VERSION 5.8 ;
BUSBITCHARS "[]" ;
DIVIDERCHAR "/" ;
UNITS
    DATABASE MICRONS 1000 ;
END UNITS

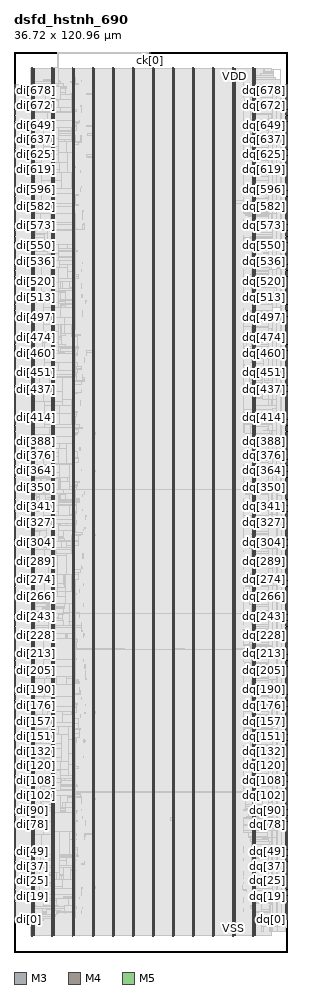
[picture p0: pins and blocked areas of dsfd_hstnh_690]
MACRO dsfd_hstnh_690
  FOREIGN dsfd_hstnh_690 0 0 ;
  CLASS BLOCK ;
  SIZE 36.72 BY 120.96 ;
  PIN ck[0]
    DIRECTION INPUT ;
    USE SIGNAL ;
    PORT
      LAYER M3 ;
        RECT  18.36 120.816 18.378 120.96 ;
    END
    PORT
      LAYER M3 ;
        RECT  18.18 120.793 18.378 120.828 ;
    END
  END ck[0]
  PIN di[0]
    DIRECTION INPUT ;
    USE SIGNAL ;
    PORT
      LAYER M4 ;
        RECT  0 4.416 0.192 4.44 ;
    END
  END di[0]
  PIN di[100]
    DIRECTION INPUT ;
    USE SIGNAL ;
    PORT
      LAYER M4 ;
        RECT  0 20.688 0.192 20.712 ;
    END
  END di[100]
  PIN di[101]
    DIRECTION INPUT ;
    USE SIGNAL ;
    PORT
      LAYER M4 ;
        RECT  0 20.832 0.192 20.856 ;
    END
  END di[101]
  PIN di[102]
    DIRECTION INPUT ;
    USE SIGNAL ;
    PORT
      LAYER M4 ;
        RECT  0 21.024 0.192 21.048 ;
    END
  END di[102]
  PIN di[103]
    DIRECTION INPUT ;
    USE SIGNAL ;
    PORT
      LAYER M4 ;
        RECT  0 21.168 0.192 21.192 ;
    END
  END di[103]
  PIN di[104]
    DIRECTION INPUT ;
    USE SIGNAL ;
    PORT
      LAYER M4 ;
        RECT  0 21.36 0.192 21.384 ;
    END
  END di[104]
  PIN di[105]
    DIRECTION INPUT ;
    USE SIGNAL ;
    PORT
      LAYER M4 ;
        RECT  0 21.504 0.192 21.528 ;
    END
  END di[105]
  PIN di[106]
    DIRECTION INPUT ;
    USE SIGNAL ;
    PORT
      LAYER M4 ;
        RECT  0 21.648 0.192 21.672 ;
    END
  END di[106]
  PIN di[107]
    DIRECTION INPUT ;
    USE SIGNAL ;
    PORT
      LAYER M4 ;
        RECT  0 21.84 0.192 21.864 ;
    END
  END di[107]
  PIN di[108]
    DIRECTION INPUT ;
    USE SIGNAL ;
    PORT
      LAYER M4 ;
        RECT  0 21.984 0.192 22.008 ;
    END
  END di[108]
  PIN di[109]
    DIRECTION INPUT ;
    USE SIGNAL ;
    PORT
      LAYER M4 ;
        RECT  0 22.176 0.192 22.2 ;
    END
  END di[109]
  PIN di[10]
    DIRECTION INPUT ;
    USE SIGNAL ;
    PORT
      LAYER M4 ;
        RECT  0 6.048 0.192 6.072 ;
    END
  END di[10]
  PIN di[110]
    DIRECTION INPUT ;
    USE SIGNAL ;
    PORT
      LAYER M4 ;
        RECT  0 22.32 0.192 22.344 ;
    END
  END di[110]
  PIN di[111]
    DIRECTION INPUT ;
    USE SIGNAL ;
    PORT
      LAYER M4 ;
        RECT  0 22.464 0.192 22.488 ;
    END
  END di[111]
  PIN di[112]
    DIRECTION INPUT ;
    USE SIGNAL ;
    PORT
      LAYER M4 ;
        RECT  0 22.656 0.192 22.68 ;
    END
  END di[112]
  PIN di[113]
    DIRECTION INPUT ;
    USE SIGNAL ;
    PORT
      LAYER M4 ;
        RECT  0 22.8 0.192 22.824 ;
    END
  END di[113]
  PIN di[114]
    DIRECTION INPUT ;
    USE SIGNAL ;
    PORT
      LAYER M4 ;
        RECT  0 22.992 0.192 23.016 ;
    END
  END di[114]
  PIN di[115]
    DIRECTION INPUT ;
    USE SIGNAL ;
    PORT
      LAYER M4 ;
        RECT  0 23.136 0.192 23.16 ;
    END
  END di[115]
  PIN di[116]
    DIRECTION INPUT ;
    USE SIGNAL ;
    PORT
      LAYER M4 ;
        RECT  0 23.28 0.192 23.304 ;
    END
  END di[116]
  PIN di[117]
    DIRECTION INPUT ;
    USE SIGNAL ;
    PORT
      LAYER M4 ;
        RECT  0 23.472 0.192 23.496 ;
    END
  END di[117]
  PIN di[118]
    DIRECTION INPUT ;
    USE SIGNAL ;
    PORT
      LAYER M4 ;
        RECT  0 23.616 0.192 23.64 ;
    END
  END di[118]
  PIN di[119]
    DIRECTION INPUT ;
    USE SIGNAL ;
    PORT
      LAYER M4 ;
        RECT  0 23.808 0.192 23.832 ;
    END
  END di[119]
  PIN di[11]
    DIRECTION INPUT ;
    USE SIGNAL ;
    PORT
      LAYER M4 ;
        RECT  0 6.192 0.192 6.216 ;
    END
  END di[11]
  PIN di[120]
    DIRECTION INPUT ;
    USE SIGNAL ;
    PORT
      LAYER M4 ;
        RECT  0 23.952 0.192 23.976 ;
    END
  END di[120]
  PIN di[121]
    DIRECTION INPUT ;
    USE SIGNAL ;
    PORT
      LAYER M4 ;
        RECT  0 24.096 0.192 24.12 ;
    END
  END di[121]
  PIN di[122]
    DIRECTION INPUT ;
    USE SIGNAL ;
    PORT
      LAYER M4 ;
        RECT  0 24.288 0.192 24.312 ;
    END
  END di[122]
  PIN di[123]
    DIRECTION INPUT ;
    USE SIGNAL ;
    PORT
      LAYER M4 ;
        RECT  0 24.432 0.192 24.456 ;
    END
  END di[123]
  PIN di[124]
    DIRECTION INPUT ;
    USE SIGNAL ;
    PORT
      LAYER M4 ;
        RECT  0 24.576 0.192 24.6 ;
    END
  END di[124]
  PIN di[125]
    DIRECTION INPUT ;
    USE SIGNAL ;
    PORT
      LAYER M4 ;
        RECT  0 24.768 0.192 24.792 ;
    END
  END di[125]
  PIN di[126]
    DIRECTION INPUT ;
    USE SIGNAL ;
    PORT
      LAYER M4 ;
        RECT  0 24.912 0.192 24.936 ;
    END
  END di[126]
  PIN di[127]
    DIRECTION INPUT ;
    USE SIGNAL ;
    PORT
      LAYER M4 ;
        RECT  0 25.104 0.192 25.128 ;
    END
  END di[127]
  PIN di[128]
    DIRECTION INPUT ;
    USE SIGNAL ;
    PORT
      LAYER M4 ;
        RECT  0 25.248 0.192 25.272 ;
    END
  END di[128]
  PIN di[129]
    DIRECTION INPUT ;
    USE SIGNAL ;
    PORT
      LAYER M4 ;
        RECT  0 25.392 0.192 25.416 ;
    END
  END di[129]
  PIN di[12]
    DIRECTION INPUT ;
    USE SIGNAL ;
    PORT
      LAYER M4 ;
        RECT  0 6.384 0.192 6.408 ;
    END
  END di[12]
  PIN di[130]
    DIRECTION INPUT ;
    USE SIGNAL ;
    PORT
      LAYER M4 ;
        RECT  0 25.584 0.192 25.608 ;
    END
  END di[130]
  PIN di[131]
    DIRECTION INPUT ;
    USE SIGNAL ;
    PORT
      LAYER M4 ;
        RECT  0 25.728 0.192 25.752 ;
    END
  END di[131]
  PIN di[132]
    DIRECTION INPUT ;
    USE SIGNAL ;
    PORT
      LAYER M4 ;
        RECT  0 25.92 0.192 25.944 ;
    END
  END di[132]
  PIN di[133]
    DIRECTION INPUT ;
    USE SIGNAL ;
    PORT
      LAYER M4 ;
        RECT  0 26.064 0.192 26.088 ;
    END
  END di[133]
  PIN di[134]
    DIRECTION INPUT ;
    USE SIGNAL ;
    PORT
      LAYER M4 ;
        RECT  0 26.208 0.192 26.232 ;
    END
  END di[134]
  PIN di[135]
    DIRECTION INPUT ;
    USE SIGNAL ;
    PORT
      LAYER M4 ;
        RECT  0 26.4 0.192 26.424 ;
    END
  END di[135]
  PIN di[136]
    DIRECTION INPUT ;
    USE SIGNAL ;
    PORT
      LAYER M4 ;
        RECT  0 26.544 0.192 26.568 ;
    END
  END di[136]
  PIN di[137]
    DIRECTION INPUT ;
    USE SIGNAL ;
    PORT
      LAYER M4 ;
        RECT  0 26.736 0.192 26.76 ;
    END
  END di[137]
  PIN di[138]
    DIRECTION INPUT ;
    USE SIGNAL ;
    PORT
      LAYER M4 ;
        RECT  0 26.88 0.192 26.904 ;
    END
  END di[138]
  PIN di[139]
    DIRECTION INPUT ;
    USE SIGNAL ;
    PORT
      LAYER M4 ;
        RECT  0 27.024 0.192 27.048 ;
    END
  END di[139]
  PIN di[13]
    DIRECTION INPUT ;
    USE SIGNAL ;
    PORT
      LAYER M4 ;
        RECT  0 6.528 0.192 6.552 ;
    END
  END di[13]
  PIN di[140]
    DIRECTION INPUT ;
    USE SIGNAL ;
    PORT
      LAYER M4 ;
        RECT  0 27.216 0.192 27.24 ;
    END
  END di[140]
  PIN di[141]
    DIRECTION INPUT ;
    USE SIGNAL ;
    PORT
      LAYER M4 ;
        RECT  0 27.36 0.192 27.384 ;
    END
  END di[141]
  PIN di[142]
    DIRECTION INPUT ;
    USE SIGNAL ;
    PORT
      LAYER M4 ;
        RECT  0 27.552 0.192 27.576 ;
    END
  END di[142]
  PIN di[143]
    DIRECTION INPUT ;
    USE SIGNAL ;
    PORT
      LAYER M4 ;
        RECT  0 27.696 0.192 27.72 ;
    END
  END di[143]
  PIN di[144]
    DIRECTION INPUT ;
    USE SIGNAL ;
    PORT
      LAYER M4 ;
        RECT  0 27.84 0.192 27.864 ;
    END
  END di[144]
  PIN di[145]
    DIRECTION INPUT ;
    USE SIGNAL ;
    PORT
      LAYER M4 ;
        RECT  0 28.032 0.192 28.056 ;
    END
  END di[145]
  PIN di[146]
    DIRECTION INPUT ;
    USE SIGNAL ;
    PORT
      LAYER M4 ;
        RECT  0 28.176 0.192 28.2 ;
    END
  END di[146]
  PIN di[147]
    DIRECTION INPUT ;
    USE SIGNAL ;
    PORT
      LAYER M4 ;
        RECT  0 28.32 0.192 28.344 ;
    END
  END di[147]
  PIN di[148]
    DIRECTION INPUT ;
    USE SIGNAL ;
    PORT
      LAYER M4 ;
        RECT  0 28.512 0.192 28.536 ;
    END
  END di[148]
  PIN di[149]
    DIRECTION INPUT ;
    USE SIGNAL ;
    PORT
      LAYER M4 ;
        RECT  0 28.656 0.192 28.68 ;
    END
  END di[149]
  PIN di[14]
    DIRECTION INPUT ;
    USE SIGNAL ;
    PORT
      LAYER M4 ;
        RECT  0 6.672 0.192 6.696 ;
    END
  END di[14]
  PIN di[150]
    DIRECTION INPUT ;
    USE SIGNAL ;
    PORT
      LAYER M4 ;
        RECT  0 28.848 0.192 28.872 ;
    END
  END di[150]
  PIN di[151]
    DIRECTION INPUT ;
    USE SIGNAL ;
    PORT
      LAYER M4 ;
        RECT  0 28.992 0.192 29.016 ;
    END
  END di[151]
  PIN di[152]
    DIRECTION INPUT ;
    USE SIGNAL ;
    PORT
      LAYER M4 ;
        RECT  0 29.136 0.192 29.16 ;
    END
  END di[152]
  PIN di[153]
    DIRECTION INPUT ;
    USE SIGNAL ;
    PORT
      LAYER M4 ;
        RECT  0 29.328 0.192 29.352 ;
    END
  END di[153]
  PIN di[154]
    DIRECTION INPUT ;
    USE SIGNAL ;
    PORT
      LAYER M4 ;
        RECT  0 29.472 0.192 29.496 ;
    END
  END di[154]
  PIN di[155]
    DIRECTION INPUT ;
    USE SIGNAL ;
    PORT
      LAYER M4 ;
        RECT  0 29.664 0.192 29.688 ;
    END
  END di[155]
  PIN di[156]
    DIRECTION INPUT ;
    USE SIGNAL ;
    PORT
      LAYER M4 ;
        RECT  0 29.808 0.192 29.832 ;
    END
  END di[156]
  PIN di[157]
    DIRECTION INPUT ;
    USE SIGNAL ;
    PORT
      LAYER M4 ;
        RECT  0 29.952 0.192 29.976 ;
    END
  END di[157]
  PIN di[158]
    DIRECTION INPUT ;
    USE SIGNAL ;
    PORT
      LAYER M4 ;
        RECT  0 30.144 0.192 30.168 ;
    END
  END di[158]
  PIN di[159]
    DIRECTION INPUT ;
    USE SIGNAL ;
    PORT
      LAYER M4 ;
        RECT  0 30.288 0.192 30.312 ;
    END
  END di[159]
  PIN di[15]
    DIRECTION INPUT ;
    USE SIGNAL ;
    PORT
      LAYER M4 ;
        RECT  0 6.864 0.192 6.888 ;
    END
  END di[15]
  PIN di[160]
    DIRECTION INPUT ;
    USE SIGNAL ;
    PORT
      LAYER M4 ;
        RECT  0 30.48 0.192 30.504 ;
    END
  END di[160]
  PIN di[161]
    DIRECTION INPUT ;
    USE SIGNAL ;
    PORT
      LAYER M4 ;
        RECT  0 30.624 0.192 30.648 ;
    END
  END di[161]
  PIN di[162]
    DIRECTION INPUT ;
    USE SIGNAL ;
    PORT
      LAYER M4 ;
        RECT  0 30.768 0.192 30.792 ;
    END
  END di[162]
  PIN di[163]
    DIRECTION INPUT ;
    USE SIGNAL ;
    PORT
      LAYER M4 ;
        RECT  0 30.96 0.192 30.984 ;
    END
  END di[163]
  PIN di[164]
    DIRECTION INPUT ;
    USE SIGNAL ;
    PORT
      LAYER M4 ;
        RECT  0 31.104 0.192 31.128 ;
    END
  END di[164]
  PIN di[165]
    DIRECTION INPUT ;
    USE SIGNAL ;
    PORT
      LAYER M4 ;
        RECT  0 31.296 0.192 31.32 ;
    END
  END di[165]
  PIN di[166]
    DIRECTION INPUT ;
    USE SIGNAL ;
    PORT
      LAYER M4 ;
        RECT  0 31.44 0.192 31.464 ;
    END
  END di[166]
  PIN di[167]
    DIRECTION INPUT ;
    USE SIGNAL ;
    PORT
      LAYER M4 ;
        RECT  0 31.584 0.192 31.608 ;
    END
  END di[167]
  PIN di[168]
    DIRECTION INPUT ;
    USE SIGNAL ;
    PORT
      LAYER M4 ;
        RECT  0 31.776 0.192 31.8 ;
    END
  END di[168]
  PIN di[169]
    DIRECTION INPUT ;
    USE SIGNAL ;
    PORT
      LAYER M4 ;
        RECT  0 31.92 0.192 31.944 ;
    END
  END di[169]
  PIN di[16]
    DIRECTION INPUT ;
    USE SIGNAL ;
    PORT
      LAYER M4 ;
        RECT  0 7.008 0.192 7.032 ;
    END
  END di[16]
  PIN di[170]
    DIRECTION INPUT ;
    USE SIGNAL ;
    PORT
      LAYER M4 ;
        RECT  0 32.064 0.192 32.088 ;
    END
  END di[170]
  PIN di[171]
    DIRECTION INPUT ;
    USE SIGNAL ;
    PORT
      LAYER M4 ;
        RECT  0 32.256 0.192 32.28 ;
    END
  END di[171]
  PIN di[172]
    DIRECTION INPUT ;
    USE SIGNAL ;
    PORT
      LAYER M4 ;
        RECT  0 32.4 0.192 32.424 ;
    END
  END di[172]
  PIN di[173]
    DIRECTION INPUT ;
    USE SIGNAL ;
    PORT
      LAYER M4 ;
        RECT  0 32.592 0.192 32.616 ;
    END
  END di[173]
  PIN di[174]
    DIRECTION INPUT ;
    USE SIGNAL ;
    PORT
      LAYER M4 ;
        RECT  0 32.736 0.192 32.76 ;
    END
  END di[174]
  PIN di[175]
    DIRECTION INPUT ;
    USE SIGNAL ;
    PORT
      LAYER M4 ;
        RECT  0 32.88 0.192 32.904 ;
    END
  END di[175]
  PIN di[176]
    DIRECTION INPUT ;
    USE SIGNAL ;
    PORT
      LAYER M4 ;
        RECT  0 33.072 0.192 33.096 ;
    END
  END di[176]
  PIN di[177]
    DIRECTION INPUT ;
    USE SIGNAL ;
    PORT
      LAYER M4 ;
        RECT  0 33.216 0.192 33.24 ;
    END
  END di[177]
  PIN di[178]
    DIRECTION INPUT ;
    USE SIGNAL ;
    PORT
      LAYER M4 ;
        RECT  0 33.408 0.192 33.432 ;
    END
  END di[178]
  PIN di[179]
    DIRECTION INPUT ;
    USE SIGNAL ;
    PORT
      LAYER M4 ;
        RECT  0 33.552 0.192 33.576 ;
    END
  END di[179]
  PIN di[17]
    DIRECTION INPUT ;
    USE SIGNAL ;
    PORT
      LAYER M4 ;
        RECT  0 7.2 0.192 7.224 ;
    END
  END di[17]
  PIN di[180]
    DIRECTION INPUT ;
    USE SIGNAL ;
    PORT
      LAYER M4 ;
        RECT  0 33.696 0.192 33.72 ;
    END
  END di[180]
  PIN di[181]
    DIRECTION INPUT ;
    USE SIGNAL ;
    PORT
      LAYER M4 ;
        RECT  0 33.888 0.192 33.912 ;
    END
  END di[181]
  PIN di[182]
    DIRECTION INPUT ;
    USE SIGNAL ;
    PORT
      LAYER M4 ;
        RECT  0 34.032 0.192 34.056 ;
    END
  END di[182]
  PIN di[183]
    DIRECTION INPUT ;
    USE SIGNAL ;
    PORT
      LAYER M4 ;
        RECT  0 34.224 0.192 34.248 ;
    END
  END di[183]
  PIN di[184]
    DIRECTION INPUT ;
    USE SIGNAL ;
    PORT
      LAYER M4 ;
        RECT  0 34.368 0.192 34.392 ;
    END
  END di[184]
  PIN di[185]
    DIRECTION INPUT ;
    USE SIGNAL ;
    PORT
      LAYER M4 ;
        RECT  0 34.512 0.192 34.536 ;
    END
  END di[185]
  PIN di[186]
    DIRECTION INPUT ;
    USE SIGNAL ;
    PORT
      LAYER M4 ;
        RECT  0 34.704 0.192 34.728 ;
    END
  END di[186]
  PIN di[187]
    DIRECTION INPUT ;
    USE SIGNAL ;
    PORT
      LAYER M4 ;
        RECT  0 34.848 0.192 34.872 ;
    END
  END di[187]
  PIN di[188]
    DIRECTION INPUT ;
    USE SIGNAL ;
    PORT
      LAYER M4 ;
        RECT  0 35.04 0.192 35.064 ;
    END
  END di[188]
  PIN di[189]
    DIRECTION INPUT ;
    USE SIGNAL ;
    PORT
      LAYER M4 ;
        RECT  0 35.184 0.192 35.208 ;
    END
  END di[189]
  PIN di[18]
    DIRECTION INPUT ;
    USE SIGNAL ;
    PORT
      LAYER M4 ;
        RECT  0 7.344 0.192 7.368 ;
    END
  END di[18]
  PIN di[190]
    DIRECTION INPUT ;
    USE SIGNAL ;
    PORT
      LAYER M4 ;
        RECT  0 35.328 0.192 35.352 ;
    END
  END di[190]
  PIN di[191]
    DIRECTION INPUT ;
    USE SIGNAL ;
    PORT
      LAYER M4 ;
        RECT  0 35.52 0.192 35.544 ;
    END
  END di[191]
  PIN di[192]
    DIRECTION INPUT ;
    USE SIGNAL ;
    PORT
      LAYER M4 ;
        RECT  0 35.664 0.192 35.688 ;
    END
  END di[192]
  PIN di[193]
    DIRECTION INPUT ;
    USE SIGNAL ;
    PORT
      LAYER M4 ;
        RECT  0 35.808 0.192 35.832 ;
    END
  END di[193]
  PIN di[194]
    DIRECTION INPUT ;
    USE SIGNAL ;
    PORT
      LAYER M4 ;
        RECT  0 36 0.192 36.024 ;
    END
  END di[194]
  PIN di[195]
    DIRECTION INPUT ;
    USE SIGNAL ;
    PORT
      LAYER M4 ;
        RECT  0 36.144 0.192 36.168 ;
    END
  END di[195]
  PIN di[196]
    DIRECTION INPUT ;
    USE SIGNAL ;
    PORT
      LAYER M4 ;
        RECT  0 36.336 0.192 36.36 ;
    END
  END di[196]
  PIN di[197]
    DIRECTION INPUT ;
    USE SIGNAL ;
    PORT
      LAYER M4 ;
        RECT  0 36.48 0.192 36.504 ;
    END
  END di[197]
  PIN di[198]
    DIRECTION INPUT ;
    USE SIGNAL ;
    PORT
      LAYER M4 ;
        RECT  0 36.624 0.192 36.648 ;
    END
  END di[198]
  PIN di[199]
    DIRECTION INPUT ;
    USE SIGNAL ;
    PORT
      LAYER M4 ;
        RECT  0 36.816 0.192 36.84 ;
    END
  END di[199]
  PIN di[19]
    DIRECTION INPUT ;
    USE SIGNAL ;
    PORT
      LAYER M4 ;
        RECT  0 7.488 0.192 7.512 ;
    END
  END di[19]
  PIN di[1]
    DIRECTION INPUT ;
    USE SIGNAL ;
    PORT
      LAYER M4 ;
        RECT  0 4.56 0.192 4.584 ;
    END
  END di[1]
  PIN di[200]
    DIRECTION INPUT ;
    USE SIGNAL ;
    PORT
      LAYER M4 ;
        RECT  0 36.96 0.192 36.984 ;
    END
  END di[200]
  PIN di[201]
    DIRECTION INPUT ;
    USE SIGNAL ;
    PORT
      LAYER M4 ;
        RECT  0 37.152 0.192 37.176 ;
    END
  END di[201]
  PIN di[202]
    DIRECTION INPUT ;
    USE SIGNAL ;
    PORT
      LAYER M4 ;
        RECT  0 37.296 0.192 37.32 ;
    END
  END di[202]
  PIN di[203]
    DIRECTION INPUT ;
    USE SIGNAL ;
    PORT
      LAYER M4 ;
        RECT  0 37.44 0.192 37.464 ;
    END
  END di[203]
  PIN di[204]
    DIRECTION INPUT ;
    USE SIGNAL ;
    PORT
      LAYER M4 ;
        RECT  0 37.632 0.192 37.656 ;
    END
  END di[204]
  PIN di[205]
    DIRECTION INPUT ;
    USE SIGNAL ;
    PORT
      LAYER M4 ;
        RECT  0 37.776 0.192 37.8 ;
    END
  END di[205]
  PIN di[206]
    DIRECTION INPUT ;
    USE SIGNAL ;
    PORT
      LAYER M4 ;
        RECT  0 37.968 0.192 37.992 ;
    END
  END di[206]
  PIN di[207]
    DIRECTION INPUT ;
    USE SIGNAL ;
    PORT
      LAYER M4 ;
        RECT  0 38.112 0.192 38.136 ;
    END
  END di[207]
  PIN di[208]
    DIRECTION INPUT ;
    USE SIGNAL ;
    PORT
      LAYER M4 ;
        RECT  0 38.256 0.192 38.28 ;
    END
  END di[208]
  PIN di[209]
    DIRECTION INPUT ;
    USE SIGNAL ;
    PORT
      LAYER M4 ;
        RECT  0 38.448 0.192 38.472 ;
    END
  END di[209]
  PIN di[20]
    DIRECTION INPUT ;
    USE SIGNAL ;
    PORT
      LAYER M4 ;
        RECT  0 7.68 0.192 7.704 ;
    END
  END di[20]
  PIN di[210]
    DIRECTION INPUT ;
    USE SIGNAL ;
    PORT
      LAYER M4 ;
        RECT  0 38.592 0.192 38.616 ;
    END
  END di[210]
  PIN di[211]
    DIRECTION INPUT ;
    USE SIGNAL ;
    PORT
      LAYER M4 ;
        RECT  0 38.784 0.192 38.808 ;
    END
  END di[211]
  PIN di[212]
    DIRECTION INPUT ;
    USE SIGNAL ;
    PORT
      LAYER M4 ;
        RECT  0 38.928 0.192 38.952 ;
    END
  END di[212]
  PIN di[213]
    DIRECTION INPUT ;
    USE SIGNAL ;
    PORT
      LAYER M4 ;
        RECT  0 39.072 0.192 39.096 ;
    END
  END di[213]
  PIN di[214]
    DIRECTION INPUT ;
    USE SIGNAL ;
    PORT
      LAYER M4 ;
        RECT  0 39.264 0.192 39.288 ;
    END
  END di[214]
  PIN di[215]
    DIRECTION INPUT ;
    USE SIGNAL ;
    PORT
      LAYER M4 ;
        RECT  0 39.408 0.192 39.432 ;
    END
  END di[215]
  PIN di[216]
    DIRECTION INPUT ;
    USE SIGNAL ;
    PORT
      LAYER M4 ;
        RECT  0 39.552 0.192 39.576 ;
    END
  END di[216]
  PIN di[217]
    DIRECTION INPUT ;
    USE SIGNAL ;
    PORT
      LAYER M4 ;
        RECT  0 39.744 0.192 39.768 ;
    END
  END di[217]
  PIN di[218]
    DIRECTION INPUT ;
    USE SIGNAL ;
    PORT
      LAYER M4 ;
        RECT  0 39.888 0.192 39.912 ;
    END
  END di[218]
  PIN di[219]
    DIRECTION INPUT ;
    USE SIGNAL ;
    PORT
      LAYER M4 ;
        RECT  0 40.08 0.192 40.104 ;
    END
  END di[219]
  PIN di[21]
    DIRECTION INPUT ;
    USE SIGNAL ;
    PORT
      LAYER M4 ;
        RECT  0 7.824 0.192 7.848 ;
    END
  END di[21]
  PIN di[220]
    DIRECTION INPUT ;
    USE SIGNAL ;
    PORT
      LAYER M4 ;
        RECT  0 40.224 0.192 40.248 ;
    END
  END di[220]
  PIN di[221]
    DIRECTION INPUT ;
    USE SIGNAL ;
    PORT
      LAYER M4 ;
        RECT  0 40.368 0.192 40.392 ;
    END
  END di[221]
  PIN di[222]
    DIRECTION INPUT ;
    USE SIGNAL ;
    PORT
      LAYER M4 ;
        RECT  0 40.56 0.192 40.584 ;
    END
  END di[222]
  PIN di[223]
    DIRECTION INPUT ;
    USE SIGNAL ;
    PORT
      LAYER M4 ;
        RECT  0 40.704 0.192 40.728 ;
    END
  END di[223]
  PIN di[224]
    DIRECTION INPUT ;
    USE SIGNAL ;
    PORT
      LAYER M4 ;
        RECT  0 40.896 0.192 40.92 ;
    END
  END di[224]
  PIN di[225]
    DIRECTION INPUT ;
    USE SIGNAL ;
    PORT
      LAYER M4 ;
        RECT  0 41.04 0.192 41.064 ;
    END
  END di[225]
  PIN di[226]
    DIRECTION INPUT ;
    USE SIGNAL ;
    PORT
      LAYER M4 ;
        RECT  0 41.184 0.192 41.208 ;
    END
  END di[226]
  PIN di[227]
    DIRECTION INPUT ;
    USE SIGNAL ;
    PORT
      LAYER M4 ;
        RECT  0 41.376 0.192 41.4 ;
    END
  END di[227]
  PIN di[228]
    DIRECTION INPUT ;
    USE SIGNAL ;
    PORT
      LAYER M4 ;
        RECT  0 41.52 0.192 41.544 ;
    END
  END di[228]
  PIN di[229]
    DIRECTION INPUT ;
    USE SIGNAL ;
    PORT
      LAYER M4 ;
        RECT  0 41.712 0.192 41.736 ;
    END
  END di[229]
  PIN di[22]
    DIRECTION INPUT ;
    USE SIGNAL ;
    PORT
      LAYER M4 ;
        RECT  0 8.016 0.192 8.04 ;
    END
  END di[22]
  PIN di[230]
    DIRECTION INPUT ;
    USE SIGNAL ;
    PORT
      LAYER M4 ;
        RECT  0 41.856 0.192 41.88 ;
    END
  END di[230]
  PIN di[231]
    DIRECTION INPUT ;
    USE SIGNAL ;
    PORT
      LAYER M4 ;
        RECT  0 42 0.192 42.024 ;
    END
  END di[231]
  PIN di[232]
    DIRECTION INPUT ;
    USE SIGNAL ;
    PORT
      LAYER M4 ;
        RECT  0 42.192 0.192 42.216 ;
    END
  END di[232]
  PIN di[233]
    DIRECTION INPUT ;
    USE SIGNAL ;
    PORT
      LAYER M4 ;
        RECT  0 42.336 0.192 42.36 ;
    END
  END di[233]
  PIN di[234]
    DIRECTION INPUT ;
    USE SIGNAL ;
    PORT
      LAYER M4 ;
        RECT  0 42.528 0.192 42.552 ;
    END
  END di[234]
  PIN di[235]
    DIRECTION INPUT ;
    USE SIGNAL ;
    PORT
      LAYER M4 ;
        RECT  0 42.672 0.192 42.696 ;
    END
  END di[235]
  PIN di[236]
    DIRECTION INPUT ;
    USE SIGNAL ;
    PORT
      LAYER M4 ;
        RECT  0 42.816 0.192 42.84 ;
    END
  END di[236]
  PIN di[237]
    DIRECTION INPUT ;
    USE SIGNAL ;
    PORT
      LAYER M4 ;
        RECT  0 43.008 0.192 43.032 ;
    END
  END di[237]
  PIN di[238]
    DIRECTION INPUT ;
    USE SIGNAL ;
    PORT
      LAYER M4 ;
        RECT  0 43.152 0.192 43.176 ;
    END
  END di[238]
  PIN di[239]
    DIRECTION INPUT ;
    USE SIGNAL ;
    PORT
      LAYER M4 ;
        RECT  0 43.296 0.192 43.32 ;
    END
  END di[239]
  PIN di[23]
    DIRECTION INPUT ;
    USE SIGNAL ;
    PORT
      LAYER M4 ;
        RECT  0 8.16 0.192 8.184 ;
    END
  END di[23]
  PIN di[240]
    DIRECTION INPUT ;
    USE SIGNAL ;
    PORT
      LAYER M4 ;
        RECT  0 43.488 0.192 43.512 ;
    END
  END di[240]
  PIN di[241]
    DIRECTION INPUT ;
    USE SIGNAL ;
    PORT
      LAYER M4 ;
        RECT  0 43.632 0.192 43.656 ;
    END
  END di[241]
  PIN di[242]
    DIRECTION INPUT ;
    USE SIGNAL ;
    PORT
      LAYER M4 ;
        RECT  0 43.824 0.192 43.848 ;
    END
  END di[242]
  PIN di[243]
    DIRECTION INPUT ;
    USE SIGNAL ;
    PORT
      LAYER M4 ;
        RECT  0 43.968 0.192 43.992 ;
    END
  END di[243]
  PIN di[244]
    DIRECTION INPUT ;
    USE SIGNAL ;
    PORT
      LAYER M4 ;
        RECT  0 44.112 0.192 44.136 ;
    END
  END di[244]
  PIN di[245]
    DIRECTION INPUT ;
    USE SIGNAL ;
    PORT
      LAYER M4 ;
        RECT  0 44.304 0.192 44.328 ;
    END
  END di[245]
  PIN di[246]
    DIRECTION INPUT ;
    USE SIGNAL ;
    PORT
      LAYER M4 ;
        RECT  0 44.448 0.192 44.472 ;
    END
  END di[246]
  PIN di[247]
    DIRECTION INPUT ;
    USE SIGNAL ;
    PORT
      LAYER M4 ;
        RECT  0 44.64 0.192 44.664 ;
    END
  END di[247]
  PIN di[248]
    DIRECTION INPUT ;
    USE SIGNAL ;
    PORT
      LAYER M4 ;
        RECT  0 44.784 0.192 44.808 ;
    END
  END di[248]
  PIN di[249]
    DIRECTION INPUT ;
    USE SIGNAL ;
    PORT
      LAYER M4 ;
        RECT  0 44.928 0.192 44.952 ;
    END
  END di[249]
  PIN di[24]
    DIRECTION INPUT ;
    USE SIGNAL ;
    PORT
      LAYER M4 ;
        RECT  0 8.304 0.192 8.328 ;
    END
  END di[24]
  PIN di[250]
    DIRECTION INPUT ;
    USE SIGNAL ;
    PORT
      LAYER M4 ;
        RECT  0 45.12 0.192 45.144 ;
    END
  END di[250]
  PIN di[251]
    DIRECTION INPUT ;
    USE SIGNAL ;
    PORT
      LAYER M4 ;
        RECT  0 45.264 0.192 45.288 ;
    END
  END di[251]
  PIN di[252]
    DIRECTION INPUT ;
    USE SIGNAL ;
    PORT
      LAYER M4 ;
        RECT  0 45.456 0.192 45.48 ;
    END
  END di[252]
  PIN di[253]
    DIRECTION INPUT ;
    USE SIGNAL ;
    PORT
      LAYER M4 ;
        RECT  0 45.6 0.192 45.624 ;
    END
  END di[253]
  PIN di[254]
    DIRECTION INPUT ;
    USE SIGNAL ;
    PORT
      LAYER M4 ;
        RECT  0 45.744 0.192 45.768 ;
    END
  END di[254]
  PIN di[255]
    DIRECTION INPUT ;
    USE SIGNAL ;
    PORT
      LAYER M4 ;
        RECT  0 45.936 0.192 45.96 ;
    END
  END di[255]
  PIN di[256]
    DIRECTION INPUT ;
    USE SIGNAL ;
    PORT
      LAYER M4 ;
        RECT  0 46.08 0.192 46.104 ;
    END
  END di[256]
  PIN di[257]
    DIRECTION INPUT ;
    USE SIGNAL ;
    PORT
      LAYER M4 ;
        RECT  0 46.272 0.192 46.296 ;
    END
  END di[257]
  PIN di[258]
    DIRECTION INPUT ;
    USE SIGNAL ;
    PORT
      LAYER M4 ;
        RECT  0 46.416 0.192 46.44 ;
    END
  END di[258]
  PIN di[259]
    DIRECTION INPUT ;
    USE SIGNAL ;
    PORT
      LAYER M4 ;
        RECT  0 46.56 0.192 46.584 ;
    END
  END di[259]
  PIN di[25]
    DIRECTION INPUT ;
    USE SIGNAL ;
    PORT
      LAYER M4 ;
        RECT  0 8.496 0.192 8.52 ;
    END
  END di[25]
  PIN di[260]
    DIRECTION INPUT ;
    USE SIGNAL ;
    PORT
      LAYER M4 ;
        RECT  0 46.752 0.192 46.776 ;
    END
  END di[260]
  PIN di[261]
    DIRECTION INPUT ;
    USE SIGNAL ;
    PORT
      LAYER M4 ;
        RECT  0 46.896 0.192 46.92 ;
    END
  END di[261]
  PIN di[262]
    DIRECTION INPUT ;
    USE SIGNAL ;
    PORT
      LAYER M4 ;
        RECT  0 47.04 0.192 47.064 ;
    END
  END di[262]
  PIN di[263]
    DIRECTION INPUT ;
    USE SIGNAL ;
    PORT
      LAYER M4 ;
        RECT  0 47.232 0.192 47.256 ;
    END
  END di[263]
  PIN di[264]
    DIRECTION INPUT ;
    USE SIGNAL ;
    PORT
      LAYER M4 ;
        RECT  0 47.376 0.192 47.4 ;
    END
  END di[264]
  PIN di[265]
    DIRECTION INPUT ;
    USE SIGNAL ;
    PORT
      LAYER M4 ;
        RECT  0 47.568 0.192 47.592 ;
    END
  END di[265]
  PIN di[266]
    DIRECTION INPUT ;
    USE SIGNAL ;
    PORT
      LAYER M4 ;
        RECT  0 47.712 0.192 47.736 ;
    END
  END di[266]
  PIN di[267]
    DIRECTION INPUT ;
    USE SIGNAL ;
    PORT
      LAYER M4 ;
        RECT  0 47.856 0.192 47.88 ;
    END
  END di[267]
  PIN di[268]
    DIRECTION INPUT ;
    USE SIGNAL ;
    PORT
      LAYER M4 ;
        RECT  0 48.048 0.192 48.072 ;
    END
  END di[268]
  PIN di[269]
    DIRECTION INPUT ;
    USE SIGNAL ;
    PORT
      LAYER M4 ;
        RECT  0 48.192 0.192 48.216 ;
    END
  END di[269]
  PIN di[26]
    DIRECTION INPUT ;
    USE SIGNAL ;
    PORT
      LAYER M4 ;
        RECT  0 8.64 0.192 8.664 ;
    END
  END di[26]
  PIN di[270]
    DIRECTION INPUT ;
    USE SIGNAL ;
    PORT
      LAYER M4 ;
        RECT  0 48.384 0.192 48.408 ;
    END
  END di[270]
  PIN di[271]
    DIRECTION INPUT ;
    USE SIGNAL ;
    PORT
      LAYER M4 ;
        RECT  0 48.528 0.192 48.552 ;
    END
  END di[271]
  PIN di[272]
    DIRECTION INPUT ;
    USE SIGNAL ;
    PORT
      LAYER M4 ;
        RECT  0 48.672 0.192 48.696 ;
    END
  END di[272]
  PIN di[273]
    DIRECTION INPUT ;
    USE SIGNAL ;
    PORT
      LAYER M4 ;
        RECT  0 48.864 0.192 48.888 ;
    END
  END di[273]
  PIN di[274]
    DIRECTION INPUT ;
    USE SIGNAL ;
    PORT
      LAYER M4 ;
        RECT  0 49.008 0.192 49.032 ;
    END
  END di[274]
  PIN di[275]
    DIRECTION INPUT ;
    USE SIGNAL ;
    PORT
      LAYER M4 ;
        RECT  0 49.2 0.192 49.224 ;
    END
  END di[275]
  PIN di[276]
    DIRECTION INPUT ;
    USE SIGNAL ;
    PORT
      LAYER M4 ;
        RECT  0 49.344 0.192 49.368 ;
    END
  END di[276]
  PIN di[277]
    DIRECTION INPUT ;
    USE SIGNAL ;
    PORT
      LAYER M4 ;
        RECT  0 49.488 0.192 49.512 ;
    END
  END di[277]
  PIN di[278]
    DIRECTION INPUT ;
    USE SIGNAL ;
    PORT
      LAYER M4 ;
        RECT  0 49.68 0.192 49.704 ;
    END
  END di[278]
  PIN di[279]
    DIRECTION INPUT ;
    USE SIGNAL ;
    PORT
      LAYER M4 ;
        RECT  0 49.824 0.192 49.848 ;
    END
  END di[279]
  PIN di[27]
    DIRECTION INPUT ;
    USE SIGNAL ;
    PORT
      LAYER M4 ;
        RECT  0 8.832 0.192 8.856 ;
    END
  END di[27]
  PIN di[280]
    DIRECTION INPUT ;
    USE SIGNAL ;
    PORT
      LAYER M4 ;
        RECT  0 50.016 0.192 50.04 ;
    END
  END di[280]
  PIN di[281]
    DIRECTION INPUT ;
    USE SIGNAL ;
    PORT
      LAYER M4 ;
        RECT  0 50.16 0.192 50.184 ;
    END
  END di[281]
  PIN di[282]
    DIRECTION INPUT ;
    USE SIGNAL ;
    PORT
      LAYER M4 ;
        RECT  0 50.304 0.192 50.328 ;
    END
  END di[282]
  PIN di[283]
    DIRECTION INPUT ;
    USE SIGNAL ;
    PORT
      LAYER M4 ;
        RECT  0 50.496 0.192 50.52 ;
    END
  END di[283]
  PIN di[284]
    DIRECTION INPUT ;
    USE SIGNAL ;
    PORT
      LAYER M4 ;
        RECT  0 50.64 0.192 50.664 ;
    END
  END di[284]
  PIN di[285]
    DIRECTION INPUT ;
    USE SIGNAL ;
    PORT
      LAYER M4 ;
        RECT  0 50.784 0.192 50.808 ;
    END
  END di[285]
  PIN di[286]
    DIRECTION INPUT ;
    USE SIGNAL ;
    PORT
      LAYER M4 ;
        RECT  0 50.976 0.192 51 ;
    END
  END di[286]
  PIN di[287]
    DIRECTION INPUT ;
    USE SIGNAL ;
    PORT
      LAYER M4 ;
        RECT  0 51.12 0.192 51.144 ;
    END
  END di[287]
  PIN di[288]
    DIRECTION INPUT ;
    USE SIGNAL ;
    PORT
      LAYER M4 ;
        RECT  0 51.312 0.192 51.336 ;
    END
  END di[288]
  PIN di[289]
    DIRECTION INPUT ;
    USE SIGNAL ;
    PORT
      LAYER M4 ;
        RECT  0 51.456 0.192 51.48 ;
    END
  END di[289]
  PIN di[28]
    DIRECTION INPUT ;
    USE SIGNAL ;
    PORT
      LAYER M4 ;
        RECT  0 8.976 0.192 9 ;
    END
  END di[28]
  PIN di[290]
    DIRECTION INPUT ;
    USE SIGNAL ;
    PORT
      LAYER M4 ;
        RECT  0 51.6 0.192 51.624 ;
    END
  END di[290]
  PIN di[291]
    DIRECTION INPUT ;
    USE SIGNAL ;
    PORT
      LAYER M4 ;
        RECT  0 51.792 0.192 51.816 ;
    END
  END di[291]
  PIN di[292]
    DIRECTION INPUT ;
    USE SIGNAL ;
    PORT
      LAYER M4 ;
        RECT  0 51.936 0.192 51.96 ;
    END
  END di[292]
  PIN di[293]
    DIRECTION INPUT ;
    USE SIGNAL ;
    PORT
      LAYER M4 ;
        RECT  0 52.128 0.192 52.152 ;
    END
  END di[293]
  PIN di[294]
    DIRECTION INPUT ;
    USE SIGNAL ;
    PORT
      LAYER M4 ;
        RECT  0 52.272 0.192 52.296 ;
    END
  END di[294]
  PIN di[295]
    DIRECTION INPUT ;
    USE SIGNAL ;
    PORT
      LAYER M4 ;
        RECT  0 52.416 0.192 52.44 ;
    END
  END di[295]
  PIN di[296]
    DIRECTION INPUT ;
    USE SIGNAL ;
    PORT
      LAYER M4 ;
        RECT  0 52.608 0.192 52.632 ;
    END
  END di[296]
  PIN di[297]
    DIRECTION INPUT ;
    USE SIGNAL ;
    PORT
      LAYER M4 ;
        RECT  0 52.752 0.192 52.776 ;
    END
  END di[297]
  PIN di[298]
    DIRECTION INPUT ;
    USE SIGNAL ;
    PORT
      LAYER M4 ;
        RECT  0 52.944 0.192 52.968 ;
    END
  END di[298]
  PIN di[299]
    DIRECTION INPUT ;
    USE SIGNAL ;
    PORT
      LAYER M4 ;
        RECT  0 53.088 0.192 53.112 ;
    END
  END di[299]
  PIN di[29]
    DIRECTION INPUT ;
    USE SIGNAL ;
    PORT
      LAYER M4 ;
        RECT  0 9.12 0.192 9.144 ;
    END
  END di[29]
  PIN di[2]
    DIRECTION INPUT ;
    USE SIGNAL ;
    PORT
      LAYER M4 ;
        RECT  0 4.752 0.192 4.776 ;
    END
  END di[2]
  PIN di[300]
    DIRECTION INPUT ;
    USE SIGNAL ;
    PORT
      LAYER M4 ;
        RECT  0 53.232 0.192 53.256 ;
    END
  END di[300]
  PIN di[301]
    DIRECTION INPUT ;
    USE SIGNAL ;
    PORT
      LAYER M4 ;
        RECT  0 53.424 0.192 53.448 ;
    END
  END di[301]
  PIN di[302]
    DIRECTION INPUT ;
    USE SIGNAL ;
    PORT
      LAYER M4 ;
        RECT  0 53.568 0.192 53.592 ;
    END
  END di[302]
  PIN di[303]
    DIRECTION INPUT ;
    USE SIGNAL ;
    PORT
      LAYER M4 ;
        RECT  0 53.76 0.192 53.784 ;
    END
  END di[303]
  PIN di[304]
    DIRECTION INPUT ;
    USE SIGNAL ;
    PORT
      LAYER M4 ;
        RECT  0 53.904 0.192 53.928 ;
    END
  END di[304]
  PIN di[305]
    DIRECTION INPUT ;
    USE SIGNAL ;
    PORT
      LAYER M4 ;
        RECT  0 54.048 0.192 54.072 ;
    END
  END di[305]
  PIN di[306]
    DIRECTION INPUT ;
    USE SIGNAL ;
    PORT
      LAYER M4 ;
        RECT  0 54.24 0.192 54.264 ;
    END
  END di[306]
  PIN di[307]
    DIRECTION INPUT ;
    USE SIGNAL ;
    PORT
      LAYER M4 ;
        RECT  0 54.384 0.192 54.408 ;
    END
  END di[307]
  PIN di[308]
    DIRECTION INPUT ;
    USE SIGNAL ;
    PORT
      LAYER M4 ;
        RECT  0 54.528 0.192 54.552 ;
    END
  END di[308]
  PIN di[309]
    DIRECTION INPUT ;
    USE SIGNAL ;
    PORT
      LAYER M4 ;
        RECT  0 54.72 0.192 54.744 ;
    END
  END di[309]
  PIN di[30]
    DIRECTION INPUT ;
    USE SIGNAL ;
    PORT
      LAYER M4 ;
        RECT  0 9.312 0.192 9.336 ;
    END
  END di[30]
  PIN di[310]
    DIRECTION INPUT ;
    USE SIGNAL ;
    PORT
      LAYER M4 ;
        RECT  0 54.864 0.192 54.888 ;
    END
  END di[310]
  PIN di[311]
    DIRECTION INPUT ;
    USE SIGNAL ;
    PORT
      LAYER M4 ;
        RECT  0 55.056 0.192 55.08 ;
    END
  END di[311]
  PIN di[312]
    DIRECTION INPUT ;
    USE SIGNAL ;
    PORT
      LAYER M4 ;
        RECT  0 55.2 0.192 55.224 ;
    END
  END di[312]
  PIN di[313]
    DIRECTION INPUT ;
    USE SIGNAL ;
    PORT
      LAYER M4 ;
        RECT  0 55.344 0.192 55.368 ;
    END
  END di[313]
  PIN di[314]
    DIRECTION INPUT ;
    USE SIGNAL ;
    PORT
      LAYER M4 ;
        RECT  0 55.536 0.192 55.56 ;
    END
  END di[314]
  PIN di[315]
    DIRECTION INPUT ;
    USE SIGNAL ;
    PORT
      LAYER M4 ;
        RECT  0 55.68 0.192 55.704 ;
    END
  END di[315]
  PIN di[316]
    DIRECTION INPUT ;
    USE SIGNAL ;
    PORT
      LAYER M4 ;
        RECT  0 55.872 0.192 55.896 ;
    END
  END di[316]
  PIN di[317]
    DIRECTION INPUT ;
    USE SIGNAL ;
    PORT
      LAYER M4 ;
        RECT  0 56.016 0.192 56.04 ;
    END
  END di[317]
  PIN di[318]
    DIRECTION INPUT ;
    USE SIGNAL ;
    PORT
      LAYER M4 ;
        RECT  0 56.16 0.192 56.184 ;
    END
  END di[318]
  PIN di[319]
    DIRECTION INPUT ;
    USE SIGNAL ;
    PORT
      LAYER M4 ;
        RECT  0 56.352 0.192 56.376 ;
    END
  END di[319]
  PIN di[31]
    DIRECTION INPUT ;
    USE SIGNAL ;
    PORT
      LAYER M4 ;
        RECT  0 9.456 0.192 9.48 ;
    END
  END di[31]
  PIN di[320]
    DIRECTION INPUT ;
    USE SIGNAL ;
    PORT
      LAYER M4 ;
        RECT  0 56.496 0.192 56.52 ;
    END
  END di[320]
  PIN di[321]
    DIRECTION INPUT ;
    USE SIGNAL ;
    PORT
      LAYER M4 ;
        RECT  0 56.688 0.192 56.712 ;
    END
  END di[321]
  PIN di[322]
    DIRECTION INPUT ;
    USE SIGNAL ;
    PORT
      LAYER M4 ;
        RECT  0 56.832 0.192 56.856 ;
    END
  END di[322]
  PIN di[323]
    DIRECTION INPUT ;
    USE SIGNAL ;
    PORT
      LAYER M4 ;
        RECT  0 56.976 0.192 57 ;
    END
  END di[323]
  PIN di[324]
    DIRECTION INPUT ;
    USE SIGNAL ;
    PORT
      LAYER M4 ;
        RECT  0 57.168 0.192 57.192 ;
    END
  END di[324]
  PIN di[325]
    DIRECTION INPUT ;
    USE SIGNAL ;
    PORT
      LAYER M4 ;
        RECT  0 57.312 0.192 57.336 ;
    END
  END di[325]
  PIN di[326]
    DIRECTION INPUT ;
    USE SIGNAL ;
    PORT
      LAYER M4 ;
        RECT  0 57.504 0.192 57.528 ;
    END
  END di[326]
  PIN di[327]
    DIRECTION INPUT ;
    USE SIGNAL ;
    PORT
      LAYER M4 ;
        RECT  0 57.648 0.192 57.672 ;
    END
  END di[327]
  PIN di[328]
    DIRECTION INPUT ;
    USE SIGNAL ;
    PORT
      LAYER M4 ;
        RECT  0 57.792 0.192 57.816 ;
    END
  END di[328]
  PIN di[329]
    DIRECTION INPUT ;
    USE SIGNAL ;
    PORT
      LAYER M4 ;
        RECT  0 57.984 0.192 58.008 ;
    END
  END di[329]
  PIN di[32]
    DIRECTION INPUT ;
    USE SIGNAL ;
    PORT
      LAYER M4 ;
        RECT  0 9.6 0.192 9.624 ;
    END
  END di[32]
  PIN di[330]
    DIRECTION INPUT ;
    USE SIGNAL ;
    PORT
      LAYER M4 ;
        RECT  0 58.128 0.192 58.152 ;
    END
  END di[330]
  PIN di[331]
    DIRECTION INPUT ;
    USE SIGNAL ;
    PORT
      LAYER M4 ;
        RECT  0 58.272 0.192 58.296 ;
    END
  END di[331]
  PIN di[332]
    DIRECTION INPUT ;
    USE SIGNAL ;
    PORT
      LAYER M4 ;
        RECT  0 58.464 0.192 58.488 ;
    END
  END di[332]
  PIN di[333]
    DIRECTION INPUT ;
    USE SIGNAL ;
    PORT
      LAYER M4 ;
        RECT  0 58.608 0.192 58.632 ;
    END
  END di[333]
  PIN di[334]
    DIRECTION INPUT ;
    USE SIGNAL ;
    PORT
      LAYER M4 ;
        RECT  0 58.8 0.192 58.824 ;
    END
  END di[334]
  PIN di[335]
    DIRECTION INPUT ;
    USE SIGNAL ;
    PORT
      LAYER M4 ;
        RECT  0 58.944 0.192 58.968 ;
    END
  END di[335]
  PIN di[336]
    DIRECTION INPUT ;
    USE SIGNAL ;
    PORT
      LAYER M4 ;
        RECT  0 59.088 0.192 59.112 ;
    END
  END di[336]
  PIN di[337]
    DIRECTION INPUT ;
    USE SIGNAL ;
    PORT
      LAYER M4 ;
        RECT  0 59.28 0.192 59.304 ;
    END
  END di[337]
  PIN di[338]
    DIRECTION INPUT ;
    USE SIGNAL ;
    PORT
      LAYER M4 ;
        RECT  0 59.424 0.192 59.448 ;
    END
  END di[338]
  PIN di[339]
    DIRECTION INPUT ;
    USE SIGNAL ;
    PORT
      LAYER M4 ;
        RECT  0 59.616 0.192 59.64 ;
    END
  END di[339]
  PIN di[33]
    DIRECTION INPUT ;
    USE SIGNAL ;
    PORT
      LAYER M4 ;
        RECT  0 9.792 0.192 9.816 ;
    END
  END di[33]
  PIN di[340]
    DIRECTION INPUT ;
    USE SIGNAL ;
    PORT
      LAYER M4 ;
        RECT  0 59.76 0.192 59.784 ;
    END
  END di[340]
  PIN di[341]
    DIRECTION INPUT ;
    USE SIGNAL ;
    PORT
      LAYER M4 ;
        RECT  0 59.904 0.192 59.928 ;
    END
  END di[341]
  PIN di[342]
    DIRECTION INPUT ;
    USE SIGNAL ;
    PORT
      LAYER M4 ;
        RECT  0 60.096 0.192 60.12 ;
    END
  END di[342]
  PIN di[343]
    DIRECTION INPUT ;
    USE SIGNAL ;
    PORT
      LAYER M4 ;
        RECT  0 60.24 0.192 60.264 ;
    END
  END di[343]
  PIN di[344]
    DIRECTION INPUT ;
    USE SIGNAL ;
    PORT
      LAYER M4 ;
        RECT  0 60.432 0.192 60.456 ;
    END
  END di[344]
  PIN di[345]
    DIRECTION INPUT ;
    USE SIGNAL ;
    PORT
      LAYER M4 ;
        RECT  0 60.576 0.192 60.6 ;
    END
  END di[345]
  PIN di[346]
    DIRECTION INPUT ;
    USE SIGNAL ;
    PORT
      LAYER M4 ;
        RECT  0 60.72 0.192 60.744 ;
    END
  END di[346]
  PIN di[347]
    DIRECTION INPUT ;
    USE SIGNAL ;
    PORT
      LAYER M4 ;
        RECT  0 60.912 0.192 60.936 ;
    END
  END di[347]
  PIN di[348]
    DIRECTION INPUT ;
    USE SIGNAL ;
    PORT
      LAYER M4 ;
        RECT  0 61.056 0.192 61.08 ;
    END
  END di[348]
  PIN di[349]
    DIRECTION INPUT ;
    USE SIGNAL ;
    PORT
      LAYER M4 ;
        RECT  0 61.248 0.192 61.272 ;
    END
  END di[349]
  PIN di[34]
    DIRECTION INPUT ;
    USE SIGNAL ;
    PORT
      LAYER M4 ;
        RECT  0 9.936 0.192 9.96 ;
    END
  END di[34]
  PIN di[350]
    DIRECTION INPUT ;
    USE SIGNAL ;
    PORT
      LAYER M4 ;
        RECT  0 61.392 0.192 61.416 ;
    END
  END di[350]
  PIN di[351]
    DIRECTION INPUT ;
    USE SIGNAL ;
    PORT
      LAYER M4 ;
        RECT  0 61.536 0.192 61.56 ;
    END
  END di[351]
  PIN di[352]
    DIRECTION INPUT ;
    USE SIGNAL ;
    PORT
      LAYER M4 ;
        RECT  0 61.728 0.192 61.752 ;
    END
  END di[352]
  PIN di[353]
    DIRECTION INPUT ;
    USE SIGNAL ;
    PORT
      LAYER M4 ;
        RECT  0 61.872 0.192 61.896 ;
    END
  END di[353]
  PIN di[354]
    DIRECTION INPUT ;
    USE SIGNAL ;
    PORT
      LAYER M4 ;
        RECT  0 62.016 0.192 62.04 ;
    END
  END di[354]
  PIN di[355]
    DIRECTION INPUT ;
    USE SIGNAL ;
    PORT
      LAYER M4 ;
        RECT  0 62.208 0.192 62.232 ;
    END
  END di[355]
  PIN di[356]
    DIRECTION INPUT ;
    USE SIGNAL ;
    PORT
      LAYER M4 ;
        RECT  0 62.352 0.192 62.376 ;
    END
  END di[356]
  PIN di[357]
    DIRECTION INPUT ;
    USE SIGNAL ;
    PORT
      LAYER M4 ;
        RECT  0 62.544 0.192 62.568 ;
    END
  END di[357]
  PIN di[358]
    DIRECTION INPUT ;
    USE SIGNAL ;
    PORT
      LAYER M4 ;
        RECT  0 62.688 0.192 62.712 ;
    END
  END di[358]
  PIN di[359]
    DIRECTION INPUT ;
    USE SIGNAL ;
    PORT
      LAYER M4 ;
        RECT  0 62.832 0.192 62.856 ;
    END
  END di[359]
  PIN di[35]
    DIRECTION INPUT ;
    USE SIGNAL ;
    PORT
      LAYER M4 ;
        RECT  0 10.128 0.192 10.152 ;
    END
  END di[35]
  PIN di[360]
    DIRECTION INPUT ;
    USE SIGNAL ;
    PORT
      LAYER M4 ;
        RECT  0 63.024 0.192 63.048 ;
    END
  END di[360]
  PIN di[361]
    DIRECTION INPUT ;
    USE SIGNAL ;
    PORT
      LAYER M4 ;
        RECT  0 63.168 0.192 63.192 ;
    END
  END di[361]
  PIN di[362]
    DIRECTION INPUT ;
    USE SIGNAL ;
    PORT
      LAYER M4 ;
        RECT  0 63.36 0.192 63.384 ;
    END
  END di[362]
  PIN di[363]
    DIRECTION INPUT ;
    USE SIGNAL ;
    PORT
      LAYER M4 ;
        RECT  0 63.504 0.192 63.528 ;
    END
  END di[363]
  PIN di[364]
    DIRECTION INPUT ;
    USE SIGNAL ;
    PORT
      LAYER M4 ;
        RECT  0 63.648 0.192 63.672 ;
    END
  END di[364]
  PIN di[365]
    DIRECTION INPUT ;
    USE SIGNAL ;
    PORT
      LAYER M4 ;
        RECT  0 63.84 0.192 63.864 ;
    END
  END di[365]
  PIN di[366]
    DIRECTION INPUT ;
    USE SIGNAL ;
    PORT
      LAYER M4 ;
        RECT  0 63.984 0.192 64.008 ;
    END
  END di[366]
  PIN di[367]
    DIRECTION INPUT ;
    USE SIGNAL ;
    PORT
      LAYER M4 ;
        RECT  0 64.176 0.192 64.2 ;
    END
  END di[367]
  PIN di[368]
    DIRECTION INPUT ;
    USE SIGNAL ;
    PORT
      LAYER M4 ;
        RECT  0 64.32 0.192 64.344 ;
    END
  END di[368]
  PIN di[369]
    DIRECTION INPUT ;
    USE SIGNAL ;
    PORT
      LAYER M4 ;
        RECT  0 64.464 0.192 64.488 ;
    END
  END di[369]
  PIN di[36]
    DIRECTION INPUT ;
    USE SIGNAL ;
    PORT
      LAYER M4 ;
        RECT  0 10.272 0.192 10.296 ;
    END
  END di[36]
  PIN di[370]
    DIRECTION INPUT ;
    USE SIGNAL ;
    PORT
      LAYER M4 ;
        RECT  0 64.656 0.192 64.68 ;
    END
  END di[370]
  PIN di[371]
    DIRECTION INPUT ;
    USE SIGNAL ;
    PORT
      LAYER M4 ;
        RECT  0 64.8 0.192 64.824 ;
    END
  END di[371]
  PIN di[372]
    DIRECTION INPUT ;
    USE SIGNAL ;
    PORT
      LAYER M4 ;
        RECT  0 64.992 0.192 65.016 ;
    END
  END di[372]
  PIN di[373]
    DIRECTION INPUT ;
    USE SIGNAL ;
    PORT
      LAYER M4 ;
        RECT  0 65.136 0.192 65.16 ;
    END
  END di[373]
  PIN di[374]
    DIRECTION INPUT ;
    USE SIGNAL ;
    PORT
      LAYER M4 ;
        RECT  0 65.28 0.192 65.304 ;
    END
  END di[374]
  PIN di[375]
    DIRECTION INPUT ;
    USE SIGNAL ;
    PORT
      LAYER M4 ;
        RECT  0 65.472 0.192 65.496 ;
    END
  END di[375]
  PIN di[376]
    DIRECTION INPUT ;
    USE SIGNAL ;
    PORT
      LAYER M4 ;
        RECT  0 65.616 0.192 65.64 ;
    END
  END di[376]
  PIN di[377]
    DIRECTION INPUT ;
    USE SIGNAL ;
    PORT
      LAYER M4 ;
        RECT  0 65.76 0.192 65.784 ;
    END
  END di[377]
  PIN di[378]
    DIRECTION INPUT ;
    USE SIGNAL ;
    PORT
      LAYER M4 ;
        RECT  0 65.952 0.192 65.976 ;
    END
  END di[378]
  PIN di[379]
    DIRECTION INPUT ;
    USE SIGNAL ;
    PORT
      LAYER M4 ;
        RECT  0 66.096 0.192 66.12 ;
    END
  END di[379]
  PIN di[37]
    DIRECTION INPUT ;
    USE SIGNAL ;
    PORT
      LAYER M4 ;
        RECT  0 10.416 0.192 10.44 ;
    END
  END di[37]
  PIN di[380]
    DIRECTION INPUT ;
    USE SIGNAL ;
    PORT
      LAYER M4 ;
        RECT  0 66.288 0.192 66.312 ;
    END
  END di[380]
  PIN di[381]
    DIRECTION INPUT ;
    USE SIGNAL ;
    PORT
      LAYER M4 ;
        RECT  0 66.432 0.192 66.456 ;
    END
  END di[381]
  PIN di[382]
    DIRECTION INPUT ;
    USE SIGNAL ;
    PORT
      LAYER M4 ;
        RECT  0 66.576 0.192 66.6 ;
    END
  END di[382]
  PIN di[383]
    DIRECTION INPUT ;
    USE SIGNAL ;
    PORT
      LAYER M4 ;
        RECT  0 66.768 0.192 66.792 ;
    END
  END di[383]
  PIN di[384]
    DIRECTION INPUT ;
    USE SIGNAL ;
    PORT
      LAYER M4 ;
        RECT  0 66.912 0.192 66.936 ;
    END
  END di[384]
  PIN di[385]
    DIRECTION INPUT ;
    USE SIGNAL ;
    PORT
      LAYER M4 ;
        RECT  0 67.104 0.192 67.128 ;
    END
  END di[385]
  PIN di[386]
    DIRECTION INPUT ;
    USE SIGNAL ;
    PORT
      LAYER M4 ;
        RECT  0 67.248 0.192 67.272 ;
    END
  END di[386]
  PIN di[387]
    DIRECTION INPUT ;
    USE SIGNAL ;
    PORT
      LAYER M4 ;
        RECT  0 67.392 0.192 67.416 ;
    END
  END di[387]
  PIN di[388]
    DIRECTION INPUT ;
    USE SIGNAL ;
    PORT
      LAYER M4 ;
        RECT  0 67.584 0.192 67.608 ;
    END
  END di[388]
  PIN di[389]
    DIRECTION INPUT ;
    USE SIGNAL ;
    PORT
      LAYER M4 ;
        RECT  0 67.728 0.192 67.752 ;
    END
  END di[389]
  PIN di[38]
    DIRECTION INPUT ;
    USE SIGNAL ;
    PORT
      LAYER M4 ;
        RECT  0 10.608 0.192 10.632 ;
    END
  END di[38]
  PIN di[390]
    DIRECTION INPUT ;
    USE SIGNAL ;
    PORT
      LAYER M4 ;
        RECT  0 67.92 0.192 67.944 ;
    END
  END di[390]
  PIN di[391]
    DIRECTION INPUT ;
    USE SIGNAL ;
    PORT
      LAYER M4 ;
        RECT  0 68.064 0.192 68.088 ;
    END
  END di[391]
  PIN di[392]
    DIRECTION INPUT ;
    USE SIGNAL ;
    PORT
      LAYER M4 ;
        RECT  0 68.208 0.192 68.232 ;
    END
  END di[392]
  PIN di[393]
    DIRECTION INPUT ;
    USE SIGNAL ;
    PORT
      LAYER M4 ;
        RECT  0 68.4 0.192 68.424 ;
    END
  END di[393]
  PIN di[394]
    DIRECTION INPUT ;
    USE SIGNAL ;
    PORT
      LAYER M4 ;
        RECT  0 68.544 0.192 68.568 ;
    END
  END di[394]
  PIN di[395]
    DIRECTION INPUT ;
    USE SIGNAL ;
    PORT
      LAYER M4 ;
        RECT  0 68.736 0.192 68.76 ;
    END
  END di[395]
  PIN di[396]
    DIRECTION INPUT ;
    USE SIGNAL ;
    PORT
      LAYER M4 ;
        RECT  0 68.88 0.192 68.904 ;
    END
  END di[396]
  PIN di[397]
    DIRECTION INPUT ;
    USE SIGNAL ;
    PORT
      LAYER M4 ;
        RECT  0 69.024 0.192 69.048 ;
    END
  END di[397]
  PIN di[398]
    DIRECTION INPUT ;
    USE SIGNAL ;
    PORT
      LAYER M4 ;
        RECT  0 69.216 0.192 69.24 ;
    END
  END di[398]
  PIN di[399]
    DIRECTION INPUT ;
    USE SIGNAL ;
    PORT
      LAYER M4 ;
        RECT  0 69.36 0.192 69.384 ;
    END
  END di[399]
  PIN di[39]
    DIRECTION INPUT ;
    USE SIGNAL ;
    PORT
      LAYER M4 ;
        RECT  0 10.752 0.192 10.776 ;
    END
  END di[39]
  PIN di[3]
    DIRECTION INPUT ;
    USE SIGNAL ;
    PORT
      LAYER M4 ;
        RECT  0 4.896 0.192 4.92 ;
    END
  END di[3]
  PIN di[400]
    DIRECTION INPUT ;
    USE SIGNAL ;
    PORT
      LAYER M4 ;
        RECT  0 69.504 0.192 69.528 ;
    END
  END di[400]
  PIN di[401]
    DIRECTION INPUT ;
    USE SIGNAL ;
    PORT
      LAYER M4 ;
        RECT  0 69.696 0.192 69.72 ;
    END
  END di[401]
  PIN di[402]
    DIRECTION INPUT ;
    USE SIGNAL ;
    PORT
      LAYER M4 ;
        RECT  0 69.84 0.192 69.864 ;
    END
  END di[402]
  PIN di[403]
    DIRECTION INPUT ;
    USE SIGNAL ;
    PORT
      LAYER M4 ;
        RECT  0 70.032 0.192 70.056 ;
    END
  END di[403]
  PIN di[404]
    DIRECTION INPUT ;
    USE SIGNAL ;
    PORT
      LAYER M4 ;
        RECT  0 70.176 0.192 70.2 ;
    END
  END di[404]
  PIN di[405]
    DIRECTION INPUT ;
    USE SIGNAL ;
    PORT
      LAYER M4 ;
        RECT  0 70.32 0.192 70.344 ;
    END
  END di[405]
  PIN di[406]
    DIRECTION INPUT ;
    USE SIGNAL ;
    PORT
      LAYER M4 ;
        RECT  0 70.512 0.192 70.536 ;
    END
  END di[406]
  PIN di[407]
    DIRECTION INPUT ;
    USE SIGNAL ;
    PORT
      LAYER M4 ;
        RECT  0 70.656 0.192 70.68 ;
    END
  END di[407]
  PIN di[408]
    DIRECTION INPUT ;
    USE SIGNAL ;
    PORT
      LAYER M4 ;
        RECT  0 70.848 0.192 70.872 ;
    END
  END di[408]
  PIN di[409]
    DIRECTION INPUT ;
    USE SIGNAL ;
    PORT
      LAYER M4 ;
        RECT  0 70.992 0.192 71.016 ;
    END
  END di[409]
  PIN di[40]
    DIRECTION INPUT ;
    USE SIGNAL ;
    PORT
      LAYER M4 ;
        RECT  0 10.944 0.192 10.968 ;
    END
  END di[40]
  PIN di[410]
    DIRECTION INPUT ;
    USE SIGNAL ;
    PORT
      LAYER M4 ;
        RECT  0 71.136 0.192 71.16 ;
    END
  END di[410]
  PIN di[411]
    DIRECTION INPUT ;
    USE SIGNAL ;
    PORT
      LAYER M4 ;
        RECT  0 71.328 0.192 71.352 ;
    END
  END di[411]
  PIN di[412]
    DIRECTION INPUT ;
    USE SIGNAL ;
    PORT
      LAYER M4 ;
        RECT  0 71.472 0.192 71.496 ;
    END
  END di[412]
  PIN di[413]
    DIRECTION INPUT ;
    USE SIGNAL ;
    PORT
      LAYER M4 ;
        RECT  0 71.664 0.192 71.688 ;
    END
  END di[413]
  PIN di[414]
    DIRECTION INPUT ;
    USE SIGNAL ;
    PORT
      LAYER M4 ;
        RECT  0 71.808 0.192 71.832 ;
    END
  END di[414]
  PIN di[415]
    DIRECTION INPUT ;
    USE SIGNAL ;
    PORT
      LAYER M4 ;
        RECT  0 71.952 0.192 71.976 ;
    END
  END di[415]
  PIN di[416]
    DIRECTION INPUT ;
    USE SIGNAL ;
    PORT
      LAYER M4 ;
        RECT  0 72.144 0.192 72.168 ;
    END
  END di[416]
  PIN di[417]
    DIRECTION INPUT ;
    USE SIGNAL ;
    PORT
      LAYER M4 ;
        RECT  0 72.288 0.192 72.312 ;
    END
  END di[417]
  PIN di[418]
    DIRECTION INPUT ;
    USE SIGNAL ;
    PORT
      LAYER M4 ;
        RECT  0 72.48 0.192 72.504 ;
    END
  END di[418]
  PIN di[419]
    DIRECTION INPUT ;
    USE SIGNAL ;
    PORT
      LAYER M4 ;
        RECT  0 72.624 0.192 72.648 ;
    END
  END di[419]
  PIN di[41]
    DIRECTION INPUT ;
    USE SIGNAL ;
    PORT
      LAYER M4 ;
        RECT  0 11.088 0.192 11.112 ;
    END
  END di[41]
  PIN di[420]
    DIRECTION INPUT ;
    USE SIGNAL ;
    PORT
      LAYER M4 ;
        RECT  0 72.768 0.192 72.792 ;
    END
  END di[420]
  PIN di[421]
    DIRECTION INPUT ;
    USE SIGNAL ;
    PORT
      LAYER M4 ;
        RECT  0 72.96 0.192 72.984 ;
    END
  END di[421]
  PIN di[422]
    DIRECTION INPUT ;
    USE SIGNAL ;
    PORT
      LAYER M4 ;
        RECT  0 73.104 0.192 73.128 ;
    END
  END di[422]
  PIN di[423]
    DIRECTION INPUT ;
    USE SIGNAL ;
    PORT
      LAYER M4 ;
        RECT  0 73.248 0.192 73.272 ;
    END
  END di[423]
  PIN di[424]
    DIRECTION INPUT ;
    USE SIGNAL ;
    PORT
      LAYER M4 ;
        RECT  0 73.44 0.192 73.464 ;
    END
  END di[424]
  PIN di[425]
    DIRECTION INPUT ;
    USE SIGNAL ;
    PORT
      LAYER M4 ;
        RECT  0 73.584 0.192 73.608 ;
    END
  END di[425]
  PIN di[426]
    DIRECTION INPUT ;
    USE SIGNAL ;
    PORT
      LAYER M4 ;
        RECT  0 73.776 0.192 73.8 ;
    END
  END di[426]
  PIN di[427]
    DIRECTION INPUT ;
    USE SIGNAL ;
    PORT
      LAYER M4 ;
        RECT  0 73.92 0.192 73.944 ;
    END
  END di[427]
  PIN di[428]
    DIRECTION INPUT ;
    USE SIGNAL ;
    PORT
      LAYER M4 ;
        RECT  0 74.064 0.192 74.088 ;
    END
  END di[428]
  PIN di[429]
    DIRECTION INPUT ;
    USE SIGNAL ;
    PORT
      LAYER M4 ;
        RECT  0 74.256 0.192 74.28 ;
    END
  END di[429]
  PIN di[42]
    DIRECTION INPUT ;
    USE SIGNAL ;
    PORT
      LAYER M4 ;
        RECT  0 11.232 0.192 11.256 ;
    END
  END di[42]
  PIN di[430]
    DIRECTION INPUT ;
    USE SIGNAL ;
    PORT
      LAYER M4 ;
        RECT  0 74.4 0.192 74.424 ;
    END
  END di[430]
  PIN di[431]
    DIRECTION INPUT ;
    USE SIGNAL ;
    PORT
      LAYER M4 ;
        RECT  0 74.592 0.192 74.616 ;
    END
  END di[431]
  PIN di[432]
    DIRECTION INPUT ;
    USE SIGNAL ;
    PORT
      LAYER M4 ;
        RECT  0 74.736 0.192 74.76 ;
    END
  END di[432]
  PIN di[433]
    DIRECTION INPUT ;
    USE SIGNAL ;
    PORT
      LAYER M4 ;
        RECT  0 74.88 0.192 74.904 ;
    END
  END di[433]
  PIN di[434]
    DIRECTION INPUT ;
    USE SIGNAL ;
    PORT
      LAYER M4 ;
        RECT  0 75.072 0.192 75.096 ;
    END
  END di[434]
  PIN di[435]
    DIRECTION INPUT ;
    USE SIGNAL ;
    PORT
      LAYER M4 ;
        RECT  0 75.216 0.192 75.24 ;
    END
  END di[435]
  PIN di[436]
    DIRECTION INPUT ;
    USE SIGNAL ;
    PORT
      LAYER M4 ;
        RECT  0 75.408 0.192 75.432 ;
    END
  END di[436]
  PIN di[437]
    DIRECTION INPUT ;
    USE SIGNAL ;
    PORT
      LAYER M4 ;
        RECT  0 75.552 0.192 75.576 ;
    END
  END di[437]
  PIN di[438]
    DIRECTION INPUT ;
    USE SIGNAL ;
    PORT
      LAYER M4 ;
        RECT  0 75.696 0.192 75.72 ;
    END
  END di[438]
  PIN di[439]
    DIRECTION INPUT ;
    USE SIGNAL ;
    PORT
      LAYER M4 ;
        RECT  0 75.888 0.192 75.912 ;
    END
  END di[439]
  PIN di[43]
    DIRECTION INPUT ;
    USE SIGNAL ;
    PORT
      LAYER M4 ;
        RECT  0 11.424 0.192 11.448 ;
    END
  END di[43]
  PIN di[440]
    DIRECTION INPUT ;
    USE SIGNAL ;
    PORT
      LAYER M4 ;
        RECT  0 76.032 0.192 76.056 ;
    END
  END di[440]
  PIN di[441]
    DIRECTION INPUT ;
    USE SIGNAL ;
    PORT
      LAYER M4 ;
        RECT  0 76.224 0.192 76.248 ;
    END
  END di[441]
  PIN di[442]
    DIRECTION INPUT ;
    USE SIGNAL ;
    PORT
      LAYER M4 ;
        RECT  0 76.368 0.192 76.392 ;
    END
  END di[442]
  PIN di[443]
    DIRECTION INPUT ;
    USE SIGNAL ;
    PORT
      LAYER M4 ;
        RECT  0 76.512 0.192 76.536 ;
    END
  END di[443]
  PIN di[444]
    DIRECTION INPUT ;
    USE SIGNAL ;
    PORT
      LAYER M4 ;
        RECT  0 76.704 0.192 76.728 ;
    END
  END di[444]
  PIN di[445]
    DIRECTION INPUT ;
    USE SIGNAL ;
    PORT
      LAYER M4 ;
        RECT  0 76.848 0.192 76.872 ;
    END
  END di[445]
  PIN di[446]
    DIRECTION INPUT ;
    USE SIGNAL ;
    PORT
      LAYER M4 ;
        RECT  0 76.992 0.192 77.016 ;
    END
  END di[446]
  PIN di[447]
    DIRECTION INPUT ;
    USE SIGNAL ;
    PORT
      LAYER M4 ;
        RECT  0 77.184 0.192 77.208 ;
    END
  END di[447]
  PIN di[448]
    DIRECTION INPUT ;
    USE SIGNAL ;
    PORT
      LAYER M4 ;
        RECT  0 77.328 0.192 77.352 ;
    END
  END di[448]
  PIN di[449]
    DIRECTION INPUT ;
    USE SIGNAL ;
    PORT
      LAYER M4 ;
        RECT  0 77.52 0.192 77.544 ;
    END
  END di[449]
  PIN di[44]
    DIRECTION INPUT ;
    USE SIGNAL ;
    PORT
      LAYER M4 ;
        RECT  0 11.568 0.192 11.592 ;
    END
  END di[44]
  PIN di[450]
    DIRECTION INPUT ;
    USE SIGNAL ;
    PORT
      LAYER M4 ;
        RECT  0 77.664 0.192 77.688 ;
    END
  END di[450]
  PIN di[451]
    DIRECTION INPUT ;
    USE SIGNAL ;
    PORT
      LAYER M4 ;
        RECT  0 77.808 0.192 77.832 ;
    END
  END di[451]
  PIN di[452]
    DIRECTION INPUT ;
    USE SIGNAL ;
    PORT
      LAYER M4 ;
        RECT  0 78 0.192 78.024 ;
    END
  END di[452]
  PIN di[453]
    DIRECTION INPUT ;
    USE SIGNAL ;
    PORT
      LAYER M4 ;
        RECT  0 78.144 0.192 78.168 ;
    END
  END di[453]
  PIN di[454]
    DIRECTION INPUT ;
    USE SIGNAL ;
    PORT
      LAYER M4 ;
        RECT  0 78.336 0.192 78.36 ;
    END
  END di[454]
  PIN di[455]
    DIRECTION INPUT ;
    USE SIGNAL ;
    PORT
      LAYER M4 ;
        RECT  0 78.48 0.192 78.504 ;
    END
  END di[455]
  PIN di[456]
    DIRECTION INPUT ;
    USE SIGNAL ;
    PORT
      LAYER M4 ;
        RECT  0 78.624 0.192 78.648 ;
    END
  END di[456]
  PIN di[457]
    DIRECTION INPUT ;
    USE SIGNAL ;
    PORT
      LAYER M4 ;
        RECT  0 78.816 0.192 78.84 ;
    END
  END di[457]
  PIN di[458]
    DIRECTION INPUT ;
    USE SIGNAL ;
    PORT
      LAYER M4 ;
        RECT  0 78.96 0.192 78.984 ;
    END
  END di[458]
  PIN di[459]
    DIRECTION INPUT ;
    USE SIGNAL ;
    PORT
      LAYER M4 ;
        RECT  0 79.152 0.192 79.176 ;
    END
  END di[459]
  PIN di[45]
    DIRECTION INPUT ;
    USE SIGNAL ;
    PORT
      LAYER M4 ;
        RECT  0 11.76 0.192 11.784 ;
    END
  END di[45]
  PIN di[460]
    DIRECTION INPUT ;
    USE SIGNAL ;
    PORT
      LAYER M4 ;
        RECT  0 79.296 0.192 79.32 ;
    END
  END di[460]
  PIN di[461]
    DIRECTION INPUT ;
    USE SIGNAL ;
    PORT
      LAYER M4 ;
        RECT  0 79.44 0.192 79.464 ;
    END
  END di[461]
  PIN di[462]
    DIRECTION INPUT ;
    USE SIGNAL ;
    PORT
      LAYER M4 ;
        RECT  0 79.632 0.192 79.656 ;
    END
  END di[462]
  PIN di[463]
    DIRECTION INPUT ;
    USE SIGNAL ;
    PORT
      LAYER M4 ;
        RECT  0 79.776 0.192 79.8 ;
    END
  END di[463]
  PIN di[464]
    DIRECTION INPUT ;
    USE SIGNAL ;
    PORT
      LAYER M4 ;
        RECT  0 79.968 0.192 79.992 ;
    END
  END di[464]
  PIN di[465]
    DIRECTION INPUT ;
    USE SIGNAL ;
    PORT
      LAYER M4 ;
        RECT  0 80.112 0.192 80.136 ;
    END
  END di[465]
  PIN di[466]
    DIRECTION INPUT ;
    USE SIGNAL ;
    PORT
      LAYER M4 ;
        RECT  0 80.256 0.192 80.28 ;
    END
  END di[466]
  PIN di[467]
    DIRECTION INPUT ;
    USE SIGNAL ;
    PORT
      LAYER M4 ;
        RECT  0 80.448 0.192 80.472 ;
    END
  END di[467]
  PIN di[468]
    DIRECTION INPUT ;
    USE SIGNAL ;
    PORT
      LAYER M4 ;
        RECT  0 80.592 0.192 80.616 ;
    END
  END di[468]
  PIN di[469]
    DIRECTION INPUT ;
    USE SIGNAL ;
    PORT
      LAYER M4 ;
        RECT  0 80.736 0.192 80.76 ;
    END
  END di[469]
  PIN di[46]
    DIRECTION INPUT ;
    USE SIGNAL ;
    PORT
      LAYER M4 ;
        RECT  0 11.904 0.192 11.928 ;
    END
  END di[46]
  PIN di[470]
    DIRECTION INPUT ;
    USE SIGNAL ;
    PORT
      LAYER M4 ;
        RECT  0 80.928 0.192 80.952 ;
    END
  END di[470]
  PIN di[471]
    DIRECTION INPUT ;
    USE SIGNAL ;
    PORT
      LAYER M4 ;
        RECT  0 81.072 0.192 81.096 ;
    END
  END di[471]
  PIN di[472]
    DIRECTION INPUT ;
    USE SIGNAL ;
    PORT
      LAYER M4 ;
        RECT  0 81.264 0.192 81.288 ;
    END
  END di[472]
  PIN di[473]
    DIRECTION INPUT ;
    USE SIGNAL ;
    PORT
      LAYER M4 ;
        RECT  0 81.408 0.192 81.432 ;
    END
  END di[473]
  PIN di[474]
    DIRECTION INPUT ;
    USE SIGNAL ;
    PORT
      LAYER M4 ;
        RECT  0 81.552 0.192 81.576 ;
    END
  END di[474]
  PIN di[475]
    DIRECTION INPUT ;
    USE SIGNAL ;
    PORT
      LAYER M4 ;
        RECT  0 81.744 0.192 81.768 ;
    END
  END di[475]
  PIN di[476]
    DIRECTION INPUT ;
    USE SIGNAL ;
    PORT
      LAYER M4 ;
        RECT  0 81.888 0.192 81.912 ;
    END
  END di[476]
  PIN di[477]
    DIRECTION INPUT ;
    USE SIGNAL ;
    PORT
      LAYER M4 ;
        RECT  0 82.08 0.192 82.104 ;
    END
  END di[477]
  PIN di[478]
    DIRECTION INPUT ;
    USE SIGNAL ;
    PORT
      LAYER M4 ;
        RECT  0 82.224 0.192 82.248 ;
    END
  END di[478]
  PIN di[479]
    DIRECTION INPUT ;
    USE SIGNAL ;
    PORT
      LAYER M4 ;
        RECT  0 82.368 0.192 82.392 ;
    END
  END di[479]
  PIN di[47]
    DIRECTION INPUT ;
    USE SIGNAL ;
    PORT
      LAYER M4 ;
        RECT  0 12.048 0.192 12.072 ;
    END
  END di[47]
  PIN di[480]
    DIRECTION INPUT ;
    USE SIGNAL ;
    PORT
      LAYER M4 ;
        RECT  0 82.56 0.192 82.584 ;
    END
  END di[480]
  PIN di[481]
    DIRECTION INPUT ;
    USE SIGNAL ;
    PORT
      LAYER M4 ;
        RECT  0 82.704 0.192 82.728 ;
    END
  END di[481]
  PIN di[482]
    DIRECTION INPUT ;
    USE SIGNAL ;
    PORT
      LAYER M4 ;
        RECT  0 82.896 0.192 82.92 ;
    END
  END di[482]
  PIN di[483]
    DIRECTION INPUT ;
    USE SIGNAL ;
    PORT
      LAYER M4 ;
        RECT  0 83.04 0.192 83.064 ;
    END
  END di[483]
  PIN di[484]
    DIRECTION INPUT ;
    USE SIGNAL ;
    PORT
      LAYER M4 ;
        RECT  0 83.184 0.192 83.208 ;
    END
  END di[484]
  PIN di[485]
    DIRECTION INPUT ;
    USE SIGNAL ;
    PORT
      LAYER M4 ;
        RECT  0 83.376 0.192 83.4 ;
    END
  END di[485]
  PIN di[486]
    DIRECTION INPUT ;
    USE SIGNAL ;
    PORT
      LAYER M4 ;
        RECT  0 83.52 0.192 83.544 ;
    END
  END di[486]
  PIN di[487]
    DIRECTION INPUT ;
    USE SIGNAL ;
    PORT
      LAYER M4 ;
        RECT  0 83.712 0.192 83.736 ;
    END
  END di[487]
  PIN di[488]
    DIRECTION INPUT ;
    USE SIGNAL ;
    PORT
      LAYER M4 ;
        RECT  0 83.856 0.192 83.88 ;
    END
  END di[488]
  PIN di[489]
    DIRECTION INPUT ;
    USE SIGNAL ;
    PORT
      LAYER M4 ;
        RECT  0 84 0.192 84.024 ;
    END
  END di[489]
  PIN di[48]
    DIRECTION INPUT ;
    USE SIGNAL ;
    PORT
      LAYER M4 ;
        RECT  0 12.24 0.192 12.264 ;
    END
  END di[48]
  PIN di[490]
    DIRECTION INPUT ;
    USE SIGNAL ;
    PORT
      LAYER M4 ;
        RECT  0 84.192 0.192 84.216 ;
    END
  END di[490]
  PIN di[491]
    DIRECTION INPUT ;
    USE SIGNAL ;
    PORT
      LAYER M4 ;
        RECT  0 84.336 0.192 84.36 ;
    END
  END di[491]
  PIN di[492]
    DIRECTION INPUT ;
    USE SIGNAL ;
    PORT
      LAYER M4 ;
        RECT  0 84.48 0.192 84.504 ;
    END
  END di[492]
  PIN di[493]
    DIRECTION INPUT ;
    USE SIGNAL ;
    PORT
      LAYER M4 ;
        RECT  0 84.672 0.192 84.696 ;
    END
  END di[493]
  PIN di[494]
    DIRECTION INPUT ;
    USE SIGNAL ;
    PORT
      LAYER M4 ;
        RECT  0 84.816 0.192 84.84 ;
    END
  END di[494]
  PIN di[495]
    DIRECTION INPUT ;
    USE SIGNAL ;
    PORT
      LAYER M4 ;
        RECT  0 85.008 0.192 85.032 ;
    END
  END di[495]
  PIN di[496]
    DIRECTION INPUT ;
    USE SIGNAL ;
    PORT
      LAYER M4 ;
        RECT  0 85.152 0.192 85.176 ;
    END
  END di[496]
  PIN di[497]
    DIRECTION INPUT ;
    USE SIGNAL ;
    PORT
      LAYER M4 ;
        RECT  0 85.296 0.192 85.32 ;
    END
  END di[497]
  PIN di[498]
    DIRECTION INPUT ;
    USE SIGNAL ;
    PORT
      LAYER M4 ;
        RECT  0 85.488 0.192 85.512 ;
    END
  END di[498]
  PIN di[499]
    DIRECTION INPUT ;
    USE SIGNAL ;
    PORT
      LAYER M4 ;
        RECT  0 85.632 0.192 85.656 ;
    END
  END di[499]
  PIN di[49]
    DIRECTION INPUT ;
    USE SIGNAL ;
    PORT
      LAYER M4 ;
        RECT  0 12.384 0.192 12.408 ;
    END
  END di[49]
  PIN di[4]
    DIRECTION INPUT ;
    USE SIGNAL ;
    PORT
      LAYER M4 ;
        RECT  0 5.088 0.192 5.112 ;
    END
  END di[4]
  PIN di[500]
    DIRECTION INPUT ;
    USE SIGNAL ;
    PORT
      LAYER M4 ;
        RECT  0 85.824 0.192 85.848 ;
    END
  END di[500]
  PIN di[501]
    DIRECTION INPUT ;
    USE SIGNAL ;
    PORT
      LAYER M4 ;
        RECT  0 85.968 0.192 85.992 ;
    END
  END di[501]
  PIN di[502]
    DIRECTION INPUT ;
    USE SIGNAL ;
    PORT
      LAYER M4 ;
        RECT  0 86.112 0.192 86.136 ;
    END
  END di[502]
  PIN di[503]
    DIRECTION INPUT ;
    USE SIGNAL ;
    PORT
      LAYER M4 ;
        RECT  0 86.304 0.192 86.328 ;
    END
  END di[503]
  PIN di[504]
    DIRECTION INPUT ;
    USE SIGNAL ;
    PORT
      LAYER M4 ;
        RECT  0 86.448 0.192 86.472 ;
    END
  END di[504]
  PIN di[505]
    DIRECTION INPUT ;
    USE SIGNAL ;
    PORT
      LAYER M4 ;
        RECT  0 86.64 0.192 86.664 ;
    END
  END di[505]
  PIN di[506]
    DIRECTION INPUT ;
    USE SIGNAL ;
    PORT
      LAYER M4 ;
        RECT  0 86.784 0.192 86.808 ;
    END
  END di[506]
  PIN di[507]
    DIRECTION INPUT ;
    USE SIGNAL ;
    PORT
      LAYER M4 ;
        RECT  0 86.928 0.192 86.952 ;
    END
  END di[507]
  PIN di[508]
    DIRECTION INPUT ;
    USE SIGNAL ;
    PORT
      LAYER M4 ;
        RECT  0 87.12 0.192 87.144 ;
    END
  END di[508]
  PIN di[509]
    DIRECTION INPUT ;
    USE SIGNAL ;
    PORT
      LAYER M4 ;
        RECT  0 87.264 0.192 87.288 ;
    END
  END di[509]
  PIN di[50]
    DIRECTION INPUT ;
    USE SIGNAL ;
    PORT
      LAYER M4 ;
        RECT  0 12.576 0.192 12.6 ;
    END
  END di[50]
  PIN di[510]
    DIRECTION INPUT ;
    USE SIGNAL ;
    PORT
      LAYER M4 ;
        RECT  0 87.456 0.192 87.48 ;
    END
  END di[510]
  PIN di[511]
    DIRECTION INPUT ;
    USE SIGNAL ;
    PORT
      LAYER M4 ;
        RECT  0 87.6 0.192 87.624 ;
    END
  END di[511]
  PIN di[512]
    DIRECTION INPUT ;
    USE SIGNAL ;
    PORT
      LAYER M4 ;
        RECT  0 87.744 0.192 87.768 ;
    END
  END di[512]
  PIN di[513]
    DIRECTION INPUT ;
    USE SIGNAL ;
    PORT
      LAYER M4 ;
        RECT  0 87.936 0.192 87.96 ;
    END
  END di[513]
  PIN di[514]
    DIRECTION INPUT ;
    USE SIGNAL ;
    PORT
      LAYER M4 ;
        RECT  0 88.08 0.192 88.104 ;
    END
  END di[514]
  PIN di[515]
    DIRECTION INPUT ;
    USE SIGNAL ;
    PORT
      LAYER M4 ;
        RECT  0 88.224 0.192 88.248 ;
    END
  END di[515]
  PIN di[516]
    DIRECTION INPUT ;
    USE SIGNAL ;
    PORT
      LAYER M4 ;
        RECT  0 88.416 0.192 88.44 ;
    END
  END di[516]
  PIN di[517]
    DIRECTION INPUT ;
    USE SIGNAL ;
    PORT
      LAYER M4 ;
        RECT  0 88.56 0.192 88.584 ;
    END
  END di[517]
  PIN di[518]
    DIRECTION INPUT ;
    USE SIGNAL ;
    PORT
      LAYER M4 ;
        RECT  0 88.752 0.192 88.776 ;
    END
  END di[518]
  PIN di[519]
    DIRECTION INPUT ;
    USE SIGNAL ;
    PORT
      LAYER M4 ;
        RECT  0 88.896 0.192 88.92 ;
    END
  END di[519]
  PIN di[51]
    DIRECTION INPUT ;
    USE SIGNAL ;
    PORT
      LAYER M4 ;
        RECT  0 12.72 0.192 12.744 ;
    END
  END di[51]
  PIN di[520]
    DIRECTION INPUT ;
    USE SIGNAL ;
    PORT
      LAYER M4 ;
        RECT  0 89.04 0.192 89.064 ;
    END
  END di[520]
  PIN di[521]
    DIRECTION INPUT ;
    USE SIGNAL ;
    PORT
      LAYER M4 ;
        RECT  0 89.232 0.192 89.256 ;
    END
  END di[521]
  PIN di[522]
    DIRECTION INPUT ;
    USE SIGNAL ;
    PORT
      LAYER M4 ;
        RECT  0 89.376 0.192 89.4 ;
    END
  END di[522]
  PIN di[523]
    DIRECTION INPUT ;
    USE SIGNAL ;
    PORT
      LAYER M4 ;
        RECT  0 89.568 0.192 89.592 ;
    END
  END di[523]
  PIN di[524]
    DIRECTION INPUT ;
    USE SIGNAL ;
    PORT
      LAYER M4 ;
        RECT  0 89.712 0.192 89.736 ;
    END
  END di[524]
  PIN di[525]
    DIRECTION INPUT ;
    USE SIGNAL ;
    PORT
      LAYER M4 ;
        RECT  0 89.856 0.192 89.88 ;
    END
  END di[525]
  PIN di[526]
    DIRECTION INPUT ;
    USE SIGNAL ;
    PORT
      LAYER M4 ;
        RECT  0 90.048 0.192 90.072 ;
    END
  END di[526]
  PIN di[527]
    DIRECTION INPUT ;
    USE SIGNAL ;
    PORT
      LAYER M4 ;
        RECT  0 90.192 0.192 90.216 ;
    END
  END di[527]
  PIN di[528]
    DIRECTION INPUT ;
    USE SIGNAL ;
    PORT
      LAYER M4 ;
        RECT  0 90.384 0.192 90.408 ;
    END
  END di[528]
  PIN di[529]
    DIRECTION INPUT ;
    USE SIGNAL ;
    PORT
      LAYER M4 ;
        RECT  0 90.528 0.192 90.552 ;
    END
  END di[529]
  PIN di[52]
    DIRECTION INPUT ;
    USE SIGNAL ;
    PORT
      LAYER M4 ;
        RECT  0 12.864 0.192 12.888 ;
    END
  END di[52]
  PIN di[530]
    DIRECTION INPUT ;
    USE SIGNAL ;
    PORT
      LAYER M4 ;
        RECT  0 90.672 0.192 90.696 ;
    END
  END di[530]
  PIN di[531]
    DIRECTION INPUT ;
    USE SIGNAL ;
    PORT
      LAYER M4 ;
        RECT  0 90.864 0.192 90.888 ;
    END
  END di[531]
  PIN di[532]
    DIRECTION INPUT ;
    USE SIGNAL ;
    PORT
      LAYER M4 ;
        RECT  0 91.008 0.192 91.032 ;
    END
  END di[532]
  PIN di[533]
    DIRECTION INPUT ;
    USE SIGNAL ;
    PORT
      LAYER M4 ;
        RECT  0 91.2 0.192 91.224 ;
    END
  END di[533]
  PIN di[534]
    DIRECTION INPUT ;
    USE SIGNAL ;
    PORT
      LAYER M4 ;
        RECT  0 91.344 0.192 91.368 ;
    END
  END di[534]
  PIN di[535]
    DIRECTION INPUT ;
    USE SIGNAL ;
    PORT
      LAYER M4 ;
        RECT  0 91.488 0.192 91.512 ;
    END
  END di[535]
  PIN di[536]
    DIRECTION INPUT ;
    USE SIGNAL ;
    PORT
      LAYER M4 ;
        RECT  0 91.68 0.192 91.704 ;
    END
  END di[536]
  PIN di[537]
    DIRECTION INPUT ;
    USE SIGNAL ;
    PORT
      LAYER M4 ;
        RECT  0 91.824 0.192 91.848 ;
    END
  END di[537]
  PIN di[538]
    DIRECTION INPUT ;
    USE SIGNAL ;
    PORT
      LAYER M4 ;
        RECT  0 91.968 0.192 91.992 ;
    END
  END di[538]
  PIN di[539]
    DIRECTION INPUT ;
    USE SIGNAL ;
    PORT
      LAYER M4 ;
        RECT  0 92.16 0.192 92.184 ;
    END
  END di[539]
  PIN di[53]
    DIRECTION INPUT ;
    USE SIGNAL ;
    PORT
      LAYER M4 ;
        RECT  0 13.056 0.192 13.08 ;
    END
  END di[53]
  PIN di[540]
    DIRECTION INPUT ;
    USE SIGNAL ;
    PORT
      LAYER M4 ;
        RECT  0 92.304 0.192 92.328 ;
    END
  END di[540]
  PIN di[541]
    DIRECTION INPUT ;
    USE SIGNAL ;
    PORT
      LAYER M4 ;
        RECT  0 92.496 0.192 92.52 ;
    END
  END di[541]
  PIN di[542]
    DIRECTION INPUT ;
    USE SIGNAL ;
    PORT
      LAYER M4 ;
        RECT  0 92.64 0.192 92.664 ;
    END
  END di[542]
  PIN di[543]
    DIRECTION INPUT ;
    USE SIGNAL ;
    PORT
      LAYER M4 ;
        RECT  0 92.784 0.192 92.808 ;
    END
  END di[543]
  PIN di[544]
    DIRECTION INPUT ;
    USE SIGNAL ;
    PORT
      LAYER M4 ;
        RECT  0 92.976 0.192 93 ;
    END
  END di[544]
  PIN di[545]
    DIRECTION INPUT ;
    USE SIGNAL ;
    PORT
      LAYER M4 ;
        RECT  0 93.12 0.192 93.144 ;
    END
  END di[545]
  PIN di[546]
    DIRECTION INPUT ;
    USE SIGNAL ;
    PORT
      LAYER M4 ;
        RECT  0 93.312 0.192 93.336 ;
    END
  END di[546]
  PIN di[547]
    DIRECTION INPUT ;
    USE SIGNAL ;
    PORT
      LAYER M4 ;
        RECT  0 93.456 0.192 93.48 ;
    END
  END di[547]
  PIN di[548]
    DIRECTION INPUT ;
    USE SIGNAL ;
    PORT
      LAYER M4 ;
        RECT  0 93.6 0.192 93.624 ;
    END
  END di[548]
  PIN di[549]
    DIRECTION INPUT ;
    USE SIGNAL ;
    PORT
      LAYER M4 ;
        RECT  0 93.792 0.192 93.816 ;
    END
  END di[549]
  PIN di[54]
    DIRECTION INPUT ;
    USE SIGNAL ;
    PORT
      LAYER M4 ;
        RECT  0 13.2 0.192 13.224 ;
    END
  END di[54]
  PIN di[550]
    DIRECTION INPUT ;
    USE SIGNAL ;
    PORT
      LAYER M4 ;
        RECT  0 93.936 0.192 93.96 ;
    END
  END di[550]
  PIN di[551]
    DIRECTION INPUT ;
    USE SIGNAL ;
    PORT
      LAYER M4 ;
        RECT  0 94.128 0.192 94.152 ;
    END
  END di[551]
  PIN di[552]
    DIRECTION INPUT ;
    USE SIGNAL ;
    PORT
      LAYER M4 ;
        RECT  0 94.272 0.192 94.296 ;
    END
  END di[552]
  PIN di[553]
    DIRECTION INPUT ;
    USE SIGNAL ;
    PORT
      LAYER M4 ;
        RECT  0 94.416 0.192 94.44 ;
    END
  END di[553]
  PIN di[554]
    DIRECTION INPUT ;
    USE SIGNAL ;
    PORT
      LAYER M4 ;
        RECT  0 94.608 0.192 94.632 ;
    END
  END di[554]
  PIN di[555]
    DIRECTION INPUT ;
    USE SIGNAL ;
    PORT
      LAYER M4 ;
        RECT  0 94.752 0.192 94.776 ;
    END
  END di[555]
  PIN di[556]
    DIRECTION INPUT ;
    USE SIGNAL ;
    PORT
      LAYER M4 ;
        RECT  0 94.944 0.192 94.968 ;
    END
  END di[556]
  PIN di[557]
    DIRECTION INPUT ;
    USE SIGNAL ;
    PORT
      LAYER M4 ;
        RECT  0 95.088 0.192 95.112 ;
    END
  END di[557]
  PIN di[558]
    DIRECTION INPUT ;
    USE SIGNAL ;
    PORT
      LAYER M4 ;
        RECT  0 95.232 0.192 95.256 ;
    END
  END di[558]
  PIN di[559]
    DIRECTION INPUT ;
    USE SIGNAL ;
    PORT
      LAYER M4 ;
        RECT  0 95.424 0.192 95.448 ;
    END
  END di[559]
  PIN di[55]
    DIRECTION INPUT ;
    USE SIGNAL ;
    PORT
      LAYER M4 ;
        RECT  0 13.344 0.192 13.368 ;
    END
  END di[55]
  PIN di[560]
    DIRECTION INPUT ;
    USE SIGNAL ;
    PORT
      LAYER M4 ;
        RECT  0 95.568 0.192 95.592 ;
    END
  END di[560]
  PIN di[561]
    DIRECTION INPUT ;
    USE SIGNAL ;
    PORT
      LAYER M4 ;
        RECT  0 95.712 0.192 95.736 ;
    END
  END di[561]
  PIN di[562]
    DIRECTION INPUT ;
    USE SIGNAL ;
    PORT
      LAYER M4 ;
        RECT  0 95.904 0.192 95.928 ;
    END
  END di[562]
  PIN di[563]
    DIRECTION INPUT ;
    USE SIGNAL ;
    PORT
      LAYER M4 ;
        RECT  0 96.048 0.192 96.072 ;
    END
  END di[563]
  PIN di[564]
    DIRECTION INPUT ;
    USE SIGNAL ;
    PORT
      LAYER M4 ;
        RECT  0 96.24 0.192 96.264 ;
    END
  END di[564]
  PIN di[565]
    DIRECTION INPUT ;
    USE SIGNAL ;
    PORT
      LAYER M4 ;
        RECT  0 96.384 0.192 96.408 ;
    END
  END di[565]
  PIN di[566]
    DIRECTION INPUT ;
    USE SIGNAL ;
    PORT
      LAYER M4 ;
        RECT  0 96.528 0.192 96.552 ;
    END
  END di[566]
  PIN di[567]
    DIRECTION INPUT ;
    USE SIGNAL ;
    PORT
      LAYER M4 ;
        RECT  0 96.72 0.192 96.744 ;
    END
  END di[567]
  PIN di[568]
    DIRECTION INPUT ;
    USE SIGNAL ;
    PORT
      LAYER M4 ;
        RECT  0 96.864 0.192 96.888 ;
    END
  END di[568]
  PIN di[569]
    DIRECTION INPUT ;
    USE SIGNAL ;
    PORT
      LAYER M4 ;
        RECT  0 97.056 0.192 97.08 ;
    END
  END di[569]
  PIN di[56]
    DIRECTION INPUT ;
    USE SIGNAL ;
    PORT
      LAYER M4 ;
        RECT  0 13.536 0.192 13.56 ;
    END
  END di[56]
  PIN di[570]
    DIRECTION INPUT ;
    USE SIGNAL ;
    PORT
      LAYER M4 ;
        RECT  0 97.2 0.192 97.224 ;
    END
  END di[570]
  PIN di[571]
    DIRECTION INPUT ;
    USE SIGNAL ;
    PORT
      LAYER M4 ;
        RECT  0 97.344 0.192 97.368 ;
    END
  END di[571]
  PIN di[572]
    DIRECTION INPUT ;
    USE SIGNAL ;
    PORT
      LAYER M4 ;
        RECT  0 97.536 0.192 97.56 ;
    END
  END di[572]
  PIN di[573]
    DIRECTION INPUT ;
    USE SIGNAL ;
    PORT
      LAYER M4 ;
        RECT  0 97.68 0.192 97.704 ;
    END
  END di[573]
  PIN di[574]
    DIRECTION INPUT ;
    USE SIGNAL ;
    PORT
      LAYER M4 ;
        RECT  0 97.872 0.192 97.896 ;
    END
  END di[574]
  PIN di[575]
    DIRECTION INPUT ;
    USE SIGNAL ;
    PORT
      LAYER M4 ;
        RECT  0 98.016 0.192 98.04 ;
    END
  END di[575]
  PIN di[576]
    DIRECTION INPUT ;
    USE SIGNAL ;
    PORT
      LAYER M4 ;
        RECT  0 98.16 0.192 98.184 ;
    END
  END di[576]
  PIN di[577]
    DIRECTION INPUT ;
    USE SIGNAL ;
    PORT
      LAYER M4 ;
        RECT  0 98.352 0.192 98.376 ;
    END
  END di[577]
  PIN di[578]
    DIRECTION INPUT ;
    USE SIGNAL ;
    PORT
      LAYER M4 ;
        RECT  0 98.496 0.192 98.52 ;
    END
  END di[578]
  PIN di[579]
    DIRECTION INPUT ;
    USE SIGNAL ;
    PORT
      LAYER M4 ;
        RECT  0 98.688 0.192 98.712 ;
    END
  END di[579]
  PIN di[57]
    DIRECTION INPUT ;
    USE SIGNAL ;
    PORT
      LAYER M4 ;
        RECT  0 13.68 0.192 13.704 ;
    END
  END di[57]
  PIN di[580]
    DIRECTION INPUT ;
    USE SIGNAL ;
    PORT
      LAYER M4 ;
        RECT  0 98.832 0.192 98.856 ;
    END
  END di[580]
  PIN di[581]
    DIRECTION INPUT ;
    USE SIGNAL ;
    PORT
      LAYER M4 ;
        RECT  0 98.976 0.192 99 ;
    END
  END di[581]
  PIN di[582]
    DIRECTION INPUT ;
    USE SIGNAL ;
    PORT
      LAYER M4 ;
        RECT  0 99.168 0.192 99.192 ;
    END
  END di[582]
  PIN di[583]
    DIRECTION INPUT ;
    USE SIGNAL ;
    PORT
      LAYER M4 ;
        RECT  0 99.312 0.192 99.336 ;
    END
  END di[583]
  PIN di[584]
    DIRECTION INPUT ;
    USE SIGNAL ;
    PORT
      LAYER M4 ;
        RECT  0 99.456 0.192 99.48 ;
    END
  END di[584]
  PIN di[585]
    DIRECTION INPUT ;
    USE SIGNAL ;
    PORT
      LAYER M4 ;
        RECT  0 99.648 0.192 99.672 ;
    END
  END di[585]
  PIN di[586]
    DIRECTION INPUT ;
    USE SIGNAL ;
    PORT
      LAYER M4 ;
        RECT  0 99.792 0.192 99.816 ;
    END
  END di[586]
  PIN di[587]
    DIRECTION INPUT ;
    USE SIGNAL ;
    PORT
      LAYER M4 ;
        RECT  0 99.984 0.192 100.008 ;
    END
  END di[587]
  PIN di[588]
    DIRECTION INPUT ;
    USE SIGNAL ;
    PORT
      LAYER M4 ;
        RECT  0 100.128 0.192 100.152 ;
    END
  END di[588]
  PIN di[589]
    DIRECTION INPUT ;
    USE SIGNAL ;
    PORT
      LAYER M4 ;
        RECT  0 100.272 0.192 100.296 ;
    END
  END di[589]
  PIN di[58]
    DIRECTION INPUT ;
    USE SIGNAL ;
    PORT
      LAYER M4 ;
        RECT  0 13.872 0.192 13.896 ;
    END
  END di[58]
  PIN di[590]
    DIRECTION INPUT ;
    USE SIGNAL ;
    PORT
      LAYER M4 ;
        RECT  0 100.464 0.192 100.488 ;
    END
  END di[590]
  PIN di[591]
    DIRECTION INPUT ;
    USE SIGNAL ;
    PORT
      LAYER M4 ;
        RECT  0 100.608 0.192 100.632 ;
    END
  END di[591]
  PIN di[592]
    DIRECTION INPUT ;
    USE SIGNAL ;
    PORT
      LAYER M4 ;
        RECT  0 100.8 0.192 100.824 ;
    END
  END di[592]
  PIN di[593]
    DIRECTION INPUT ;
    USE SIGNAL ;
    PORT
      LAYER M4 ;
        RECT  0 100.944 0.192 100.968 ;
    END
  END di[593]
  PIN di[594]
    DIRECTION INPUT ;
    USE SIGNAL ;
    PORT
      LAYER M4 ;
        RECT  0 101.088 0.192 101.112 ;
    END
  END di[594]
  PIN di[595]
    DIRECTION INPUT ;
    USE SIGNAL ;
    PORT
      LAYER M4 ;
        RECT  0 101.28 0.192 101.304 ;
    END
  END di[595]
  PIN di[596]
    DIRECTION INPUT ;
    USE SIGNAL ;
    PORT
      LAYER M4 ;
        RECT  0 101.424 0.192 101.448 ;
    END
  END di[596]
  PIN di[597]
    DIRECTION INPUT ;
    USE SIGNAL ;
    PORT
      LAYER M4 ;
        RECT  0 101.616 0.192 101.64 ;
    END
  END di[597]
  PIN di[598]
    DIRECTION INPUT ;
    USE SIGNAL ;
    PORT
      LAYER M4 ;
        RECT  0 101.76 0.192 101.784 ;
    END
  END di[598]
  PIN di[599]
    DIRECTION INPUT ;
    USE SIGNAL ;
    PORT
      LAYER M4 ;
        RECT  0 101.904 0.192 101.928 ;
    END
  END di[599]
  PIN di[59]
    DIRECTION INPUT ;
    USE SIGNAL ;
    PORT
      LAYER M4 ;
        RECT  0 14.016 0.192 14.04 ;
    END
  END di[59]
  PIN di[5]
    DIRECTION INPUT ;
    USE SIGNAL ;
    PORT
      LAYER M4 ;
        RECT  0 5.232 0.192 5.256 ;
    END
  END di[5]
  PIN di[600]
    DIRECTION INPUT ;
    USE SIGNAL ;
    PORT
      LAYER M4 ;
        RECT  0 102.096 0.192 102.12 ;
    END
  END di[600]
  PIN di[601]
    DIRECTION INPUT ;
    USE SIGNAL ;
    PORT
      LAYER M4 ;
        RECT  0 102.24 0.192 102.264 ;
    END
  END di[601]
  PIN di[602]
    DIRECTION INPUT ;
    USE SIGNAL ;
    PORT
      LAYER M4 ;
        RECT  0 102.432 0.192 102.456 ;
    END
  END di[602]
  PIN di[603]
    DIRECTION INPUT ;
    USE SIGNAL ;
    PORT
      LAYER M4 ;
        RECT  0 102.576 0.192 102.6 ;
    END
  END di[603]
  PIN di[604]
    DIRECTION INPUT ;
    USE SIGNAL ;
    PORT
      LAYER M4 ;
        RECT  0 102.72 0.192 102.744 ;
    END
  END di[604]
  PIN di[605]
    DIRECTION INPUT ;
    USE SIGNAL ;
    PORT
      LAYER M4 ;
        RECT  0 102.912 0.192 102.936 ;
    END
  END di[605]
  PIN di[606]
    DIRECTION INPUT ;
    USE SIGNAL ;
    PORT
      LAYER M4 ;
        RECT  0 103.056 0.192 103.08 ;
    END
  END di[606]
  PIN di[607]
    DIRECTION INPUT ;
    USE SIGNAL ;
    PORT
      LAYER M4 ;
        RECT  0 103.2 0.192 103.224 ;
    END
  END di[607]
  PIN di[608]
    DIRECTION INPUT ;
    USE SIGNAL ;
    PORT
      LAYER M4 ;
        RECT  0 103.392 0.192 103.416 ;
    END
  END di[608]
  PIN di[609]
    DIRECTION INPUT ;
    USE SIGNAL ;
    PORT
      LAYER M4 ;
        RECT  0 103.536 0.192 103.56 ;
    END
  END di[609]
  PIN di[60]
    DIRECTION INPUT ;
    USE SIGNAL ;
    PORT
      LAYER M4 ;
        RECT  0 14.16 0.192 14.184 ;
    END
  END di[60]
  PIN di[610]
    DIRECTION INPUT ;
    USE SIGNAL ;
    PORT
      LAYER M4 ;
        RECT  0 103.728 0.192 103.752 ;
    END
  END di[610]
  PIN di[611]
    DIRECTION INPUT ;
    USE SIGNAL ;
    PORT
      LAYER M4 ;
        RECT  0 103.872 0.192 103.896 ;
    END
  END di[611]
  PIN di[612]
    DIRECTION INPUT ;
    USE SIGNAL ;
    PORT
      LAYER M4 ;
        RECT  0 104.016 0.192 104.04 ;
    END
  END di[612]
  PIN di[613]
    DIRECTION INPUT ;
    USE SIGNAL ;
    PORT
      LAYER M4 ;
        RECT  0 104.208 0.192 104.232 ;
    END
  END di[613]
  PIN di[614]
    DIRECTION INPUT ;
    USE SIGNAL ;
    PORT
      LAYER M4 ;
        RECT  0 104.352 0.192 104.376 ;
    END
  END di[614]
  PIN di[615]
    DIRECTION INPUT ;
    USE SIGNAL ;
    PORT
      LAYER M4 ;
        RECT  0 104.544 0.192 104.568 ;
    END
  END di[615]
  PIN di[616]
    DIRECTION INPUT ;
    USE SIGNAL ;
    PORT
      LAYER M4 ;
        RECT  0 104.688 0.192 104.712 ;
    END
  END di[616]
  PIN di[617]
    DIRECTION INPUT ;
    USE SIGNAL ;
    PORT
      LAYER M4 ;
        RECT  0 104.832 0.192 104.856 ;
    END
  END di[617]
  PIN di[618]
    DIRECTION INPUT ;
    USE SIGNAL ;
    PORT
      LAYER M4 ;
        RECT  0 105.024 0.192 105.048 ;
    END
  END di[618]
  PIN di[619]
    DIRECTION INPUT ;
    USE SIGNAL ;
    PORT
      LAYER M4 ;
        RECT  0 105.168 0.192 105.192 ;
    END
  END di[619]
  PIN di[61]
    DIRECTION INPUT ;
    USE SIGNAL ;
    PORT
      LAYER M4 ;
        RECT  0 14.352 0.192 14.376 ;
    END
  END di[61]
  PIN di[620]
    DIRECTION INPUT ;
    USE SIGNAL ;
    PORT
      LAYER M4 ;
        RECT  0 105.36 0.192 105.384 ;
    END
  END di[620]
  PIN di[621]
    DIRECTION INPUT ;
    USE SIGNAL ;
    PORT
      LAYER M4 ;
        RECT  0 105.504 0.192 105.528 ;
    END
  END di[621]
  PIN di[622]
    DIRECTION INPUT ;
    USE SIGNAL ;
    PORT
      LAYER M4 ;
        RECT  0 105.648 0.192 105.672 ;
    END
  END di[622]
  PIN di[623]
    DIRECTION INPUT ;
    USE SIGNAL ;
    PORT
      LAYER M4 ;
        RECT  0 105.84 0.192 105.864 ;
    END
  END di[623]
  PIN di[624]
    DIRECTION INPUT ;
    USE SIGNAL ;
    PORT
      LAYER M4 ;
        RECT  0 105.984 0.192 106.008 ;
    END
  END di[624]
  PIN di[625]
    DIRECTION INPUT ;
    USE SIGNAL ;
    PORT
      LAYER M4 ;
        RECT  0 106.176 0.192 106.2 ;
    END
  END di[625]
  PIN di[626]
    DIRECTION INPUT ;
    USE SIGNAL ;
    PORT
      LAYER M4 ;
        RECT  0 106.32 0.192 106.344 ;
    END
  END di[626]
  PIN di[627]
    DIRECTION INPUT ;
    USE SIGNAL ;
    PORT
      LAYER M4 ;
        RECT  0 106.464 0.192 106.488 ;
    END
  END di[627]
  PIN di[628]
    DIRECTION INPUT ;
    USE SIGNAL ;
    PORT
      LAYER M4 ;
        RECT  0 106.656 0.192 106.68 ;
    END
  END di[628]
  PIN di[629]
    DIRECTION INPUT ;
    USE SIGNAL ;
    PORT
      LAYER M4 ;
        RECT  0 106.8 0.192 106.824 ;
    END
  END di[629]
  PIN di[62]
    DIRECTION INPUT ;
    USE SIGNAL ;
    PORT
      LAYER M4 ;
        RECT  0 14.496 0.192 14.52 ;
    END
  END di[62]
  PIN di[630]
    DIRECTION INPUT ;
    USE SIGNAL ;
    PORT
      LAYER M4 ;
        RECT  0 106.944 0.192 106.968 ;
    END
  END di[630]
  PIN di[631]
    DIRECTION INPUT ;
    USE SIGNAL ;
    PORT
      LAYER M4 ;
        RECT  0 107.136 0.192 107.16 ;
    END
  END di[631]
  PIN di[632]
    DIRECTION INPUT ;
    USE SIGNAL ;
    PORT
      LAYER M4 ;
        RECT  0 107.28 0.192 107.304 ;
    END
  END di[632]
  PIN di[633]
    DIRECTION INPUT ;
    USE SIGNAL ;
    PORT
      LAYER M4 ;
        RECT  0 107.472 0.192 107.496 ;
    END
  END di[633]
  PIN di[634]
    DIRECTION INPUT ;
    USE SIGNAL ;
    PORT
      LAYER M4 ;
        RECT  0 107.616 0.192 107.64 ;
    END
  END di[634]
  PIN di[635]
    DIRECTION INPUT ;
    USE SIGNAL ;
    PORT
      LAYER M4 ;
        RECT  0 107.76 0.192 107.784 ;
    END
  END di[635]
  PIN di[636]
    DIRECTION INPUT ;
    USE SIGNAL ;
    PORT
      LAYER M4 ;
        RECT  0 107.952 0.192 107.976 ;
    END
  END di[636]
  PIN di[637]
    DIRECTION INPUT ;
    USE SIGNAL ;
    PORT
      LAYER M4 ;
        RECT  0 108.096 0.192 108.12 ;
    END
  END di[637]
  PIN di[638]
    DIRECTION INPUT ;
    USE SIGNAL ;
    PORT
      LAYER M4 ;
        RECT  0 108.288 0.192 108.312 ;
    END
  END di[638]
  PIN di[639]
    DIRECTION INPUT ;
    USE SIGNAL ;
    PORT
      LAYER M4 ;
        RECT  0 108.432 0.192 108.456 ;
    END
  END di[639]
  PIN di[63]
    DIRECTION INPUT ;
    USE SIGNAL ;
    PORT
      LAYER M4 ;
        RECT  0 14.688 0.192 14.712 ;
    END
  END di[63]
  PIN di[640]
    DIRECTION INPUT ;
    USE SIGNAL ;
    PORT
      LAYER M4 ;
        RECT  0 108.576 0.192 108.6 ;
    END
  END di[640]
  PIN di[641]
    DIRECTION INPUT ;
    USE SIGNAL ;
    PORT
      LAYER M4 ;
        RECT  0 108.768 0.192 108.792 ;
    END
  END di[641]
  PIN di[642]
    DIRECTION INPUT ;
    USE SIGNAL ;
    PORT
      LAYER M4 ;
        RECT  0 108.912 0.192 108.936 ;
    END
  END di[642]
  PIN di[643]
    DIRECTION INPUT ;
    USE SIGNAL ;
    PORT
      LAYER M4 ;
        RECT  0 109.104 0.192 109.128 ;
    END
  END di[643]
  PIN di[644]
    DIRECTION INPUT ;
    USE SIGNAL ;
    PORT
      LAYER M4 ;
        RECT  0 109.248 0.192 109.272 ;
    END
  END di[644]
  PIN di[645]
    DIRECTION INPUT ;
    USE SIGNAL ;
    PORT
      LAYER M4 ;
        RECT  0 109.392 0.192 109.416 ;
    END
  END di[645]
  PIN di[646]
    DIRECTION INPUT ;
    USE SIGNAL ;
    PORT
      LAYER M4 ;
        RECT  0 109.584 0.192 109.608 ;
    END
  END di[646]
  PIN di[647]
    DIRECTION INPUT ;
    USE SIGNAL ;
    PORT
      LAYER M4 ;
        RECT  0 109.728 0.192 109.752 ;
    END
  END di[647]
  PIN di[648]
    DIRECTION INPUT ;
    USE SIGNAL ;
    PORT
      LAYER M4 ;
        RECT  0 109.92 0.192 109.944 ;
    END
  END di[648]
  PIN di[649]
    DIRECTION INPUT ;
    USE SIGNAL ;
    PORT
      LAYER M4 ;
        RECT  0 110.064 0.192 110.088 ;
    END
  END di[649]
  PIN di[64]
    DIRECTION INPUT ;
    USE SIGNAL ;
    PORT
      LAYER M4 ;
        RECT  0 14.832 0.192 14.856 ;
    END
  END di[64]
  PIN di[650]
    DIRECTION INPUT ;
    USE SIGNAL ;
    PORT
      LAYER M4 ;
        RECT  0 110.208 0.192 110.232 ;
    END
  END di[650]
  PIN di[651]
    DIRECTION INPUT ;
    USE SIGNAL ;
    PORT
      LAYER M4 ;
        RECT  0 110.4 0.192 110.424 ;
    END
  END di[651]
  PIN di[652]
    DIRECTION INPUT ;
    USE SIGNAL ;
    PORT
      LAYER M4 ;
        RECT  0 110.544 0.192 110.568 ;
    END
  END di[652]
  PIN di[653]
    DIRECTION INPUT ;
    USE SIGNAL ;
    PORT
      LAYER M4 ;
        RECT  0 110.688 0.192 110.712 ;
    END
  END di[653]
  PIN di[654]
    DIRECTION INPUT ;
    USE SIGNAL ;
    PORT
      LAYER M4 ;
        RECT  0 110.88 0.192 110.904 ;
    END
  END di[654]
  PIN di[655]
    DIRECTION INPUT ;
    USE SIGNAL ;
    PORT
      LAYER M4 ;
        RECT  0 111.024 0.192 111.048 ;
    END
  END di[655]
  PIN di[656]
    DIRECTION INPUT ;
    USE SIGNAL ;
    PORT
      LAYER M4 ;
        RECT  0 111.216 0.192 111.24 ;
    END
  END di[656]
  PIN di[657]
    DIRECTION INPUT ;
    USE SIGNAL ;
    PORT
      LAYER M4 ;
        RECT  0 111.36 0.192 111.384 ;
    END
  END di[657]
  PIN di[658]
    DIRECTION INPUT ;
    USE SIGNAL ;
    PORT
      LAYER M4 ;
        RECT  0 111.504 0.192 111.528 ;
    END
  END di[658]
  PIN di[659]
    DIRECTION INPUT ;
    USE SIGNAL ;
    PORT
      LAYER M4 ;
        RECT  0 111.696 0.192 111.72 ;
    END
  END di[659]
  PIN di[65]
    DIRECTION INPUT ;
    USE SIGNAL ;
    PORT
      LAYER M4 ;
        RECT  0 14.976 0.192 15 ;
    END
  END di[65]
  PIN di[660]
    DIRECTION INPUT ;
    USE SIGNAL ;
    PORT
      LAYER M4 ;
        RECT  0 111.84 0.192 111.864 ;
    END
  END di[660]
  PIN di[661]
    DIRECTION INPUT ;
    USE SIGNAL ;
    PORT
      LAYER M4 ;
        RECT  0 112.032 0.192 112.056 ;
    END
  END di[661]
  PIN di[662]
    DIRECTION INPUT ;
    USE SIGNAL ;
    PORT
      LAYER M4 ;
        RECT  0 112.176 0.192 112.2 ;
    END
  END di[662]
  PIN di[663]
    DIRECTION INPUT ;
    USE SIGNAL ;
    PORT
      LAYER M4 ;
        RECT  0 112.32 0.192 112.344 ;
    END
  END di[663]
  PIN di[664]
    DIRECTION INPUT ;
    USE SIGNAL ;
    PORT
      LAYER M4 ;
        RECT  0 112.512 0.192 112.536 ;
    END
  END di[664]
  PIN di[665]
    DIRECTION INPUT ;
    USE SIGNAL ;
    PORT
      LAYER M4 ;
        RECT  0 112.656 0.192 112.68 ;
    END
  END di[665]
  PIN di[666]
    DIRECTION INPUT ;
    USE SIGNAL ;
    PORT
      LAYER M4 ;
        RECT  0 112.848 0.192 112.872 ;
    END
  END di[666]
  PIN di[667]
    DIRECTION INPUT ;
    USE SIGNAL ;
    PORT
      LAYER M4 ;
        RECT  0 112.992 0.192 113.016 ;
    END
  END di[667]
  PIN di[668]
    DIRECTION INPUT ;
    USE SIGNAL ;
    PORT
      LAYER M4 ;
        RECT  0 113.136 0.192 113.16 ;
    END
  END di[668]
  PIN di[669]
    DIRECTION INPUT ;
    USE SIGNAL ;
    PORT
      LAYER M4 ;
        RECT  0 113.328 0.192 113.352 ;
    END
  END di[669]
  PIN di[66]
    DIRECTION INPUT ;
    USE SIGNAL ;
    PORT
      LAYER M4 ;
        RECT  0 15.168 0.192 15.192 ;
    END
  END di[66]
  PIN di[670]
    DIRECTION INPUT ;
    USE SIGNAL ;
    PORT
      LAYER M4 ;
        RECT  0 113.472 0.192 113.496 ;
    END
  END di[670]
  PIN di[671]
    DIRECTION INPUT ;
    USE SIGNAL ;
    PORT
      LAYER M4 ;
        RECT  0 113.664 0.192 113.688 ;
    END
  END di[671]
  PIN di[672]
    DIRECTION INPUT ;
    USE SIGNAL ;
    PORT
      LAYER M4 ;
        RECT  0 113.808 0.192 113.832 ;
    END
  END di[672]
  PIN di[673]
    DIRECTION INPUT ;
    USE SIGNAL ;
    PORT
      LAYER M4 ;
        RECT  0 113.952 0.192 113.976 ;
    END
  END di[673]
  PIN di[674]
    DIRECTION INPUT ;
    USE SIGNAL ;
    PORT
      LAYER M4 ;
        RECT  0 114.144 0.192 114.168 ;
    END
  END di[674]
  PIN di[675]
    DIRECTION INPUT ;
    USE SIGNAL ;
    PORT
      LAYER M4 ;
        RECT  0 114.288 0.192 114.312 ;
    END
  END di[675]
  PIN di[676]
    DIRECTION INPUT ;
    USE SIGNAL ;
    PORT
      LAYER M4 ;
        RECT  0 114.432 0.192 114.456 ;
    END
  END di[676]
  PIN di[677]
    DIRECTION INPUT ;
    USE SIGNAL ;
    PORT
      LAYER M4 ;
        RECT  0 114.624 0.192 114.648 ;
    END
  END di[677]
  PIN di[678]
    DIRECTION INPUT ;
    USE SIGNAL ;
    PORT
      LAYER M4 ;
        RECT  0 114.768 0.192 114.792 ;
    END
  END di[678]
  PIN di[679]
    DIRECTION INPUT ;
    USE SIGNAL ;
    PORT
      LAYER M4 ;
        RECT  0 114.96 0.192 114.984 ;
    END
  END di[679]
  PIN di[67]
    DIRECTION INPUT ;
    USE SIGNAL ;
    PORT
      LAYER M4 ;
        RECT  0 15.312 0.192 15.336 ;
    END
  END di[67]
  PIN di[680]
    DIRECTION INPUT ;
    USE SIGNAL ;
    PORT
      LAYER M4 ;
        RECT  0 115.104 0.192 115.128 ;
    END
  END di[680]
  PIN di[681]
    DIRECTION INPUT ;
    USE SIGNAL ;
    PORT
      LAYER M4 ;
        RECT  0 115.248 0.192 115.272 ;
    END
  END di[681]
  PIN di[682]
    DIRECTION INPUT ;
    USE SIGNAL ;
    PORT
      LAYER M4 ;
        RECT  0 115.44 0.192 115.464 ;
    END
  END di[682]
  PIN di[683]
    DIRECTION INPUT ;
    USE SIGNAL ;
    PORT
      LAYER M4 ;
        RECT  0 115.584 0.192 115.608 ;
    END
  END di[683]
  PIN di[684]
    DIRECTION INPUT ;
    USE SIGNAL ;
    PORT
      LAYER M4 ;
        RECT  0 115.776 0.192 115.8 ;
    END
  END di[684]
  PIN di[685]
    DIRECTION INPUT ;
    USE SIGNAL ;
    PORT
      LAYER M4 ;
        RECT  0 115.92 0.192 115.944 ;
    END
  END di[685]
  PIN di[686]
    DIRECTION INPUT ;
    USE SIGNAL ;
    PORT
      LAYER M4 ;
        RECT  0 116.064 0.192 116.088 ;
    END
  END di[686]
  PIN di[687]
    DIRECTION INPUT ;
    USE SIGNAL ;
    PORT
      LAYER M4 ;
        RECT  0 116.256 0.192 116.28 ;
    END
  END di[687]
  PIN di[688]
    DIRECTION INPUT ;
    USE SIGNAL ;
    PORT
      LAYER M4 ;
        RECT  0 116.4 0.192 116.424 ;
    END
  END di[688]
  PIN di[689]
    DIRECTION INPUT ;
    USE SIGNAL ;
    PORT
      LAYER M4 ;
        RECT  0 116.592 0.192 116.616 ;
    END
  END di[689]
  PIN di[68]
    DIRECTION INPUT ;
    USE SIGNAL ;
    PORT
      LAYER M4 ;
        RECT  0 15.504 0.192 15.528 ;
    END
  END di[68]
  PIN di[69]
    DIRECTION INPUT ;
    USE SIGNAL ;
    PORT
      LAYER M4 ;
        RECT  0 15.648 0.192 15.672 ;
    END
  END di[69]
  PIN di[6]
    DIRECTION INPUT ;
    USE SIGNAL ;
    PORT
      LAYER M4 ;
        RECT  0 5.376 0.192 5.4 ;
    END
  END di[6]
  PIN di[70]
    DIRECTION INPUT ;
    USE SIGNAL ;
    PORT
      LAYER M4 ;
        RECT  0 15.792 0.192 15.816 ;
    END
  END di[70]
  PIN di[71]
    DIRECTION INPUT ;
    USE SIGNAL ;
    PORT
      LAYER M4 ;
        RECT  0 15.984 0.192 16.008 ;
    END
  END di[71]
  PIN di[72]
    DIRECTION INPUT ;
    USE SIGNAL ;
    PORT
      LAYER M4 ;
        RECT  0 16.128 0.192 16.152 ;
    END
  END di[72]
  PIN di[73]
    DIRECTION INPUT ;
    USE SIGNAL ;
    PORT
      LAYER M4 ;
        RECT  0 16.32 0.192 16.344 ;
    END
  END di[73]
  PIN di[74]
    DIRECTION INPUT ;
    USE SIGNAL ;
    PORT
      LAYER M4 ;
        RECT  0 16.464 0.192 16.488 ;
    END
  END di[74]
  PIN di[75]
    DIRECTION INPUT ;
    USE SIGNAL ;
    PORT
      LAYER M4 ;
        RECT  0 16.608 0.192 16.632 ;
    END
  END di[75]
  PIN di[76]
    DIRECTION INPUT ;
    USE SIGNAL ;
    PORT
      LAYER M4 ;
        RECT  0 16.8 0.192 16.824 ;
    END
  END di[76]
  PIN di[77]
    DIRECTION INPUT ;
    USE SIGNAL ;
    PORT
      LAYER M4 ;
        RECT  0 16.944 0.192 16.968 ;
    END
  END di[77]
  PIN di[78]
    DIRECTION INPUT ;
    USE SIGNAL ;
    PORT
      LAYER M4 ;
        RECT  0 17.088 0.192 17.112 ;
    END
  END di[78]
  PIN di[79]
    DIRECTION INPUT ;
    USE SIGNAL ;
    PORT
      LAYER M4 ;
        RECT  0 17.28 0.192 17.304 ;
    END
  END di[79]
  PIN di[7]
    DIRECTION INPUT ;
    USE SIGNAL ;
    PORT
      LAYER M4 ;
        RECT  0 5.568 0.192 5.592 ;
    END
  END di[7]
  PIN di[80]
    DIRECTION INPUT ;
    USE SIGNAL ;
    PORT
      LAYER M4 ;
        RECT  0 17.424 0.192 17.448 ;
    END
  END di[80]
  PIN di[81]
    DIRECTION INPUT ;
    USE SIGNAL ;
    PORT
      LAYER M4 ;
        RECT  0 17.616 0.192 17.64 ;
    END
  END di[81]
  PIN di[82]
    DIRECTION INPUT ;
    USE SIGNAL ;
    PORT
      LAYER M4 ;
        RECT  0 17.76 0.192 17.784 ;
    END
  END di[82]
  PIN di[83]
    DIRECTION INPUT ;
    USE SIGNAL ;
    PORT
      LAYER M4 ;
        RECT  0 17.904 0.192 17.928 ;
    END
  END di[83]
  PIN di[84]
    DIRECTION INPUT ;
    USE SIGNAL ;
    PORT
      LAYER M4 ;
        RECT  0 18.096 0.192 18.12 ;
    END
  END di[84]
  PIN di[85]
    DIRECTION INPUT ;
    USE SIGNAL ;
    PORT
      LAYER M4 ;
        RECT  0 18.24 0.192 18.264 ;
    END
  END di[85]
  PIN di[86]
    DIRECTION INPUT ;
    USE SIGNAL ;
    PORT
      LAYER M4 ;
        RECT  0 18.432 0.192 18.456 ;
    END
  END di[86]
  PIN di[87]
    DIRECTION INPUT ;
    USE SIGNAL ;
    PORT
      LAYER M4 ;
        RECT  0 18.576 0.192 18.6 ;
    END
  END di[87]
  PIN di[88]
    DIRECTION INPUT ;
    USE SIGNAL ;
    PORT
      LAYER M4 ;
        RECT  0 18.72 0.192 18.744 ;
    END
  END di[88]
  PIN di[89]
    DIRECTION INPUT ;
    USE SIGNAL ;
    PORT
      LAYER M4 ;
        RECT  0 18.912 0.192 18.936 ;
    END
  END di[89]
  PIN di[8]
    DIRECTION INPUT ;
    USE SIGNAL ;
    PORT
      LAYER M4 ;
        RECT  0 5.712 0.192 5.736 ;
    END
  END di[8]
  PIN di[90]
    DIRECTION INPUT ;
    USE SIGNAL ;
    PORT
      LAYER M4 ;
        RECT  0 19.056 0.192 19.08 ;
    END
  END di[90]
  PIN di[91]
    DIRECTION INPUT ;
    USE SIGNAL ;
    PORT
      LAYER M4 ;
        RECT  0 19.248 0.192 19.272 ;
    END
  END di[91]
  PIN di[92]
    DIRECTION INPUT ;
    USE SIGNAL ;
    PORT
      LAYER M4 ;
        RECT  0 19.392 0.192 19.416 ;
    END
  END di[92]
  PIN di[93]
    DIRECTION INPUT ;
    USE SIGNAL ;
    PORT
      LAYER M4 ;
        RECT  0 19.536 0.192 19.56 ;
    END
  END di[93]
  PIN di[94]
    DIRECTION INPUT ;
    USE SIGNAL ;
    PORT
      LAYER M4 ;
        RECT  0 19.728 0.192 19.752 ;
    END
  END di[94]
  PIN di[95]
    DIRECTION INPUT ;
    USE SIGNAL ;
    PORT
      LAYER M4 ;
        RECT  0 19.872 0.192 19.896 ;
    END
  END di[95]
  PIN di[96]
    DIRECTION INPUT ;
    USE SIGNAL ;
    PORT
      LAYER M4 ;
        RECT  0 20.064 0.192 20.088 ;
    END
  END di[96]
  PIN di[97]
    DIRECTION INPUT ;
    USE SIGNAL ;
    PORT
      LAYER M4 ;
        RECT  0 20.208 0.192 20.232 ;
    END
  END di[97]
  PIN di[98]
    DIRECTION INPUT ;
    USE SIGNAL ;
    PORT
      LAYER M4 ;
        RECT  0 20.352 0.192 20.376 ;
    END
  END di[98]
  PIN di[99]
    DIRECTION INPUT ;
    USE SIGNAL ;
    PORT
      LAYER M4 ;
        RECT  0 20.544 0.192 20.568 ;
    END
  END di[99]
  PIN di[9]
    DIRECTION INPUT ;
    USE SIGNAL ;
    PORT
      LAYER M4 ;
        RECT  0 5.856 0.192 5.88 ;
    END
  END di[9]
  PIN dq[0]
    DIRECTION OUTPUT ;
    USE SIGNAL ;
    PORT
      LAYER M4 ;
        RECT  36.528 4.416 36.72 4.44 ;
    END
  END dq[0]
  PIN dq[100]
    DIRECTION OUTPUT ;
    USE SIGNAL ;
    PORT
      LAYER M4 ;
        RECT  36.528 20.688 36.72 20.712 ;
    END
  END dq[100]
  PIN dq[101]
    DIRECTION OUTPUT ;
    USE SIGNAL ;
    PORT
      LAYER M4 ;
        RECT  36.528 20.832 36.72 20.856 ;
    END
  END dq[101]
  PIN dq[102]
    DIRECTION OUTPUT ;
    USE SIGNAL ;
    PORT
      LAYER M4 ;
        RECT  36.528 21.024 36.72 21.048 ;
    END
  END dq[102]
  PIN dq[103]
    DIRECTION OUTPUT ;
    USE SIGNAL ;
    PORT
      LAYER M4 ;
        RECT  36.528 21.168 36.72 21.192 ;
    END
  END dq[103]
  PIN dq[104]
    DIRECTION OUTPUT ;
    USE SIGNAL ;
    PORT
      LAYER M4 ;
        RECT  36.528 21.36 36.72 21.384 ;
    END
  END dq[104]
  PIN dq[105]
    DIRECTION OUTPUT ;
    USE SIGNAL ;
    PORT
      LAYER M4 ;
        RECT  36.528 21.504 36.72 21.528 ;
    END
  END dq[105]
  PIN dq[106]
    DIRECTION OUTPUT ;
    USE SIGNAL ;
    PORT
      LAYER M4 ;
        RECT  36.528 21.648 36.72 21.672 ;
    END
  END dq[106]
  PIN dq[107]
    DIRECTION OUTPUT ;
    USE SIGNAL ;
    PORT
      LAYER M4 ;
        RECT  36.528 21.84 36.72 21.864 ;
    END
  END dq[107]
  PIN dq[108]
    DIRECTION OUTPUT ;
    USE SIGNAL ;
    PORT
      LAYER M4 ;
        RECT  36.528 21.984 36.72 22.008 ;
    END
  END dq[108]
  PIN dq[109]
    DIRECTION OUTPUT ;
    USE SIGNAL ;
    PORT
      LAYER M4 ;
        RECT  36.528 22.176 36.72 22.2 ;
    END
  END dq[109]
  PIN dq[10]
    DIRECTION OUTPUT ;
    USE SIGNAL ;
    PORT
      LAYER M4 ;
        RECT  36.528 6.048 36.72 6.072 ;
    END
  END dq[10]
  PIN dq[110]
    DIRECTION OUTPUT ;
    USE SIGNAL ;
    PORT
      LAYER M4 ;
        RECT  36.528 22.32 36.72 22.344 ;
    END
  END dq[110]
  PIN dq[111]
    DIRECTION OUTPUT ;
    USE SIGNAL ;
    PORT
      LAYER M4 ;
        RECT  36.528 22.464 36.72 22.488 ;
    END
  END dq[111]
  PIN dq[112]
    DIRECTION OUTPUT ;
    USE SIGNAL ;
    PORT
      LAYER M4 ;
        RECT  36.528 22.656 36.72 22.68 ;
    END
  END dq[112]
  PIN dq[113]
    DIRECTION OUTPUT ;
    USE SIGNAL ;
    PORT
      LAYER M4 ;
        RECT  36.528 22.8 36.72 22.824 ;
    END
  END dq[113]
  PIN dq[114]
    DIRECTION OUTPUT ;
    USE SIGNAL ;
    PORT
      LAYER M4 ;
        RECT  36.528 22.992 36.72 23.016 ;
    END
  END dq[114]
  PIN dq[115]
    DIRECTION OUTPUT ;
    USE SIGNAL ;
    PORT
      LAYER M4 ;
        RECT  36.528 23.136 36.72 23.16 ;
    END
  END dq[115]
  PIN dq[116]
    DIRECTION OUTPUT ;
    USE SIGNAL ;
    PORT
      LAYER M4 ;
        RECT  36.528 23.28 36.72 23.304 ;
    END
  END dq[116]
  PIN dq[117]
    DIRECTION OUTPUT ;
    USE SIGNAL ;
    PORT
      LAYER M4 ;
        RECT  36.528 23.472 36.72 23.496 ;
    END
  END dq[117]
  PIN dq[118]
    DIRECTION OUTPUT ;
    USE SIGNAL ;
    PORT
      LAYER M4 ;
        RECT  36.528 23.616 36.72 23.64 ;
    END
  END dq[118]
  PIN dq[119]
    DIRECTION OUTPUT ;
    USE SIGNAL ;
    PORT
      LAYER M4 ;
        RECT  36.528 23.808 36.72 23.832 ;
    END
  END dq[119]
  PIN dq[11]
    DIRECTION OUTPUT ;
    USE SIGNAL ;
    PORT
      LAYER M4 ;
        RECT  36.528 6.192 36.72 6.216 ;
    END
  END dq[11]
  PIN dq[120]
    DIRECTION OUTPUT ;
    USE SIGNAL ;
    PORT
      LAYER M4 ;
        RECT  36.528 23.952 36.72 23.976 ;
    END
  END dq[120]
  PIN dq[121]
    DIRECTION OUTPUT ;
    USE SIGNAL ;
    PORT
      LAYER M4 ;
        RECT  36.528 24.096 36.72 24.12 ;
    END
  END dq[121]
  PIN dq[122]
    DIRECTION OUTPUT ;
    USE SIGNAL ;
    PORT
      LAYER M4 ;
        RECT  36.528 24.288 36.72 24.312 ;
    END
  END dq[122]
  PIN dq[123]
    DIRECTION OUTPUT ;
    USE SIGNAL ;
    PORT
      LAYER M4 ;
        RECT  36.528 24.432 36.72 24.456 ;
    END
  END dq[123]
  PIN dq[124]
    DIRECTION OUTPUT ;
    USE SIGNAL ;
    PORT
      LAYER M4 ;
        RECT  36.528 24.576 36.72 24.6 ;
    END
  END dq[124]
  PIN dq[125]
    DIRECTION OUTPUT ;
    USE SIGNAL ;
    PORT
      LAYER M4 ;
        RECT  36.528 24.768 36.72 24.792 ;
    END
  END dq[125]
  PIN dq[126]
    DIRECTION OUTPUT ;
    USE SIGNAL ;
    PORT
      LAYER M4 ;
        RECT  36.528 24.912 36.72 24.936 ;
    END
  END dq[126]
  PIN dq[127]
    DIRECTION OUTPUT ;
    USE SIGNAL ;
    PORT
      LAYER M4 ;
        RECT  36.528 25.104 36.72 25.128 ;
    END
  END dq[127]
  PIN dq[128]
    DIRECTION OUTPUT ;
    USE SIGNAL ;
    PORT
      LAYER M4 ;
        RECT  36.528 25.248 36.72 25.272 ;
    END
  END dq[128]
  PIN dq[129]
    DIRECTION OUTPUT ;
    USE SIGNAL ;
    PORT
      LAYER M4 ;
        RECT  36.528 25.392 36.72 25.416 ;
    END
  END dq[129]
  PIN dq[12]
    DIRECTION OUTPUT ;
    USE SIGNAL ;
    PORT
      LAYER M4 ;
        RECT  36.528 6.384 36.72 6.408 ;
    END
  END dq[12]
  PIN dq[130]
    DIRECTION OUTPUT ;
    USE SIGNAL ;
    PORT
      LAYER M4 ;
        RECT  36.528 25.584 36.72 25.608 ;
    END
  END dq[130]
  PIN dq[131]
    DIRECTION OUTPUT ;
    USE SIGNAL ;
    PORT
      LAYER M4 ;
        RECT  36.528 25.728 36.72 25.752 ;
    END
  END dq[131]
  PIN dq[132]
    DIRECTION OUTPUT ;
    USE SIGNAL ;
    PORT
      LAYER M4 ;
        RECT  36.528 25.92 36.72 25.944 ;
    END
  END dq[132]
  PIN dq[133]
    DIRECTION OUTPUT ;
    USE SIGNAL ;
    PORT
      LAYER M4 ;
        RECT  36.528 26.064 36.72 26.088 ;
    END
  END dq[133]
  PIN dq[134]
    DIRECTION OUTPUT ;
    USE SIGNAL ;
    PORT
      LAYER M4 ;
        RECT  36.528 26.208 36.72 26.232 ;
    END
  END dq[134]
  PIN dq[135]
    DIRECTION OUTPUT ;
    USE SIGNAL ;
    PORT
      LAYER M4 ;
        RECT  36.528 26.4 36.72 26.424 ;
    END
  END dq[135]
  PIN dq[136]
    DIRECTION OUTPUT ;
    USE SIGNAL ;
    PORT
      LAYER M4 ;
        RECT  36.528 26.544 36.72 26.568 ;
    END
  END dq[136]
  PIN dq[137]
    DIRECTION OUTPUT ;
    USE SIGNAL ;
    PORT
      LAYER M4 ;
        RECT  36.528 26.736 36.72 26.76 ;
    END
  END dq[137]
  PIN dq[138]
    DIRECTION OUTPUT ;
    USE SIGNAL ;
    PORT
      LAYER M4 ;
        RECT  36.528 26.88 36.72 26.904 ;
    END
  END dq[138]
  PIN dq[139]
    DIRECTION OUTPUT ;
    USE SIGNAL ;
    PORT
      LAYER M4 ;
        RECT  36.528 27.024 36.72 27.048 ;
    END
  END dq[139]
  PIN dq[13]
    DIRECTION OUTPUT ;
    USE SIGNAL ;
    PORT
      LAYER M4 ;
        RECT  36.528 6.528 36.72 6.552 ;
    END
  END dq[13]
  PIN dq[140]
    DIRECTION OUTPUT ;
    USE SIGNAL ;
    PORT
      LAYER M4 ;
        RECT  36.528 27.216 36.72 27.24 ;
    END
  END dq[140]
  PIN dq[141]
    DIRECTION OUTPUT ;
    USE SIGNAL ;
    PORT
      LAYER M4 ;
        RECT  36.528 27.36 36.72 27.384 ;
    END
  END dq[141]
  PIN dq[142]
    DIRECTION OUTPUT ;
    USE SIGNAL ;
    PORT
      LAYER M4 ;
        RECT  36.528 27.552 36.72 27.576 ;
    END
  END dq[142]
  PIN dq[143]
    DIRECTION OUTPUT ;
    USE SIGNAL ;
    PORT
      LAYER M4 ;
        RECT  36.528 27.696 36.72 27.72 ;
    END
  END dq[143]
  PIN dq[144]
    DIRECTION OUTPUT ;
    USE SIGNAL ;
    PORT
      LAYER M4 ;
        RECT  36.528 27.84 36.72 27.864 ;
    END
  END dq[144]
  PIN dq[145]
    DIRECTION OUTPUT ;
    USE SIGNAL ;
    PORT
      LAYER M4 ;
        RECT  36.528 28.032 36.72 28.056 ;
    END
  END dq[145]
  PIN dq[146]
    DIRECTION OUTPUT ;
    USE SIGNAL ;
    PORT
      LAYER M4 ;
        RECT  36.528 28.176 36.72 28.2 ;
    END
  END dq[146]
  PIN dq[147]
    DIRECTION OUTPUT ;
    USE SIGNAL ;
    PORT
      LAYER M4 ;
        RECT  36.528 28.32 36.72 28.344 ;
    END
  END dq[147]
  PIN dq[148]
    DIRECTION OUTPUT ;
    USE SIGNAL ;
    PORT
      LAYER M4 ;
        RECT  36.528 28.512 36.72 28.536 ;
    END
  END dq[148]
  PIN dq[149]
    DIRECTION OUTPUT ;
    USE SIGNAL ;
    PORT
      LAYER M4 ;
        RECT  36.528 28.656 36.72 28.68 ;
    END
  END dq[149]
  PIN dq[14]
    DIRECTION OUTPUT ;
    USE SIGNAL ;
    PORT
      LAYER M4 ;
        RECT  36.528 6.672 36.72 6.696 ;
    END
  END dq[14]
  PIN dq[150]
    DIRECTION OUTPUT ;
    USE SIGNAL ;
    PORT
      LAYER M4 ;
        RECT  36.528 28.848 36.72 28.872 ;
    END
  END dq[150]
  PIN dq[151]
    DIRECTION OUTPUT ;
    USE SIGNAL ;
    PORT
      LAYER M4 ;
        RECT  36.528 28.992 36.72 29.016 ;
    END
  END dq[151]
  PIN dq[152]
    DIRECTION OUTPUT ;
    USE SIGNAL ;
    PORT
      LAYER M4 ;
        RECT  36.528 29.136 36.72 29.16 ;
    END
  END dq[152]
  PIN dq[153]
    DIRECTION OUTPUT ;
    USE SIGNAL ;
    PORT
      LAYER M4 ;
        RECT  36.528 29.328 36.72 29.352 ;
    END
  END dq[153]
  PIN dq[154]
    DIRECTION OUTPUT ;
    USE SIGNAL ;
    PORT
      LAYER M4 ;
        RECT  36.528 29.472 36.72 29.496 ;
    END
  END dq[154]
  PIN dq[155]
    DIRECTION OUTPUT ;
    USE SIGNAL ;
    PORT
      LAYER M4 ;
        RECT  36.528 29.664 36.72 29.688 ;
    END
  END dq[155]
  PIN dq[156]
    DIRECTION OUTPUT ;
    USE SIGNAL ;
    PORT
      LAYER M4 ;
        RECT  36.528 29.808 36.72 29.832 ;
    END
  END dq[156]
  PIN dq[157]
    DIRECTION OUTPUT ;
    USE SIGNAL ;
    PORT
      LAYER M4 ;
        RECT  36.528 29.952 36.72 29.976 ;
    END
  END dq[157]
  PIN dq[158]
    DIRECTION OUTPUT ;
    USE SIGNAL ;
    PORT
      LAYER M4 ;
        RECT  36.528 30.144 36.72 30.168 ;
    END
  END dq[158]
  PIN dq[159]
    DIRECTION OUTPUT ;
    USE SIGNAL ;
    PORT
      LAYER M4 ;
        RECT  36.528 30.288 36.72 30.312 ;
    END
  END dq[159]
  PIN dq[15]
    DIRECTION OUTPUT ;
    USE SIGNAL ;
    PORT
      LAYER M4 ;
        RECT  36.528 6.864 36.72 6.888 ;
    END
  END dq[15]
  PIN dq[160]
    DIRECTION OUTPUT ;
    USE SIGNAL ;
    PORT
      LAYER M4 ;
        RECT  36.528 30.48 36.72 30.504 ;
    END
  END dq[160]
  PIN dq[161]
    DIRECTION OUTPUT ;
    USE SIGNAL ;
    PORT
      LAYER M4 ;
        RECT  36.528 30.624 36.72 30.648 ;
    END
  END dq[161]
  PIN dq[162]
    DIRECTION OUTPUT ;
    USE SIGNAL ;
    PORT
      LAYER M4 ;
        RECT  36.528 30.768 36.72 30.792 ;
    END
  END dq[162]
  PIN dq[163]
    DIRECTION OUTPUT ;
    USE SIGNAL ;
    PORT
      LAYER M4 ;
        RECT  36.528 30.96 36.72 30.984 ;
    END
  END dq[163]
  PIN dq[164]
    DIRECTION OUTPUT ;
    USE SIGNAL ;
    PORT
      LAYER M4 ;
        RECT  36.528 31.104 36.72 31.128 ;
    END
  END dq[164]
  PIN dq[165]
    DIRECTION OUTPUT ;
    USE SIGNAL ;
    PORT
      LAYER M4 ;
        RECT  36.528 31.296 36.72 31.32 ;
    END
  END dq[165]
  PIN dq[166]
    DIRECTION OUTPUT ;
    USE SIGNAL ;
    PORT
      LAYER M4 ;
        RECT  36.528 31.44 36.72 31.464 ;
    END
  END dq[166]
  PIN dq[167]
    DIRECTION OUTPUT ;
    USE SIGNAL ;
    PORT
      LAYER M4 ;
        RECT  36.528 31.584 36.72 31.608 ;
    END
  END dq[167]
  PIN dq[168]
    DIRECTION OUTPUT ;
    USE SIGNAL ;
    PORT
      LAYER M4 ;
        RECT  36.528 31.776 36.72 31.8 ;
    END
  END dq[168]
  PIN dq[169]
    DIRECTION OUTPUT ;
    USE SIGNAL ;
    PORT
      LAYER M4 ;
        RECT  36.528 31.92 36.72 31.944 ;
    END
  END dq[169]
  PIN dq[16]
    DIRECTION OUTPUT ;
    USE SIGNAL ;
    PORT
      LAYER M4 ;
        RECT  36.528 7.008 36.72 7.032 ;
    END
  END dq[16]
  PIN dq[170]
    DIRECTION OUTPUT ;
    USE SIGNAL ;
    PORT
      LAYER M4 ;
        RECT  36.528 32.064 36.72 32.088 ;
    END
  END dq[170]
  PIN dq[171]
    DIRECTION OUTPUT ;
    USE SIGNAL ;
    PORT
      LAYER M4 ;
        RECT  36.528 32.256 36.72 32.28 ;
    END
  END dq[171]
  PIN dq[172]
    DIRECTION OUTPUT ;
    USE SIGNAL ;
    PORT
      LAYER M4 ;
        RECT  36.528 32.4 36.72 32.424 ;
    END
  END dq[172]
  PIN dq[173]
    DIRECTION OUTPUT ;
    USE SIGNAL ;
    PORT
      LAYER M4 ;
        RECT  36.528 32.592 36.72 32.616 ;
    END
  END dq[173]
  PIN dq[174]
    DIRECTION OUTPUT ;
    USE SIGNAL ;
    PORT
      LAYER M4 ;
        RECT  36.528 32.736 36.72 32.76 ;
    END
  END dq[174]
  PIN dq[175]
    DIRECTION OUTPUT ;
    USE SIGNAL ;
    PORT
      LAYER M4 ;
        RECT  36.528 32.88 36.72 32.904 ;
    END
  END dq[175]
  PIN dq[176]
    DIRECTION OUTPUT ;
    USE SIGNAL ;
    PORT
      LAYER M4 ;
        RECT  36.528 33.072 36.72 33.096 ;
    END
  END dq[176]
  PIN dq[177]
    DIRECTION OUTPUT ;
    USE SIGNAL ;
    PORT
      LAYER M4 ;
        RECT  36.528 33.216 36.72 33.24 ;
    END
  END dq[177]
  PIN dq[178]
    DIRECTION OUTPUT ;
    USE SIGNAL ;
    PORT
      LAYER M4 ;
        RECT  36.528 33.408 36.72 33.432 ;
    END
  END dq[178]
  PIN dq[179]
    DIRECTION OUTPUT ;
    USE SIGNAL ;
    PORT
      LAYER M4 ;
        RECT  36.528 33.552 36.72 33.576 ;
    END
  END dq[179]
  PIN dq[17]
    DIRECTION OUTPUT ;
    USE SIGNAL ;
    PORT
      LAYER M4 ;
        RECT  36.528 7.2 36.72 7.224 ;
    END
  END dq[17]
  PIN dq[180]
    DIRECTION OUTPUT ;
    USE SIGNAL ;
    PORT
      LAYER M4 ;
        RECT  36.528 33.696 36.72 33.72 ;
    END
  END dq[180]
  PIN dq[181]
    DIRECTION OUTPUT ;
    USE SIGNAL ;
    PORT
      LAYER M4 ;
        RECT  36.528 33.888 36.72 33.912 ;
    END
  END dq[181]
  PIN dq[182]
    DIRECTION OUTPUT ;
    USE SIGNAL ;
    PORT
      LAYER M4 ;
        RECT  36.528 34.032 36.72 34.056 ;
    END
  END dq[182]
  PIN dq[183]
    DIRECTION OUTPUT ;
    USE SIGNAL ;
    PORT
      LAYER M4 ;
        RECT  36.528 34.224 36.72 34.248 ;
    END
  END dq[183]
  PIN dq[184]
    DIRECTION OUTPUT ;
    USE SIGNAL ;
    PORT
      LAYER M4 ;
        RECT  36.528 34.368 36.72 34.392 ;
    END
  END dq[184]
  PIN dq[185]
    DIRECTION OUTPUT ;
    USE SIGNAL ;
    PORT
      LAYER M4 ;
        RECT  36.528 34.512 36.72 34.536 ;
    END
  END dq[185]
  PIN dq[186]
    DIRECTION OUTPUT ;
    USE SIGNAL ;
    PORT
      LAYER M4 ;
        RECT  36.528 34.704 36.72 34.728 ;
    END
  END dq[186]
  PIN dq[187]
    DIRECTION OUTPUT ;
    USE SIGNAL ;
    PORT
      LAYER M4 ;
        RECT  36.528 34.848 36.72 34.872 ;
    END
  END dq[187]
  PIN dq[188]
    DIRECTION OUTPUT ;
    USE SIGNAL ;
    PORT
      LAYER M4 ;
        RECT  36.528 35.04 36.72 35.064 ;
    END
  END dq[188]
  PIN dq[189]
    DIRECTION OUTPUT ;
    USE SIGNAL ;
    PORT
      LAYER M4 ;
        RECT  36.528 35.184 36.72 35.208 ;
    END
  END dq[189]
  PIN dq[18]
    DIRECTION OUTPUT ;
    USE SIGNAL ;
    PORT
      LAYER M4 ;
        RECT  36.528 7.344 36.72 7.368 ;
    END
  END dq[18]
  PIN dq[190]
    DIRECTION OUTPUT ;
    USE SIGNAL ;
    PORT
      LAYER M4 ;
        RECT  36.528 35.328 36.72 35.352 ;
    END
  END dq[190]
  PIN dq[191]
    DIRECTION OUTPUT ;
    USE SIGNAL ;
    PORT
      LAYER M4 ;
        RECT  36.528 35.52 36.72 35.544 ;
    END
  END dq[191]
  PIN dq[192]
    DIRECTION OUTPUT ;
    USE SIGNAL ;
    PORT
      LAYER M4 ;
        RECT  36.528 35.664 36.72 35.688 ;
    END
  END dq[192]
  PIN dq[193]
    DIRECTION OUTPUT ;
    USE SIGNAL ;
    PORT
      LAYER M4 ;
        RECT  36.528 35.808 36.72 35.832 ;
    END
  END dq[193]
  PIN dq[194]
    DIRECTION OUTPUT ;
    USE SIGNAL ;
    PORT
      LAYER M4 ;
        RECT  36.528 36 36.72 36.024 ;
    END
  END dq[194]
  PIN dq[195]
    DIRECTION OUTPUT ;
    USE SIGNAL ;
    PORT
      LAYER M4 ;
        RECT  36.528 36.144 36.72 36.168 ;
    END
  END dq[195]
  PIN dq[196]
    DIRECTION OUTPUT ;
    USE SIGNAL ;
    PORT
      LAYER M4 ;
        RECT  36.528 36.336 36.72 36.36 ;
    END
  END dq[196]
  PIN dq[197]
    DIRECTION OUTPUT ;
    USE SIGNAL ;
    PORT
      LAYER M4 ;
        RECT  36.528 36.48 36.72 36.504 ;
    END
  END dq[197]
  PIN dq[198]
    DIRECTION OUTPUT ;
    USE SIGNAL ;
    PORT
      LAYER M4 ;
        RECT  36.528 36.624 36.72 36.648 ;
    END
  END dq[198]
  PIN dq[199]
    DIRECTION OUTPUT ;
    USE SIGNAL ;
    PORT
      LAYER M4 ;
        RECT  36.528 36.816 36.72 36.84 ;
    END
  END dq[199]
  PIN dq[19]
    DIRECTION OUTPUT ;
    USE SIGNAL ;
    PORT
      LAYER M4 ;
        RECT  36.528 7.488 36.72 7.512 ;
    END
  END dq[19]
  PIN dq[1]
    DIRECTION OUTPUT ;
    USE SIGNAL ;
    PORT
      LAYER M4 ;
        RECT  36.528 4.56 36.72 4.584 ;
    END
  END dq[1]
  PIN dq[200]
    DIRECTION OUTPUT ;
    USE SIGNAL ;
    PORT
      LAYER M4 ;
        RECT  36.528 36.96 36.72 36.984 ;
    END
  END dq[200]
  PIN dq[201]
    DIRECTION OUTPUT ;
    USE SIGNAL ;
    PORT
      LAYER M4 ;
        RECT  36.528 37.152 36.72 37.176 ;
    END
  END dq[201]
  PIN dq[202]
    DIRECTION OUTPUT ;
    USE SIGNAL ;
    PORT
      LAYER M4 ;
        RECT  36.528 37.296 36.72 37.32 ;
    END
  END dq[202]
  PIN dq[203]
    DIRECTION OUTPUT ;
    USE SIGNAL ;
    PORT
      LAYER M4 ;
        RECT  36.528 37.44 36.72 37.464 ;
    END
  END dq[203]
  PIN dq[204]
    DIRECTION OUTPUT ;
    USE SIGNAL ;
    PORT
      LAYER M4 ;
        RECT  36.528 37.632 36.72 37.656 ;
    END
  END dq[204]
  PIN dq[205]
    DIRECTION OUTPUT ;
    USE SIGNAL ;
    PORT
      LAYER M4 ;
        RECT  36.528 37.776 36.72 37.8 ;
    END
  END dq[205]
  PIN dq[206]
    DIRECTION OUTPUT ;
    USE SIGNAL ;
    PORT
      LAYER M4 ;
        RECT  36.528 37.968 36.72 37.992 ;
    END
  END dq[206]
  PIN dq[207]
    DIRECTION OUTPUT ;
    USE SIGNAL ;
    PORT
      LAYER M4 ;
        RECT  36.528 38.112 36.72 38.136 ;
    END
  END dq[207]
  PIN dq[208]
    DIRECTION OUTPUT ;
    USE SIGNAL ;
    PORT
      LAYER M4 ;
        RECT  36.528 38.256 36.72 38.28 ;
    END
  END dq[208]
  PIN dq[209]
    DIRECTION OUTPUT ;
    USE SIGNAL ;
    PORT
      LAYER M4 ;
        RECT  36.528 38.448 36.72 38.472 ;
    END
  END dq[209]
  PIN dq[20]
    DIRECTION OUTPUT ;
    USE SIGNAL ;
    PORT
      LAYER M4 ;
        RECT  36.528 7.68 36.72 7.704 ;
    END
  END dq[20]
  PIN dq[210]
    DIRECTION OUTPUT ;
    USE SIGNAL ;
    PORT
      LAYER M4 ;
        RECT  36.528 38.592 36.72 38.616 ;
    END
  END dq[210]
  PIN dq[211]
    DIRECTION OUTPUT ;
    USE SIGNAL ;
    PORT
      LAYER M4 ;
        RECT  36.528 38.784 36.72 38.808 ;
    END
  END dq[211]
  PIN dq[212]
    DIRECTION OUTPUT ;
    USE SIGNAL ;
    PORT
      LAYER M4 ;
        RECT  36.528 38.928 36.72 38.952 ;
    END
  END dq[212]
  PIN dq[213]
    DIRECTION OUTPUT ;
    USE SIGNAL ;
    PORT
      LAYER M4 ;
        RECT  36.528 39.072 36.72 39.096 ;
    END
  END dq[213]
  PIN dq[214]
    DIRECTION OUTPUT ;
    USE SIGNAL ;
    PORT
      LAYER M4 ;
        RECT  36.528 39.264 36.72 39.288 ;
    END
  END dq[214]
  PIN dq[215]
    DIRECTION OUTPUT ;
    USE SIGNAL ;
    PORT
      LAYER M4 ;
        RECT  36.528 39.408 36.72 39.432 ;
    END
  END dq[215]
  PIN dq[216]
    DIRECTION OUTPUT ;
    USE SIGNAL ;
    PORT
      LAYER M4 ;
        RECT  36.528 39.552 36.72 39.576 ;
    END
  END dq[216]
  PIN dq[217]
    DIRECTION OUTPUT ;
    USE SIGNAL ;
    PORT
      LAYER M4 ;
        RECT  36.528 39.744 36.72 39.768 ;
    END
  END dq[217]
  PIN dq[218]
    DIRECTION OUTPUT ;
    USE SIGNAL ;
    PORT
      LAYER M4 ;
        RECT  36.528 39.888 36.72 39.912 ;
    END
  END dq[218]
  PIN dq[219]
    DIRECTION OUTPUT ;
    USE SIGNAL ;
    PORT
      LAYER M4 ;
        RECT  36.528 40.08 36.72 40.104 ;
    END
  END dq[219]
  PIN dq[21]
    DIRECTION OUTPUT ;
    USE SIGNAL ;
    PORT
      LAYER M4 ;
        RECT  36.528 7.824 36.72 7.848 ;
    END
  END dq[21]
  PIN dq[220]
    DIRECTION OUTPUT ;
    USE SIGNAL ;
    PORT
      LAYER M4 ;
        RECT  36.528 40.224 36.72 40.248 ;
    END
  END dq[220]
  PIN dq[221]
    DIRECTION OUTPUT ;
    USE SIGNAL ;
    PORT
      LAYER M4 ;
        RECT  36.528 40.368 36.72 40.392 ;
    END
  END dq[221]
  PIN dq[222]
    DIRECTION OUTPUT ;
    USE SIGNAL ;
    PORT
      LAYER M4 ;
        RECT  36.528 40.56 36.72 40.584 ;
    END
  END dq[222]
  PIN dq[223]
    DIRECTION OUTPUT ;
    USE SIGNAL ;
    PORT
      LAYER M4 ;
        RECT  36.528 40.704 36.72 40.728 ;
    END
  END dq[223]
  PIN dq[224]
    DIRECTION OUTPUT ;
    USE SIGNAL ;
    PORT
      LAYER M4 ;
        RECT  36.528 40.896 36.72 40.92 ;
    END
  END dq[224]
  PIN dq[225]
    DIRECTION OUTPUT ;
    USE SIGNAL ;
    PORT
      LAYER M4 ;
        RECT  36.528 41.04 36.72 41.064 ;
    END
  END dq[225]
  PIN dq[226]
    DIRECTION OUTPUT ;
    USE SIGNAL ;
    PORT
      LAYER M4 ;
        RECT  36.528 41.184 36.72 41.208 ;
    END
  END dq[226]
  PIN dq[227]
    DIRECTION OUTPUT ;
    USE SIGNAL ;
    PORT
      LAYER M4 ;
        RECT  36.528 41.376 36.72 41.4 ;
    END
  END dq[227]
  PIN dq[228]
    DIRECTION OUTPUT ;
    USE SIGNAL ;
    PORT
      LAYER M4 ;
        RECT  36.528 41.52 36.72 41.544 ;
    END
  END dq[228]
  PIN dq[229]
    DIRECTION OUTPUT ;
    USE SIGNAL ;
    PORT
      LAYER M4 ;
        RECT  36.528 41.712 36.72 41.736 ;
    END
  END dq[229]
  PIN dq[22]
    DIRECTION OUTPUT ;
    USE SIGNAL ;
    PORT
      LAYER M4 ;
        RECT  36.528 8.016 36.72 8.04 ;
    END
  END dq[22]
  PIN dq[230]
    DIRECTION OUTPUT ;
    USE SIGNAL ;
    PORT
      LAYER M4 ;
        RECT  36.528 41.856 36.72 41.88 ;
    END
  END dq[230]
  PIN dq[231]
    DIRECTION OUTPUT ;
    USE SIGNAL ;
    PORT
      LAYER M4 ;
        RECT  36.528 42 36.72 42.024 ;
    END
  END dq[231]
  PIN dq[232]
    DIRECTION OUTPUT ;
    USE SIGNAL ;
    PORT
      LAYER M4 ;
        RECT  36.528 42.192 36.72 42.216 ;
    END
  END dq[232]
  PIN dq[233]
    DIRECTION OUTPUT ;
    USE SIGNAL ;
    PORT
      LAYER M4 ;
        RECT  36.528 42.336 36.72 42.36 ;
    END
  END dq[233]
  PIN dq[234]
    DIRECTION OUTPUT ;
    USE SIGNAL ;
    PORT
      LAYER M4 ;
        RECT  36.528 42.528 36.72 42.552 ;
    END
  END dq[234]
  PIN dq[235]
    DIRECTION OUTPUT ;
    USE SIGNAL ;
    PORT
      LAYER M4 ;
        RECT  36.528 42.672 36.72 42.696 ;
    END
  END dq[235]
  PIN dq[236]
    DIRECTION OUTPUT ;
    USE SIGNAL ;
    PORT
      LAYER M4 ;
        RECT  36.528 42.816 36.72 42.84 ;
    END
  END dq[236]
  PIN dq[237]
    DIRECTION OUTPUT ;
    USE SIGNAL ;
    PORT
      LAYER M4 ;
        RECT  36.528 43.008 36.72 43.032 ;
    END
  END dq[237]
  PIN dq[238]
    DIRECTION OUTPUT ;
    USE SIGNAL ;
    PORT
      LAYER M4 ;
        RECT  36.528 43.152 36.72 43.176 ;
    END
  END dq[238]
  PIN dq[239]
    DIRECTION OUTPUT ;
    USE SIGNAL ;
    PORT
      LAYER M4 ;
        RECT  36.528 43.296 36.72 43.32 ;
    END
  END dq[239]
  PIN dq[23]
    DIRECTION OUTPUT ;
    USE SIGNAL ;
    PORT
      LAYER M4 ;
        RECT  36.528 8.16 36.72 8.184 ;
    END
  END dq[23]
  PIN dq[240]
    DIRECTION OUTPUT ;
    USE SIGNAL ;
    PORT
      LAYER M4 ;
        RECT  36.528 43.488 36.72 43.512 ;
    END
  END dq[240]
  PIN dq[241]
    DIRECTION OUTPUT ;
    USE SIGNAL ;
    PORT
      LAYER M4 ;
        RECT  36.528 43.632 36.72 43.656 ;
    END
  END dq[241]
  PIN dq[242]
    DIRECTION OUTPUT ;
    USE SIGNAL ;
    PORT
      LAYER M4 ;
        RECT  36.528 43.824 36.72 43.848 ;
    END
  END dq[242]
  PIN dq[243]
    DIRECTION OUTPUT ;
    USE SIGNAL ;
    PORT
      LAYER M4 ;
        RECT  36.528 43.968 36.72 43.992 ;
    END
  END dq[243]
  PIN dq[244]
    DIRECTION OUTPUT ;
    USE SIGNAL ;
    PORT
      LAYER M4 ;
        RECT  36.528 44.112 36.72 44.136 ;
    END
  END dq[244]
  PIN dq[245]
    DIRECTION OUTPUT ;
    USE SIGNAL ;
    PORT
      LAYER M4 ;
        RECT  36.528 44.304 36.72 44.328 ;
    END
  END dq[245]
  PIN dq[246]
    DIRECTION OUTPUT ;
    USE SIGNAL ;
    PORT
      LAYER M4 ;
        RECT  36.528 44.448 36.72 44.472 ;
    END
  END dq[246]
  PIN dq[247]
    DIRECTION OUTPUT ;
    USE SIGNAL ;
    PORT
      LAYER M4 ;
        RECT  36.528 44.64 36.72 44.664 ;
    END
  END dq[247]
  PIN dq[248]
    DIRECTION OUTPUT ;
    USE SIGNAL ;
    PORT
      LAYER M4 ;
        RECT  36.528 44.784 36.72 44.808 ;
    END
  END dq[248]
  PIN dq[249]
    DIRECTION OUTPUT ;
    USE SIGNAL ;
    PORT
      LAYER M4 ;
        RECT  36.528 44.928 36.72 44.952 ;
    END
  END dq[249]
  PIN dq[24]
    DIRECTION OUTPUT ;
    USE SIGNAL ;
    PORT
      LAYER M4 ;
        RECT  36.528 8.304 36.72 8.328 ;
    END
  END dq[24]
  PIN dq[250]
    DIRECTION OUTPUT ;
    USE SIGNAL ;
    PORT
      LAYER M4 ;
        RECT  36.528 45.12 36.72 45.144 ;
    END
  END dq[250]
  PIN dq[251]
    DIRECTION OUTPUT ;
    USE SIGNAL ;
    PORT
      LAYER M4 ;
        RECT  36.528 45.264 36.72 45.288 ;
    END
  END dq[251]
  PIN dq[252]
    DIRECTION OUTPUT ;
    USE SIGNAL ;
    PORT
      LAYER M4 ;
        RECT  36.528 45.456 36.72 45.48 ;
    END
  END dq[252]
  PIN dq[253]
    DIRECTION OUTPUT ;
    USE SIGNAL ;
    PORT
      LAYER M4 ;
        RECT  36.528 45.6 36.72 45.624 ;
    END
  END dq[253]
  PIN dq[254]
    DIRECTION OUTPUT ;
    USE SIGNAL ;
    PORT
      LAYER M4 ;
        RECT  36.528 45.744 36.72 45.768 ;
    END
  END dq[254]
  PIN dq[255]
    DIRECTION OUTPUT ;
    USE SIGNAL ;
    PORT
      LAYER M4 ;
        RECT  36.528 45.936 36.72 45.96 ;
    END
  END dq[255]
  PIN dq[256]
    DIRECTION OUTPUT ;
    USE SIGNAL ;
    PORT
      LAYER M4 ;
        RECT  36.528 46.08 36.72 46.104 ;
    END
  END dq[256]
  PIN dq[257]
    DIRECTION OUTPUT ;
    USE SIGNAL ;
    PORT
      LAYER M4 ;
        RECT  36.528 46.272 36.72 46.296 ;
    END
  END dq[257]
  PIN dq[258]
    DIRECTION OUTPUT ;
    USE SIGNAL ;
    PORT
      LAYER M4 ;
        RECT  36.528 46.416 36.72 46.44 ;
    END
  END dq[258]
  PIN dq[259]
    DIRECTION OUTPUT ;
    USE SIGNAL ;
    PORT
      LAYER M4 ;
        RECT  36.528 46.56 36.72 46.584 ;
    END
  END dq[259]
  PIN dq[25]
    DIRECTION OUTPUT ;
    USE SIGNAL ;
    PORT
      LAYER M4 ;
        RECT  36.528 8.496 36.72 8.52 ;
    END
  END dq[25]
  PIN dq[260]
    DIRECTION OUTPUT ;
    USE SIGNAL ;
    PORT
      LAYER M4 ;
        RECT  36.528 46.752 36.72 46.776 ;
    END
  END dq[260]
  PIN dq[261]
    DIRECTION OUTPUT ;
    USE SIGNAL ;
    PORT
      LAYER M4 ;
        RECT  36.528 46.896 36.72 46.92 ;
    END
  END dq[261]
  PIN dq[262]
    DIRECTION OUTPUT ;
    USE SIGNAL ;
    PORT
      LAYER M4 ;
        RECT  36.528 47.04 36.72 47.064 ;
    END
  END dq[262]
  PIN dq[263]
    DIRECTION OUTPUT ;
    USE SIGNAL ;
    PORT
      LAYER M4 ;
        RECT  36.528 47.232 36.72 47.256 ;
    END
  END dq[263]
  PIN dq[264]
    DIRECTION OUTPUT ;
    USE SIGNAL ;
    PORT
      LAYER M4 ;
        RECT  36.528 47.376 36.72 47.4 ;
    END
  END dq[264]
  PIN dq[265]
    DIRECTION OUTPUT ;
    USE SIGNAL ;
    PORT
      LAYER M4 ;
        RECT  36.528 47.568 36.72 47.592 ;
    END
  END dq[265]
  PIN dq[266]
    DIRECTION OUTPUT ;
    USE SIGNAL ;
    PORT
      LAYER M4 ;
        RECT  36.528 47.712 36.72 47.736 ;
    END
  END dq[266]
  PIN dq[267]
    DIRECTION OUTPUT ;
    USE SIGNAL ;
    PORT
      LAYER M4 ;
        RECT  36.528 47.856 36.72 47.88 ;
    END
  END dq[267]
  PIN dq[268]
    DIRECTION OUTPUT ;
    USE SIGNAL ;
    PORT
      LAYER M4 ;
        RECT  36.528 48.048 36.72 48.072 ;
    END
  END dq[268]
  PIN dq[269]
    DIRECTION OUTPUT ;
    USE SIGNAL ;
    PORT
      LAYER M4 ;
        RECT  36.528 48.192 36.72 48.216 ;
    END
  END dq[269]
  PIN dq[26]
    DIRECTION OUTPUT ;
    USE SIGNAL ;
    PORT
      LAYER M4 ;
        RECT  36.528 8.64 36.72 8.664 ;
    END
  END dq[26]
  PIN dq[270]
    DIRECTION OUTPUT ;
    USE SIGNAL ;
    PORT
      LAYER M4 ;
        RECT  36.528 48.384 36.72 48.408 ;
    END
  END dq[270]
  PIN dq[271]
    DIRECTION OUTPUT ;
    USE SIGNAL ;
    PORT
      LAYER M4 ;
        RECT  36.528 48.528 36.72 48.552 ;
    END
  END dq[271]
  PIN dq[272]
    DIRECTION OUTPUT ;
    USE SIGNAL ;
    PORT
      LAYER M4 ;
        RECT  36.528 48.672 36.72 48.696 ;
    END
  END dq[272]
  PIN dq[273]
    DIRECTION OUTPUT ;
    USE SIGNAL ;
    PORT
      LAYER M4 ;
        RECT  36.528 48.864 36.72 48.888 ;
    END
  END dq[273]
  PIN dq[274]
    DIRECTION OUTPUT ;
    USE SIGNAL ;
    PORT
      LAYER M4 ;
        RECT  36.528 49.008 36.72 49.032 ;
    END
  END dq[274]
  PIN dq[275]
    DIRECTION OUTPUT ;
    USE SIGNAL ;
    PORT
      LAYER M4 ;
        RECT  36.528 49.2 36.72 49.224 ;
    END
  END dq[275]
  PIN dq[276]
    DIRECTION OUTPUT ;
    USE SIGNAL ;
    PORT
      LAYER M4 ;
        RECT  36.528 49.344 36.72 49.368 ;
    END
  END dq[276]
  PIN dq[277]
    DIRECTION OUTPUT ;
    USE SIGNAL ;
    PORT
      LAYER M4 ;
        RECT  36.528 49.488 36.72 49.512 ;
    END
  END dq[277]
  PIN dq[278]
    DIRECTION OUTPUT ;
    USE SIGNAL ;
    PORT
      LAYER M4 ;
        RECT  36.528 49.68 36.72 49.704 ;
    END
  END dq[278]
  PIN dq[279]
    DIRECTION OUTPUT ;
    USE SIGNAL ;
    PORT
      LAYER M4 ;
        RECT  36.528 49.824 36.72 49.848 ;
    END
  END dq[279]
  PIN dq[27]
    DIRECTION OUTPUT ;
    USE SIGNAL ;
    PORT
      LAYER M4 ;
        RECT  36.528 8.832 36.72 8.856 ;
    END
  END dq[27]
  PIN dq[280]
    DIRECTION OUTPUT ;
    USE SIGNAL ;
    PORT
      LAYER M4 ;
        RECT  36.528 50.016 36.72 50.04 ;
    END
  END dq[280]
  PIN dq[281]
    DIRECTION OUTPUT ;
    USE SIGNAL ;
    PORT
      LAYER M4 ;
        RECT  36.528 50.16 36.72 50.184 ;
    END
  END dq[281]
  PIN dq[282]
    DIRECTION OUTPUT ;
    USE SIGNAL ;
    PORT
      LAYER M4 ;
        RECT  36.528 50.304 36.72 50.328 ;
    END
  END dq[282]
  PIN dq[283]
    DIRECTION OUTPUT ;
    USE SIGNAL ;
    PORT
      LAYER M4 ;
        RECT  36.528 50.496 36.72 50.52 ;
    END
  END dq[283]
  PIN dq[284]
    DIRECTION OUTPUT ;
    USE SIGNAL ;
    PORT
      LAYER M4 ;
        RECT  36.528 50.64 36.72 50.664 ;
    END
  END dq[284]
  PIN dq[285]
    DIRECTION OUTPUT ;
    USE SIGNAL ;
    PORT
      LAYER M4 ;
        RECT  36.528 50.784 36.72 50.808 ;
    END
  END dq[285]
  PIN dq[286]
    DIRECTION OUTPUT ;
    USE SIGNAL ;
    PORT
      LAYER M4 ;
        RECT  36.528 50.976 36.72 51 ;
    END
  END dq[286]
  PIN dq[287]
    DIRECTION OUTPUT ;
    USE SIGNAL ;
    PORT
      LAYER M4 ;
        RECT  36.528 51.12 36.72 51.144 ;
    END
  END dq[287]
  PIN dq[288]
    DIRECTION OUTPUT ;
    USE SIGNAL ;
    PORT
      LAYER M4 ;
        RECT  36.528 51.312 36.72 51.336 ;
    END
  END dq[288]
  PIN dq[289]
    DIRECTION OUTPUT ;
    USE SIGNAL ;
    PORT
      LAYER M4 ;
        RECT  36.528 51.456 36.72 51.48 ;
    END
  END dq[289]
  PIN dq[28]
    DIRECTION OUTPUT ;
    USE SIGNAL ;
    PORT
      LAYER M4 ;
        RECT  36.528 8.976 36.72 9 ;
    END
  END dq[28]
  PIN dq[290]
    DIRECTION OUTPUT ;
    USE SIGNAL ;
    PORT
      LAYER M4 ;
        RECT  36.528 51.6 36.72 51.624 ;
    END
  END dq[290]
  PIN dq[291]
    DIRECTION OUTPUT ;
    USE SIGNAL ;
    PORT
      LAYER M4 ;
        RECT  36.528 51.792 36.72 51.816 ;
    END
  END dq[291]
  PIN dq[292]
    DIRECTION OUTPUT ;
    USE SIGNAL ;
    PORT
      LAYER M4 ;
        RECT  36.528 51.936 36.72 51.96 ;
    END
  END dq[292]
  PIN dq[293]
    DIRECTION OUTPUT ;
    USE SIGNAL ;
    PORT
      LAYER M4 ;
        RECT  36.528 52.128 36.72 52.152 ;
    END
  END dq[293]
  PIN dq[294]
    DIRECTION OUTPUT ;
    USE SIGNAL ;
    PORT
      LAYER M4 ;
        RECT  36.528 52.272 36.72 52.296 ;
    END
  END dq[294]
  PIN dq[295]
    DIRECTION OUTPUT ;
    USE SIGNAL ;
    PORT
      LAYER M4 ;
        RECT  36.528 52.416 36.72 52.44 ;
    END
  END dq[295]
  PIN dq[296]
    DIRECTION OUTPUT ;
    USE SIGNAL ;
    PORT
      LAYER M4 ;
        RECT  36.528 52.608 36.72 52.632 ;
    END
  END dq[296]
  PIN dq[297]
    DIRECTION OUTPUT ;
    USE SIGNAL ;
    PORT
      LAYER M4 ;
        RECT  36.528 52.752 36.72 52.776 ;
    END
  END dq[297]
  PIN dq[298]
    DIRECTION OUTPUT ;
    USE SIGNAL ;
    PORT
      LAYER M4 ;
        RECT  36.528 52.944 36.72 52.968 ;
    END
  END dq[298]
  PIN dq[299]
    DIRECTION OUTPUT ;
    USE SIGNAL ;
    PORT
      LAYER M4 ;
        RECT  36.528 53.088 36.72 53.112 ;
    END
  END dq[299]
  PIN dq[29]
    DIRECTION OUTPUT ;
    USE SIGNAL ;
    PORT
      LAYER M4 ;
        RECT  36.528 9.12 36.72 9.144 ;
    END
  END dq[29]
  PIN dq[2]
    DIRECTION OUTPUT ;
    USE SIGNAL ;
    PORT
      LAYER M4 ;
        RECT  36.528 4.752 36.72 4.776 ;
    END
  END dq[2]
  PIN dq[300]
    DIRECTION OUTPUT ;
    USE SIGNAL ;
    PORT
      LAYER M4 ;
        RECT  36.528 53.232 36.72 53.256 ;
    END
  END dq[300]
  PIN dq[301]
    DIRECTION OUTPUT ;
    USE SIGNAL ;
    PORT
      LAYER M4 ;
        RECT  36.528 53.424 36.72 53.448 ;
    END
  END dq[301]
  PIN dq[302]
    DIRECTION OUTPUT ;
    USE SIGNAL ;
    PORT
      LAYER M4 ;
        RECT  36.528 53.568 36.72 53.592 ;
    END
  END dq[302]
  PIN dq[303]
    DIRECTION OUTPUT ;
    USE SIGNAL ;
    PORT
      LAYER M4 ;
        RECT  36.528 53.76 36.72 53.784 ;
    END
  END dq[303]
  PIN dq[304]
    DIRECTION OUTPUT ;
    USE SIGNAL ;
    PORT
      LAYER M4 ;
        RECT  36.528 53.904 36.72 53.928 ;
    END
  END dq[304]
  PIN dq[305]
    DIRECTION OUTPUT ;
    USE SIGNAL ;
    PORT
      LAYER M4 ;
        RECT  36.528 54.048 36.72 54.072 ;
    END
  END dq[305]
  PIN dq[306]
    DIRECTION OUTPUT ;
    USE SIGNAL ;
    PORT
      LAYER M4 ;
        RECT  36.528 54.24 36.72 54.264 ;
    END
  END dq[306]
  PIN dq[307]
    DIRECTION OUTPUT ;
    USE SIGNAL ;
    PORT
      LAYER M4 ;
        RECT  36.528 54.384 36.72 54.408 ;
    END
  END dq[307]
  PIN dq[308]
    DIRECTION OUTPUT ;
    USE SIGNAL ;
    PORT
      LAYER M4 ;
        RECT  36.528 54.528 36.72 54.552 ;
    END
  END dq[308]
  PIN dq[309]
    DIRECTION OUTPUT ;
    USE SIGNAL ;
    PORT
      LAYER M4 ;
        RECT  36.528 54.72 36.72 54.744 ;
    END
  END dq[309]
  PIN dq[30]
    DIRECTION OUTPUT ;
    USE SIGNAL ;
    PORT
      LAYER M4 ;
        RECT  36.528 9.312 36.72 9.336 ;
    END
  END dq[30]
  PIN dq[310]
    DIRECTION OUTPUT ;
    USE SIGNAL ;
    PORT
      LAYER M4 ;
        RECT  36.528 54.864 36.72 54.888 ;
    END
  END dq[310]
  PIN dq[311]
    DIRECTION OUTPUT ;
    USE SIGNAL ;
    PORT
      LAYER M4 ;
        RECT  36.528 55.056 36.72 55.08 ;
    END
  END dq[311]
  PIN dq[312]
    DIRECTION OUTPUT ;
    USE SIGNAL ;
    PORT
      LAYER M4 ;
        RECT  36.528 55.2 36.72 55.224 ;
    END
  END dq[312]
  PIN dq[313]
    DIRECTION OUTPUT ;
    USE SIGNAL ;
    PORT
      LAYER M4 ;
        RECT  36.528 55.344 36.72 55.368 ;
    END
  END dq[313]
  PIN dq[314]
    DIRECTION OUTPUT ;
    USE SIGNAL ;
    PORT
      LAYER M4 ;
        RECT  36.528 55.536 36.72 55.56 ;
    END
  END dq[314]
  PIN dq[315]
    DIRECTION OUTPUT ;
    USE SIGNAL ;
    PORT
      LAYER M4 ;
        RECT  36.528 55.68 36.72 55.704 ;
    END
  END dq[315]
  PIN dq[316]
    DIRECTION OUTPUT ;
    USE SIGNAL ;
    PORT
      LAYER M4 ;
        RECT  36.528 55.872 36.72 55.896 ;
    END
  END dq[316]
  PIN dq[317]
    DIRECTION OUTPUT ;
    USE SIGNAL ;
    PORT
      LAYER M4 ;
        RECT  36.528 56.016 36.72 56.04 ;
    END
  END dq[317]
  PIN dq[318]
    DIRECTION OUTPUT ;
    USE SIGNAL ;
    PORT
      LAYER M4 ;
        RECT  36.528 56.16 36.72 56.184 ;
    END
  END dq[318]
  PIN dq[319]
    DIRECTION OUTPUT ;
    USE SIGNAL ;
    PORT
      LAYER M4 ;
        RECT  36.528 56.352 36.72 56.376 ;
    END
  END dq[319]
  PIN dq[31]
    DIRECTION OUTPUT ;
    USE SIGNAL ;
    PORT
      LAYER M4 ;
        RECT  36.528 9.456 36.72 9.48 ;
    END
  END dq[31]
  PIN dq[320]
    DIRECTION OUTPUT ;
    USE SIGNAL ;
    PORT
      LAYER M4 ;
        RECT  36.528 56.496 36.72 56.52 ;
    END
  END dq[320]
  PIN dq[321]
    DIRECTION OUTPUT ;
    USE SIGNAL ;
    PORT
      LAYER M4 ;
        RECT  36.528 56.688 36.72 56.712 ;
    END
  END dq[321]
  PIN dq[322]
    DIRECTION OUTPUT ;
    USE SIGNAL ;
    PORT
      LAYER M4 ;
        RECT  36.528 56.832 36.72 56.856 ;
    END
  END dq[322]
  PIN dq[323]
    DIRECTION OUTPUT ;
    USE SIGNAL ;
    PORT
      LAYER M4 ;
        RECT  36.528 56.976 36.72 57 ;
    END
  END dq[323]
  PIN dq[324]
    DIRECTION OUTPUT ;
    USE SIGNAL ;
    PORT
      LAYER M4 ;
        RECT  36.528 57.168 36.72 57.192 ;
    END
  END dq[324]
  PIN dq[325]
    DIRECTION OUTPUT ;
    USE SIGNAL ;
    PORT
      LAYER M4 ;
        RECT  36.528 57.312 36.72 57.336 ;
    END
  END dq[325]
  PIN dq[326]
    DIRECTION OUTPUT ;
    USE SIGNAL ;
    PORT
      LAYER M4 ;
        RECT  36.528 57.504 36.72 57.528 ;
    END
  END dq[326]
  PIN dq[327]
    DIRECTION OUTPUT ;
    USE SIGNAL ;
    PORT
      LAYER M4 ;
        RECT  36.528 57.648 36.72 57.672 ;
    END
  END dq[327]
  PIN dq[328]
    DIRECTION OUTPUT ;
    USE SIGNAL ;
    PORT
      LAYER M4 ;
        RECT  36.528 57.792 36.72 57.816 ;
    END
  END dq[328]
  PIN dq[329]
    DIRECTION OUTPUT ;
    USE SIGNAL ;
    PORT
      LAYER M4 ;
        RECT  36.528 57.984 36.72 58.008 ;
    END
  END dq[329]
  PIN dq[32]
    DIRECTION OUTPUT ;
    USE SIGNAL ;
    PORT
      LAYER M4 ;
        RECT  36.528 9.6 36.72 9.624 ;
    END
  END dq[32]
  PIN dq[330]
    DIRECTION OUTPUT ;
    USE SIGNAL ;
    PORT
      LAYER M4 ;
        RECT  36.528 58.128 36.72 58.152 ;
    END
  END dq[330]
  PIN dq[331]
    DIRECTION OUTPUT ;
    USE SIGNAL ;
    PORT
      LAYER M4 ;
        RECT  36.528 58.272 36.72 58.296 ;
    END
  END dq[331]
  PIN dq[332]
    DIRECTION OUTPUT ;
    USE SIGNAL ;
    PORT
      LAYER M4 ;
        RECT  36.528 58.464 36.72 58.488 ;
    END
  END dq[332]
  PIN dq[333]
    DIRECTION OUTPUT ;
    USE SIGNAL ;
    PORT
      LAYER M4 ;
        RECT  36.528 58.608 36.72 58.632 ;
    END
  END dq[333]
  PIN dq[334]
    DIRECTION OUTPUT ;
    USE SIGNAL ;
    PORT
      LAYER M4 ;
        RECT  36.528 58.8 36.72 58.824 ;
    END
  END dq[334]
  PIN dq[335]
    DIRECTION OUTPUT ;
    USE SIGNAL ;
    PORT
      LAYER M4 ;
        RECT  36.528 58.944 36.72 58.968 ;
    END
  END dq[335]
  PIN dq[336]
    DIRECTION OUTPUT ;
    USE SIGNAL ;
    PORT
      LAYER M4 ;
        RECT  36.528 59.088 36.72 59.112 ;
    END
  END dq[336]
  PIN dq[337]
    DIRECTION OUTPUT ;
    USE SIGNAL ;
    PORT
      LAYER M4 ;
        RECT  36.528 59.28 36.72 59.304 ;
    END
  END dq[337]
  PIN dq[338]
    DIRECTION OUTPUT ;
    USE SIGNAL ;
    PORT
      LAYER M4 ;
        RECT  36.528 59.424 36.72 59.448 ;
    END
  END dq[338]
  PIN dq[339]
    DIRECTION OUTPUT ;
    USE SIGNAL ;
    PORT
      LAYER M4 ;
        RECT  36.528 59.616 36.72 59.64 ;
    END
  END dq[339]
  PIN dq[33]
    DIRECTION OUTPUT ;
    USE SIGNAL ;
    PORT
      LAYER M4 ;
        RECT  36.528 9.792 36.72 9.816 ;
    END
  END dq[33]
  PIN dq[340]
    DIRECTION OUTPUT ;
    USE SIGNAL ;
    PORT
      LAYER M4 ;
        RECT  36.528 59.76 36.72 59.784 ;
    END
  END dq[340]
  PIN dq[341]
    DIRECTION OUTPUT ;
    USE SIGNAL ;
    PORT
      LAYER M4 ;
        RECT  36.528 59.904 36.72 59.928 ;
    END
  END dq[341]
  PIN dq[342]
    DIRECTION OUTPUT ;
    USE SIGNAL ;
    PORT
      LAYER M4 ;
        RECT  36.528 60.096 36.72 60.12 ;
    END
  END dq[342]
  PIN dq[343]
    DIRECTION OUTPUT ;
    USE SIGNAL ;
    PORT
      LAYER M4 ;
        RECT  36.528 60.24 36.72 60.264 ;
    END
  END dq[343]
  PIN dq[344]
    DIRECTION OUTPUT ;
    USE SIGNAL ;
    PORT
      LAYER M4 ;
        RECT  36.528 60.432 36.72 60.456 ;
    END
  END dq[344]
  PIN dq[345]
    DIRECTION OUTPUT ;
    USE SIGNAL ;
    PORT
      LAYER M4 ;
        RECT  36.528 60.576 36.72 60.6 ;
    END
  END dq[345]
  PIN dq[346]
    DIRECTION OUTPUT ;
    USE SIGNAL ;
    PORT
      LAYER M4 ;
        RECT  36.528 60.72 36.72 60.744 ;
    END
  END dq[346]
  PIN dq[347]
    DIRECTION OUTPUT ;
    USE SIGNAL ;
    PORT
      LAYER M4 ;
        RECT  36.528 60.912 36.72 60.936 ;
    END
  END dq[347]
  PIN dq[348]
    DIRECTION OUTPUT ;
    USE SIGNAL ;
    PORT
      LAYER M4 ;
        RECT  36.528 61.056 36.72 61.08 ;
    END
  END dq[348]
  PIN dq[349]
    DIRECTION OUTPUT ;
    USE SIGNAL ;
    PORT
      LAYER M4 ;
        RECT  36.528 61.248 36.72 61.272 ;
    END
  END dq[349]
  PIN dq[34]
    DIRECTION OUTPUT ;
    USE SIGNAL ;
    PORT
      LAYER M4 ;
        RECT  36.528 9.936 36.72 9.96 ;
    END
  END dq[34]
  PIN dq[350]
    DIRECTION OUTPUT ;
    USE SIGNAL ;
    PORT
      LAYER M4 ;
        RECT  36.528 61.392 36.72 61.416 ;
    END
  END dq[350]
  PIN dq[351]
    DIRECTION OUTPUT ;
    USE SIGNAL ;
    PORT
      LAYER M4 ;
        RECT  36.528 61.536 36.72 61.56 ;
    END
  END dq[351]
  PIN dq[352]
    DIRECTION OUTPUT ;
    USE SIGNAL ;
    PORT
      LAYER M4 ;
        RECT  36.528 61.728 36.72 61.752 ;
    END
  END dq[352]
  PIN dq[353]
    DIRECTION OUTPUT ;
    USE SIGNAL ;
    PORT
      LAYER M4 ;
        RECT  36.528 61.872 36.72 61.896 ;
    END
  END dq[353]
  PIN dq[354]
    DIRECTION OUTPUT ;
    USE SIGNAL ;
    PORT
      LAYER M4 ;
        RECT  36.528 62.016 36.72 62.04 ;
    END
  END dq[354]
  PIN dq[355]
    DIRECTION OUTPUT ;
    USE SIGNAL ;
    PORT
      LAYER M4 ;
        RECT  36.528 62.208 36.72 62.232 ;
    END
  END dq[355]
  PIN dq[356]
    DIRECTION OUTPUT ;
    USE SIGNAL ;
    PORT
      LAYER M4 ;
        RECT  36.528 62.352 36.72 62.376 ;
    END
  END dq[356]
  PIN dq[357]
    DIRECTION OUTPUT ;
    USE SIGNAL ;
    PORT
      LAYER M4 ;
        RECT  36.528 62.544 36.72 62.568 ;
    END
  END dq[357]
  PIN dq[358]
    DIRECTION OUTPUT ;
    USE SIGNAL ;
    PORT
      LAYER M4 ;
        RECT  36.528 62.688 36.72 62.712 ;
    END
  END dq[358]
  PIN dq[359]
    DIRECTION OUTPUT ;
    USE SIGNAL ;
    PORT
      LAYER M4 ;
        RECT  36.528 62.832 36.72 62.856 ;
    END
  END dq[359]
  PIN dq[35]
    DIRECTION OUTPUT ;
    USE SIGNAL ;
    PORT
      LAYER M4 ;
        RECT  36.528 10.128 36.72 10.152 ;
    END
  END dq[35]
  PIN dq[360]
    DIRECTION OUTPUT ;
    USE SIGNAL ;
    PORT
      LAYER M4 ;
        RECT  36.528 63.024 36.72 63.048 ;
    END
  END dq[360]
  PIN dq[361]
    DIRECTION OUTPUT ;
    USE SIGNAL ;
    PORT
      LAYER M4 ;
        RECT  36.528 63.168 36.72 63.192 ;
    END
  END dq[361]
  PIN dq[362]
    DIRECTION OUTPUT ;
    USE SIGNAL ;
    PORT
      LAYER M4 ;
        RECT  36.528 63.36 36.72 63.384 ;
    END
  END dq[362]
  PIN dq[363]
    DIRECTION OUTPUT ;
    USE SIGNAL ;
    PORT
      LAYER M4 ;
        RECT  36.528 63.504 36.72 63.528 ;
    END
  END dq[363]
  PIN dq[364]
    DIRECTION OUTPUT ;
    USE SIGNAL ;
    PORT
      LAYER M4 ;
        RECT  36.528 63.648 36.72 63.672 ;
    END
  END dq[364]
  PIN dq[365]
    DIRECTION OUTPUT ;
    USE SIGNAL ;
    PORT
      LAYER M4 ;
        RECT  36.528 63.84 36.72 63.864 ;
    END
  END dq[365]
  PIN dq[366]
    DIRECTION OUTPUT ;
    USE SIGNAL ;
    PORT
      LAYER M4 ;
        RECT  36.528 63.984 36.72 64.008 ;
    END
  END dq[366]
  PIN dq[367]
    DIRECTION OUTPUT ;
    USE SIGNAL ;
    PORT
      LAYER M4 ;
        RECT  36.528 64.176 36.72 64.2 ;
    END
  END dq[367]
  PIN dq[368]
    DIRECTION OUTPUT ;
    USE SIGNAL ;
    PORT
      LAYER M4 ;
        RECT  36.528 64.32 36.72 64.344 ;
    END
  END dq[368]
  PIN dq[369]
    DIRECTION OUTPUT ;
    USE SIGNAL ;
    PORT
      LAYER M4 ;
        RECT  36.528 64.464 36.72 64.488 ;
    END
  END dq[369]
  PIN dq[36]
    DIRECTION OUTPUT ;
    USE SIGNAL ;
    PORT
      LAYER M4 ;
        RECT  36.528 10.272 36.72 10.296 ;
    END
  END dq[36]
  PIN dq[370]
    DIRECTION OUTPUT ;
    USE SIGNAL ;
    PORT
      LAYER M4 ;
        RECT  36.528 64.656 36.72 64.68 ;
    END
  END dq[370]
  PIN dq[371]
    DIRECTION OUTPUT ;
    USE SIGNAL ;
    PORT
      LAYER M4 ;
        RECT  36.528 64.8 36.72 64.824 ;
    END
  END dq[371]
  PIN dq[372]
    DIRECTION OUTPUT ;
    USE SIGNAL ;
    PORT
      LAYER M4 ;
        RECT  36.528 64.992 36.72 65.016 ;
    END
  END dq[372]
  PIN dq[373]
    DIRECTION OUTPUT ;
    USE SIGNAL ;
    PORT
      LAYER M4 ;
        RECT  36.528 65.136 36.72 65.16 ;
    END
  END dq[373]
  PIN dq[374]
    DIRECTION OUTPUT ;
    USE SIGNAL ;
    PORT
      LAYER M4 ;
        RECT  36.528 65.28 36.72 65.304 ;
    END
  END dq[374]
  PIN dq[375]
    DIRECTION OUTPUT ;
    USE SIGNAL ;
    PORT
      LAYER M4 ;
        RECT  36.528 65.472 36.72 65.496 ;
    END
  END dq[375]
  PIN dq[376]
    DIRECTION OUTPUT ;
    USE SIGNAL ;
    PORT
      LAYER M4 ;
        RECT  36.528 65.616 36.72 65.64 ;
    END
  END dq[376]
  PIN dq[377]
    DIRECTION OUTPUT ;
    USE SIGNAL ;
    PORT
      LAYER M4 ;
        RECT  36.528 65.76 36.72 65.784 ;
    END
  END dq[377]
  PIN dq[378]
    DIRECTION OUTPUT ;
    USE SIGNAL ;
    PORT
      LAYER M4 ;
        RECT  36.528 65.952 36.72 65.976 ;
    END
  END dq[378]
  PIN dq[379]
    DIRECTION OUTPUT ;
    USE SIGNAL ;
    PORT
      LAYER M4 ;
        RECT  36.528 66.096 36.72 66.12 ;
    END
  END dq[379]
  PIN dq[37]
    DIRECTION OUTPUT ;
    USE SIGNAL ;
    PORT
      LAYER M4 ;
        RECT  36.528 10.416 36.72 10.44 ;
    END
  END dq[37]
  PIN dq[380]
    DIRECTION OUTPUT ;
    USE SIGNAL ;
    PORT
      LAYER M4 ;
        RECT  36.528 66.288 36.72 66.312 ;
    END
  END dq[380]
  PIN dq[381]
    DIRECTION OUTPUT ;
    USE SIGNAL ;
    PORT
      LAYER M4 ;
        RECT  36.528 66.432 36.72 66.456 ;
    END
  END dq[381]
  PIN dq[382]
    DIRECTION OUTPUT ;
    USE SIGNAL ;
    PORT
      LAYER M4 ;
        RECT  36.528 66.576 36.72 66.6 ;
    END
  END dq[382]
  PIN dq[383]
    DIRECTION OUTPUT ;
    USE SIGNAL ;
    PORT
      LAYER M4 ;
        RECT  36.528 66.768 36.72 66.792 ;
    END
  END dq[383]
  PIN dq[384]
    DIRECTION OUTPUT ;
    USE SIGNAL ;
    PORT
      LAYER M4 ;
        RECT  36.528 66.912 36.72 66.936 ;
    END
  END dq[384]
  PIN dq[385]
    DIRECTION OUTPUT ;
    USE SIGNAL ;
    PORT
      LAYER M4 ;
        RECT  36.528 67.104 36.72 67.128 ;
    END
  END dq[385]
  PIN dq[386]
    DIRECTION OUTPUT ;
    USE SIGNAL ;
    PORT
      LAYER M4 ;
        RECT  36.528 67.248 36.72 67.272 ;
    END
  END dq[386]
  PIN dq[387]
    DIRECTION OUTPUT ;
    USE SIGNAL ;
    PORT
      LAYER M4 ;
        RECT  36.528 67.392 36.72 67.416 ;
    END
  END dq[387]
  PIN dq[388]
    DIRECTION OUTPUT ;
    USE SIGNAL ;
    PORT
      LAYER M4 ;
        RECT  36.528 67.584 36.72 67.608 ;
    END
  END dq[388]
  PIN dq[389]
    DIRECTION OUTPUT ;
    USE SIGNAL ;
    PORT
      LAYER M4 ;
        RECT  36.528 67.728 36.72 67.752 ;
    END
  END dq[389]
  PIN dq[38]
    DIRECTION OUTPUT ;
    USE SIGNAL ;
    PORT
      LAYER M4 ;
        RECT  36.528 10.608 36.72 10.632 ;
    END
  END dq[38]
  PIN dq[390]
    DIRECTION OUTPUT ;
    USE SIGNAL ;
    PORT
      LAYER M4 ;
        RECT  36.528 67.92 36.72 67.944 ;
    END
  END dq[390]
  PIN dq[391]
    DIRECTION OUTPUT ;
    USE SIGNAL ;
    PORT
      LAYER M4 ;
        RECT  36.528 68.064 36.72 68.088 ;
    END
  END dq[391]
  PIN dq[392]
    DIRECTION OUTPUT ;
    USE SIGNAL ;
    PORT
      LAYER M4 ;
        RECT  36.528 68.208 36.72 68.232 ;
    END
  END dq[392]
  PIN dq[393]
    DIRECTION OUTPUT ;
    USE SIGNAL ;
    PORT
      LAYER M4 ;
        RECT  36.528 68.4 36.72 68.424 ;
    END
  END dq[393]
  PIN dq[394]
    DIRECTION OUTPUT ;
    USE SIGNAL ;
    PORT
      LAYER M4 ;
        RECT  36.528 68.544 36.72 68.568 ;
    END
  END dq[394]
  PIN dq[395]
    DIRECTION OUTPUT ;
    USE SIGNAL ;
    PORT
      LAYER M4 ;
        RECT  36.528 68.736 36.72 68.76 ;
    END
  END dq[395]
  PIN dq[396]
    DIRECTION OUTPUT ;
    USE SIGNAL ;
    PORT
      LAYER M4 ;
        RECT  36.528 68.88 36.72 68.904 ;
    END
  END dq[396]
  PIN dq[397]
    DIRECTION OUTPUT ;
    USE SIGNAL ;
    PORT
      LAYER M4 ;
        RECT  36.528 69.024 36.72 69.048 ;
    END
  END dq[397]
  PIN dq[398]
    DIRECTION OUTPUT ;
    USE SIGNAL ;
    PORT
      LAYER M4 ;
        RECT  36.528 69.216 36.72 69.24 ;
    END
  END dq[398]
  PIN dq[399]
    DIRECTION OUTPUT ;
    USE SIGNAL ;
    PORT
      LAYER M4 ;
        RECT  36.528 69.36 36.72 69.384 ;
    END
  END dq[399]
  PIN dq[39]
    DIRECTION OUTPUT ;
    USE SIGNAL ;
    PORT
      LAYER M4 ;
        RECT  36.528 10.752 36.72 10.776 ;
    END
  END dq[39]
  PIN dq[3]
    DIRECTION OUTPUT ;
    USE SIGNAL ;
    PORT
      LAYER M4 ;
        RECT  36.528 4.896 36.72 4.92 ;
    END
  END dq[3]
  PIN dq[400]
    DIRECTION OUTPUT ;
    USE SIGNAL ;
    PORT
      LAYER M4 ;
        RECT  36.528 69.504 36.72 69.528 ;
    END
  END dq[400]
  PIN dq[401]
    DIRECTION OUTPUT ;
    USE SIGNAL ;
    PORT
      LAYER M4 ;
        RECT  36.528 69.696 36.72 69.72 ;
    END
  END dq[401]
  PIN dq[402]
    DIRECTION OUTPUT ;
    USE SIGNAL ;
    PORT
      LAYER M4 ;
        RECT  36.528 69.84 36.72 69.864 ;
    END
  END dq[402]
  PIN dq[403]
    DIRECTION OUTPUT ;
    USE SIGNAL ;
    PORT
      LAYER M4 ;
        RECT  36.528 70.032 36.72 70.056 ;
    END
  END dq[403]
  PIN dq[404]
    DIRECTION OUTPUT ;
    USE SIGNAL ;
    PORT
      LAYER M4 ;
        RECT  36.528 70.176 36.72 70.2 ;
    END
  END dq[404]
  PIN dq[405]
    DIRECTION OUTPUT ;
    USE SIGNAL ;
    PORT
      LAYER M4 ;
        RECT  36.528 70.32 36.72 70.344 ;
    END
  END dq[405]
  PIN dq[406]
    DIRECTION OUTPUT ;
    USE SIGNAL ;
    PORT
      LAYER M4 ;
        RECT  36.528 70.512 36.72 70.536 ;
    END
  END dq[406]
  PIN dq[407]
    DIRECTION OUTPUT ;
    USE SIGNAL ;
    PORT
      LAYER M4 ;
        RECT  36.528 70.656 36.72 70.68 ;
    END
  END dq[407]
  PIN dq[408]
    DIRECTION OUTPUT ;
    USE SIGNAL ;
    PORT
      LAYER M4 ;
        RECT  36.528 70.848 36.72 70.872 ;
    END
  END dq[408]
  PIN dq[409]
    DIRECTION OUTPUT ;
    USE SIGNAL ;
    PORT
      LAYER M4 ;
        RECT  36.528 70.992 36.72 71.016 ;
    END
  END dq[409]
  PIN dq[40]
    DIRECTION OUTPUT ;
    USE SIGNAL ;
    PORT
      LAYER M4 ;
        RECT  36.528 10.944 36.72 10.968 ;
    END
  END dq[40]
  PIN dq[410]
    DIRECTION OUTPUT ;
    USE SIGNAL ;
    PORT
      LAYER M4 ;
        RECT  36.528 71.136 36.72 71.16 ;
    END
  END dq[410]
  PIN dq[411]
    DIRECTION OUTPUT ;
    USE SIGNAL ;
    PORT
      LAYER M4 ;
        RECT  36.528 71.328 36.72 71.352 ;
    END
  END dq[411]
  PIN dq[412]
    DIRECTION OUTPUT ;
    USE SIGNAL ;
    PORT
      LAYER M4 ;
        RECT  36.528 71.472 36.72 71.496 ;
    END
  END dq[412]
  PIN dq[413]
    DIRECTION OUTPUT ;
    USE SIGNAL ;
    PORT
      LAYER M4 ;
        RECT  36.528 71.664 36.72 71.688 ;
    END
  END dq[413]
  PIN dq[414]
    DIRECTION OUTPUT ;
    USE SIGNAL ;
    PORT
      LAYER M4 ;
        RECT  36.528 71.808 36.72 71.832 ;
    END
  END dq[414]
  PIN dq[415]
    DIRECTION OUTPUT ;
    USE SIGNAL ;
    PORT
      LAYER M4 ;
        RECT  36.528 71.952 36.72 71.976 ;
    END
  END dq[415]
  PIN dq[416]
    DIRECTION OUTPUT ;
    USE SIGNAL ;
    PORT
      LAYER M4 ;
        RECT  36.528 72.144 36.72 72.168 ;
    END
  END dq[416]
  PIN dq[417]
    DIRECTION OUTPUT ;
    USE SIGNAL ;
    PORT
      LAYER M4 ;
        RECT  36.528 72.288 36.72 72.312 ;
    END
  END dq[417]
  PIN dq[418]
    DIRECTION OUTPUT ;
    USE SIGNAL ;
    PORT
      LAYER M4 ;
        RECT  36.528 72.48 36.72 72.504 ;
    END
  END dq[418]
  PIN dq[419]
    DIRECTION OUTPUT ;
    USE SIGNAL ;
    PORT
      LAYER M4 ;
        RECT  36.528 72.624 36.72 72.648 ;
    END
  END dq[419]
  PIN dq[41]
    DIRECTION OUTPUT ;
    USE SIGNAL ;
    PORT
      LAYER M4 ;
        RECT  36.528 11.088 36.72 11.112 ;
    END
  END dq[41]
  PIN dq[420]
    DIRECTION OUTPUT ;
    USE SIGNAL ;
    PORT
      LAYER M4 ;
        RECT  36.528 72.768 36.72 72.792 ;
    END
  END dq[420]
  PIN dq[421]
    DIRECTION OUTPUT ;
    USE SIGNAL ;
    PORT
      LAYER M4 ;
        RECT  36.528 72.96 36.72 72.984 ;
    END
  END dq[421]
  PIN dq[422]
    DIRECTION OUTPUT ;
    USE SIGNAL ;
    PORT
      LAYER M4 ;
        RECT  36.528 73.104 36.72 73.128 ;
    END
  END dq[422]
  PIN dq[423]
    DIRECTION OUTPUT ;
    USE SIGNAL ;
    PORT
      LAYER M4 ;
        RECT  36.528 73.248 36.72 73.272 ;
    END
  END dq[423]
  PIN dq[424]
    DIRECTION OUTPUT ;
    USE SIGNAL ;
    PORT
      LAYER M4 ;
        RECT  36.528 73.44 36.72 73.464 ;
    END
  END dq[424]
  PIN dq[425]
    DIRECTION OUTPUT ;
    USE SIGNAL ;
    PORT
      LAYER M4 ;
        RECT  36.528 73.584 36.72 73.608 ;
    END
  END dq[425]
  PIN dq[426]
    DIRECTION OUTPUT ;
    USE SIGNAL ;
    PORT
      LAYER M4 ;
        RECT  36.528 73.776 36.72 73.8 ;
    END
  END dq[426]
  PIN dq[427]
    DIRECTION OUTPUT ;
    USE SIGNAL ;
    PORT
      LAYER M4 ;
        RECT  36.528 73.92 36.72 73.944 ;
    END
  END dq[427]
  PIN dq[428]
    DIRECTION OUTPUT ;
    USE SIGNAL ;
    PORT
      LAYER M4 ;
        RECT  36.528 74.064 36.72 74.088 ;
    END
  END dq[428]
  PIN dq[429]
    DIRECTION OUTPUT ;
    USE SIGNAL ;
    PORT
      LAYER M4 ;
        RECT  36.528 74.256 36.72 74.28 ;
    END
  END dq[429]
  PIN dq[42]
    DIRECTION OUTPUT ;
    USE SIGNAL ;
    PORT
      LAYER M4 ;
        RECT  36.528 11.232 36.72 11.256 ;
    END
  END dq[42]
  PIN dq[430]
    DIRECTION OUTPUT ;
    USE SIGNAL ;
    PORT
      LAYER M4 ;
        RECT  36.528 74.4 36.72 74.424 ;
    END
  END dq[430]
  PIN dq[431]
    DIRECTION OUTPUT ;
    USE SIGNAL ;
    PORT
      LAYER M4 ;
        RECT  36.528 74.592 36.72 74.616 ;
    END
  END dq[431]
  PIN dq[432]
    DIRECTION OUTPUT ;
    USE SIGNAL ;
    PORT
      LAYER M4 ;
        RECT  36.528 74.736 36.72 74.76 ;
    END
  END dq[432]
  PIN dq[433]
    DIRECTION OUTPUT ;
    USE SIGNAL ;
    PORT
      LAYER M4 ;
        RECT  36.528 74.88 36.72 74.904 ;
    END
  END dq[433]
  PIN dq[434]
    DIRECTION OUTPUT ;
    USE SIGNAL ;
    PORT
      LAYER M4 ;
        RECT  36.528 75.072 36.72 75.096 ;
    END
  END dq[434]
  PIN dq[435]
    DIRECTION OUTPUT ;
    USE SIGNAL ;
    PORT
      LAYER M4 ;
        RECT  36.528 75.216 36.72 75.24 ;
    END
  END dq[435]
  PIN dq[436]
    DIRECTION OUTPUT ;
    USE SIGNAL ;
    PORT
      LAYER M4 ;
        RECT  36.528 75.408 36.72 75.432 ;
    END
  END dq[436]
  PIN dq[437]
    DIRECTION OUTPUT ;
    USE SIGNAL ;
    PORT
      LAYER M4 ;
        RECT  36.528 75.552 36.72 75.576 ;
    END
  END dq[437]
  PIN dq[438]
    DIRECTION OUTPUT ;
    USE SIGNAL ;
    PORT
      LAYER M4 ;
        RECT  36.528 75.696 36.72 75.72 ;
    END
  END dq[438]
  PIN dq[439]
    DIRECTION OUTPUT ;
    USE SIGNAL ;
    PORT
      LAYER M4 ;
        RECT  36.528 75.888 36.72 75.912 ;
    END
  END dq[439]
  PIN dq[43]
    DIRECTION OUTPUT ;
    USE SIGNAL ;
    PORT
      LAYER M4 ;
        RECT  36.528 11.424 36.72 11.448 ;
    END
  END dq[43]
  PIN dq[440]
    DIRECTION OUTPUT ;
    USE SIGNAL ;
    PORT
      LAYER M4 ;
        RECT  36.528 76.032 36.72 76.056 ;
    END
  END dq[440]
  PIN dq[441]
    DIRECTION OUTPUT ;
    USE SIGNAL ;
    PORT
      LAYER M4 ;
        RECT  36.528 76.224 36.72 76.248 ;
    END
  END dq[441]
  PIN dq[442]
    DIRECTION OUTPUT ;
    USE SIGNAL ;
    PORT
      LAYER M4 ;
        RECT  36.528 76.368 36.72 76.392 ;
    END
  END dq[442]
  PIN dq[443]
    DIRECTION OUTPUT ;
    USE SIGNAL ;
    PORT
      LAYER M4 ;
        RECT  36.528 76.512 36.72 76.536 ;
    END
  END dq[443]
  PIN dq[444]
    DIRECTION OUTPUT ;
    USE SIGNAL ;
    PORT
      LAYER M4 ;
        RECT  36.528 76.704 36.72 76.728 ;
    END
  END dq[444]
  PIN dq[445]
    DIRECTION OUTPUT ;
    USE SIGNAL ;
    PORT
      LAYER M4 ;
        RECT  36.528 76.848 36.72 76.872 ;
    END
  END dq[445]
  PIN dq[446]
    DIRECTION OUTPUT ;
    USE SIGNAL ;
    PORT
      LAYER M4 ;
        RECT  36.528 76.992 36.72 77.016 ;
    END
  END dq[446]
  PIN dq[447]
    DIRECTION OUTPUT ;
    USE SIGNAL ;
    PORT
      LAYER M4 ;
        RECT  36.528 77.184 36.72 77.208 ;
    END
  END dq[447]
  PIN dq[448]
    DIRECTION OUTPUT ;
    USE SIGNAL ;
    PORT
      LAYER M4 ;
        RECT  36.528 77.328 36.72 77.352 ;
    END
  END dq[448]
  PIN dq[449]
    DIRECTION OUTPUT ;
    USE SIGNAL ;
    PORT
      LAYER M4 ;
        RECT  36.528 77.52 36.72 77.544 ;
    END
  END dq[449]
  PIN dq[44]
    DIRECTION OUTPUT ;
    USE SIGNAL ;
    PORT
      LAYER M4 ;
        RECT  36.528 11.568 36.72 11.592 ;
    END
  END dq[44]
  PIN dq[450]
    DIRECTION OUTPUT ;
    USE SIGNAL ;
    PORT
      LAYER M4 ;
        RECT  36.528 77.664 36.72 77.688 ;
    END
  END dq[450]
  PIN dq[451]
    DIRECTION OUTPUT ;
    USE SIGNAL ;
    PORT
      LAYER M4 ;
        RECT  36.528 77.808 36.72 77.832 ;
    END
  END dq[451]
  PIN dq[452]
    DIRECTION OUTPUT ;
    USE SIGNAL ;
    PORT
      LAYER M4 ;
        RECT  36.528 78 36.72 78.024 ;
    END
  END dq[452]
  PIN dq[453]
    DIRECTION OUTPUT ;
    USE SIGNAL ;
    PORT
      LAYER M4 ;
        RECT  36.528 78.144 36.72 78.168 ;
    END
  END dq[453]
  PIN dq[454]
    DIRECTION OUTPUT ;
    USE SIGNAL ;
    PORT
      LAYER M4 ;
        RECT  36.528 78.336 36.72 78.36 ;
    END
  END dq[454]
  PIN dq[455]
    DIRECTION OUTPUT ;
    USE SIGNAL ;
    PORT
      LAYER M4 ;
        RECT  36.528 78.48 36.72 78.504 ;
    END
  END dq[455]
  PIN dq[456]
    DIRECTION OUTPUT ;
    USE SIGNAL ;
    PORT
      LAYER M4 ;
        RECT  36.528 78.624 36.72 78.648 ;
    END
  END dq[456]
  PIN dq[457]
    DIRECTION OUTPUT ;
    USE SIGNAL ;
    PORT
      LAYER M4 ;
        RECT  36.528 78.816 36.72 78.84 ;
    END
  END dq[457]
  PIN dq[458]
    DIRECTION OUTPUT ;
    USE SIGNAL ;
    PORT
      LAYER M4 ;
        RECT  36.528 78.96 36.72 78.984 ;
    END
  END dq[458]
  PIN dq[459]
    DIRECTION OUTPUT ;
    USE SIGNAL ;
    PORT
      LAYER M4 ;
        RECT  36.528 79.152 36.72 79.176 ;
    END
  END dq[459]
  PIN dq[45]
    DIRECTION OUTPUT ;
    USE SIGNAL ;
    PORT
      LAYER M4 ;
        RECT  36.528 11.76 36.72 11.784 ;
    END
  END dq[45]
  PIN dq[460]
    DIRECTION OUTPUT ;
    USE SIGNAL ;
    PORT
      LAYER M4 ;
        RECT  36.528 79.296 36.72 79.32 ;
    END
  END dq[460]
  PIN dq[461]
    DIRECTION OUTPUT ;
    USE SIGNAL ;
    PORT
      LAYER M4 ;
        RECT  36.528 79.44 36.72 79.464 ;
    END
  END dq[461]
  PIN dq[462]
    DIRECTION OUTPUT ;
    USE SIGNAL ;
    PORT
      LAYER M4 ;
        RECT  36.528 79.632 36.72 79.656 ;
    END
  END dq[462]
  PIN dq[463]
    DIRECTION OUTPUT ;
    USE SIGNAL ;
    PORT
      LAYER M4 ;
        RECT  36.528 79.776 36.72 79.8 ;
    END
  END dq[463]
  PIN dq[464]
    DIRECTION OUTPUT ;
    USE SIGNAL ;
    PORT
      LAYER M4 ;
        RECT  36.528 79.968 36.72 79.992 ;
    END
  END dq[464]
  PIN dq[465]
    DIRECTION OUTPUT ;
    USE SIGNAL ;
    PORT
      LAYER M4 ;
        RECT  36.528 80.112 36.72 80.136 ;
    END
  END dq[465]
  PIN dq[466]
    DIRECTION OUTPUT ;
    USE SIGNAL ;
    PORT
      LAYER M4 ;
        RECT  36.528 80.256 36.72 80.28 ;
    END
  END dq[466]
  PIN dq[467]
    DIRECTION OUTPUT ;
    USE SIGNAL ;
    PORT
      LAYER M4 ;
        RECT  36.528 80.448 36.72 80.472 ;
    END
  END dq[467]
  PIN dq[468]
    DIRECTION OUTPUT ;
    USE SIGNAL ;
    PORT
      LAYER M4 ;
        RECT  36.528 80.592 36.72 80.616 ;
    END
  END dq[468]
  PIN dq[469]
    DIRECTION OUTPUT ;
    USE SIGNAL ;
    PORT
      LAYER M4 ;
        RECT  36.528 80.736 36.72 80.76 ;
    END
  END dq[469]
  PIN dq[46]
    DIRECTION OUTPUT ;
    USE SIGNAL ;
    PORT
      LAYER M4 ;
        RECT  36.528 11.904 36.72 11.928 ;
    END
  END dq[46]
  PIN dq[470]
    DIRECTION OUTPUT ;
    USE SIGNAL ;
    PORT
      LAYER M4 ;
        RECT  36.528 80.928 36.72 80.952 ;
    END
  END dq[470]
  PIN dq[471]
    DIRECTION OUTPUT ;
    USE SIGNAL ;
    PORT
      LAYER M4 ;
        RECT  36.528 81.072 36.72 81.096 ;
    END
  END dq[471]
  PIN dq[472]
    DIRECTION OUTPUT ;
    USE SIGNAL ;
    PORT
      LAYER M4 ;
        RECT  36.528 81.264 36.72 81.288 ;
    END
  END dq[472]
  PIN dq[473]
    DIRECTION OUTPUT ;
    USE SIGNAL ;
    PORT
      LAYER M4 ;
        RECT  36.528 81.408 36.72 81.432 ;
    END
  END dq[473]
  PIN dq[474]
    DIRECTION OUTPUT ;
    USE SIGNAL ;
    PORT
      LAYER M4 ;
        RECT  36.528 81.552 36.72 81.576 ;
    END
  END dq[474]
  PIN dq[475]
    DIRECTION OUTPUT ;
    USE SIGNAL ;
    PORT
      LAYER M4 ;
        RECT  36.528 81.744 36.72 81.768 ;
    END
  END dq[475]
  PIN dq[476]
    DIRECTION OUTPUT ;
    USE SIGNAL ;
    PORT
      LAYER M4 ;
        RECT  36.528 81.888 36.72 81.912 ;
    END
  END dq[476]
  PIN dq[477]
    DIRECTION OUTPUT ;
    USE SIGNAL ;
    PORT
      LAYER M4 ;
        RECT  36.528 82.08 36.72 82.104 ;
    END
  END dq[477]
  PIN dq[478]
    DIRECTION OUTPUT ;
    USE SIGNAL ;
    PORT
      LAYER M4 ;
        RECT  36.528 82.224 36.72 82.248 ;
    END
  END dq[478]
  PIN dq[479]
    DIRECTION OUTPUT ;
    USE SIGNAL ;
    PORT
      LAYER M4 ;
        RECT  36.528 82.368 36.72 82.392 ;
    END
  END dq[479]
  PIN dq[47]
    DIRECTION OUTPUT ;
    USE SIGNAL ;
    PORT
      LAYER M4 ;
        RECT  36.528 12.048 36.72 12.072 ;
    END
  END dq[47]
  PIN dq[480]
    DIRECTION OUTPUT ;
    USE SIGNAL ;
    PORT
      LAYER M4 ;
        RECT  36.528 82.56 36.72 82.584 ;
    END
  END dq[480]
  PIN dq[481]
    DIRECTION OUTPUT ;
    USE SIGNAL ;
    PORT
      LAYER M4 ;
        RECT  36.528 82.704 36.72 82.728 ;
    END
  END dq[481]
  PIN dq[482]
    DIRECTION OUTPUT ;
    USE SIGNAL ;
    PORT
      LAYER M4 ;
        RECT  36.528 82.896 36.72 82.92 ;
    END
  END dq[482]
  PIN dq[483]
    DIRECTION OUTPUT ;
    USE SIGNAL ;
    PORT
      LAYER M4 ;
        RECT  36.528 83.04 36.72 83.064 ;
    END
  END dq[483]
  PIN dq[484]
    DIRECTION OUTPUT ;
    USE SIGNAL ;
    PORT
      LAYER M4 ;
        RECT  36.528 83.184 36.72 83.208 ;
    END
  END dq[484]
  PIN dq[485]
    DIRECTION OUTPUT ;
    USE SIGNAL ;
    PORT
      LAYER M4 ;
        RECT  36.528 83.376 36.72 83.4 ;
    END
  END dq[485]
  PIN dq[486]
    DIRECTION OUTPUT ;
    USE SIGNAL ;
    PORT
      LAYER M4 ;
        RECT  36.528 83.52 36.72 83.544 ;
    END
  END dq[486]
  PIN dq[487]
    DIRECTION OUTPUT ;
    USE SIGNAL ;
    PORT
      LAYER M4 ;
        RECT  36.528 83.712 36.72 83.736 ;
    END
  END dq[487]
  PIN dq[488]
    DIRECTION OUTPUT ;
    USE SIGNAL ;
    PORT
      LAYER M4 ;
        RECT  36.528 83.856 36.72 83.88 ;
    END
  END dq[488]
  PIN dq[489]
    DIRECTION OUTPUT ;
    USE SIGNAL ;
    PORT
      LAYER M4 ;
        RECT  36.528 84 36.72 84.024 ;
    END
  END dq[489]
  PIN dq[48]
    DIRECTION OUTPUT ;
    USE SIGNAL ;
    PORT
      LAYER M4 ;
        RECT  36.528 12.24 36.72 12.264 ;
    END
  END dq[48]
  PIN dq[490]
    DIRECTION OUTPUT ;
    USE SIGNAL ;
    PORT
      LAYER M4 ;
        RECT  36.528 84.192 36.72 84.216 ;
    END
  END dq[490]
  PIN dq[491]
    DIRECTION OUTPUT ;
    USE SIGNAL ;
    PORT
      LAYER M4 ;
        RECT  36.528 84.336 36.72 84.36 ;
    END
  END dq[491]
  PIN dq[492]
    DIRECTION OUTPUT ;
    USE SIGNAL ;
    PORT
      LAYER M4 ;
        RECT  36.528 84.48 36.72 84.504 ;
    END
  END dq[492]
  PIN dq[493]
    DIRECTION OUTPUT ;
    USE SIGNAL ;
    PORT
      LAYER M4 ;
        RECT  36.528 84.672 36.72 84.696 ;
    END
  END dq[493]
  PIN dq[494]
    DIRECTION OUTPUT ;
    USE SIGNAL ;
    PORT
      LAYER M4 ;
        RECT  36.528 84.816 36.72 84.84 ;
    END
  END dq[494]
  PIN dq[495]
    DIRECTION OUTPUT ;
    USE SIGNAL ;
    PORT
      LAYER M4 ;
        RECT  36.528 85.008 36.72 85.032 ;
    END
  END dq[495]
  PIN dq[496]
    DIRECTION OUTPUT ;
    USE SIGNAL ;
    PORT
      LAYER M4 ;
        RECT  36.528 85.152 36.72 85.176 ;
    END
  END dq[496]
  PIN dq[497]
    DIRECTION OUTPUT ;
    USE SIGNAL ;
    PORT
      LAYER M4 ;
        RECT  36.528 85.296 36.72 85.32 ;
    END
  END dq[497]
  PIN dq[498]
    DIRECTION OUTPUT ;
    USE SIGNAL ;
    PORT
      LAYER M4 ;
        RECT  36.528 85.488 36.72 85.512 ;
    END
  END dq[498]
  PIN dq[499]
    DIRECTION OUTPUT ;
    USE SIGNAL ;
    PORT
      LAYER M4 ;
        RECT  36.528 85.632 36.72 85.656 ;
    END
  END dq[499]
  PIN dq[49]
    DIRECTION OUTPUT ;
    USE SIGNAL ;
    PORT
      LAYER M4 ;
        RECT  36.528 12.384 36.72 12.408 ;
    END
  END dq[49]
  PIN dq[4]
    DIRECTION OUTPUT ;
    USE SIGNAL ;
    PORT
      LAYER M4 ;
        RECT  36.528 5.088 36.72 5.112 ;
    END
  END dq[4]
  PIN dq[500]
    DIRECTION OUTPUT ;
    USE SIGNAL ;
    PORT
      LAYER M4 ;
        RECT  36.528 85.824 36.72 85.848 ;
    END
  END dq[500]
  PIN dq[501]
    DIRECTION OUTPUT ;
    USE SIGNAL ;
    PORT
      LAYER M4 ;
        RECT  36.528 85.968 36.72 85.992 ;
    END
  END dq[501]
  PIN dq[502]
    DIRECTION OUTPUT ;
    USE SIGNAL ;
    PORT
      LAYER M4 ;
        RECT  36.528 86.112 36.72 86.136 ;
    END
  END dq[502]
  PIN dq[503]
    DIRECTION OUTPUT ;
    USE SIGNAL ;
    PORT
      LAYER M4 ;
        RECT  36.528 86.304 36.72 86.328 ;
    END
  END dq[503]
  PIN dq[504]
    DIRECTION OUTPUT ;
    USE SIGNAL ;
    PORT
      LAYER M4 ;
        RECT  36.528 86.448 36.72 86.472 ;
    END
  END dq[504]
  PIN dq[505]
    DIRECTION OUTPUT ;
    USE SIGNAL ;
    PORT
      LAYER M4 ;
        RECT  36.528 86.64 36.72 86.664 ;
    END
  END dq[505]
  PIN dq[506]
    DIRECTION OUTPUT ;
    USE SIGNAL ;
    PORT
      LAYER M4 ;
        RECT  36.528 86.784 36.72 86.808 ;
    END
  END dq[506]
  PIN dq[507]
    DIRECTION OUTPUT ;
    USE SIGNAL ;
    PORT
      LAYER M4 ;
        RECT  36.528 86.928 36.72 86.952 ;
    END
  END dq[507]
  PIN dq[508]
    DIRECTION OUTPUT ;
    USE SIGNAL ;
    PORT
      LAYER M4 ;
        RECT  36.528 87.12 36.72 87.144 ;
    END
  END dq[508]
  PIN dq[509]
    DIRECTION OUTPUT ;
    USE SIGNAL ;
    PORT
      LAYER M4 ;
        RECT  36.528 87.264 36.72 87.288 ;
    END
  END dq[509]
  PIN dq[50]
    DIRECTION OUTPUT ;
    USE SIGNAL ;
    PORT
      LAYER M4 ;
        RECT  36.528 12.576 36.72 12.6 ;
    END
  END dq[50]
  PIN dq[510]
    DIRECTION OUTPUT ;
    USE SIGNAL ;
    PORT
      LAYER M4 ;
        RECT  36.528 87.456 36.72 87.48 ;
    END
  END dq[510]
  PIN dq[511]
    DIRECTION OUTPUT ;
    USE SIGNAL ;
    PORT
      LAYER M4 ;
        RECT  36.528 87.6 36.72 87.624 ;
    END
  END dq[511]
  PIN dq[512]
    DIRECTION OUTPUT ;
    USE SIGNAL ;
    PORT
      LAYER M4 ;
        RECT  36.528 87.744 36.72 87.768 ;
    END
  END dq[512]
  PIN dq[513]
    DIRECTION OUTPUT ;
    USE SIGNAL ;
    PORT
      LAYER M4 ;
        RECT  36.528 87.936 36.72 87.96 ;
    END
  END dq[513]
  PIN dq[514]
    DIRECTION OUTPUT ;
    USE SIGNAL ;
    PORT
      LAYER M4 ;
        RECT  36.528 88.08 36.72 88.104 ;
    END
  END dq[514]
  PIN dq[515]
    DIRECTION OUTPUT ;
    USE SIGNAL ;
    PORT
      LAYER M4 ;
        RECT  36.528 88.224 36.72 88.248 ;
    END
  END dq[515]
  PIN dq[516]
    DIRECTION OUTPUT ;
    USE SIGNAL ;
    PORT
      LAYER M4 ;
        RECT  36.528 88.416 36.72 88.44 ;
    END
  END dq[516]
  PIN dq[517]
    DIRECTION OUTPUT ;
    USE SIGNAL ;
    PORT
      LAYER M4 ;
        RECT  36.528 88.56 36.72 88.584 ;
    END
  END dq[517]
  PIN dq[518]
    DIRECTION OUTPUT ;
    USE SIGNAL ;
    PORT
      LAYER M4 ;
        RECT  36.528 88.752 36.72 88.776 ;
    END
  END dq[518]
  PIN dq[519]
    DIRECTION OUTPUT ;
    USE SIGNAL ;
    PORT
      LAYER M4 ;
        RECT  36.528 88.896 36.72 88.92 ;
    END
  END dq[519]
  PIN dq[51]
    DIRECTION OUTPUT ;
    USE SIGNAL ;
    PORT
      LAYER M4 ;
        RECT  36.528 12.72 36.72 12.744 ;
    END
  END dq[51]
  PIN dq[520]
    DIRECTION OUTPUT ;
    USE SIGNAL ;
    PORT
      LAYER M4 ;
        RECT  36.528 89.04 36.72 89.064 ;
    END
  END dq[520]
  PIN dq[521]
    DIRECTION OUTPUT ;
    USE SIGNAL ;
    PORT
      LAYER M4 ;
        RECT  36.528 89.232 36.72 89.256 ;
    END
  END dq[521]
  PIN dq[522]
    DIRECTION OUTPUT ;
    USE SIGNAL ;
    PORT
      LAYER M4 ;
        RECT  36.528 89.376 36.72 89.4 ;
    END
  END dq[522]
  PIN dq[523]
    DIRECTION OUTPUT ;
    USE SIGNAL ;
    PORT
      LAYER M4 ;
        RECT  36.528 89.568 36.72 89.592 ;
    END
  END dq[523]
  PIN dq[524]
    DIRECTION OUTPUT ;
    USE SIGNAL ;
    PORT
      LAYER M4 ;
        RECT  36.528 89.712 36.72 89.736 ;
    END
  END dq[524]
  PIN dq[525]
    DIRECTION OUTPUT ;
    USE SIGNAL ;
    PORT
      LAYER M4 ;
        RECT  36.528 89.856 36.72 89.88 ;
    END
  END dq[525]
  PIN dq[526]
    DIRECTION OUTPUT ;
    USE SIGNAL ;
    PORT
      LAYER M4 ;
        RECT  36.528 90.048 36.72 90.072 ;
    END
  END dq[526]
  PIN dq[527]
    DIRECTION OUTPUT ;
    USE SIGNAL ;
    PORT
      LAYER M4 ;
        RECT  36.528 90.192 36.72 90.216 ;
    END
  END dq[527]
  PIN dq[528]
    DIRECTION OUTPUT ;
    USE SIGNAL ;
    PORT
      LAYER M4 ;
        RECT  36.528 90.384 36.72 90.408 ;
    END
  END dq[528]
  PIN dq[529]
    DIRECTION OUTPUT ;
    USE SIGNAL ;
    PORT
      LAYER M4 ;
        RECT  36.528 90.528 36.72 90.552 ;
    END
  END dq[529]
  PIN dq[52]
    DIRECTION OUTPUT ;
    USE SIGNAL ;
    PORT
      LAYER M4 ;
        RECT  36.528 12.864 36.72 12.888 ;
    END
  END dq[52]
  PIN dq[530]
    DIRECTION OUTPUT ;
    USE SIGNAL ;
    PORT
      LAYER M4 ;
        RECT  36.528 90.672 36.72 90.696 ;
    END
  END dq[530]
  PIN dq[531]
    DIRECTION OUTPUT ;
    USE SIGNAL ;
    PORT
      LAYER M4 ;
        RECT  36.528 90.864 36.72 90.888 ;
    END
  END dq[531]
  PIN dq[532]
    DIRECTION OUTPUT ;
    USE SIGNAL ;
    PORT
      LAYER M4 ;
        RECT  36.528 91.008 36.72 91.032 ;
    END
  END dq[532]
  PIN dq[533]
    DIRECTION OUTPUT ;
    USE SIGNAL ;
    PORT
      LAYER M4 ;
        RECT  36.528 91.2 36.72 91.224 ;
    END
  END dq[533]
  PIN dq[534]
    DIRECTION OUTPUT ;
    USE SIGNAL ;
    PORT
      LAYER M4 ;
        RECT  36.528 91.344 36.72 91.368 ;
    END
  END dq[534]
  PIN dq[535]
    DIRECTION OUTPUT ;
    USE SIGNAL ;
    PORT
      LAYER M4 ;
        RECT  36.528 91.488 36.72 91.512 ;
    END
  END dq[535]
  PIN dq[536]
    DIRECTION OUTPUT ;
    USE SIGNAL ;
    PORT
      LAYER M4 ;
        RECT  36.528 91.68 36.72 91.704 ;
    END
  END dq[536]
  PIN dq[537]
    DIRECTION OUTPUT ;
    USE SIGNAL ;
    PORT
      LAYER M4 ;
        RECT  36.528 91.824 36.72 91.848 ;
    END
  END dq[537]
  PIN dq[538]
    DIRECTION OUTPUT ;
    USE SIGNAL ;
    PORT
      LAYER M4 ;
        RECT  36.528 91.968 36.72 91.992 ;
    END
  END dq[538]
  PIN dq[539]
    DIRECTION OUTPUT ;
    USE SIGNAL ;
    PORT
      LAYER M4 ;
        RECT  36.528 92.16 36.72 92.184 ;
    END
  END dq[539]
  PIN dq[53]
    DIRECTION OUTPUT ;
    USE SIGNAL ;
    PORT
      LAYER M4 ;
        RECT  36.528 13.056 36.72 13.08 ;
    END
  END dq[53]
  PIN dq[540]
    DIRECTION OUTPUT ;
    USE SIGNAL ;
    PORT
      LAYER M4 ;
        RECT  36.528 92.304 36.72 92.328 ;
    END
  END dq[540]
  PIN dq[541]
    DIRECTION OUTPUT ;
    USE SIGNAL ;
    PORT
      LAYER M4 ;
        RECT  36.528 92.496 36.72 92.52 ;
    END
  END dq[541]
  PIN dq[542]
    DIRECTION OUTPUT ;
    USE SIGNAL ;
    PORT
      LAYER M4 ;
        RECT  36.528 92.64 36.72 92.664 ;
    END
  END dq[542]
  PIN dq[543]
    DIRECTION OUTPUT ;
    USE SIGNAL ;
    PORT
      LAYER M4 ;
        RECT  36.528 92.784 36.72 92.808 ;
    END
  END dq[543]
  PIN dq[544]
    DIRECTION OUTPUT ;
    USE SIGNAL ;
    PORT
      LAYER M4 ;
        RECT  36.528 92.976 36.72 93 ;
    END
  END dq[544]
  PIN dq[545]
    DIRECTION OUTPUT ;
    USE SIGNAL ;
    PORT
      LAYER M4 ;
        RECT  36.528 93.12 36.72 93.144 ;
    END
  END dq[545]
  PIN dq[546]
    DIRECTION OUTPUT ;
    USE SIGNAL ;
    PORT
      LAYER M4 ;
        RECT  36.528 93.312 36.72 93.336 ;
    END
  END dq[546]
  PIN dq[547]
    DIRECTION OUTPUT ;
    USE SIGNAL ;
    PORT
      LAYER M4 ;
        RECT  36.528 93.456 36.72 93.48 ;
    END
  END dq[547]
  PIN dq[548]
    DIRECTION OUTPUT ;
    USE SIGNAL ;
    PORT
      LAYER M4 ;
        RECT  36.528 93.6 36.72 93.624 ;
    END
  END dq[548]
  PIN dq[549]
    DIRECTION OUTPUT ;
    USE SIGNAL ;
    PORT
      LAYER M4 ;
        RECT  36.528 93.792 36.72 93.816 ;
    END
  END dq[549]
  PIN dq[54]
    DIRECTION OUTPUT ;
    USE SIGNAL ;
    PORT
      LAYER M4 ;
        RECT  36.528 13.2 36.72 13.224 ;
    END
  END dq[54]
  PIN dq[550]
    DIRECTION OUTPUT ;
    USE SIGNAL ;
    PORT
      LAYER M4 ;
        RECT  36.528 93.936 36.72 93.96 ;
    END
  END dq[550]
  PIN dq[551]
    DIRECTION OUTPUT ;
    USE SIGNAL ;
    PORT
      LAYER M4 ;
        RECT  36.528 94.128 36.72 94.152 ;
    END
  END dq[551]
  PIN dq[552]
    DIRECTION OUTPUT ;
    USE SIGNAL ;
    PORT
      LAYER M4 ;
        RECT  36.528 94.272 36.72 94.296 ;
    END
  END dq[552]
  PIN dq[553]
    DIRECTION OUTPUT ;
    USE SIGNAL ;
    PORT
      LAYER M4 ;
        RECT  36.528 94.416 36.72 94.44 ;
    END
  END dq[553]
  PIN dq[554]
    DIRECTION OUTPUT ;
    USE SIGNAL ;
    PORT
      LAYER M4 ;
        RECT  36.528 94.608 36.72 94.632 ;
    END
  END dq[554]
  PIN dq[555]
    DIRECTION OUTPUT ;
    USE SIGNAL ;
    PORT
      LAYER M4 ;
        RECT  36.528 94.752 36.72 94.776 ;
    END
  END dq[555]
  PIN dq[556]
    DIRECTION OUTPUT ;
    USE SIGNAL ;
    PORT
      LAYER M4 ;
        RECT  36.528 94.944 36.72 94.968 ;
    END
  END dq[556]
  PIN dq[557]
    DIRECTION OUTPUT ;
    USE SIGNAL ;
    PORT
      LAYER M4 ;
        RECT  36.528 95.088 36.72 95.112 ;
    END
  END dq[557]
  PIN dq[558]
    DIRECTION OUTPUT ;
    USE SIGNAL ;
    PORT
      LAYER M4 ;
        RECT  36.528 95.232 36.72 95.256 ;
    END
  END dq[558]
  PIN dq[559]
    DIRECTION OUTPUT ;
    USE SIGNAL ;
    PORT
      LAYER M4 ;
        RECT  36.528 95.424 36.72 95.448 ;
    END
  END dq[559]
  PIN dq[55]
    DIRECTION OUTPUT ;
    USE SIGNAL ;
    PORT
      LAYER M4 ;
        RECT  36.528 13.344 36.72 13.368 ;
    END
  END dq[55]
  PIN dq[560]
    DIRECTION OUTPUT ;
    USE SIGNAL ;
    PORT
      LAYER M4 ;
        RECT  36.528 95.568 36.72 95.592 ;
    END
  END dq[560]
  PIN dq[561]
    DIRECTION OUTPUT ;
    USE SIGNAL ;
    PORT
      LAYER M4 ;
        RECT  36.528 95.712 36.72 95.736 ;
    END
  END dq[561]
  PIN dq[562]
    DIRECTION OUTPUT ;
    USE SIGNAL ;
    PORT
      LAYER M4 ;
        RECT  36.528 95.904 36.72 95.928 ;
    END
  END dq[562]
  PIN dq[563]
    DIRECTION OUTPUT ;
    USE SIGNAL ;
    PORT
      LAYER M4 ;
        RECT  36.528 96.048 36.72 96.072 ;
    END
  END dq[563]
  PIN dq[564]
    DIRECTION OUTPUT ;
    USE SIGNAL ;
    PORT
      LAYER M4 ;
        RECT  36.528 96.24 36.72 96.264 ;
    END
  END dq[564]
  PIN dq[565]
    DIRECTION OUTPUT ;
    USE SIGNAL ;
    PORT
      LAYER M4 ;
        RECT  36.528 96.384 36.72 96.408 ;
    END
  END dq[565]
  PIN dq[566]
    DIRECTION OUTPUT ;
    USE SIGNAL ;
    PORT
      LAYER M4 ;
        RECT  36.528 96.528 36.72 96.552 ;
    END
  END dq[566]
  PIN dq[567]
    DIRECTION OUTPUT ;
    USE SIGNAL ;
    PORT
      LAYER M4 ;
        RECT  36.528 96.72 36.72 96.744 ;
    END
  END dq[567]
  PIN dq[568]
    DIRECTION OUTPUT ;
    USE SIGNAL ;
    PORT
      LAYER M4 ;
        RECT  36.528 96.864 36.72 96.888 ;
    END
  END dq[568]
  PIN dq[569]
    DIRECTION OUTPUT ;
    USE SIGNAL ;
    PORT
      LAYER M4 ;
        RECT  36.528 97.056 36.72 97.08 ;
    END
  END dq[569]
  PIN dq[56]
    DIRECTION OUTPUT ;
    USE SIGNAL ;
    PORT
      LAYER M4 ;
        RECT  36.528 13.536 36.72 13.56 ;
    END
  END dq[56]
  PIN dq[570]
    DIRECTION OUTPUT ;
    USE SIGNAL ;
    PORT
      LAYER M4 ;
        RECT  36.528 97.2 36.72 97.224 ;
    END
  END dq[570]
  PIN dq[571]
    DIRECTION OUTPUT ;
    USE SIGNAL ;
    PORT
      LAYER M4 ;
        RECT  36.528 97.344 36.72 97.368 ;
    END
  END dq[571]
  PIN dq[572]
    DIRECTION OUTPUT ;
    USE SIGNAL ;
    PORT
      LAYER M4 ;
        RECT  36.528 97.536 36.72 97.56 ;
    END
  END dq[572]
  PIN dq[573]
    DIRECTION OUTPUT ;
    USE SIGNAL ;
    PORT
      LAYER M4 ;
        RECT  36.528 97.68 36.72 97.704 ;
    END
  END dq[573]
  PIN dq[574]
    DIRECTION OUTPUT ;
    USE SIGNAL ;
    PORT
      LAYER M4 ;
        RECT  36.528 97.872 36.72 97.896 ;
    END
  END dq[574]
  PIN dq[575]
    DIRECTION OUTPUT ;
    USE SIGNAL ;
    PORT
      LAYER M4 ;
        RECT  36.528 98.016 36.72 98.04 ;
    END
  END dq[575]
  PIN dq[576]
    DIRECTION OUTPUT ;
    USE SIGNAL ;
    PORT
      LAYER M4 ;
        RECT  36.528 98.16 36.72 98.184 ;
    END
  END dq[576]
  PIN dq[577]
    DIRECTION OUTPUT ;
    USE SIGNAL ;
    PORT
      LAYER M4 ;
        RECT  36.528 98.352 36.72 98.376 ;
    END
  END dq[577]
  PIN dq[578]
    DIRECTION OUTPUT ;
    USE SIGNAL ;
    PORT
      LAYER M4 ;
        RECT  36.528 98.496 36.72 98.52 ;
    END
  END dq[578]
  PIN dq[579]
    DIRECTION OUTPUT ;
    USE SIGNAL ;
    PORT
      LAYER M4 ;
        RECT  36.528 98.688 36.72 98.712 ;
    END
  END dq[579]
  PIN dq[57]
    DIRECTION OUTPUT ;
    USE SIGNAL ;
    PORT
      LAYER M4 ;
        RECT  36.528 13.68 36.72 13.704 ;
    END
  END dq[57]
  PIN dq[580]
    DIRECTION OUTPUT ;
    USE SIGNAL ;
    PORT
      LAYER M4 ;
        RECT  36.528 98.832 36.72 98.856 ;
    END
  END dq[580]
  PIN dq[581]
    DIRECTION OUTPUT ;
    USE SIGNAL ;
    PORT
      LAYER M4 ;
        RECT  36.528 98.976 36.72 99 ;
    END
  END dq[581]
  PIN dq[582]
    DIRECTION OUTPUT ;
    USE SIGNAL ;
    PORT
      LAYER M4 ;
        RECT  36.528 99.168 36.72 99.192 ;
    END
  END dq[582]
  PIN dq[583]
    DIRECTION OUTPUT ;
    USE SIGNAL ;
    PORT
      LAYER M4 ;
        RECT  36.528 99.312 36.72 99.336 ;
    END
  END dq[583]
  PIN dq[584]
    DIRECTION OUTPUT ;
    USE SIGNAL ;
    PORT
      LAYER M4 ;
        RECT  36.528 99.456 36.72 99.48 ;
    END
  END dq[584]
  PIN dq[585]
    DIRECTION OUTPUT ;
    USE SIGNAL ;
    PORT
      LAYER M4 ;
        RECT  36.528 99.648 36.72 99.672 ;
    END
  END dq[585]
  PIN dq[586]
    DIRECTION OUTPUT ;
    USE SIGNAL ;
    PORT
      LAYER M4 ;
        RECT  36.528 99.792 36.72 99.816 ;
    END
  END dq[586]
  PIN dq[587]
    DIRECTION OUTPUT ;
    USE SIGNAL ;
    PORT
      LAYER M4 ;
        RECT  36.528 99.984 36.72 100.008 ;
    END
  END dq[587]
  PIN dq[588]
    DIRECTION OUTPUT ;
    USE SIGNAL ;
    PORT
      LAYER M4 ;
        RECT  36.528 100.128 36.72 100.152 ;
    END
  END dq[588]
  PIN dq[589]
    DIRECTION OUTPUT ;
    USE SIGNAL ;
    PORT
      LAYER M4 ;
        RECT  36.528 100.272 36.72 100.296 ;
    END
  END dq[589]
  PIN dq[58]
    DIRECTION OUTPUT ;
    USE SIGNAL ;
    PORT
      LAYER M4 ;
        RECT  36.528 13.872 36.72 13.896 ;
    END
  END dq[58]
  PIN dq[590]
    DIRECTION OUTPUT ;
    USE SIGNAL ;
    PORT
      LAYER M4 ;
        RECT  36.528 100.464 36.72 100.488 ;
    END
  END dq[590]
  PIN dq[591]
    DIRECTION OUTPUT ;
    USE SIGNAL ;
    PORT
      LAYER M4 ;
        RECT  36.528 100.608 36.72 100.632 ;
    END
  END dq[591]
  PIN dq[592]
    DIRECTION OUTPUT ;
    USE SIGNAL ;
    PORT
      LAYER M4 ;
        RECT  36.528 100.8 36.72 100.824 ;
    END
  END dq[592]
  PIN dq[593]
    DIRECTION OUTPUT ;
    USE SIGNAL ;
    PORT
      LAYER M4 ;
        RECT  36.528 100.944 36.72 100.968 ;
    END
  END dq[593]
  PIN dq[594]
    DIRECTION OUTPUT ;
    USE SIGNAL ;
    PORT
      LAYER M4 ;
        RECT  36.528 101.088 36.72 101.112 ;
    END
  END dq[594]
  PIN dq[595]
    DIRECTION OUTPUT ;
    USE SIGNAL ;
    PORT
      LAYER M4 ;
        RECT  36.528 101.28 36.72 101.304 ;
    END
  END dq[595]
  PIN dq[596]
    DIRECTION OUTPUT ;
    USE SIGNAL ;
    PORT
      LAYER M4 ;
        RECT  36.528 101.424 36.72 101.448 ;
    END
  END dq[596]
  PIN dq[597]
    DIRECTION OUTPUT ;
    USE SIGNAL ;
    PORT
      LAYER M4 ;
        RECT  36.528 101.616 36.72 101.64 ;
    END
  END dq[597]
  PIN dq[598]
    DIRECTION OUTPUT ;
    USE SIGNAL ;
    PORT
      LAYER M4 ;
        RECT  36.528 101.76 36.72 101.784 ;
    END
  END dq[598]
  PIN dq[599]
    DIRECTION OUTPUT ;
    USE SIGNAL ;
    PORT
      LAYER M4 ;
        RECT  36.528 101.904 36.72 101.928 ;
    END
  END dq[599]
  PIN dq[59]
    DIRECTION OUTPUT ;
    USE SIGNAL ;
    PORT
      LAYER M4 ;
        RECT  36.528 14.016 36.72 14.04 ;
    END
  END dq[59]
  PIN dq[5]
    DIRECTION OUTPUT ;
    USE SIGNAL ;
    PORT
      LAYER M4 ;
        RECT  36.528 5.232 36.72 5.256 ;
    END
  END dq[5]
  PIN dq[600]
    DIRECTION OUTPUT ;
    USE SIGNAL ;
    PORT
      LAYER M4 ;
        RECT  36.528 102.096 36.72 102.12 ;
    END
  END dq[600]
  PIN dq[601]
    DIRECTION OUTPUT ;
    USE SIGNAL ;
    PORT
      LAYER M4 ;
        RECT  36.528 102.24 36.72 102.264 ;
    END
  END dq[601]
  PIN dq[602]
    DIRECTION OUTPUT ;
    USE SIGNAL ;
    PORT
      LAYER M4 ;
        RECT  36.528 102.432 36.72 102.456 ;
    END
  END dq[602]
  PIN dq[603]
    DIRECTION OUTPUT ;
    USE SIGNAL ;
    PORT
      LAYER M4 ;
        RECT  36.528 102.576 36.72 102.6 ;
    END
  END dq[603]
  PIN dq[604]
    DIRECTION OUTPUT ;
    USE SIGNAL ;
    PORT
      LAYER M4 ;
        RECT  36.528 102.72 36.72 102.744 ;
    END
  END dq[604]
  PIN dq[605]
    DIRECTION OUTPUT ;
    USE SIGNAL ;
    PORT
      LAYER M4 ;
        RECT  36.528 102.912 36.72 102.936 ;
    END
  END dq[605]
  PIN dq[606]
    DIRECTION OUTPUT ;
    USE SIGNAL ;
    PORT
      LAYER M4 ;
        RECT  36.528 103.056 36.72 103.08 ;
    END
  END dq[606]
  PIN dq[607]
    DIRECTION OUTPUT ;
    USE SIGNAL ;
    PORT
      LAYER M4 ;
        RECT  36.528 103.2 36.72 103.224 ;
    END
  END dq[607]
  PIN dq[608]
    DIRECTION OUTPUT ;
    USE SIGNAL ;
    PORT
      LAYER M4 ;
        RECT  36.528 103.392 36.72 103.416 ;
    END
  END dq[608]
  PIN dq[609]
    DIRECTION OUTPUT ;
    USE SIGNAL ;
    PORT
      LAYER M4 ;
        RECT  36.528 103.536 36.72 103.56 ;
    END
  END dq[609]
  PIN dq[60]
    DIRECTION OUTPUT ;
    USE SIGNAL ;
    PORT
      LAYER M4 ;
        RECT  36.528 14.16 36.72 14.184 ;
    END
  END dq[60]
  PIN dq[610]
    DIRECTION OUTPUT ;
    USE SIGNAL ;
    PORT
      LAYER M4 ;
        RECT  36.528 103.728 36.72 103.752 ;
    END
  END dq[610]
  PIN dq[611]
    DIRECTION OUTPUT ;
    USE SIGNAL ;
    PORT
      LAYER M4 ;
        RECT  36.528 103.872 36.72 103.896 ;
    END
  END dq[611]
  PIN dq[612]
    DIRECTION OUTPUT ;
    USE SIGNAL ;
    PORT
      LAYER M4 ;
        RECT  36.528 104.016 36.72 104.04 ;
    END
  END dq[612]
  PIN dq[613]
    DIRECTION OUTPUT ;
    USE SIGNAL ;
    PORT
      LAYER M4 ;
        RECT  36.528 104.208 36.72 104.232 ;
    END
  END dq[613]
  PIN dq[614]
    DIRECTION OUTPUT ;
    USE SIGNAL ;
    PORT
      LAYER M4 ;
        RECT  36.528 104.352 36.72 104.376 ;
    END
  END dq[614]
  PIN dq[615]
    DIRECTION OUTPUT ;
    USE SIGNAL ;
    PORT
      LAYER M4 ;
        RECT  36.528 104.544 36.72 104.568 ;
    END
  END dq[615]
  PIN dq[616]
    DIRECTION OUTPUT ;
    USE SIGNAL ;
    PORT
      LAYER M4 ;
        RECT  36.528 104.688 36.72 104.712 ;
    END
  END dq[616]
  PIN dq[617]
    DIRECTION OUTPUT ;
    USE SIGNAL ;
    PORT
      LAYER M4 ;
        RECT  36.528 104.832 36.72 104.856 ;
    END
  END dq[617]
  PIN dq[618]
    DIRECTION OUTPUT ;
    USE SIGNAL ;
    PORT
      LAYER M4 ;
        RECT  36.528 105.024 36.72 105.048 ;
    END
  END dq[618]
  PIN dq[619]
    DIRECTION OUTPUT ;
    USE SIGNAL ;
    PORT
      LAYER M4 ;
        RECT  36.528 105.168 36.72 105.192 ;
    END
  END dq[619]
  PIN dq[61]
    DIRECTION OUTPUT ;
    USE SIGNAL ;
    PORT
      LAYER M4 ;
        RECT  36.528 14.352 36.72 14.376 ;
    END
  END dq[61]
  PIN dq[620]
    DIRECTION OUTPUT ;
    USE SIGNAL ;
    PORT
      LAYER M4 ;
        RECT  36.528 105.36 36.72 105.384 ;
    END
  END dq[620]
  PIN dq[621]
    DIRECTION OUTPUT ;
    USE SIGNAL ;
    PORT
      LAYER M4 ;
        RECT  36.528 105.504 36.72 105.528 ;
    END
  END dq[621]
  PIN dq[622]
    DIRECTION OUTPUT ;
    USE SIGNAL ;
    PORT
      LAYER M4 ;
        RECT  36.528 105.648 36.72 105.672 ;
    END
  END dq[622]
  PIN dq[623]
    DIRECTION OUTPUT ;
    USE SIGNAL ;
    PORT
      LAYER M4 ;
        RECT  36.528 105.84 36.72 105.864 ;
    END
  END dq[623]
  PIN dq[624]
    DIRECTION OUTPUT ;
    USE SIGNAL ;
    PORT
      LAYER M4 ;
        RECT  36.528 105.984 36.72 106.008 ;
    END
  END dq[624]
  PIN dq[625]
    DIRECTION OUTPUT ;
    USE SIGNAL ;
    PORT
      LAYER M4 ;
        RECT  36.528 106.176 36.72 106.2 ;
    END
  END dq[625]
  PIN dq[626]
    DIRECTION OUTPUT ;
    USE SIGNAL ;
    PORT
      LAYER M4 ;
        RECT  36.528 106.32 36.72 106.344 ;
    END
  END dq[626]
  PIN dq[627]
    DIRECTION OUTPUT ;
    USE SIGNAL ;
    PORT
      LAYER M4 ;
        RECT  36.528 106.464 36.72 106.488 ;
    END
  END dq[627]
  PIN dq[628]
    DIRECTION OUTPUT ;
    USE SIGNAL ;
    PORT
      LAYER M4 ;
        RECT  36.528 106.656 36.72 106.68 ;
    END
  END dq[628]
  PIN dq[629]
    DIRECTION OUTPUT ;
    USE SIGNAL ;
    PORT
      LAYER M4 ;
        RECT  36.528 106.8 36.72 106.824 ;
    END
  END dq[629]
  PIN dq[62]
    DIRECTION OUTPUT ;
    USE SIGNAL ;
    PORT
      LAYER M4 ;
        RECT  36.528 14.496 36.72 14.52 ;
    END
  END dq[62]
  PIN dq[630]
    DIRECTION OUTPUT ;
    USE SIGNAL ;
    PORT
      LAYER M4 ;
        RECT  36.528 106.944 36.72 106.968 ;
    END
  END dq[630]
  PIN dq[631]
    DIRECTION OUTPUT ;
    USE SIGNAL ;
    PORT
      LAYER M4 ;
        RECT  36.528 107.136 36.72 107.16 ;
    END
  END dq[631]
  PIN dq[632]
    DIRECTION OUTPUT ;
    USE SIGNAL ;
    PORT
      LAYER M4 ;
        RECT  36.528 107.28 36.72 107.304 ;
    END
  END dq[632]
  PIN dq[633]
    DIRECTION OUTPUT ;
    USE SIGNAL ;
    PORT
      LAYER M4 ;
        RECT  36.528 107.472 36.72 107.496 ;
    END
  END dq[633]
  PIN dq[634]
    DIRECTION OUTPUT ;
    USE SIGNAL ;
    PORT
      LAYER M4 ;
        RECT  36.528 107.616 36.72 107.64 ;
    END
  END dq[634]
  PIN dq[635]
    DIRECTION OUTPUT ;
    USE SIGNAL ;
    PORT
      LAYER M4 ;
        RECT  36.528 107.76 36.72 107.784 ;
    END
  END dq[635]
  PIN dq[636]
    DIRECTION OUTPUT ;
    USE SIGNAL ;
    PORT
      LAYER M4 ;
        RECT  36.528 107.952 36.72 107.976 ;
    END
  END dq[636]
  PIN dq[637]
    DIRECTION OUTPUT ;
    USE SIGNAL ;
    PORT
      LAYER M4 ;
        RECT  36.528 108.096 36.72 108.12 ;
    END
  END dq[637]
  PIN dq[638]
    DIRECTION OUTPUT ;
    USE SIGNAL ;
    PORT
      LAYER M4 ;
        RECT  36.528 108.288 36.72 108.312 ;
    END
  END dq[638]
  PIN dq[639]
    DIRECTION OUTPUT ;
    USE SIGNAL ;
    PORT
      LAYER M4 ;
        RECT  36.528 108.432 36.72 108.456 ;
    END
  END dq[639]
  PIN dq[63]
    DIRECTION OUTPUT ;
    USE SIGNAL ;
    PORT
      LAYER M4 ;
        RECT  36.528 14.688 36.72 14.712 ;
    END
  END dq[63]
  PIN dq[640]
    DIRECTION OUTPUT ;
    USE SIGNAL ;
    PORT
      LAYER M4 ;
        RECT  36.528 108.576 36.72 108.6 ;
    END
  END dq[640]
  PIN dq[641]
    DIRECTION OUTPUT ;
    USE SIGNAL ;
    PORT
      LAYER M4 ;
        RECT  36.528 108.768 36.72 108.792 ;
    END
  END dq[641]
  PIN dq[642]
    DIRECTION OUTPUT ;
    USE SIGNAL ;
    PORT
      LAYER M4 ;
        RECT  36.528 108.912 36.72 108.936 ;
    END
  END dq[642]
  PIN dq[643]
    DIRECTION OUTPUT ;
    USE SIGNAL ;
    PORT
      LAYER M4 ;
        RECT  36.528 109.104 36.72 109.128 ;
    END
  END dq[643]
  PIN dq[644]
    DIRECTION OUTPUT ;
    USE SIGNAL ;
    PORT
      LAYER M4 ;
        RECT  36.528 109.248 36.72 109.272 ;
    END
  END dq[644]
  PIN dq[645]
    DIRECTION OUTPUT ;
    USE SIGNAL ;
    PORT
      LAYER M4 ;
        RECT  36.528 109.392 36.72 109.416 ;
    END
  END dq[645]
  PIN dq[646]
    DIRECTION OUTPUT ;
    USE SIGNAL ;
    PORT
      LAYER M4 ;
        RECT  36.528 109.584 36.72 109.608 ;
    END
  END dq[646]
  PIN dq[647]
    DIRECTION OUTPUT ;
    USE SIGNAL ;
    PORT
      LAYER M4 ;
        RECT  36.528 109.728 36.72 109.752 ;
    END
  END dq[647]
  PIN dq[648]
    DIRECTION OUTPUT ;
    USE SIGNAL ;
    PORT
      LAYER M4 ;
        RECT  36.528 109.92 36.72 109.944 ;
    END
  END dq[648]
  PIN dq[649]
    DIRECTION OUTPUT ;
    USE SIGNAL ;
    PORT
      LAYER M4 ;
        RECT  36.528 110.064 36.72 110.088 ;
    END
  END dq[649]
  PIN dq[64]
    DIRECTION OUTPUT ;
    USE SIGNAL ;
    PORT
      LAYER M4 ;
        RECT  36.528 14.832 36.72 14.856 ;
    END
  END dq[64]
  PIN dq[650]
    DIRECTION OUTPUT ;
    USE SIGNAL ;
    PORT
      LAYER M4 ;
        RECT  36.528 110.208 36.72 110.232 ;
    END
  END dq[650]
  PIN dq[651]
    DIRECTION OUTPUT ;
    USE SIGNAL ;
    PORT
      LAYER M4 ;
        RECT  36.528 110.4 36.72 110.424 ;
    END
  END dq[651]
  PIN dq[652]
    DIRECTION OUTPUT ;
    USE SIGNAL ;
    PORT
      LAYER M4 ;
        RECT  36.528 110.544 36.72 110.568 ;
    END
  END dq[652]
  PIN dq[653]
    DIRECTION OUTPUT ;
    USE SIGNAL ;
    PORT
      LAYER M4 ;
        RECT  36.528 110.688 36.72 110.712 ;
    END
  END dq[653]
  PIN dq[654]
    DIRECTION OUTPUT ;
    USE SIGNAL ;
    PORT
      LAYER M4 ;
        RECT  36.528 110.88 36.72 110.904 ;
    END
  END dq[654]
  PIN dq[655]
    DIRECTION OUTPUT ;
    USE SIGNAL ;
    PORT
      LAYER M4 ;
        RECT  36.528 111.024 36.72 111.048 ;
    END
  END dq[655]
  PIN dq[656]
    DIRECTION OUTPUT ;
    USE SIGNAL ;
    PORT
      LAYER M4 ;
        RECT  36.528 111.216 36.72 111.24 ;
    END
  END dq[656]
  PIN dq[657]
    DIRECTION OUTPUT ;
    USE SIGNAL ;
    PORT
      LAYER M4 ;
        RECT  36.528 111.36 36.72 111.384 ;
    END
  END dq[657]
  PIN dq[658]
    DIRECTION OUTPUT ;
    USE SIGNAL ;
    PORT
      LAYER M4 ;
        RECT  36.528 111.504 36.72 111.528 ;
    END
  END dq[658]
  PIN dq[659]
    DIRECTION OUTPUT ;
    USE SIGNAL ;
    PORT
      LAYER M4 ;
        RECT  36.528 111.696 36.72 111.72 ;
    END
  END dq[659]
  PIN dq[65]
    DIRECTION OUTPUT ;
    USE SIGNAL ;
    PORT
      LAYER M4 ;
        RECT  36.528 14.976 36.72 15 ;
    END
  END dq[65]
  PIN dq[660]
    DIRECTION OUTPUT ;
    USE SIGNAL ;
    PORT
      LAYER M4 ;
        RECT  36.528 111.84 36.72 111.864 ;
    END
  END dq[660]
  PIN dq[661]
    DIRECTION OUTPUT ;
    USE SIGNAL ;
    PORT
      LAYER M4 ;
        RECT  36.528 112.032 36.72 112.056 ;
    END
  END dq[661]
  PIN dq[662]
    DIRECTION OUTPUT ;
    USE SIGNAL ;
    PORT
      LAYER M4 ;
        RECT  36.528 112.176 36.72 112.2 ;
    END
  END dq[662]
  PIN dq[663]
    DIRECTION OUTPUT ;
    USE SIGNAL ;
    PORT
      LAYER M4 ;
        RECT  36.528 112.32 36.72 112.344 ;
    END
  END dq[663]
  PIN dq[664]
    DIRECTION OUTPUT ;
    USE SIGNAL ;
    PORT
      LAYER M4 ;
        RECT  36.528 112.512 36.72 112.536 ;
    END
  END dq[664]
  PIN dq[665]
    DIRECTION OUTPUT ;
    USE SIGNAL ;
    PORT
      LAYER M4 ;
        RECT  36.528 112.656 36.72 112.68 ;
    END
  END dq[665]
  PIN dq[666]
    DIRECTION OUTPUT ;
    USE SIGNAL ;
    PORT
      LAYER M4 ;
        RECT  36.528 112.848 36.72 112.872 ;
    END
  END dq[666]
  PIN dq[667]
    DIRECTION OUTPUT ;
    USE SIGNAL ;
    PORT
      LAYER M4 ;
        RECT  36.528 112.992 36.72 113.016 ;
    END
  END dq[667]
  PIN dq[668]
    DIRECTION OUTPUT ;
    USE SIGNAL ;
    PORT
      LAYER M4 ;
        RECT  36.528 113.136 36.72 113.16 ;
    END
  END dq[668]
  PIN dq[669]
    DIRECTION OUTPUT ;
    USE SIGNAL ;
    PORT
      LAYER M4 ;
        RECT  36.528 113.328 36.72 113.352 ;
    END
  END dq[669]
  PIN dq[66]
    DIRECTION OUTPUT ;
    USE SIGNAL ;
    PORT
      LAYER M4 ;
        RECT  36.528 15.168 36.72 15.192 ;
    END
  END dq[66]
  PIN dq[670]
    DIRECTION OUTPUT ;
    USE SIGNAL ;
    PORT
      LAYER M4 ;
        RECT  36.528 113.472 36.72 113.496 ;
    END
  END dq[670]
  PIN dq[671]
    DIRECTION OUTPUT ;
    USE SIGNAL ;
    PORT
      LAYER M4 ;
        RECT  36.528 113.664 36.72 113.688 ;
    END
  END dq[671]
  PIN dq[672]
    DIRECTION OUTPUT ;
    USE SIGNAL ;
    PORT
      LAYER M4 ;
        RECT  36.528 113.808 36.72 113.832 ;
    END
  END dq[672]
  PIN dq[673]
    DIRECTION OUTPUT ;
    USE SIGNAL ;
    PORT
      LAYER M4 ;
        RECT  36.528 113.952 36.72 113.976 ;
    END
  END dq[673]
  PIN dq[674]
    DIRECTION OUTPUT ;
    USE SIGNAL ;
    PORT
      LAYER M4 ;
        RECT  36.528 114.144 36.72 114.168 ;
    END
  END dq[674]
  PIN dq[675]
    DIRECTION OUTPUT ;
    USE SIGNAL ;
    PORT
      LAYER M4 ;
        RECT  36.528 114.288 36.72 114.312 ;
    END
  END dq[675]
  PIN dq[676]
    DIRECTION OUTPUT ;
    USE SIGNAL ;
    PORT
      LAYER M4 ;
        RECT  36.528 114.432 36.72 114.456 ;
    END
  END dq[676]
  PIN dq[677]
    DIRECTION OUTPUT ;
    USE SIGNAL ;
    PORT
      LAYER M4 ;
        RECT  36.528 114.624 36.72 114.648 ;
    END
  END dq[677]
  PIN dq[678]
    DIRECTION OUTPUT ;
    USE SIGNAL ;
    PORT
      LAYER M4 ;
        RECT  36.528 114.768 36.72 114.792 ;
    END
  END dq[678]
  PIN dq[679]
    DIRECTION OUTPUT ;
    USE SIGNAL ;
    PORT
      LAYER M4 ;
        RECT  36.528 114.96 36.72 114.984 ;
    END
  END dq[679]
  PIN dq[67]
    DIRECTION OUTPUT ;
    USE SIGNAL ;
    PORT
      LAYER M4 ;
        RECT  36.528 15.312 36.72 15.336 ;
    END
  END dq[67]
  PIN dq[680]
    DIRECTION OUTPUT ;
    USE SIGNAL ;
    PORT
      LAYER M4 ;
        RECT  36.528 115.104 36.72 115.128 ;
    END
  END dq[680]
  PIN dq[681]
    DIRECTION OUTPUT ;
    USE SIGNAL ;
    PORT
      LAYER M4 ;
        RECT  36.528 115.248 36.72 115.272 ;
    END
  END dq[681]
  PIN dq[682]
    DIRECTION OUTPUT ;
    USE SIGNAL ;
    PORT
      LAYER M4 ;
        RECT  36.528 115.44 36.72 115.464 ;
    END
  END dq[682]
  PIN dq[683]
    DIRECTION OUTPUT ;
    USE SIGNAL ;
    PORT
      LAYER M4 ;
        RECT  36.528 115.584 36.72 115.608 ;
    END
  END dq[683]
  PIN dq[684]
    DIRECTION OUTPUT ;
    USE SIGNAL ;
    PORT
      LAYER M4 ;
        RECT  36.528 115.776 36.72 115.8 ;
    END
  END dq[684]
  PIN dq[685]
    DIRECTION OUTPUT ;
    USE SIGNAL ;
    PORT
      LAYER M4 ;
        RECT  36.528 115.92 36.72 115.944 ;
    END
  END dq[685]
  PIN dq[686]
    DIRECTION OUTPUT ;
    USE SIGNAL ;
    PORT
      LAYER M4 ;
        RECT  36.528 116.064 36.72 116.088 ;
    END
  END dq[686]
  PIN dq[687]
    DIRECTION OUTPUT ;
    USE SIGNAL ;
    PORT
      LAYER M4 ;
        RECT  36.528 116.256 36.72 116.28 ;
    END
  END dq[687]
  PIN dq[688]
    DIRECTION OUTPUT ;
    USE SIGNAL ;
    PORT
      LAYER M4 ;
        RECT  36.528 116.4 36.72 116.424 ;
    END
  END dq[688]
  PIN dq[689]
    DIRECTION OUTPUT ;
    USE SIGNAL ;
    PORT
      LAYER M4 ;
        RECT  36.528 116.592 36.72 116.616 ;
    END
  END dq[689]
  PIN dq[68]
    DIRECTION OUTPUT ;
    USE SIGNAL ;
    PORT
      LAYER M4 ;
        RECT  36.528 15.504 36.72 15.528 ;
    END
  END dq[68]
  PIN dq[69]
    DIRECTION OUTPUT ;
    USE SIGNAL ;
    PORT
      LAYER M4 ;
        RECT  36.528 15.648 36.72 15.672 ;
    END
  END dq[69]
  PIN dq[6]
    DIRECTION OUTPUT ;
    USE SIGNAL ;
    PORT
      LAYER M4 ;
        RECT  36.528 5.376 36.72 5.4 ;
    END
  END dq[6]
  PIN dq[70]
    DIRECTION OUTPUT ;
    USE SIGNAL ;
    PORT
      LAYER M4 ;
        RECT  36.528 15.792 36.72 15.816 ;
    END
  END dq[70]
  PIN dq[71]
    DIRECTION OUTPUT ;
    USE SIGNAL ;
    PORT
      LAYER M4 ;
        RECT  36.528 15.984 36.72 16.008 ;
    END
  END dq[71]
  PIN dq[72]
    DIRECTION OUTPUT ;
    USE SIGNAL ;
    PORT
      LAYER M4 ;
        RECT  36.528 16.128 36.72 16.152 ;
    END
  END dq[72]
  PIN dq[73]
    DIRECTION OUTPUT ;
    USE SIGNAL ;
    PORT
      LAYER M4 ;
        RECT  36.528 16.32 36.72 16.344 ;
    END
  END dq[73]
  PIN dq[74]
    DIRECTION OUTPUT ;
    USE SIGNAL ;
    PORT
      LAYER M4 ;
        RECT  36.528 16.464 36.72 16.488 ;
    END
  END dq[74]
  PIN dq[75]
    DIRECTION OUTPUT ;
    USE SIGNAL ;
    PORT
      LAYER M4 ;
        RECT  36.528 16.608 36.72 16.632 ;
    END
  END dq[75]
  PIN dq[76]
    DIRECTION OUTPUT ;
    USE SIGNAL ;
    PORT
      LAYER M4 ;
        RECT  36.528 16.8 36.72 16.824 ;
    END
  END dq[76]
  PIN dq[77]
    DIRECTION OUTPUT ;
    USE SIGNAL ;
    PORT
      LAYER M4 ;
        RECT  36.528 16.944 36.72 16.968 ;
    END
  END dq[77]
  PIN dq[78]
    DIRECTION OUTPUT ;
    USE SIGNAL ;
    PORT
      LAYER M4 ;
        RECT  36.528 17.088 36.72 17.112 ;
    END
  END dq[78]
  PIN dq[79]
    DIRECTION OUTPUT ;
    USE SIGNAL ;
    PORT
      LAYER M4 ;
        RECT  36.528 17.28 36.72 17.304 ;
    END
  END dq[79]
  PIN dq[7]
    DIRECTION OUTPUT ;
    USE SIGNAL ;
    PORT
      LAYER M4 ;
        RECT  36.528 5.568 36.72 5.592 ;
    END
  END dq[7]
  PIN dq[80]
    DIRECTION OUTPUT ;
    USE SIGNAL ;
    PORT
      LAYER M4 ;
        RECT  36.528 17.424 36.72 17.448 ;
    END
  END dq[80]
  PIN dq[81]
    DIRECTION OUTPUT ;
    USE SIGNAL ;
    PORT
      LAYER M4 ;
        RECT  36.528 17.616 36.72 17.64 ;
    END
  END dq[81]
  PIN dq[82]
    DIRECTION OUTPUT ;
    USE SIGNAL ;
    PORT
      LAYER M4 ;
        RECT  36.528 17.76 36.72 17.784 ;
    END
  END dq[82]
  PIN dq[83]
    DIRECTION OUTPUT ;
    USE SIGNAL ;
    PORT
      LAYER M4 ;
        RECT  36.528 17.904 36.72 17.928 ;
    END
  END dq[83]
  PIN dq[84]
    DIRECTION OUTPUT ;
    USE SIGNAL ;
    PORT
      LAYER M4 ;
        RECT  36.528 18.096 36.72 18.12 ;
    END
  END dq[84]
  PIN dq[85]
    DIRECTION OUTPUT ;
    USE SIGNAL ;
    PORT
      LAYER M4 ;
        RECT  36.528 18.24 36.72 18.264 ;
    END
  END dq[85]
  PIN dq[86]
    DIRECTION OUTPUT ;
    USE SIGNAL ;
    PORT
      LAYER M4 ;
        RECT  36.528 18.432 36.72 18.456 ;
    END
  END dq[86]
  PIN dq[87]
    DIRECTION OUTPUT ;
    USE SIGNAL ;
    PORT
      LAYER M4 ;
        RECT  36.528 18.576 36.72 18.6 ;
    END
  END dq[87]
  PIN dq[88]
    DIRECTION OUTPUT ;
    USE SIGNAL ;
    PORT
      LAYER M4 ;
        RECT  36.528 18.72 36.72 18.744 ;
    END
  END dq[88]
  PIN dq[89]
    DIRECTION OUTPUT ;
    USE SIGNAL ;
    PORT
      LAYER M4 ;
        RECT  36.528 18.912 36.72 18.936 ;
    END
  END dq[89]
  PIN dq[8]
    DIRECTION OUTPUT ;
    USE SIGNAL ;
    PORT
      LAYER M4 ;
        RECT  36.528 5.712 36.72 5.736 ;
    END
  END dq[8]
  PIN dq[90]
    DIRECTION OUTPUT ;
    USE SIGNAL ;
    PORT
      LAYER M4 ;
        RECT  36.528 19.056 36.72 19.08 ;
    END
  END dq[90]
  PIN dq[91]
    DIRECTION OUTPUT ;
    USE SIGNAL ;
    PORT
      LAYER M4 ;
        RECT  36.528 19.248 36.72 19.272 ;
    END
  END dq[91]
  PIN dq[92]
    DIRECTION OUTPUT ;
    USE SIGNAL ;
    PORT
      LAYER M4 ;
        RECT  36.528 19.392 36.72 19.416 ;
    END
  END dq[92]
  PIN dq[93]
    DIRECTION OUTPUT ;
    USE SIGNAL ;
    PORT
      LAYER M4 ;
        RECT  36.528 19.536 36.72 19.56 ;
    END
  END dq[93]
  PIN dq[94]
    DIRECTION OUTPUT ;
    USE SIGNAL ;
    PORT
      LAYER M4 ;
        RECT  36.528 19.728 36.72 19.752 ;
    END
  END dq[94]
  PIN dq[95]
    DIRECTION OUTPUT ;
    USE SIGNAL ;
    PORT
      LAYER M4 ;
        RECT  36.528 19.872 36.72 19.896 ;
    END
  END dq[95]
  PIN dq[96]
    DIRECTION OUTPUT ;
    USE SIGNAL ;
    PORT
      LAYER M4 ;
        RECT  36.528 20.064 36.72 20.088 ;
    END
  END dq[96]
  PIN dq[97]
    DIRECTION OUTPUT ;
    USE SIGNAL ;
    PORT
      LAYER M4 ;
        RECT  36.528 20.208 36.72 20.232 ;
    END
  END dq[97]
  PIN dq[98]
    DIRECTION OUTPUT ;
    USE SIGNAL ;
    PORT
      LAYER M4 ;
        RECT  36.528 20.352 36.72 20.376 ;
    END
  END dq[98]
  PIN dq[99]
    DIRECTION OUTPUT ;
    USE SIGNAL ;
    PORT
      LAYER M4 ;
        RECT  36.528 20.544 36.72 20.568 ;
    END
  END dq[99]
  PIN dq[9]
    DIRECTION OUTPUT ;
    USE SIGNAL ;
    PORT
      LAYER M4 ;
        RECT  36.528 5.856 36.72 5.88 ;
    END
  END dq[9]
  PIN VDD
    DIRECTION INOUT ;
    USE POWER ;
    PORT
      LAYER M5 ;
        RECT  32.292 2.151 32.412 118.809 ;
        RECT  29.592 2.151 29.712 118.809 ;
        RECT  26.892 2.151 27.012 118.809 ;
        RECT  24.192 2.151 24.312 118.809 ;
        RECT  21.492 2.151 21.612 118.809 ;
        RECT  18.792 2.151 18.912 118.809 ;
        RECT  16.092 2.151 16.212 118.809 ;
        RECT  13.392 2.151 13.512 118.809 ;
        RECT  10.692 2.151 10.812 118.809 ;
        RECT  7.992 2.151 8.112 118.809 ;
        RECT  5.292 2.151 5.412 118.809 ;
        RECT  2.592 2.151 2.712 118.809 ;
    END
  END VDD
  PIN VSS
    DIRECTION INOUT ;
    USE GROUND ;
    PORT
      LAYER M5 ;
        RECT  32.1 2.137 32.22 118.823 ;
        RECT  29.4 2.137 29.52 118.823 ;
        RECT  26.7 2.137 26.82 118.823 ;
        RECT  24 2.137 24.12 118.823 ;
        RECT  21.3 2.137 21.42 118.823 ;
        RECT  18.6 2.137 18.72 118.823 ;
        RECT  15.9 2.137 16.02 118.823 ;
        RECT  13.2 2.137 13.32 118.823 ;
        RECT  10.5 2.137 10.62 118.823 ;
        RECT  7.8 2.137 7.92 118.823 ;
        RECT  5.1 2.137 5.22 118.823 ;
        RECT  2.4 2.137 2.52 118.823 ;
    END
  END VSS
  # OT_OBS_CLOSED layer=M5 d_um=1.536 added=94
  OBS
    LAYER RVTN ;
     RECT  2.16 2.16 34.56 2.295 ;
     RECT  2.16 2.565 34.56 2.835 ;
     RECT  2.16 3.105 34.56 3.375 ;
     RECT  2.16 3.645 34.56 3.915 ;
     RECT  2.16 4.185 34.56 4.455 ;
     RECT  2.16 4.725 34.56 4.995 ;
     RECT  2.16 5.265 34.56 5.535 ;
     RECT  2.16 5.805 34.56 6.075 ;
     RECT  2.16 6.345 34.56 6.615 ;
     RECT  2.16 6.885 34.56 7.155 ;
     RECT  2.16 7.425 34.56 7.695 ;
     RECT  2.16 7.965 34.56 8.235 ;
     RECT  2.16 8.505 34.56 8.775 ;
     RECT  2.16 9.045 34.56 9.315 ;
     RECT  2.16 9.585 34.56 9.855 ;
     RECT  2.16 10.125 34.56 10.395 ;
     RECT  2.16 10.665 34.56 10.935 ;
     RECT  2.16 11.205 34.56 11.475 ;
     RECT  2.16 11.745 34.56 12.015 ;
     RECT  2.16 12.285 34.56 12.555 ;
     RECT  2.16 12.825 34.56 13.095 ;
     RECT  2.16 13.365 34.56 13.635 ;
     RECT  2.16 13.905 34.56 14.175 ;
     RECT  2.16 14.445 34.56 14.715 ;
     RECT  2.16 14.985 34.56 15.255 ;
     RECT  2.16 15.525 34.56 15.795 ;
     RECT  2.16 16.065 34.56 16.335 ;
     RECT  2.16 16.605 34.56 16.875 ;
     RECT  2.16 17.145 34.56 17.415 ;
     RECT  2.16 17.685 34.56 17.955 ;
     RECT  2.16 18.225 34.56 18.495 ;
     RECT  2.16 18.765 34.56 19.035 ;
     RECT  2.16 19.305 34.56 19.575 ;
     RECT  2.16 19.845 34.56 20.115 ;
     RECT  2.16 20.385 34.56 20.655 ;
     RECT  2.16 20.925 34.56 21.195 ;
     RECT  2.16 21.465 34.56 21.735 ;
     RECT  2.16 22.005 34.56 22.275 ;
     RECT  2.16 22.545 34.56 22.815 ;
     RECT  2.16 23.085 34.56 23.355 ;
     RECT  2.16 23.625 34.56 23.895 ;
     RECT  2.16 24.165 34.56 24.435 ;
     RECT  2.16 24.705 34.56 24.975 ;
     RECT  2.16 25.245 34.56 25.515 ;
     RECT  2.16 25.785 34.56 26.055 ;
     RECT  2.16 26.325 34.56 26.595 ;
     RECT  2.16 26.865 34.56 27.135 ;
     RECT  2.16 27.405 34.56 27.675 ;
     RECT  2.16 27.945 34.56 28.215 ;
     RECT  2.16 28.485 34.56 28.755 ;
     RECT  2.16 29.025 34.56 29.295 ;
     RECT  2.16 29.565 34.56 29.835 ;
     RECT  2.16 30.105 34.56 30.375 ;
     RECT  2.16 30.645 34.56 30.915 ;
     RECT  2.16 31.185 34.56 31.455 ;
     RECT  2.16 31.725 34.56 31.995 ;
     RECT  2.16 32.265 34.56 32.535 ;
     RECT  2.16 32.805 34.56 33.075 ;
     RECT  2.16 33.345 34.56 33.615 ;
     RECT  2.16 33.885 34.56 34.155 ;
     RECT  2.16 34.425 34.56 34.695 ;
     RECT  2.16 34.965 34.56 35.235 ;
     RECT  2.16 35.505 34.56 35.775 ;
     RECT  2.16 36.045 34.56 36.315 ;
     RECT  2.16 36.585 34.56 36.855 ;
     RECT  2.16 37.125 34.56 37.395 ;
     RECT  2.16 37.665 34.56 37.935 ;
     RECT  2.16 38.205 34.56 38.475 ;
     RECT  2.16 38.745 34.56 39.015 ;
     RECT  2.16 39.285 34.56 39.555 ;
     RECT  2.16 39.825 34.56 40.095 ;
     RECT  2.16 40.365 34.56 40.635 ;
     RECT  2.16 40.905 34.56 41.175 ;
     RECT  2.16 41.445 34.56 41.715 ;
     RECT  2.16 41.985 34.56 42.255 ;
     RECT  2.16 42.525 34.56 42.795 ;
     RECT  2.16 43.065 34.56 43.335 ;
     RECT  2.16 43.605 34.56 43.875 ;
     RECT  2.16 44.145 34.56 44.415 ;
     RECT  2.16 44.685 34.56 44.955 ;
     RECT  2.16 45.225 34.56 45.495 ;
     RECT  2.16 45.765 34.56 46.035 ;
     RECT  2.16 46.305 34.56 46.575 ;
     RECT  2.16 46.845 34.56 47.115 ;
     RECT  2.16 47.385 34.56 47.655 ;
     RECT  2.16 47.925 34.56 48.195 ;
     RECT  2.16 48.465 34.56 48.735 ;
     RECT  2.16 49.005 34.56 49.275 ;
     RECT  2.16 49.545 34.56 49.815 ;
     RECT  2.16 50.085 34.56 50.355 ;
     RECT  2.16 50.625 34.56 50.895 ;
     RECT  2.16 51.165 34.56 51.435 ;
     RECT  2.16 51.705 34.56 51.975 ;
     RECT  2.16 52.245 34.56 52.515 ;
     RECT  2.16 52.785 34.56 53.055 ;
     RECT  2.16 53.325 34.56 53.595 ;
     RECT  2.16 53.865 34.56 54.135 ;
     RECT  2.16 54.405 34.56 54.675 ;
     RECT  2.16 54.945 34.56 55.215 ;
     RECT  2.16 55.485 34.56 55.755 ;
     RECT  2.16 56.025 34.56 56.295 ;
     RECT  2.16 56.565 34.56 56.835 ;
     RECT  2.16 57.105 34.56 57.375 ;
     RECT  2.16 57.645 34.56 57.915 ;
     RECT  2.16 58.185 34.56 58.455 ;
     RECT  2.16 58.725 34.56 58.995 ;
     RECT  2.16 59.265 34.56 59.535 ;
     RECT  2.16 59.805 34.56 60.075 ;
     RECT  2.16 60.345 34.56 60.615 ;
     RECT  2.16 60.885 34.56 61.155 ;
     RECT  2.16 61.425 34.56 61.695 ;
     RECT  2.16 61.965 34.56 62.235 ;
     RECT  2.16 62.505 34.56 62.775 ;
     RECT  2.16 63.045 34.56 63.315 ;
     RECT  2.16 63.585 34.56 63.855 ;
     RECT  2.16 64.125 34.56 64.395 ;
     RECT  2.16 64.665 34.56 64.935 ;
     RECT  2.16 65.205 34.56 65.475 ;
     RECT  2.16 65.745 34.56 66.015 ;
     RECT  2.16 66.285 34.56 66.555 ;
     RECT  2.16 66.825 34.56 67.095 ;
     RECT  2.16 67.365 34.56 67.635 ;
     RECT  2.16 67.905 34.56 68.175 ;
     RECT  2.16 68.445 34.56 68.715 ;
     RECT  2.16 68.985 34.56 69.255 ;
     RECT  2.16 69.525 34.56 69.795 ;
     RECT  2.16 70.065 34.56 70.335 ;
     RECT  2.16 70.605 34.56 70.875 ;
     RECT  2.16 71.145 34.56 71.415 ;
     RECT  2.16 71.685 34.56 71.955 ;
     RECT  2.16 72.225 34.56 72.495 ;
     RECT  2.16 72.765 34.56 73.035 ;
     RECT  2.16 73.305 34.56 73.575 ;
     RECT  2.16 73.845 34.56 74.115 ;
     RECT  2.16 74.385 34.56 74.655 ;
     RECT  2.16 74.925 34.56 75.195 ;
     RECT  2.16 75.465 34.56 75.735 ;
     RECT  2.16 76.005 34.56 76.275 ;
     RECT  2.16 76.545 34.56 76.815 ;
     RECT  2.16 77.085 34.56 77.355 ;
     RECT  2.16 77.625 34.56 77.895 ;
     RECT  2.16 78.165 34.56 78.435 ;
     RECT  2.16 78.705 34.56 78.975 ;
     RECT  2.16 79.245 34.56 79.515 ;
     RECT  2.16 79.785 34.56 80.055 ;
     RECT  2.16 80.325 34.56 80.595 ;
     RECT  2.16 80.865 34.56 81.135 ;
     RECT  2.16 81.405 34.56 81.675 ;
     RECT  2.16 81.945 34.56 82.215 ;
     RECT  2.16 82.485 34.56 82.755 ;
     RECT  2.16 83.025 34.56 83.295 ;
     RECT  2.16 83.565 34.56 83.835 ;
     RECT  2.16 84.105 34.56 84.375 ;
     RECT  2.16 84.645 34.56 84.915 ;
     RECT  2.16 85.185 34.56 85.455 ;
     RECT  2.16 85.725 34.56 85.995 ;
     RECT  2.16 86.265 34.56 86.535 ;
     RECT  2.16 86.805 34.56 87.075 ;
     RECT  2.16 87.345 34.56 87.615 ;
     RECT  2.16 87.885 34.56 88.155 ;
     RECT  2.16 88.425 34.56 88.695 ;
     RECT  2.16 88.965 34.56 89.235 ;
     RECT  2.16 89.505 34.56 89.775 ;
     RECT  2.16 90.045 34.56 90.315 ;
     RECT  2.16 90.585 34.56 90.855 ;
     RECT  2.16 91.125 34.56 91.395 ;
     RECT  2.16 91.665 34.56 91.935 ;
     RECT  2.16 92.205 34.56 92.475 ;
     RECT  2.16 92.745 34.56 93.015 ;
     RECT  2.16 93.285 34.56 93.555 ;
     RECT  2.16 93.825 34.56 94.095 ;
     RECT  2.16 94.365 34.56 94.635 ;
     RECT  2.16 94.905 34.56 95.175 ;
     RECT  2.16 95.445 34.56 95.715 ;
     RECT  2.16 95.985 34.56 96.255 ;
     RECT  2.16 96.525 34.56 96.795 ;
     RECT  2.16 97.065 34.56 97.335 ;
     RECT  2.16 97.605 34.56 97.875 ;
     RECT  2.16 98.145 34.56 98.415 ;
     RECT  2.16 98.685 34.56 98.955 ;
     RECT  2.16 99.225 34.56 99.495 ;
     RECT  2.16 99.765 34.56 100.035 ;
     RECT  2.16 100.305 34.56 100.575 ;
     RECT  2.16 100.845 34.56 101.115 ;
     RECT  2.16 101.385 34.56 101.655 ;
     RECT  2.16 101.925 34.56 102.195 ;
     RECT  2.16 102.465 34.56 102.735 ;
     RECT  2.16 103.005 34.56 103.275 ;
     RECT  2.16 103.545 34.56 103.815 ;
     RECT  2.16 104.085 34.56 104.355 ;
     RECT  2.16 104.625 34.56 104.895 ;
     RECT  2.16 105.165 34.56 105.435 ;
     RECT  2.16 105.705 34.56 105.975 ;
     RECT  2.16 106.245 34.56 106.515 ;
     RECT  2.16 106.785 34.56 107.055 ;
     RECT  2.16 107.325 34.56 107.595 ;
     RECT  2.16 107.865 34.56 108.135 ;
     RECT  2.16 108.405 34.56 108.675 ;
     RECT  2.16 108.945 34.56 109.215 ;
     RECT  2.16 109.485 34.56 109.755 ;
     RECT  2.16 110.025 34.56 110.295 ;
     RECT  2.16 110.565 34.56 110.835 ;
     RECT  2.16 111.105 34.56 111.375 ;
     RECT  2.16 111.645 34.56 111.915 ;
     RECT  2.16 112.185 34.56 112.455 ;
     RECT  2.16 112.725 34.56 112.995 ;
     RECT  2.16 113.265 34.56 113.535 ;
     RECT  2.16 113.805 34.56 114.075 ;
     RECT  2.16 114.345 34.56 114.615 ;
     RECT  2.16 114.885 34.56 115.155 ;
     RECT  2.16 115.425 34.56 115.695 ;
     RECT  2.16 115.965 34.56 116.235 ;
     RECT  2.16 116.505 34.56 116.775 ;
     RECT  2.16 117.045 34.56 117.315 ;
     RECT  2.16 117.585 34.56 117.855 ;
     RECT  2.16 118.125 34.56 118.395 ;
     RECT  2.16 118.665 34.56 118.8 ;
    LAYER RVTP ;
     RECT  2.16 2.295 34.56 2.565 ;
     RECT  2.16 2.835 34.56 3.105 ;
     RECT  2.16 3.375 34.56 3.645 ;
     RECT  2.16 3.915 34.56 4.185 ;
     RECT  2.16 4.455 34.56 4.725 ;
     RECT  2.16 4.995 34.56 5.265 ;
     RECT  2.16 5.535 34.56 5.805 ;
     RECT  2.16 6.075 34.56 6.345 ;
     RECT  2.16 6.615 34.56 6.885 ;
     RECT  2.16 7.155 34.56 7.425 ;
     RECT  2.16 7.695 34.56 7.965 ;
     RECT  2.16 8.235 34.56 8.505 ;
     RECT  2.16 8.775 34.56 9.045 ;
     RECT  2.16 9.315 34.56 9.585 ;
     RECT  2.16 9.855 34.56 10.125 ;
     RECT  2.16 10.395 34.56 10.665 ;
     RECT  2.16 10.935 34.56 11.205 ;
     RECT  2.16 11.475 34.56 11.745 ;
     RECT  2.16 12.015 34.56 12.285 ;
     RECT  2.16 12.555 34.56 12.825 ;
     RECT  2.16 13.095 34.56 13.365 ;
     RECT  2.16 13.635 34.56 13.905 ;
     RECT  2.16 14.175 34.56 14.445 ;
     RECT  2.16 14.715 34.56 14.985 ;
     RECT  2.16 15.255 34.56 15.525 ;
     RECT  2.16 15.795 34.56 16.065 ;
     RECT  2.16 16.335 34.56 16.605 ;
     RECT  2.16 16.875 34.56 17.145 ;
     RECT  2.16 17.415 34.56 17.685 ;
     RECT  2.16 17.955 34.56 18.225 ;
     RECT  2.16 18.495 34.56 18.765 ;
     RECT  2.16 19.035 34.56 19.305 ;
     RECT  2.16 19.575 34.56 19.845 ;
     RECT  2.16 20.115 34.56 20.385 ;
     RECT  2.16 20.655 34.56 20.925 ;
     RECT  2.16 21.195 34.56 21.465 ;
     RECT  2.16 21.735 34.56 22.005 ;
     RECT  2.16 22.275 34.56 22.545 ;
     RECT  2.16 22.815 34.56 23.085 ;
     RECT  2.16 23.355 34.56 23.625 ;
     RECT  2.16 23.895 34.56 24.165 ;
     RECT  2.16 24.435 34.56 24.705 ;
     RECT  2.16 24.975 34.56 25.245 ;
     RECT  2.16 25.515 34.56 25.785 ;
     RECT  2.16 26.055 34.56 26.325 ;
     RECT  2.16 26.595 34.56 26.865 ;
     RECT  2.16 27.135 34.56 27.405 ;
     RECT  2.16 27.675 34.56 27.945 ;
     RECT  2.16 28.215 34.56 28.485 ;
     RECT  2.16 28.755 34.56 29.025 ;
     RECT  2.16 29.295 34.56 29.565 ;
     RECT  2.16 29.835 34.56 30.105 ;
     RECT  2.16 30.375 34.56 30.645 ;
     RECT  2.16 30.915 34.56 31.185 ;
     RECT  2.16 31.455 34.56 31.725 ;
     RECT  2.16 31.995 34.56 32.265 ;
     RECT  2.16 32.535 34.56 32.805 ;
     RECT  2.16 33.075 34.56 33.345 ;
     RECT  2.16 33.615 34.56 33.885 ;
     RECT  2.16 34.155 34.56 34.425 ;
     RECT  2.16 34.695 34.56 34.965 ;
     RECT  2.16 35.235 34.56 35.505 ;
     RECT  2.16 35.775 34.56 36.045 ;
     RECT  2.16 36.315 34.56 36.585 ;
     RECT  2.16 36.855 34.56 37.125 ;
     RECT  2.16 37.395 34.56 37.665 ;
     RECT  2.16 37.935 34.56 38.205 ;
     RECT  2.16 38.475 34.56 38.745 ;
     RECT  2.16 39.015 34.56 39.285 ;
     RECT  2.16 39.555 34.56 39.825 ;
     RECT  2.16 40.095 34.56 40.365 ;
     RECT  2.16 40.635 34.56 40.905 ;
     RECT  2.16 41.175 34.56 41.445 ;
     RECT  2.16 41.715 34.56 41.985 ;
     RECT  2.16 42.255 34.56 42.525 ;
     RECT  2.16 42.795 34.56 43.065 ;
     RECT  2.16 43.335 34.56 43.605 ;
     RECT  2.16 43.875 34.56 44.145 ;
     RECT  2.16 44.415 34.56 44.685 ;
     RECT  2.16 44.955 34.56 45.225 ;
     RECT  2.16 45.495 34.56 45.765 ;
     RECT  2.16 46.035 34.56 46.305 ;
     RECT  2.16 46.575 34.56 46.845 ;
     RECT  2.16 47.115 34.56 47.385 ;
     RECT  2.16 47.655 34.56 47.925 ;
     RECT  2.16 48.195 34.56 48.465 ;
     RECT  2.16 48.735 34.56 49.005 ;
     RECT  2.16 49.275 34.56 49.545 ;
     RECT  2.16 49.815 34.56 50.085 ;
     RECT  2.16 50.355 34.56 50.625 ;
     RECT  2.16 50.895 34.56 51.165 ;
     RECT  2.16 51.435 34.56 51.705 ;
     RECT  2.16 51.975 34.56 52.245 ;
     RECT  2.16 52.515 34.56 52.785 ;
     RECT  2.16 53.055 34.56 53.325 ;
     RECT  2.16 53.595 34.56 53.865 ;
     RECT  2.16 54.135 34.56 54.405 ;
     RECT  2.16 54.675 34.56 54.945 ;
     RECT  2.16 55.215 34.56 55.485 ;
     RECT  2.16 55.755 34.56 56.025 ;
     RECT  2.16 56.295 34.56 56.565 ;
     RECT  2.16 56.835 34.56 57.105 ;
     RECT  2.16 57.375 34.56 57.645 ;
     RECT  2.16 57.915 34.56 58.185 ;
     RECT  2.16 58.455 34.56 58.725 ;
     RECT  2.16 58.995 34.56 59.265 ;
     RECT  2.16 59.535 34.56 59.805 ;
     RECT  2.16 60.075 34.56 60.345 ;
     RECT  2.16 60.615 34.56 60.885 ;
     RECT  2.16 61.155 34.56 61.425 ;
     RECT  2.16 61.695 34.56 61.965 ;
     RECT  2.16 62.235 34.56 62.505 ;
     RECT  2.16 62.775 34.56 63.045 ;
     RECT  2.16 63.315 34.56 63.585 ;
     RECT  2.16 63.855 34.56 64.125 ;
     RECT  2.16 64.395 34.56 64.665 ;
     RECT  2.16 64.935 34.56 65.205 ;
     RECT  2.16 65.475 34.56 65.745 ;
     RECT  2.16 66.015 34.56 66.285 ;
     RECT  2.16 66.555 34.56 66.825 ;
     RECT  2.16 67.095 34.56 67.365 ;
     RECT  2.16 67.635 34.56 67.905 ;
     RECT  2.16 68.175 34.56 68.445 ;
     RECT  2.16 68.715 34.56 68.985 ;
     RECT  2.16 69.255 34.56 69.525 ;
     RECT  2.16 69.795 34.56 70.065 ;
     RECT  2.16 70.335 34.56 70.605 ;
     RECT  2.16 70.875 34.56 71.145 ;
     RECT  2.16 71.415 34.56 71.685 ;
     RECT  2.16 71.955 34.56 72.225 ;
     RECT  2.16 72.495 34.56 72.765 ;
     RECT  2.16 73.035 34.56 73.305 ;
     RECT  2.16 73.575 34.56 73.845 ;
     RECT  2.16 74.115 34.56 74.385 ;
     RECT  2.16 74.655 34.56 74.925 ;
     RECT  2.16 75.195 34.56 75.465 ;
     RECT  2.16 75.735 34.56 76.005 ;
     RECT  2.16 76.275 34.56 76.545 ;
     RECT  2.16 76.815 34.56 77.085 ;
     RECT  2.16 77.355 34.56 77.625 ;
     RECT  2.16 77.895 34.56 78.165 ;
     RECT  2.16 78.435 34.56 78.705 ;
     RECT  2.16 78.975 34.56 79.245 ;
     RECT  2.16 79.515 34.56 79.785 ;
     RECT  2.16 80.055 34.56 80.325 ;
     RECT  2.16 80.595 34.56 80.865 ;
     RECT  2.16 81.135 34.56 81.405 ;
     RECT  2.16 81.675 34.56 81.945 ;
     RECT  2.16 82.215 34.56 82.485 ;
     RECT  2.16 82.755 34.56 83.025 ;
     RECT  2.16 83.295 34.56 83.565 ;
     RECT  2.16 83.835 34.56 84.105 ;
     RECT  2.16 84.375 34.56 84.645 ;
     RECT  2.16 84.915 34.56 85.185 ;
     RECT  2.16 85.455 34.56 85.725 ;
     RECT  2.16 85.995 34.56 86.265 ;
     RECT  2.16 86.535 34.56 86.805 ;
     RECT  2.16 87.075 34.56 87.345 ;
     RECT  2.16 87.615 34.56 87.885 ;
     RECT  2.16 88.155 34.56 88.425 ;
     RECT  2.16 88.695 34.56 88.965 ;
     RECT  2.16 89.235 34.56 89.505 ;
     RECT  2.16 89.775 34.56 90.045 ;
     RECT  2.16 90.315 34.56 90.585 ;
     RECT  2.16 90.855 34.56 91.125 ;
     RECT  2.16 91.395 34.56 91.665 ;
     RECT  2.16 91.935 34.56 92.205 ;
     RECT  2.16 92.475 34.56 92.745 ;
     RECT  2.16 93.015 34.56 93.285 ;
     RECT  2.16 93.555 34.56 93.825 ;
     RECT  2.16 94.095 34.56 94.365 ;
     RECT  2.16 94.635 34.56 94.905 ;
     RECT  2.16 95.175 34.56 95.445 ;
     RECT  2.16 95.715 34.56 95.985 ;
     RECT  2.16 96.255 34.56 96.525 ;
     RECT  2.16 96.795 34.56 97.065 ;
     RECT  2.16 97.335 34.56 97.605 ;
     RECT  2.16 97.875 34.56 98.145 ;
     RECT  2.16 98.415 34.56 98.685 ;
     RECT  2.16 98.955 34.56 99.225 ;
     RECT  2.16 99.495 34.56 99.765 ;
     RECT  2.16 100.035 34.56 100.305 ;
     RECT  2.16 100.575 34.56 100.845 ;
     RECT  2.16 101.115 34.56 101.385 ;
     RECT  2.16 101.655 34.56 101.925 ;
     RECT  2.16 102.195 34.56 102.465 ;
     RECT  2.16 102.735 34.56 103.005 ;
     RECT  2.16 103.275 34.56 103.545 ;
     RECT  2.16 103.815 34.56 104.085 ;
     RECT  2.16 104.355 34.56 104.625 ;
     RECT  2.16 104.895 34.56 105.165 ;
     RECT  2.16 105.435 34.56 105.705 ;
     RECT  2.16 105.975 34.56 106.245 ;
     RECT  2.16 106.515 34.56 106.785 ;
     RECT  2.16 107.055 34.56 107.325 ;
     RECT  2.16 107.595 34.56 107.865 ;
     RECT  2.16 108.135 34.56 108.405 ;
     RECT  2.16 108.675 34.56 108.945 ;
     RECT  2.16 109.215 34.56 109.485 ;
     RECT  2.16 109.755 34.56 110.025 ;
     RECT  2.16 110.295 34.56 110.565 ;
     RECT  2.16 110.835 34.56 111.105 ;
     RECT  2.16 111.375 34.56 111.645 ;
     RECT  2.16 111.915 34.56 112.185 ;
     RECT  2.16 112.455 34.56 112.725 ;
     RECT  2.16 112.995 34.56 113.265 ;
     RECT  2.16 113.535 34.56 113.805 ;
     RECT  2.16 114.075 34.56 114.345 ;
     RECT  2.16 114.615 34.56 114.885 ;
     RECT  2.16 115.155 34.56 115.425 ;
     RECT  2.16 115.695 34.56 115.965 ;
     RECT  2.16 116.235 34.56 116.505 ;
     RECT  2.16 116.775 34.56 117.045 ;
     RECT  2.16 117.315 34.56 117.585 ;
     RECT  2.16 117.855 34.56 118.125 ;
     RECT  2.16 118.395 34.56 118.665 ;
    LAYER M1 ;
     RECT  2.16 2.151 34.56 118.809 ;
    LAYER M2 ;
     RECT  0.211 8.442 2.16 8.46 ;
     RECT  0.535 27.18 2.16 27.198 ;
     RECT  0.211 37.602 2.16 37.62 ;
     RECT  0.247 116.172 2.16 116.19 ;
     RECT  18.175 120.798 18.383 120.816 ;
     RECT  2.16 2.151 34.56 118.809 ;
     RECT  34.56 2.808 34.763 3.978 ;
     RECT  34.56 6.624 34.763 31.824 ;
     RECT  34.56 32.58 34.763 36.918 ;
     RECT  34.56 37.674 34.763 74.448 ;
     RECT  34.56 75.276 34.763 75.762 ;
     RECT  34.56 76.518 34.763 91.494 ;
     RECT  34.56 102.096 34.763 108.864 ;
     RECT  34.56 109.836 34.763 116.064 ;
     RECT  34.763 9.756 34.799 31.752 ;
     RECT  34.763 37.674 34.799 63.414 ;
     RECT  34.763 64.206 34.799 74.448 ;
     RECT  34.763 75.276 34.799 75.564 ;
     RECT  34.763 76.554 34.799 91.224 ;
     RECT  34.56 92.448 34.799 101.214 ;
     RECT  34.763 102.096 34.799 104.814 ;
     RECT  34.763 111.456 34.799 116.064 ;
     RECT  34.763 6.624 34.835 8.964 ;
     RECT  34.56 117.216 34.835 118.584 ;
     RECT  34.799 111.924 34.871 116.064 ;
     RECT  34.835 117.216 34.871 117.774 ;
     RECT  34.871 116.046 34.907 116.064 ;
     RECT  34.799 64.206 35.015 67.194 ;
     RECT  34.871 117.216 35.087 117.504 ;
     RECT  34.799 49.05 35.339 63.414 ;
     RECT  34.56 4.806 35.375 5.364 ;
     RECT  34.835 6.624 35.375 8.19 ;
     RECT  34.799 9.756 35.375 9.954 ;
     RECT  34.799 10.908 35.375 19.944 ;
     RECT  34.799 20.7 35.375 21.528 ;
     RECT  34.799 24.444 35.375 29.592 ;
     RECT  34.799 30.348 35.375 31.752 ;
     RECT  34.763 32.58 35.375 36.846 ;
     RECT  34.799 37.674 35.375 48.294 ;
     RECT  35.015 64.206 35.375 67.122 ;
     RECT  34.799 67.986 35.375 74.448 ;
     RECT  34.799 76.554 35.375 85.752 ;
     RECT  34.799 94.41 35.375 101.214 ;
     RECT  34.799 102.168 35.375 104.814 ;
     RECT  34.871 111.924 35.375 115.146 ;
     RECT  35.087 117.216 35.375 117.234 ;
     RECT  35.375 13.374 35.411 19.944 ;
     RECT  35.375 30.348 35.411 31.518 ;
     RECT  35.375 37.674 35.411 46.566 ;
     RECT  35.375 78.75 35.411 85.752 ;
     RECT  34.799 86.616 35.411 91.224 ;
     RECT  35.375 102.168 35.411 103.644 ;
     RECT  34.763 105.714 35.411 108.864 ;
     RECT  35.375 111.924 35.411 114.138 ;
     RECT  34.763 2.808 35.447 3.942 ;
     RECT  35.375 5.076 35.447 5.094 ;
     RECT  35.411 45 35.447 46.296 ;
     RECT  34.835 118.566 35.879 118.584 ;
     RECT  35.375 26.604 35.915 27.234 ;
     RECT  35.375 28.458 35.915 28.854 ;
     RECT  35.411 30.816 35.915 31.518 ;
     RECT  35.375 47.43 35.915 48.294 ;
     RECT  35.411 78.75 35.915 83.052 ;
     RECT  34.799 92.448 35.915 93.654 ;
     RECT  35.375 101.16 35.915 101.214 ;
     RECT  35.375 6.624 35.951 6.642 ;
     RECT  34.835 8.946 35.951 8.964 ;
     RECT  35.375 9.936 35.951 9.954 ;
     RECT  35.375 10.908 35.951 12.618 ;
     RECT  35.411 13.374 35.951 13.392 ;
     RECT  35.411 14.256 35.951 16.902 ;
     RECT  35.411 17.658 35.951 18.054 ;
     RECT  35.411 18.846 35.951 19.944 ;
     RECT  35.375 20.934 35.951 21.492 ;
     RECT  34.799 22.59 35.951 23.454 ;
     RECT  35.375 24.444 35.951 25.812 ;
     RECT  35.915 26.64 35.951 27.234 ;
     RECT  35.915 28.458 35.951 28.818 ;
     RECT  35.915 30.888 35.951 31.518 ;
     RECT  35.375 32.58 35.951 32.904 ;
     RECT  35.375 33.696 35.951 36.846 ;
     RECT  35.411 37.674 35.951 44.172 ;
     RECT  35.447 45 35.951 45.864 ;
     RECT  35.915 47.466 35.951 48.294 ;
     RECT  35.339 49.05 35.951 53.964 ;
     RECT  35.339 54.72 35.951 63.414 ;
     RECT  35.375 64.206 35.951 64.224 ;
     RECT  35.375 65.016 35.951 66.924 ;
     RECT  35.375 67.986 35.951 68.778 ;
     RECT  35.375 69.57 35.951 74.448 ;
     RECT  34.799 75.276 35.951 75.492 ;
     RECT  35.915 78.786 35.951 83.052 ;
     RECT  35.411 84.114 35.951 85.752 ;
     RECT  35.411 86.616 35.951 89.568 ;
     RECT  35.411 90.324 35.951 91.224 ;
     RECT  35.915 92.484 35.951 93.654 ;
     RECT  35.375 94.41 35.951 94.734 ;
     RECT  35.375 95.994 35.951 100.062 ;
     RECT  35.915 101.16 35.951 101.178 ;
     RECT  35.411 102.168 35.951 102.834 ;
     RECT  35.411 103.626 35.951 103.644 ;
     RECT  35.375 104.634 35.951 104.652 ;
     RECT  35.411 105.786 35.951 108.504 ;
     RECT  34.763 109.836 35.951 110.664 ;
     RECT  35.411 111.924 35.951 111.942 ;
     RECT  35.411 112.806 35.951 114.138 ;
     RECT  35.375 7.596 35.987 8.19 ;
     RECT  35.951 10.908 35.987 10.926 ;
     RECT  35.951 11.826 35.987 11.844 ;
     RECT  35.951 15.57 35.987 16.902 ;
     RECT  35.951 19.116 35.987 19.566 ;
     RECT  35.951 21.168 35.987 21.258 ;
     RECT  35.951 22.896 35.987 23.454 ;
     RECT  35.951 24.714 35.987 25.776 ;
     RECT  35.951 26.766 35.987 26.964 ;
     RECT  35.951 28.458 35.987 28.584 ;
     RECT  35.951 30.888 35.987 31.014 ;
     RECT  35.951 32.616 35.987 32.904 ;
     RECT  35.951 34.776 35.987 35.532 ;
     RECT  35.951 36.666 35.987 36.846 ;
     RECT  35.951 37.674 35.987 37.692 ;
     RECT  35.951 39.024 35.987 40.698 ;
     RECT  35.951 41.796 35.987 43.092 ;
     RECT  35.951 45.846 35.987 45.864 ;
     RECT  35.951 48.204 35.987 48.222 ;
     RECT  35.951 52.02 35.987 52.074 ;
     RECT  35.951 53.136 35.987 53.586 ;
     RECT  35.951 54.918 35.987 55.242 ;
     RECT  35.951 56.106 35.987 56.394 ;
     RECT  35.951 57.456 35.987 57.474 ;
     RECT  35.951 59.346 35.987 59.364 ;
     RECT  35.951 60.12 35.987 61.182 ;
     RECT  35.951 62.046 35.987 63.108 ;
     RECT  35.951 65.016 35.987 65.574 ;
     RECT  35.951 66.834 35.987 66.924 ;
     RECT  35.951 68.184 35.987 68.202 ;
     RECT  35.951 69.606 35.987 69.894 ;
     RECT  35.951 70.884 35.987 71.442 ;
     RECT  35.951 72.306 35.987 73.332 ;
     RECT  35.951 74.088 35.987 74.448 ;
     RECT  35.951 75.276 35.987 75.294 ;
     RECT  35.375 76.554 35.987 76.842 ;
     RECT  35.951 78.786 35.987 80.154 ;
     RECT  35.951 81.108 35.987 81.126 ;
     RECT  35.951 81.954 35.987 81.972 ;
     RECT  35.951 82.728 35.987 82.746 ;
     RECT  35.951 84.186 35.987 85.752 ;
     RECT  35.951 86.778 35.987 88.452 ;
     RECT  35.951 89.316 35.987 89.334 ;
     RECT  35.951 91.206 35.987 91.224 ;
     RECT  35.951 92.52 35.987 92.808 ;
     RECT  35.951 93.564 35.987 93.654 ;
     RECT  35.951 94.716 35.987 94.734 ;
     RECT  35.951 95.994 35.987 96.624 ;
     RECT  35.951 97.416 35.987 98.172 ;
     RECT  35.951 99.036 35.987 99.054 ;
     RECT  35.951 99.846 35.987 99.864 ;
     RECT  35.951 102.546 35.987 102.564 ;
     RECT  35.951 106.218 35.987 106.812 ;
     RECT  35.951 108.108 35.987 108.126 ;
     RECT  35.951 110.07 35.987 110.628 ;
     RECT  35.951 113.616 35.987 113.634 ;
     RECT  35.987 8.172 36.023 8.19 ;
     RECT  35.951 14.49 36.023 14.814 ;
     RECT  35.951 17.694 36.023 17.712 ;
     RECT  35.987 21.24 36.023 21.258 ;
     RECT  35.987 23.094 36.023 23.112 ;
     RECT  35.987 24.714 36.023 24.732 ;
     RECT  35.987 25.758 36.023 25.776 ;
     RECT  35.987 26.946 36.023 26.964 ;
     RECT  35.987 28.458 36.023 28.476 ;
     RECT  35.987 32.616 36.023 32.634 ;
     RECT  35.987 35.244 36.023 35.262 ;
     RECT  35.987 36.756 36.023 36.774 ;
     RECT  35.987 39.024 36.023 39.042 ;
     RECT  35.987 40.68 36.023 40.698 ;
     RECT  35.951 49.05 36.023 49.068 ;
     RECT  35.951 49.824 36.023 50.958 ;
     RECT  35.987 56.376 36.023 56.394 ;
     RECT  35.987 61.164 36.023 61.182 ;
     RECT  35.987 69.606 36.023 69.624 ;
     RECT  35.987 72.306 36.023 72.324 ;
     RECT  35.987 74.394 36.023 74.448 ;
     RECT  35.987 76.554 36.023 76.572 ;
     RECT  35.987 79.488 36.023 80.154 ;
     RECT  35.987 84.456 36.023 84.474 ;
     RECT  35.987 85.734 36.023 85.752 ;
     RECT  35.987 86.778 36.023 87.984 ;
     RECT  35.987 92.52 36.023 92.538 ;
     RECT  35.987 93.636 36.023 93.654 ;
     RECT  35.987 95.994 36.023 96.012 ;
     RECT  36.023 14.49 36.059 14.508 ;
     RECT  36.023 50.328 36.059 50.346 ;
     RECT  35.987 52.056 36.059 52.074 ;
     RECT  35.987 62.28 36.059 62.568 ;
     RECT  35.987 66.834 36.059 66.852 ;
     RECT  36.023 79.488 36.059 79.506 ;
     RECT  36.023 87.426 36.059 87.444 ;
     RECT  36.059 62.28 36.095 62.298 ;
     RECT  36.023 74.43 36.095 74.448 ;
     RECT  35.447 2.808 36.527 3.366 ;
     RECT  35.987 30.888 36.527 30.906 ;
     RECT  36.527 3.348 36.563 3.366 ;
    LAYER M3 ;
     RECT  2.415 2.143 2.505 2.413 ;
     RECT  5.115 2.143 5.205 2.413 ;
     RECT  7.815 2.143 7.905 2.413 ;
     RECT  10.515 2.143 10.605 2.413 ;
     RECT  13.215 2.143 13.305 2.413 ;
     RECT  15.915 2.143 16.005 2.413 ;
     RECT  18.615 2.143 18.705 2.413 ;
     RECT  21.315 2.143 21.405 2.413 ;
     RECT  24.015 2.143 24.105 2.413 ;
     RECT  26.715 2.143 26.805 2.413 ;
     RECT  29.415 2.143 29.505 2.413 ;
     RECT  32.115 2.143 32.205 2.413 ;
     RECT  33.48 2.731 33.498 2.767 ;
     RECT  34.344 2.767 34.47 2.839 ;
     RECT  34.272 2.839 34.47 3.307 ;
     RECT  36.504 2.803 36.522 3.343 ;
     RECT  33.3 2.767 33.498 3.379 ;
     RECT  34.272 3.307 34.506 3.379 ;
     RECT  35.388 3.181 35.406 3.379 ;
     RECT  33.3 3.379 35.406 3.919 ;
     RECT  2.415 2.413 2.697 4.225 ;
     RECT  32.115 2.413 32.397 4.225 ;
     RECT  33.3 3.919 35.442 4.225 ;
     RECT  2.415 4.225 2.79 4.445 ;
     RECT  3.888 4.261 3.906 4.531 ;
     RECT  5.115 2.413 5.397 4.531 ;
     RECT  2.415 4.445 2.697 4.555 ;
     RECT  7.815 2.413 8.097 4.657 ;
     RECT  3.888 4.531 5.397 4.801 ;
     RECT  3.888 4.801 5.634 5.035 ;
     RECT  3.816 5.035 5.634 5.161 ;
     RECT  32.115 4.225 35.442 5.261 ;
     RECT  3.816 5.161 5.958 5.341 ;
     RECT  6.912 5.161 6.93 5.341 ;
     RECT  7.815 4.657 8.262 5.341 ;
     RECT  32.115 5.261 35.406 5.405 ;
     RECT  9.108 5.161 9.126 5.431 ;
     RECT  3.816 5.341 8.262 5.459 ;
     RECT  32.115 5.405 34.506 5.459 ;
     RECT  10.515 2.413 10.797 5.467 ;
     RECT  30.852 5.431 30.87 5.467 ;
     RECT  10.515 5.467 10.818 5.603 ;
     RECT  9.036 5.431 9.126 5.639 ;
     RECT  30.78 5.467 30.87 5.639 ;
     RECT  33.3 5.459 34.506 5.729 ;
     RECT  32.115 5.459 32.49 5.845 ;
     RECT  2.304 4.555 2.697 5.881 ;
     RECT  3.816 5.459 6.822 5.881 ;
     RECT  7.815 5.459 8.262 5.881 ;
     RECT  35.352 5.405 35.406 5.885 ;
     RECT  30.78 5.639 30.798 5.909 ;
     RECT  9.216 5.809 9.234 5.999 ;
     RECT  2.304 5.881 6.822 6.071 ;
     RECT  7.815 5.881 8.406 6.071 ;
     RECT  3.924 6.071 6.822 6.107 ;
     RECT  31.824 5.845 32.49 6.151 ;
     RECT  6.804 6.107 6.822 6.235 ;
     RECT  7.815 6.071 8.097 6.235 ;
     RECT  2.304 6.071 2.934 6.269 ;
     RECT  3.924 6.107 6.03 6.269 ;
     RECT  6.804 6.235 8.097 6.269 ;
     RECT  31.788 6.151 32.49 6.305 ;
     RECT  32.04 6.305 32.49 6.511 ;
     RECT  33.3 5.729 34.47 6.511 ;
     RECT  2.304 6.269 2.79 6.523 ;
     RECT  35.388 5.885 35.406 6.619 ;
     RECT  36.504 3.343 36.558 6.619 ;
     RECT  35.388 6.619 36.558 6.655 ;
     RECT  2.268 6.523 2.79 6.683 ;
     RECT  32.04 6.511 34.47 6.691 ;
     RECT  35.352 6.655 36.558 6.691 ;
     RECT  3.924 6.269 5.67 6.917 ;
     RECT  32.04 6.691 36.558 7.079 ;
     RECT  34.776 7.079 36.558 7.133 ;
     RECT  4.392 6.917 5.67 7.159 ;
     RECT  7.272 6.269 8.097 7.195 ;
     RECT  34.776 7.133 36.486 7.229 ;
     RECT  4.392 7.159 5.886 7.231 ;
     RECT  6.624 7.195 8.097 7.231 ;
     RECT  8.82 7.231 8.838 7.349 ;
     RECT  2.304 6.683 2.79 7.357 ;
     RECT  30.78 6.691 30.798 7.385 ;
     RECT  32.04 7.079 34.002 7.501 ;
     RECT  34.776 7.229 35.982 7.517 ;
     RECT  31.896 7.501 34.002 7.591 ;
     RECT  2.304 7.357 3.546 7.699 ;
     RECT  4.392 7.231 8.097 7.699 ;
     RECT  9.036 7.627 9.054 7.699 ;
     RECT  9.036 7.699 9.126 7.799 ;
     RECT  31.716 7.591 34.002 7.889 ;
     RECT  34.776 7.517 34.794 8.041 ;
     RECT  35.928 7.517 35.982 8.167 ;
     RECT  31.212 8.131 31.23 8.203 ;
     RECT  32.04 7.889 34.002 8.203 ;
     RECT  34.74 8.041 34.794 8.203 ;
     RECT  32.04 8.203 34.794 8.299 ;
     RECT  30.852 8.203 31.23 8.401 ;
     RECT  30.708 8.401 31.23 8.465 ;
     RECT  32.04 8.299 34.83 8.501 ;
     RECT  10.515 5.603 10.797 8.545 ;
     RECT  9.036 7.799 9.054 8.581 ;
     RECT  0.216 8.437 0.234 8.669 ;
     RECT  35.928 8.167 36.018 8.669 ;
     RECT  9.036 8.581 9.162 8.699 ;
     RECT  10.515 8.545 10.926 8.743 ;
     RECT  10.515 8.743 10.998 8.843 ;
     RECT  30.708 8.465 30.726 8.879 ;
     RECT  2.304 7.699 8.097 8.969 ;
     RECT  2.304 8.969 6.822 9.239 ;
     RECT  32.04 8.501 34.794 9.239 ;
     RECT  2.304 9.239 6.642 9.275 ;
     RECT  30.78 9.247 30.798 9.347 ;
     RECT  32.115 9.239 34.794 9.347 ;
     RECT  35.928 8.669 35.946 9.595 ;
     RECT  7.56 8.969 8.097 9.779 ;
     RECT  35.352 9.595 35.946 9.779 ;
     RECT  30.852 9.823 30.87 9.959 ;
     RECT  0.252 9.931 0.27 10.109 ;
     RECT  32.115 9.347 34.29 10.123 ;
     RECT  2.304 9.275 5.526 10.267 ;
     RECT  6.336 9.275 6.642 10.267 ;
     RECT  2.304 10.267 6.642 10.399 ;
     RECT  35.928 9.779 35.946 10.747 ;
     RECT  30.78 10.291 30.798 10.769 ;
     RECT  7.632 9.779 8.097 11.011 ;
     RECT  32.115 10.123 34.794 11.039 ;
     RECT  35.928 10.747 35.982 11.083 ;
     RECT  7.632 11.011 8.262 11.129 ;
     RECT  32.115 11.039 34.254 11.173 ;
     RECT  10.515 8.843 10.797 11.245 ;
     RECT  31.968 11.173 34.254 11.245 ;
     RECT  2.304 10.399 6.714 11.371 ;
     RECT  7.632 11.129 8.097 11.371 ;
     RECT  10.515 11.245 10.818 11.399 ;
     RECT  2.304 11.371 8.097 11.579 ;
     RECT  31.932 11.245 34.254 11.641 ;
     RECT  31.68 11.641 34.254 11.669 ;
     RECT  9.144 11.785 9.162 11.821 ;
     RECT  35.352 11.083 35.982 11.849 ;
     RECT  0.252 11.707 0.27 11.933 ;
     RECT  9.036 11.821 9.486 11.939 ;
     RECT  31.68 11.669 34.218 11.939 ;
     RECT  9.468 11.939 9.486 12.209 ;
     RECT  2.304 11.579 7.074 12.245 ;
     RECT  10.515 11.399 10.797 12.361 ;
     RECT  30.78 12.289 30.798 12.361 ;
     RECT  30.78 12.361 30.87 12.389 ;
     RECT  10.515 12.361 10.818 12.479 ;
     RECT  0.216 12.379 0.234 12.509 ;
     RECT  30.852 12.389 30.87 12.515 ;
     RECT  31.932 11.939 34.218 12.631 ;
     RECT  31.932 12.631 34.254 12.749 ;
     RECT  3.924 12.245 7.074 12.757 ;
     RECT  7.815 11.579 8.097 12.757 ;
     RECT  2.304 12.245 3.114 12.785 ;
     RECT  3.924 12.757 8.097 12.793 ;
     RECT  3.924 12.793 8.586 12.829 ;
     RECT  3.924 12.829 8.658 12.929 ;
     RECT  3.924 12.929 8.586 13.171 ;
     RECT  0.252 13.195 0.27 13.325 ;
     RECT  2.304 12.785 2.898 13.711 ;
     RECT  3.708 13.171 8.586 13.711 ;
     RECT  32.04 12.749 34.254 13.711 ;
     RECT  32.004 13.711 34.254 13.837 ;
     RECT  31.932 13.837 34.254 13.867 ;
     RECT  35.352 11.849 35.946 13.867 ;
     RECT  30.78 13.333 30.798 13.873 ;
     RECT  2.304 13.711 8.586 14.009 ;
     RECT  31.932 13.867 35.946 14.009 ;
     RECT  2.304 14.009 6.39 14.011 ;
     RECT  35.928 14.009 35.946 14.011 ;
     RECT  7.236 14.009 8.586 14.099 ;
     RECT  35.928 14.011 35.982 14.155 ;
     RECT  2.268 14.011 6.39 14.171 ;
     RECT  30.78 13.873 30.87 14.207 ;
     RECT  30.78 14.207 30.798 14.243 ;
     RECT  7.236 14.099 8.097 14.369 ;
     RECT  31.932 14.009 34.794 14.381 ;
     RECT  2.268 14.171 3.402 14.477 ;
     RECT  35.928 14.155 36.018 14.485 ;
     RECT  35.928 14.485 36.054 14.717 ;
     RECT  35.928 14.717 36.018 14.819 ;
     RECT  31.932 14.381 34.398 14.917 ;
     RECT  2.304 14.477 3.402 15.151 ;
     RECT  4.176 14.171 6.39 15.151 ;
     RECT  31.788 14.917 34.398 15.179 ;
     RECT  2.304 15.151 6.966 15.307 ;
     RECT  7.815 14.369 8.097 15.307 ;
     RECT  31.788 15.179 34.218 15.359 ;
     RECT  31.788 15.359 34.146 15.421 ;
     RECT  31.572 15.421 34.146 15.449 ;
     RECT  31.572 15.449 34.074 15.493 ;
     RECT  9.432 15.061 9.45 15.565 ;
     RECT  2.304 15.307 8.097 15.593 ;
     RECT  7.74 15.593 8.097 15.601 ;
     RECT  10.515 12.479 10.797 15.601 ;
     RECT  35.928 14.819 35.982 15.601 ;
     RECT  7.74 15.601 8.37 15.629 ;
     RECT  10.515 15.601 10.854 15.719 ;
     RECT  2.304 15.593 7.002 15.728 ;
     RECT  9.432 15.565 9.594 15.763 ;
     RECT  9.432 15.763 9.666 15.869 ;
     RECT  9.432 15.869 9.522 15.899 ;
     RECT  35.892 15.601 35.982 15.979 ;
     RECT  7.815 15.629 8.37 15.989 ;
     RECT  31.464 15.493 34.074 16.033 ;
     RECT  2.304 15.728 6.93 16.123 ;
     RECT  30.852 16.033 34.074 16.303 ;
     RECT  2.268 16.123 6.93 16.367 ;
     RECT  30.78 16.303 34.326 16.375 ;
     RECT  35.352 15.979 35.982 16.375 ;
     RECT  2.304 16.367 6.93 16.645 ;
     RECT  7.815 15.989 8.154 16.645 ;
     RECT  30.78 16.375 35.982 16.979 ;
     RECT  30.78 16.979 34.326 17.069 ;
     RECT  2.304 16.645 8.154 17.105 ;
     RECT  1.152 17.083 1.17 17.213 ;
     RECT  2.304 17.105 2.862 17.275 ;
     RECT  3.744 17.105 5.994 17.375 ;
     RECT  35.352 16.979 35.982 17.419 ;
     RECT  2.268 17.275 2.862 17.483 ;
     RECT  6.732 17.105 8.154 17.491 ;
     RECT  9.648 17.041 9.666 17.609 ;
     RECT  21.315 2.413 21.597 17.653 ;
     RECT  6.732 17.491 8.478 17.681 ;
     RECT  35.352 17.419 36.018 17.717 ;
     RECT  30.78 17.069 34.218 17.899 ;
     RECT  35.352 17.717 35.946 17.899 ;
     RECT  4.068 17.375 5.994 17.989 ;
     RECT  6.732 17.681 8.262 17.989 ;
     RECT  30.78 17.899 35.946 18.023 ;
     RECT  21.096 17.653 21.597 18.059 ;
     RECT  4.068 17.989 8.262 18.149 ;
     RECT  9.18 17.995 9.198 18.149 ;
     RECT  31.248 18.023 35.946 18.149 ;
     RECT  2.304 17.483 2.862 18.187 ;
     RECT  4.068 18.149 6.966 18.187 ;
     RECT  0.252 18.091 0.27 18.221 ;
     RECT  7.815 18.149 8.262 18.661 ;
     RECT  31.5 18.149 35.946 18.689 ;
     RECT  7.815 18.661 8.406 18.841 ;
     RECT  2.304 18.187 6.966 18.907 ;
     RECT  2.268 18.907 6.966 18.959 ;
     RECT  7.815 18.841 8.514 18.959 ;
     RECT  10.515 15.719 10.797 18.967 ;
     RECT  31.5 18.689 34.758 19.003 ;
     RECT  2.268 18.959 2.697 19.067 ;
     RECT  10.515 18.967 10.854 19.067 ;
     RECT  30.852 19.003 34.758 19.103 ;
     RECT  35.856 18.689 35.946 19.111 ;
     RECT  9.036 19.003 9.054 19.139 ;
     RECT  31.068 19.103 34.758 19.265 ;
     RECT  3.456 18.959 6.966 19.373 ;
     RECT  35.856 19.111 35.982 19.499 ;
     RECT  31.176 19.265 34.758 19.531 ;
     RECT  35.928 19.499 35.982 19.571 ;
     RECT  31.176 19.531 34.794 19.769 ;
     RECT  2.304 19.067 2.697 19.867 ;
     RECT  3.456 19.373 5.706 19.867 ;
     RECT  6.552 19.373 6.966 20.039 ;
     RECT  34.2 19.769 34.794 20.039 ;
     RECT  6.66 20.039 6.966 20.047 ;
     RECT  7.815 18.959 8.097 20.047 ;
     RECT  10.515 19.067 10.797 20.047 ;
     RECT  6.66 20.047 8.097 20.111 ;
     RECT  2.304 19.867 5.706 20.191 ;
     RECT  35.928 19.571 35.946 20.347 ;
     RECT  35.928 20.347 35.982 20.539 ;
     RECT  2.304 20.191 5.742 20.551 ;
     RECT  10.515 20.047 10.854 20.551 ;
     RECT  31.176 19.769 33.462 20.587 ;
     RECT  2.304 20.551 5.814 20.615 ;
     RECT  10.515 20.551 10.926 20.651 ;
     RECT  35.928 20.539 36.018 20.683 ;
     RECT  35.352 20.683 36.018 20.723 ;
     RECT  7.128 20.111 8.097 20.731 ;
     RECT  9.036 20.011 9.054 20.731 ;
     RECT  30.852 20.587 33.462 20.731 ;
     RECT  34.2 20.039 34.218 20.731 ;
     RECT  30.852 20.731 34.218 20.827 ;
     RECT  7.128 20.731 9.054 20.921 ;
     RECT  3.636 20.615 5.814 21.001 ;
     RECT  30.852 20.827 34.794 21.155 ;
     RECT  7.128 20.921 8.874 21.163 ;
     RECT  35.928 20.723 36.018 21.263 ;
     RECT  6.912 21.163 8.874 21.271 ;
     RECT  6.768 21.271 8.874 21.389 ;
     RECT  10.515 20.651 10.797 21.397 ;
     RECT  30.852 21.155 31.158 21.397 ;
     RECT  10.515 21.397 10.854 21.497 ;
     RECT  2.304 20.615 2.697 21.499 ;
     RECT  3.636 21.001 6.03 21.499 ;
     RECT  32.115 21.155 34.794 21.499 ;
     RECT  35.928 21.263 35.946 21.499 ;
     RECT  32.115 21.499 35.946 21.539 ;
     RECT  2.304 21.499 6.03 21.811 ;
     RECT  6.768 21.389 8.097 21.811 ;
     RECT  30.78 21.397 31.158 21.929 ;
     RECT  32.115 21.539 34.794 22.199 ;
     RECT  2.304 21.811 8.097 22.279 ;
     RECT  2.304 22.279 8.478 22.379 ;
     RECT  35.928 21.539 35.946 22.459 ;
     RECT  2.304 22.379 8.406 22.469 ;
     RECT  32.115 22.199 34.398 22.739 ;
     RECT  35.316 22.459 35.946 22.795 ;
     RECT  2.304 22.469 8.298 23.009 ;
     RECT  35.316 22.795 35.982 23.009 ;
     RECT  35.928 23.009 35.982 23.089 ;
     RECT  32.115 22.739 34.254 23.125 ;
     RECT  3.528 23.009 6.03 23.279 ;
     RECT  35.928 23.089 36.018 23.309 ;
     RECT  30.78 21.929 30.798 23.431 ;
     RECT  31.932 23.125 34.254 23.431 ;
     RECT  30.78 23.431 34.254 23.467 ;
     RECT  30.78 23.467 34.794 23.549 ;
     RECT  3.816 23.279 6.03 23.855 ;
     RECT  31.932 23.549 34.794 23.947 ;
     RECT  35.928 23.309 35.982 23.947 ;
     RECT  6.804 23.009 8.097 24.089 ;
     RECT  2.304 23.009 2.79 24.169 ;
     RECT  3.888 23.855 6.03 24.197 ;
     RECT  30.78 23.549 30.798 24.197 ;
     RECT  2.304 24.169 2.934 24.205 ;
     RECT  3.996 24.197 6.03 24.233 ;
     RECT  4.032 24.233 6.03 24.241 ;
     RECT  31.932 23.947 35.982 24.395 ;
     RECT  31.968 24.395 35.982 24.427 ;
     RECT  4.032 24.241 6.498 24.503 ;
     RECT  31.968 24.427 36.018 24.539 ;
     RECT  2.304 24.205 3.006 24.601 ;
     RECT  7.416 24.089 8.097 24.709 ;
     RECT  35.352 24.539 36.018 24.737 ;
     RECT  4.068 24.503 6.498 24.871 ;
     RECT  30.852 24.907 30.87 24.943 ;
     RECT  7.416 24.709 8.694 24.971 ;
     RECT  35.352 24.737 35.982 24.971 ;
     RECT  31.968 24.539 34.254 25.052 ;
     RECT  4.068 24.871 6.57 25.079 ;
     RECT  2.304 24.601 3.186 25.169 ;
     RECT  32.004 25.052 34.254 25.169 ;
     RECT  7.416 24.971 8.154 25.177 ;
     RECT  7.308 25.177 8.154 25.285 ;
     RECT  2.304 25.169 2.898 25.387 ;
     RECT  32.04 25.169 34.254 25.439 ;
     RECT  35.388 24.971 35.982 25.579 ;
     RECT  4.068 25.079 6.174 25.591 ;
     RECT  3.96 25.591 6.174 25.675 ;
     RECT  35.388 25.579 36.018 25.723 ;
     RECT  3.636 25.675 6.174 25.817 ;
     RECT  7.092 25.285 8.154 25.861 ;
     RECT  30.78 24.943 30.87 25.889 ;
     RECT  2.268 25.387 2.898 26.059 ;
     RECT  3.636 25.817 5.922 26.059 ;
     RECT  30.78 25.889 30.798 26.087 ;
     RECT  6.66 25.861 8.154 26.249 ;
     RECT  9.36 26.131 9.378 26.249 ;
     RECT  2.268 26.059 5.922 26.555 ;
     RECT  32.04 25.439 34.218 26.563 ;
     RECT  2.304 26.555 5.922 26.671 ;
     RECT  6.66 26.249 6.894 26.671 ;
     RECT  32.04 26.563 34.254 26.671 ;
     RECT  35.352 25.723 36.018 26.699 ;
     RECT  35.892 26.699 36.018 26.765 ;
     RECT  32.004 26.671 34.254 26.825 ;
     RECT  35.928 26.765 36.018 26.969 ;
     RECT  32.076 26.825 34.254 27.019 ;
     RECT  30.852 26.941 30.87 27.103 ;
     RECT  30.78 27.103 30.87 27.167 ;
     RECT  2.304 26.671 6.894 27.205 ;
     RECT  7.815 26.249 8.154 27.205 ;
     RECT  2.304 27.205 8.154 27.211 ;
     RECT  2.304 27.211 8.298 27.245 ;
     RECT  35.928 26.969 35.946 27.245 ;
     RECT  2.304 27.245 7.002 27.329 ;
     RECT  7.815 27.245 8.298 27.329 ;
     RECT  7.815 27.329 8.154 27.365 ;
     RECT  0.54 27.175 0.558 27.389 ;
     RECT  6.804 27.329 7.002 27.437 ;
     RECT  32.076 27.019 34.83 27.547 ;
     RECT  2.304 27.329 6.03 27.635 ;
     RECT  3.42 27.635 6.03 27.671 ;
     RECT  30.78 27.167 30.798 27.707 ;
     RECT  32.076 27.547 35.37 27.715 ;
     RECT  31.788 27.715 35.37 27.869 ;
     RECT  31.824 27.869 35.37 27.875 ;
     RECT  3.456 27.671 6.03 27.905 ;
     RECT  6.984 27.437 7.002 27.985 ;
     RECT  7.815 27.365 8.097 27.985 ;
     RECT  2.304 27.635 2.697 28.027 ;
     RECT  6.984 27.985 8.097 28.123 ;
     RECT  6.984 28.123 8.37 28.255 ;
     RECT  3.888 27.905 6.03 28.291 ;
     RECT  6.804 28.255 8.37 28.291 ;
     RECT  9.396 28.183 9.414 28.291 ;
     RECT  35.928 28.027 35.946 28.315 ;
     RECT  9.396 28.291 9.558 28.409 ;
     RECT  2.268 28.027 2.697 28.411 ;
     RECT  0.216 28.315 0.234 28.445 ;
     RECT  35.928 28.315 35.982 28.453 ;
     RECT  35.928 28.453 36.018 28.541 ;
     RECT  9.396 28.409 9.486 28.589 ;
     RECT  35.928 28.541 35.982 28.589 ;
     RECT  31.824 27.875 34.794 28.651 ;
     RECT  35.928 28.589 35.946 28.651 ;
     RECT  2.268 28.411 3.078 28.715 ;
     RECT  2.304 28.715 3.078 28.723 ;
     RECT  3.888 28.291 8.37 28.723 ;
     RECT  31.824 28.651 35.946 28.795 ;
     RECT  31.752 28.795 35.946 28.823 ;
     RECT  2.304 28.723 8.37 28.831 ;
     RECT  31.752 28.823 35.91 28.877 ;
     RECT  2.304 28.831 8.766 29.371 ;
     RECT  30.852 29.227 30.87 29.839 ;
     RECT  31.752 28.877 35.37 29.839 ;
     RECT  2.304 29.371 8.838 29.875 ;
     RECT  30.852 29.839 35.37 29.875 ;
     RECT  30.78 29.875 35.37 29.981 ;
     RECT  2.304 29.875 8.982 30.029 ;
     RECT  35.352 29.981 35.37 30.139 ;
     RECT  30.78 29.981 34.254 30.209 ;
     RECT  35.352 30.139 35.406 30.283 ;
     RECT  30.78 30.209 31.302 30.299 ;
     RECT  35.352 30.283 35.91 30.475 ;
     RECT  30.78 30.299 30.978 30.641 ;
     RECT  2.304 30.029 8.658 30.677 ;
     RECT  30.816 30.641 30.978 30.713 ;
     RECT  2.304 30.677 6.138 30.749 ;
     RECT  30.816 30.713 30.906 30.749 ;
     RECT  35.352 30.475 35.946 30.763 ;
     RECT  35.352 30.763 36.522 30.911 ;
     RECT  32.115 30.209 34.254 30.991 ;
     RECT  35.352 30.911 35.982 31.019 ;
     RECT  31.896 30.991 34.254 31.099 ;
     RECT  35.352 31.019 35.946 31.099 ;
     RECT  31.896 31.099 35.946 31.109 ;
     RECT  7.128 30.677 8.658 31.379 ;
     RECT  7.128 31.379 8.097 31.531 ;
     RECT  7.092 31.531 8.097 31.621 ;
     RECT  30.852 30.749 30.87 31.657 ;
     RECT  32.004 31.109 35.946 31.757 ;
     RECT  2.304 30.749 5.814 31.771 ;
     RECT  32.004 31.757 34.758 31.829 ;
     RECT  32.004 31.829 34.254 31.891 ;
     RECT  2.304 31.771 5.958 31.919 ;
     RECT  8.928 31.531 8.946 31.919 ;
     RECT  2.304 31.919 5.886 31.955 ;
     RECT  35.928 31.757 35.946 32.059 ;
     RECT  6.84 31.621 8.097 32.071 ;
     RECT  10.515 21.497 10.797 32.071 ;
     RECT  6.768 32.071 8.097 32.161 ;
     RECT  2.304 31.955 2.862 32.189 ;
     RECT  9.54 32.071 9.558 32.189 ;
     RECT  30.78 31.657 30.87 32.341 ;
     RECT  31.932 31.891 34.254 32.341 ;
     RECT  10.515 32.071 10.926 32.369 ;
     RECT  30.78 32.341 34.254 32.495 ;
     RECT  35.928 32.059 36.018 32.639 ;
     RECT  31.86 32.495 34.254 32.729 ;
     RECT  35.928 32.639 35.982 32.731 ;
     RECT  30.78 32.495 30.798 32.837 ;
     RECT  3.888 31.955 5.886 32.845 ;
     RECT  6.768 32.161 8.442 32.845 ;
     RECT  2.304 32.189 2.697 32.872 ;
     RECT  3.888 32.845 8.442 32.881 ;
     RECT  35.352 32.731 35.982 32.909 ;
     RECT  3.708 32.881 8.442 33.007 ;
     RECT  3.636 33.007 8.442 33.053 ;
     RECT  2.268 32.872 2.697 33.067 ;
     RECT  31.896 32.729 34.254 33.067 ;
     RECT  35.352 32.909 35.946 33.067 ;
     RECT  2.268 33.067 2.754 33.241 ;
     RECT  3.672 33.053 8.442 33.241 ;
     RECT  31.896 33.067 35.946 33.269 ;
     RECT  10.515 32.369 10.797 33.277 ;
     RECT  9.648 33.151 9.666 33.305 ;
     RECT  3.672 33.241 8.478 33.389 ;
     RECT  10.515 33.277 10.818 33.449 ;
     RECT  3.672 33.389 8.298 33.539 ;
     RECT  31.932 33.269 35.946 33.539 ;
     RECT  2.268 33.241 2.862 33.575 ;
     RECT  2.304 33.575 2.862 33.889 ;
     RECT  3.672 33.539 8.097 33.889 ;
     RECT  2.304 33.889 8.097 34.115 ;
     RECT  4.248 34.115 8.097 34.16 ;
     RECT  9.036 33.961 9.054 34.223 ;
     RECT  2.304 34.115 3.438 34.349 ;
     RECT  31.932 33.539 34.83 34.363 ;
     RECT  35.928 33.539 35.946 34.363 ;
     RECT  31.932 34.363 35.946 34.493 ;
     RECT  7.56 34.16 8.097 34.591 ;
     RECT  4.248 34.16 6.678 34.619 ;
     RECT  32.115 34.493 35.946 34.619 ;
     RECT  0.252 34.507 0.27 34.685 ;
     RECT  7.56 34.591 8.91 34.691 ;
     RECT  35.928 34.619 35.946 34.699 ;
     RECT  30.78 34.663 30.798 34.763 ;
     RECT  35.928 34.699 35.982 35.035 ;
     RECT  4.248 34.619 6.282 35.041 ;
     RECT  2.304 34.349 3.114 35.131 ;
     RECT  3.888 35.041 6.282 35.131 ;
     RECT  7.56 34.691 8.097 35.131 ;
     RECT  8.82 34.691 8.91 35.159 ;
     RECT  0.288 35.035 0.414 35.213 ;
     RECT  35.928 35.035 36.018 35.267 ;
     RECT  32.115 34.619 34.794 35.275 ;
     RECT  0.288 35.213 0.306 35.309 ;
     RECT  32.076 35.275 34.794 35.311 ;
     RECT  31.932 35.311 34.794 35.357 ;
     RECT  8.82 35.159 8.838 35.501 ;
     RECT  30.852 35.473 30.87 35.573 ;
     RECT  7.452 35.131 8.097 35.581 ;
     RECT  2.304 35.131 6.282 35.659 ;
     RECT  31.932 35.357 34.434 35.699 ;
     RECT  2.268 35.659 6.282 35.807 ;
     RECT  2.304 35.807 6.282 35.851 ;
     RECT  2.304 35.851 6.354 35.899 ;
     RECT  7.092 35.581 8.097 35.899 ;
     RECT  35.928 35.267 35.982 35.995 ;
     RECT  2.304 35.899 8.097 36.085 ;
     RECT  35.892 35.995 35.982 36.139 ;
     RECT  0.216 36.139 0.234 36.269 ;
     RECT  2.304 36.085 8.766 36.275 ;
     RECT  7.344 36.275 8.766 36.347 ;
     RECT  35.352 36.139 35.982 36.419 ;
     RECT  7.344 36.347 8.694 36.461 ;
     RECT  35.928 36.419 35.982 36.475 ;
     RECT  31.932 35.699 34.254 36.509 ;
     RECT  7.416 36.461 8.694 36.617 ;
     RECT  9.684 36.625 9.702 36.661 ;
     RECT  10.515 33.449 10.797 36.751 ;
     RECT  9.612 36.661 9.702 36.779 ;
     RECT  35.928 36.475 36.018 36.779 ;
     RECT  32.004 36.509 34.254 36.787 ;
     RECT  32.004 36.787 34.326 36.823 ;
     RECT  10.515 36.751 10.818 36.895 ;
     RECT  32.004 36.823 34.758 36.923 ;
     RECT  9.612 36.779 9.63 36.931 ;
     RECT  0.252 36.859 0.27 36.989 ;
     RECT  10.515 36.895 10.854 37.049 ;
     RECT  2.304 36.275 6.498 37.291 ;
     RECT  30.78 36.247 30.798 37.291 ;
     RECT  2.268 37.291 6.498 37.319 ;
     RECT  9.576 36.931 9.63 37.319 ;
     RECT  7.416 36.617 8.097 37.399 ;
     RECT  2.268 37.319 6.102 37.427 ;
     RECT  7.272 37.399 8.097 37.435 ;
     RECT  32.004 36.923 34.326 37.435 ;
     RECT  30.78 37.291 30.87 37.499 ;
     RECT  7.272 37.435 8.154 37.561 ;
     RECT  6.876 37.561 8.154 37.597 ;
     RECT  31.86 37.435 34.326 37.597 ;
     RECT  35.928 36.779 35.982 37.627 ;
     RECT  0.216 37.597 0.234 37.661 ;
     RECT  6.876 37.597 8.298 37.697 ;
     RECT  31.608 37.597 34.326 37.697 ;
     RECT  9.576 37.319 9.594 37.859 ;
     RECT  31.68 37.697 34.326 37.859 ;
     RECT  30.852 37.499 30.87 38.003 ;
     RECT  35.928 37.627 36.018 38.107 ;
     RECT  6.876 37.697 8.262 38.129 ;
     RECT  2.304 37.427 6.102 38.201 ;
     RECT  5.076 38.201 6.102 38.245 ;
     RECT  31.932 37.859 34.326 38.641 ;
     RECT  9.504 38.101 9.558 38.669 ;
     RECT  7.092 38.129 8.262 38.779 ;
     RECT  31.032 38.713 31.05 38.821 ;
     RECT  31.932 38.641 34.362 38.821 ;
     RECT  35.316 38.107 36.018 38.849 ;
     RECT  31.032 38.821 34.362 38.939 ;
     RECT  2.304 38.201 2.826 39.019 ;
     RECT  3.708 38.201 4.266 39.019 ;
     RECT  5.076 38.245 6.21 39.019 ;
     RECT  35.352 38.849 36.018 39.047 ;
     RECT  2.304 39.019 4.266 39.091 ;
     RECT  5.076 39.019 6.282 39.091 ;
     RECT  7.092 38.779 8.298 39.091 ;
     RECT  30.852 38.983 30.87 39.119 ;
     RECT  9.288 39.091 9.306 39.317 ;
     RECT  2.304 39.091 8.298 39.361 ;
     RECT  2.304 39.361 8.406 39.479 ;
     RECT  30.78 39.487 30.798 39.587 ;
     RECT  31.932 38.939 34.362 39.623 ;
     RECT  2.304 39.479 8.298 39.659 ;
     RECT  31.932 39.623 34.254 39.857 ;
     RECT  7.344 39.659 8.298 39.929 ;
     RECT  2.304 39.659 6.39 40.019 ;
     RECT  35.352 39.047 35.982 40.289 ;
     RECT  35.928 40.289 35.982 40.363 ;
     RECT  30.852 40.063 30.87 40.397 ;
     RECT  32.076 39.857 34.254 40.555 ;
     RECT  21.315 18.059 21.597 40.603 ;
     RECT  29.415 2.413 29.697 40.603 ;
     RECT  2.304 40.019 6.246 40.631 ;
     RECT  32.076 40.555 34.794 40.675 ;
     RECT  35.928 40.363 36.018 40.703 ;
     RECT  14.832 40.603 14.85 40.733 ;
     RECT  21.315 40.603 21.69 40.733 ;
     RECT  22.824 40.603 22.842 40.733 ;
     RECT  29.415 40.603 29.79 40.733 ;
     RECT  7.344 39.929 8.097 40.795 ;
     RECT  9.576 40.711 9.594 40.829 ;
     RECT  7.272 40.795 8.097 40.837 ;
     RECT  6.984 40.837 8.097 40.909 ;
     RECT  31.86 40.675 34.794 40.945 ;
     RECT  6.948 40.909 8.097 40.981 ;
     RECT  31.644 40.945 34.794 41.035 ;
     RECT  35.928 40.703 35.982 41.035 ;
     RECT  31.644 41.035 35.982 41.143 ;
     RECT  2.304 40.631 6.138 41.207 ;
     RECT  30.924 41.143 35.982 41.251 ;
     RECT  30.852 41.251 35.982 41.279 ;
     RECT  2.304 41.207 5.958 41.368 ;
     RECT  31.644 41.279 35.982 41.369 ;
     RECT  6.948 40.981 8.406 41.449 ;
     RECT  10.515 37.049 10.797 41.611 ;
     RECT  31.716 41.369 35.982 41.639 ;
     RECT  2.268 41.368 5.958 41.675 ;
     RECT  6.732 41.449 8.406 41.675 ;
     RECT  30.852 41.279 30.87 41.755 ;
     RECT  30.78 41.755 30.87 41.783 ;
     RECT  7.815 41.675 8.406 41.791 ;
     RECT  0.252 41.851 0.27 41.981 ;
     RECT  7.815 41.791 8.514 42.017 ;
     RECT  30.78 41.783 30.798 42.017 ;
     RECT  2.304 41.675 5.958 42.061 ;
     RECT  6.732 41.675 6.894 42.061 ;
     RECT  10.515 41.611 10.818 42.061 ;
     RECT  7.815 42.017 8.406 42.179 ;
     RECT  10.515 42.061 10.854 42.179 ;
     RECT  32.004 41.639 35.982 42.221 ;
     RECT  7.815 42.179 8.262 42.365 ;
     RECT  10.515 42.179 10.818 42.557 ;
     RECT  32.004 42.221 34.758 42.565 ;
     RECT  9.36 42.331 9.378 42.601 ;
     RECT  31.68 42.565 34.758 42.601 ;
     RECT  30.924 42.601 34.758 42.755 ;
     RECT  2.304 42.061 6.894 42.763 ;
     RECT  7.815 42.365 8.097 42.763 ;
     RECT  30.924 42.755 30.978 42.835 ;
     RECT  9.36 42.601 9.486 42.863 ;
     RECT  31.824 42.755 34.758 42.989 ;
     RECT  32.004 42.989 34.758 43.003 ;
     RECT  30.852 42.835 30.978 43.069 ;
     RECT  35.928 42.221 35.982 43.097 ;
     RECT  9.036 43.141 9.162 43.259 ;
     RECT  30.78 43.069 30.978 43.325 ;
     RECT  30.78 43.325 30.906 43.331 ;
     RECT  32.004 43.003 34.794 43.483 ;
     RECT  35.928 43.097 35.946 43.483 ;
     RECT  2.304 42.763 8.097 43.609 ;
     RECT  9.036 43.259 9.126 43.609 ;
     RECT  32.004 43.483 35.946 43.799 ;
     RECT  2.304 43.609 9.126 43.871 ;
     RECT  32.004 43.799 34.254 44.041 ;
     RECT  35.352 43.799 35.946 44.177 ;
     RECT  9.108 43.871 9.126 44.339 ;
     RECT  7.416 43.871 8.097 44.429 ;
     RECT  2.304 43.871 6.606 44.609 ;
     RECT  31.896 44.041 34.254 44.635 ;
     RECT  35.352 44.177 35.406 44.635 ;
     RECT  30.78 44.077 30.798 44.725 ;
     RECT  31.896 44.635 35.406 44.725 ;
     RECT  2.304 44.609 6.57 44.779 ;
     RECT  30.78 44.725 35.406 44.789 ;
     RECT  31.068 44.789 35.406 44.923 ;
     RECT  31.068 44.923 35.946 45.149 ;
     RECT  35.928 45.149 35.946 45.259 ;
     RECT  8.82 44.995 8.838 45.419 ;
     RECT  2.268 44.779 6.57 45.427 ;
     RECT  2.268 45.427 6.714 45.527 ;
     RECT  7.56 44.429 8.097 45.571 ;
     RECT  7.56 45.571 8.802 45.581 ;
     RECT  7.596 45.581 8.802 45.689 ;
     RECT  35.928 45.259 35.982 45.869 ;
     RECT  31.932 45.149 34.794 45.931 ;
     RECT  2.268 45.527 2.898 45.995 ;
     RECT  7.596 45.689 8.097 46.031 ;
     RECT  30.852 45.733 30.87 46.039 ;
     RECT  30.78 46.039 30.87 46.139 ;
     RECT  3.852 45.527 6.714 46.201 ;
     RECT  31.932 45.931 35.442 46.237 ;
     RECT  3.852 46.201 6.75 46.309 ;
     RECT  2.304 45.995 2.898 46.381 ;
     RECT  3.852 46.309 6.822 46.381 ;
     RECT  31.896 46.237 35.442 46.409 ;
     RECT  31.896 46.409 34.29 46.651 ;
     RECT  31.608 46.651 34.29 46.769 ;
     RECT  9.36 46.381 9.378 46.841 ;
     RECT  2.304 46.381 6.822 46.885 ;
     RECT  7.815 46.031 8.097 46.921 ;
     RECT  30.816 46.139 30.87 46.921 ;
     RECT  2.304 46.885 6.858 46.925 ;
     RECT  35.352 46.409 35.442 47.035 ;
     RECT  7.815 46.921 8.298 47.039 ;
     RECT  31.68 46.769 34.29 47.191 ;
     RECT  35.352 47.035 35.946 47.191 ;
     RECT  7.815 47.039 8.097 47.281 ;
     RECT  31.68 47.191 35.946 47.309 ;
     RECT  35.892 47.309 35.946 47.453 ;
     RECT  7.704 47.281 8.097 47.461 ;
     RECT  31.68 47.309 34.794 47.579 ;
     RECT  2.304 46.925 6.75 47.731 ;
     RECT  7.56 47.461 8.097 47.731 ;
     RECT  30.78 46.921 30.87 47.759 ;
     RECT  10.515 42.557 10.797 47.929 ;
     RECT  2.304 47.731 8.097 48.001 ;
     RECT  35.928 47.453 35.946 48.187 ;
     RECT  2.304 48.001 8.442 48.191 ;
     RECT  31.932 47.579 34.794 48.379 ;
     RECT  31.932 48.379 34.83 48.397 ;
     RECT  8.82 48.271 8.838 48.659 ;
     RECT  10.515 47.929 10.818 48.667 ;
     RECT  35.928 48.187 35.982 48.667 ;
     RECT  10.515 48.667 10.854 48.839 ;
     RECT  0.252 48.859 0.27 48.989 ;
     RECT  30.78 47.759 30.798 49.001 ;
     RECT  2.304 48.191 8.097 49.045 ;
     RECT  31.68 48.397 34.83 49.081 ;
     RECT  31.068 49.081 34.83 49.195 ;
     RECT  31.068 49.195 34.866 49.199 ;
     RECT  2.304 49.045 8.298 49.469 ;
     RECT  2.304 49.469 3.366 49.577 ;
     RECT  9.324 49.315 9.342 49.577 ;
     RECT  2.304 49.577 3.294 49.649 ;
     RECT  35.928 48.667 36.018 49.819 ;
     RECT  4.14 49.469 8.298 49.883 ;
     RECT  30.78 49.783 30.798 49.883 ;
     RECT  32.115 49.199 34.866 50.011 ;
     RECT  35.928 49.819 36.054 50.011 ;
     RECT  32.115 50.011 36.054 50.051 ;
     RECT  6.768 49.883 8.298 50.089 ;
     RECT  4.14 49.883 5.994 50.093 ;
     RECT  32.115 50.051 34.866 50.117 ;
     RECT  32.115 50.117 34.794 50.125 ;
     RECT  35.964 50.051 36.054 50.351 ;
     RECT  31.932 50.125 34.794 50.395 ;
     RECT  2.304 49.649 3.078 50.431 ;
     RECT  4.14 50.093 5.49 50.431 ;
     RECT  31.824 50.395 34.794 50.521 ;
     RECT  2.304 50.431 5.49 50.585 ;
     RECT  0.252 50.491 0.27 50.621 ;
     RECT  30.852 50.323 30.87 50.621 ;
     RECT  31.752 50.521 34.794 50.701 ;
     RECT  6.768 50.089 8.694 50.731 ;
     RECT  6.3 50.731 8.694 50.765 ;
     RECT  2.304 50.585 3.186 50.779 ;
     RECT  31.428 50.701 34.794 50.819 ;
     RECT  3.996 50.585 5.49 50.827 ;
     RECT  6.3 50.765 7.038 50.827 ;
     RECT  2.268 50.779 3.186 50.855 ;
     RECT  31.752 50.819 34.794 50.855 ;
     RECT  35.964 50.351 36.018 50.963 ;
     RECT  7.812 50.765 8.694 50.971 ;
     RECT  2.304 50.855 3.186 51.367 ;
     RECT  3.996 50.827 7.038 51.367 ;
     RECT  7.812 50.971 8.946 51.395 ;
     RECT  8.928 51.395 8.946 51.431 ;
     RECT  30.852 51.367 30.87 51.439 ;
     RECT  2.304 51.367 7.038 51.511 ;
     RECT  7.812 51.395 8.097 51.511 ;
     RECT  30.816 51.439 30.87 51.511 ;
     RECT  30.78 51.511 30.87 51.539 ;
     RECT  2.304 51.511 8.097 51.629 ;
     RECT  9.108 51.511 9.198 51.629 ;
     RECT  35.928 51.115 35.946 51.787 ;
     RECT  3.888 51.629 8.097 51.899 ;
     RECT  9.108 51.629 9.126 51.899 ;
     RECT  32.004 50.855 34.794 51.979 ;
     RECT  35.928 51.787 35.982 52.051 ;
     RECT  31.716 51.979 34.794 52.123 ;
     RECT  35.928 52.051 36.054 52.123 ;
     RECT  6.192 51.899 8.097 52.169 ;
     RECT  31.716 52.123 36.054 52.169 ;
     RECT  31.716 52.169 34.758 52.241 ;
     RECT  30.78 51.539 30.834 52.321 ;
     RECT  30.78 52.321 30.87 52.349 ;
     RECT  2.304 51.629 3.006 52.411 ;
     RECT  6.192 52.169 6.894 52.439 ;
     RECT  30.852 52.349 30.87 52.439 ;
     RECT  35.928 52.169 36.054 52.445 ;
     RECT  2.268 52.411 3.006 52.583 ;
     RECT  2.304 52.583 3.006 52.861 ;
     RECT  3.888 51.899 5.397 52.861 ;
     RECT  32.004 52.241 34.758 52.939 ;
     RECT  35.928 52.445 35.982 52.939 ;
     RECT  32.004 52.939 35.982 52.987 ;
     RECT  9.216 52.861 9.306 53.221 ;
     RECT  2.304 52.861 5.397 53.227 ;
     RECT  6.3 52.439 6.894 53.227 ;
     RECT  2.304 53.227 6.894 53.329 ;
     RECT  9.216 53.221 9.342 53.429 ;
     RECT  2.304 53.329 6.93 53.515 ;
     RECT  7.668 52.169 8.097 53.515 ;
     RECT  9.216 53.429 9.306 53.519 ;
     RECT  0.252 53.419 0.27 53.549 ;
     RECT  31.932 52.987 35.982 53.591 ;
     RECT  35.388 53.591 35.982 53.597 ;
     RECT  35.388 53.597 35.946 53.789 ;
     RECT  31.932 53.591 34.254 53.869 ;
     RECT  30.852 53.833 30.87 53.933 ;
     RECT  2.304 53.515 8.097 54.043 ;
     RECT  31.86 53.869 34.254 54.175 ;
     RECT  2.268 54.043 8.097 54.329 ;
     RECT  31.68 54.175 34.254 54.337 ;
     RECT  2.268 54.329 6.354 54.365 ;
     RECT  35.928 53.789 35.946 54.523 ;
     RECT  7.092 54.329 8.097 54.571 ;
     RECT  31.392 54.337 34.254 54.599 ;
     RECT  35.928 54.523 35.982 54.679 ;
     RECT  32.115 54.599 34.254 54.715 ;
     RECT  35.316 54.679 35.982 54.715 ;
     RECT  2.304 54.365 2.934 55.111 ;
     RECT  3.744 54.365 6.354 55.111 ;
     RECT  7.092 54.571 8.694 55.111 ;
     RECT  0.252 55.051 0.27 55.181 ;
     RECT  2.304 55.111 8.694 55.283 ;
     RECT  30.78 55.147 30.798 55.417 ;
     RECT  2.304 55.283 6.822 55.517 ;
     RECT  30.78 55.417 30.87 55.589 ;
     RECT  32.115 54.715 35.982 55.679 ;
     RECT  2.304 55.517 6.606 55.715 ;
     RECT  4.212 55.715 6.606 55.859 ;
     RECT  35.928 55.679 35.982 55.867 ;
     RECT  7.815 55.283 8.694 55.921 ;
     RECT  10.515 48.839 10.797 55.921 ;
     RECT  7.815 55.921 8.874 56.029 ;
     RECT  10.515 55.921 10.926 56.093 ;
     RECT  7.815 56.029 8.946 56.101 ;
     RECT  32.115 55.679 34.794 56.101 ;
     RECT  31.932 56.101 34.794 56.219 ;
     RECT  7.815 56.101 9.234 56.327 ;
     RECT  35.928 55.867 36.018 56.399 ;
     RECT  7.815 56.327 8.37 56.489 ;
     RECT  32.115 56.219 34.794 56.491 ;
     RECT  30.78 55.589 30.798 56.533 ;
     RECT  2.304 55.715 2.697 56.569 ;
     RECT  3.42 55.715 3.438 56.569 ;
     RECT  2.304 56.569 3.618 56.641 ;
     RECT  4.428 55.859 6.606 56.641 ;
     RECT  7.815 56.489 8.226 56.641 ;
     RECT  9.324 56.641 9.342 56.831 ;
     RECT  30.78 56.533 30.87 56.831 ;
     RECT  30.78 56.831 30.798 56.903 ;
     RECT  9.54 56.911 9.558 57.029 ;
     RECT  2.304 56.641 8.226 57.299 ;
     RECT  32.115 56.491 34.83 57.307 ;
     RECT  35.928 56.399 35.982 57.307 ;
     RECT  7.815 57.299 8.226 57.451 ;
     RECT  32.115 57.307 35.982 57.479 ;
     RECT  32.115 57.479 35.946 57.677 ;
     RECT  2.304 57.299 7.074 57.787 ;
     RECT  2.268 57.787 7.074 57.875 ;
     RECT  32.115 57.677 34.254 57.919 ;
     RECT  2.304 57.875 7.074 58.013 ;
     RECT  7.815 57.451 8.442 58.019 ;
     RECT  35.352 57.677 35.946 58.487 ;
     RECT  35.388 58.487 35.946 58.493 ;
     RECT  7.815 58.019 8.262 58.495 ;
     RECT  30.78 57.883 30.798 58.523 ;
     RECT  9.648 58.117 9.666 58.531 ;
     RECT  9.648 58.531 9.738 58.649 ;
     RECT  31.932 57.919 34.254 58.657 ;
     RECT  30.852 58.657 30.87 58.699 ;
     RECT  31.608 58.657 34.254 58.699 ;
     RECT  7.74 58.495 8.262 58.999 ;
     RECT  2.304 58.013 6.858 59.071 ;
     RECT  7.74 58.999 8.406 59.071 ;
     RECT  35.892 58.493 35.946 59.083 ;
     RECT  2.304 59.071 8.406 59.099 ;
     RECT  7.344 59.099 8.406 59.189 ;
     RECT  30.852 58.699 34.254 59.275 ;
     RECT  2.304 59.099 6.39 59.419 ;
     RECT  30.852 59.275 34.758 59.419 ;
     RECT  9.216 59.341 9.234 59.459 ;
     RECT  30.852 59.419 34.794 59.467 ;
     RECT  30.78 59.467 34.794 59.567 ;
     RECT  30.852 59.567 34.794 59.755 ;
     RECT  35.892 59.083 35.982 59.755 ;
     RECT  2.268 59.419 6.39 59.765 ;
     RECT  7.815 59.189 8.334 59.947 ;
     RECT  30.852 59.755 35.982 60.071 ;
     RECT  2.304 59.765 6.39 60.151 ;
     RECT  7.452 59.947 8.334 60.151 ;
     RECT  30.852 60.071 34.758 60.179 ;
     RECT  30.852 60.179 34.254 60.269 ;
     RECT  0.216 60.235 0.234 60.365 ;
     RECT  31.716 60.269 34.254 60.377 ;
     RECT  2.304 60.151 8.334 60.421 ;
     RECT  35.928 60.071 35.982 60.427 ;
     RECT  30.852 60.269 30.87 60.547 ;
     RECT  2.304 60.421 8.766 60.611 ;
     RECT  30.78 60.547 30.87 60.683 ;
     RECT  4.284 60.611 8.766 60.691 ;
     RECT  10.515 56.093 10.797 60.853 ;
     RECT  4.284 60.691 8.802 60.881 ;
     RECT  30.78 60.683 30.834 60.953 ;
     RECT  7.815 60.881 8.802 60.989 ;
     RECT  10.515 60.853 10.818 60.989 ;
     RECT  30.816 60.953 30.834 60.989 ;
     RECT  2.304 60.611 3.366 61.051 ;
     RECT  35.928 60.427 36.018 61.051 ;
     RECT  2.268 61.051 3.366 61.187 ;
     RECT  31.716 60.377 34.218 61.429 ;
     RECT  9.216 61.231 9.234 61.457 ;
     RECT  31.176 61.429 34.218 61.465 ;
     RECT  2.304 61.187 3.366 61.501 ;
     RECT  4.284 60.881 6.93 61.501 ;
     RECT  31.176 61.465 34.254 61.619 ;
     RECT  2.304 61.501 6.93 61.655 ;
     RECT  7.815 60.989 8.298 61.699 ;
     RECT  3.888 61.655 6.93 61.771 ;
     RECT  9.468 61.501 9.486 61.889 ;
     RECT  32.004 61.619 34.254 61.889 ;
     RECT  10.515 60.989 10.797 61.897 ;
     RECT  30.852 61.861 30.87 61.897 ;
     RECT  35.352 61.051 36.018 61.961 ;
     RECT  2.304 61.655 3.114 61.997 ;
     RECT  3.888 61.771 7.002 62.005 ;
     RECT  7.812 61.699 8.298 62.005 ;
     RECT  35.892 61.961 36.018 62.011 ;
     RECT  10.515 61.897 10.854 62.069 ;
     RECT  3.888 62.005 8.298 62.131 ;
     RECT  32.076 61.889 34.254 62.167 ;
     RECT  35.892 62.011 36.09 62.303 ;
     RECT  2.412 61.997 3.114 62.473 ;
     RECT  3.888 62.131 8.442 62.473 ;
     RECT  35.892 62.303 36.054 62.573 ;
     RECT  2.412 62.473 8.442 62.581 ;
     RECT  32.076 62.167 34.29 62.581 ;
     RECT  32.076 62.581 34.362 62.683 ;
     RECT  2.412 62.581 8.586 62.735 ;
     RECT  2.412 62.735 2.697 62.779 ;
     RECT  0.252 62.683 0.27 62.813 ;
     RECT  32.076 62.683 34.794 62.815 ;
     RECT  3.6 62.735 8.586 62.879 ;
     RECT  30.78 61.897 30.87 62.977 ;
     RECT  31.68 62.815 34.794 62.977 ;
     RECT  2.34 62.779 2.697 63.004 ;
     RECT  2.304 63.004 2.697 63.121 ;
     RECT  4.392 62.879 8.586 63.121 ;
     RECT  4.392 63.121 8.766 63.149 ;
     RECT  35.928 62.573 35.982 63.197 ;
     RECT  6.984 63.149 8.766 63.239 ;
     RECT  30.78 62.977 34.794 63.239 ;
     RECT  6.984 63.239 8.097 63.245 ;
     RECT  30.78 63.239 30.87 63.275 ;
     RECT  35.928 63.197 35.946 63.419 ;
     RECT  4.392 63.149 6.246 63.533 ;
     RECT  2.268 63.121 2.697 63.625 ;
     RECT  3.6 62.879 3.654 63.625 ;
     RECT  4.392 63.533 6.21 63.653 ;
     RECT  2.268 63.625 3.654 63.661 ;
     RECT  4.392 63.653 6.174 63.661 ;
     RECT  2.268 63.661 6.174 63.779 ;
     RECT  30.78 63.275 30.798 63.779 ;
     RECT  2.268 63.779 6.066 63.815 ;
     RECT  2.304 63.815 6.066 63.821 ;
     RECT  2.304 63.821 5.994 63.851 ;
     RECT  10.515 62.069 10.797 64.057 ;
     RECT  32.112 63.239 34.794 64.201 ;
     RECT  31.932 64.201 34.794 64.315 ;
     RECT  35.928 64.171 35.946 64.315 ;
     RECT  7.2 63.245 8.097 64.555 ;
     RECT  7.128 64.555 8.097 64.561 ;
     RECT  30.852 64.093 30.87 64.561 ;
     RECT  10.515 64.057 10.818 64.597 ;
     RECT  10.515 64.597 10.926 64.697 ;
     RECT  30.852 64.561 30.942 64.705 ;
     RECT  2.304 63.851 5.397 64.741 ;
     RECT  7.056 64.561 8.097 64.741 ;
     RECT  31.932 64.315 35.946 64.741 ;
     RECT  31.896 64.741 35.946 64.795 ;
     RECT  6.912 64.741 8.097 64.859 ;
     RECT  9.072 64.741 9.09 64.859 ;
     RECT  30.78 64.705 30.942 64.967 ;
     RECT  31.896 64.795 35.982 65.237 ;
     RECT  2.304 64.741 5.958 65.272 ;
     RECT  10.515 64.697 10.818 65.399 ;
     RECT  31.896 65.237 35.01 65.399 ;
     RECT  2.268 65.272 5.958 65.435 ;
     RECT  30.78 64.967 30.87 65.507 ;
     RECT  30.78 65.507 30.798 65.543 ;
     RECT  6.984 64.859 8.097 65.549 ;
     RECT  2.304 65.435 5.958 65.611 ;
     RECT  6.984 65.549 7.074 65.749 ;
     RECT  7.815 65.549 8.097 65.821 ;
     RECT  32.115 65.399 35.01 65.849 ;
     RECT  32.115 65.849 34.254 66.011 ;
     RECT  0.252 65.995 0.27 66.125 ;
     RECT  2.304 65.611 6.174 66.187 ;
     RECT  6.948 65.749 7.074 66.187 ;
     RECT  32.115 66.011 34.218 66.325 ;
     RECT  2.304 66.187 7.074 66.361 ;
     RECT  7.815 65.821 8.622 66.361 ;
     RECT  10.515 65.399 10.797 66.361 ;
     RECT  32.004 66.325 34.218 66.361 ;
     RECT  2.304 66.361 8.622 66.479 ;
     RECT  31.896 66.361 34.218 66.479 ;
     RECT  30.888 66.325 30.906 66.487 ;
     RECT  35.928 65.237 35.982 66.571 ;
     RECT  10.515 66.361 10.854 66.659 ;
     RECT  34.992 65.849 35.01 66.763 ;
     RECT  35.928 66.571 36.054 66.763 ;
     RECT  34.992 66.763 36.054 66.857 ;
     RECT  32.112 66.479 34.218 66.907 ;
     RECT  34.992 66.857 35.982 66.907 ;
     RECT  32.112 66.907 35.982 66.929 ;
     RECT  30.852 66.487 30.906 67.063 ;
     RECT  0.252 66.907 0.27 67.085 ;
     RECT  30.78 67.063 30.906 67.127 ;
     RECT  32.112 66.929 35.37 67.133 ;
     RECT  30.78 67.127 30.798 67.163 ;
     RECT  32.112 67.133 35.01 67.199 ;
     RECT  2.304 66.479 8.586 67.289 ;
     RECT  32.112 67.199 34.83 67.297 ;
     RECT  2.304 67.289 8.097 67.559 ;
     RECT  8.856 67.441 8.874 67.739 ;
     RECT  35.928 67.723 35.946 67.915 ;
     RECT  2.304 67.559 6.894 68.059 ;
     RECT  2.268 68.059 6.894 68.093 ;
     RECT  31.572 67.297 34.83 68.107 ;
     RECT  30.852 68.107 34.83 68.143 ;
     RECT  35.928 67.915 35.982 68.207 ;
     RECT  2.268 68.093 6.786 68.243 ;
     RECT  7.776 67.559 8.097 68.377 ;
     RECT  30.78 68.143 34.83 68.449 ;
     RECT  35.928 68.207 35.946 68.449 ;
     RECT  2.304 68.243 6.786 68.549 ;
     RECT  7.776 68.377 8.154 68.639 ;
     RECT  30.78 68.449 35.946 68.819 ;
     RECT  30.888 68.819 35.946 68.909 ;
     RECT  31.068 68.909 35.946 68.915 ;
     RECT  2.304 68.549 6.282 68.945 ;
     RECT  7.776 68.639 8.097 68.989 ;
     RECT  31.068 68.915 34.794 69.053 ;
     RECT  35.928 68.915 35.946 69.355 ;
     RECT  2.34 68.945 6.282 69.403 ;
     RECT  7.092 68.989 8.097 69.403 ;
     RECT  2.34 69.403 8.097 69.457 ;
     RECT  0.252 69.355 0.27 69.485 ;
     RECT  2.34 69.457 8.262 69.547 ;
     RECT  10.515 66.659 10.797 69.601 ;
     RECT  35.928 69.355 36.018 69.629 ;
     RECT  2.34 69.547 8.478 69.691 ;
     RECT  35.928 69.629 35.982 69.691 ;
     RECT  2.304 69.691 8.478 69.719 ;
     RECT  31.068 69.053 34.434 69.719 ;
     RECT  2.304 69.719 5.397 69.755 ;
     RECT  10.515 69.601 10.926 69.791 ;
     RECT  6.12 69.719 8.478 69.871 ;
     RECT  35.352 69.691 35.982 69.899 ;
     RECT  6.12 69.871 8.622 70.259 ;
     RECT  35.352 69.899 35.946 70.259 ;
     RECT  7.632 70.259 8.622 70.303 ;
     RECT  7.632 70.303 9.198 70.411 ;
     RECT  7.632 70.411 9.27 70.529 ;
     RECT  2.304 69.755 4.194 70.565 ;
     RECT  6.12 70.259 6.858 70.565 ;
     RECT  5.115 69.755 5.397 70.645 ;
     RECT  35.928 70.259 35.946 70.651 ;
     RECT  31.752 69.719 34.29 70.681 ;
     RECT  3.888 70.565 4.194 70.795 ;
     RECT  5.115 70.645 5.706 70.795 ;
     RECT  6.66 70.565 6.858 70.835 ;
     RECT  7.632 70.529 8.766 70.871 ;
     RECT  30.852 69.763 30.942 70.915 ;
     RECT  31.752 70.681 34.722 70.915 ;
     RECT  6.804 70.835 6.858 71.041 ;
     RECT  7.632 70.871 8.262 71.041 ;
     RECT  30.852 70.915 34.722 71.069 ;
     RECT  0.252 70.987 0.27 71.117 ;
     RECT  3.888 70.795 5.706 71.213 ;
     RECT  30.888 71.069 30.906 71.249 ;
     RECT  3.996 71.213 5.706 71.383 ;
     RECT  35.928 70.651 35.982 71.467 ;
     RECT  31.896 71.069 33.858 71.609 ;
     RECT  6.804 71.041 8.262 71.707 ;
     RECT  3.996 71.383 5.922 71.725 ;
     RECT  6.768 71.707 8.262 71.725 ;
     RECT  34.776 71.323 34.794 71.803 ;
     RECT  35.928 71.467 36.018 71.803 ;
     RECT  32.076 71.609 33.858 71.887 ;
     RECT  34.776 71.803 36.018 71.947 ;
     RECT  2.304 70.565 3.114 72.031 ;
     RECT  3.996 71.725 8.262 72.031 ;
     RECT  32.076 71.887 33.966 72.031 ;
     RECT  34.74 71.947 36.018 72.031 ;
     RECT  2.304 72.031 8.442 72.185 ;
     RECT  0.252 72.187 0.27 72.317 ;
     RECT  32.076 72.031 36.018 72.329 ;
     RECT  30.78 71.923 30.798 72.427 ;
     RECT  30.78 72.427 30.87 72.463 ;
     RECT  32.076 72.329 35.982 72.463 ;
     RECT  3.96 72.185 8.442 72.571 ;
     RECT  3.96 72.571 8.586 72.689 ;
     RECT  3.96 72.689 8.154 72.869 ;
     RECT  3.96 72.869 7.038 72.959 ;
     RECT  30.78 72.463 35.982 72.959 ;
     RECT  2.304 72.185 3.222 72.995 ;
     RECT  30.78 72.959 30.87 73.409 ;
     RECT  32.115 72.959 35.982 73.469 ;
     RECT  32.115 73.469 34.794 73.499 ;
     RECT  7.776 72.869 8.154 73.535 ;
     RECT  35.928 73.469 35.982 73.771 ;
     RECT  6.624 72.959 7.038 73.849 ;
     RECT  7.776 73.535 8.097 73.849 ;
     RECT  3.96 72.959 5.886 73.867 ;
     RECT  6.624 73.849 8.097 73.867 ;
     RECT  2.304 72.995 3.114 73.915 ;
     RECT  35.928 73.771 36.018 73.915 ;
     RECT  2.268 73.915 3.114 73.921 ;
     RECT  3.96 73.867 8.097 73.921 ;
     RECT  2.268 73.921 8.097 74.075 ;
     RECT  8.928 73.507 8.946 74.183 ;
     RECT  2.304 74.075 8.097 74.345 ;
     RECT  32.115 73.499 34.254 74.389 ;
     RECT  35.928 73.915 36.09 74.453 ;
     RECT  30.78 73.409 30.834 74.579 ;
     RECT  32.076 74.389 34.254 74.587 ;
     RECT  30.78 74.579 30.798 74.651 ;
     RECT  3.564 74.345 8.097 75.001 ;
     RECT  32.076 74.587 34.794 75.119 ;
     RECT  3.564 75.001 8.514 75.127 ;
     RECT  2.304 74.345 2.697 75.163 ;
     RECT  3.564 75.127 8.586 75.163 ;
     RECT  0.252 75.067 0.27 75.197 ;
     RECT  2.304 75.163 9.126 75.227 ;
     RECT  35.928 74.453 35.982 75.299 ;
     RECT  32.115 75.119 34.794 75.403 ;
     RECT  35.928 75.299 35.946 75.403 ;
     RECT  2.304 75.227 8.154 75.425 ;
     RECT  2.304 75.425 6.318 75.547 ;
     RECT  2.268 75.547 6.318 75.659 ;
     RECT  9.108 75.227 9.126 75.659 ;
     RECT  32.115 75.403 35.946 75.767 ;
     RECT  35.352 75.767 35.946 76.027 ;
     RECT  2.268 75.659 6.174 76.037 ;
     RECT  2.268 76.037 6.102 76.073 ;
     RECT  7.2 75.425 8.154 76.207 ;
     RECT  35.352 76.027 35.982 76.219 ;
     RECT  2.304 76.073 6.102 76.271 ;
     RECT  7.2 76.207 9.054 76.271 ;
     RECT  32.115 75.767 34.254 76.351 ;
     RECT  32.112 76.351 34.254 76.441 ;
     RECT  31.644 76.441 34.254 76.504 ;
     RECT  35.352 76.219 36.018 76.504 ;
     RECT  31.644 76.504 36.018 76.577 ;
     RECT  7.815 76.271 9.054 76.711 ;
     RECT  7.815 76.711 9.522 76.811 ;
     RECT  31.644 76.577 35.982 76.847 ;
     RECT  31.644 76.847 35.37 76.883 ;
     RECT  9.252 76.811 9.522 76.919 ;
     RECT  2.304 76.271 5.922 76.925 ;
     RECT  6.984 76.621 7.002 77.009 ;
     RECT  30.78 75.973 30.798 77.017 ;
     RECT  9.252 76.919 9.45 77.279 ;
     RECT  9.252 77.279 9.27 77.549 ;
     RECT  2.304 76.925 5.742 77.701 ;
     RECT  6.732 77.275 6.858 77.701 ;
     RECT  31.644 76.883 34.29 77.899 ;
     RECT  35.352 76.883 35.37 77.899 ;
     RECT  7.815 76.811 8.406 77.935 ;
     RECT  30.78 77.017 30.87 77.963 ;
     RECT  2.304 77.701 6.858 78.088 ;
     RECT  31.644 77.899 35.37 78.089 ;
     RECT  7.815 77.935 8.514 78.241 ;
     RECT  2.304 78.088 7.074 78.439 ;
     RECT  7.815 78.241 9.126 78.439 ;
     RECT  32.004 78.089 35.37 78.467 ;
     RECT  2.304 78.439 9.126 78.629 ;
     RECT  2.304 78.629 8.514 78.653 ;
     RECT  35.892 78.475 35.982 78.773 ;
     RECT  30.852 77.963 30.87 78.781 ;
     RECT  30.852 78.781 30.942 78.971 ;
     RECT  30.852 78.971 30.87 78.979 ;
     RECT  2.304 78.653 7.074 79.079 ;
     RECT  7.815 78.653 8.514 79.169 ;
     RECT  30.78 78.979 30.87 79.169 ;
     RECT  32.004 78.467 34.794 79.195 ;
     RECT  35.928 78.773 35.982 79.435 ;
     RECT  9.432 79.213 9.45 79.439 ;
     RECT  2.304 79.079 6.966 79.475 ;
     RECT  35.928 79.435 36.018 79.483 ;
     RECT  30.852 79.169 30.87 79.547 ;
     RECT  31.86 79.195 34.794 79.555 ;
     RECT  35.928 79.483 36.054 79.555 ;
     RECT  31.86 79.555 36.054 79.661 ;
     RECT  4.608 79.475 6.966 79.709 ;
     RECT  4.716 79.709 6.966 79.757 ;
     RECT  35.928 79.661 36.054 79.805 ;
     RECT  31.86 79.661 34.83 79.825 ;
     RECT  4.824 79.757 6.966 79.861 ;
     RECT  7.815 79.169 8.097 79.861 ;
     RECT  9.504 79.591 9.522 79.889 ;
     RECT  2.304 79.475 3.87 79.963 ;
     RECT  4.824 79.861 8.097 80.131 ;
     RECT  35.928 79.805 36.018 80.159 ;
     RECT  4.824 80.131 8.514 80.249 ;
     RECT  2.268 79.963 3.87 80.527 ;
     RECT  31.824 79.825 34.83 80.527 ;
     RECT  9.684 80.221 9.702 80.563 ;
     RECT  10.515 69.791 10.797 80.563 ;
     RECT  31.464 80.527 34.83 80.587 ;
     RECT  35.928 80.159 35.982 80.587 ;
     RECT  9.684 80.563 10.797 80.789 ;
     RECT  0.216 80.731 0.234 80.861 ;
     RECT  31.464 80.587 35.982 80.897 ;
     RECT  2.268 80.527 3.906 80.941 ;
     RECT  6.264 80.249 8.514 81.139 ;
     RECT  31.464 80.897 34.794 81.139 ;
     RECT  2.268 80.941 4.05 81.211 ;
     RECT  4.824 80.249 5.397 81.211 ;
     RECT  2.268 81.211 5.397 81.259 ;
     RECT  6.264 81.139 8.622 81.259 ;
     RECT  2.268 81.259 8.622 81.329 ;
     RECT  2.268 81.329 6.93 81.365 ;
     RECT  30.78 81.139 34.794 81.365 ;
     RECT  7.815 81.329 8.478 81.389 ;
     RECT  31.932 81.365 34.794 81.581 ;
     RECT  4.824 81.365 6.93 81.599 ;
     RECT  4.824 81.599 6.822 81.671 ;
     RECT  2.268 81.365 4.05 81.707 ;
     RECT  30.78 81.365 31.194 81.869 ;
     RECT  31.932 81.581 34.29 81.869 ;
     RECT  32.004 81.869 34.29 82.139 ;
     RECT  30.78 81.869 30.87 82.247 ;
     RECT  2.304 81.707 4.05 82.255 ;
     RECT  4.824 81.671 6.318 82.255 ;
     RECT  2.304 82.255 6.318 82.552 ;
     RECT  2.268 82.552 6.318 82.561 ;
     RECT  7.815 81.389 8.097 82.699 ;
     RECT  35.928 80.897 35.982 82.751 ;
     RECT  2.268 82.561 6.426 82.795 ;
     RECT  7.704 82.699 8.097 82.831 ;
     RECT  35.928 82.751 35.946 82.891 ;
     RECT  7.704 82.831 8.946 82.949 ;
     RECT  10.515 80.789 10.797 83.029 ;
     RECT  32.115 82.139 34.29 83.035 ;
     RECT  35.352 82.891 35.946 83.035 ;
     RECT  32.115 83.035 35.946 83.065 ;
     RECT  10.515 83.029 10.818 83.129 ;
     RECT  31.932 83.065 35.946 83.129 ;
     RECT  2.268 82.795 6.93 83.179 ;
     RECT  7.704 82.949 8.097 83.179 ;
     RECT  31.932 83.129 34.254 83.191 ;
     RECT  2.268 83.179 8.097 83.213 ;
     RECT  31.86 83.191 34.254 83.261 ;
     RECT  35.352 83.129 35.946 83.707 ;
     RECT  6.228 83.213 8.097 83.731 ;
     RECT  35.352 83.707 35.982 83.759 ;
     RECT  31.896 83.261 34.254 83.995 ;
     RECT  10.515 83.129 10.797 84.109 ;
     RECT  30.78 82.247 30.798 84.109 ;
     RECT  31.896 83.995 34.794 84.109 ;
     RECT  2.268 83.213 5.454 84.271 ;
     RECT  6.228 83.731 8.226 84.271 ;
     RECT  10.515 84.109 10.818 84.371 ;
     RECT  35.928 83.759 35.982 84.451 ;
     RECT  35.928 84.451 36.018 84.509 ;
     RECT  2.268 84.271 8.226 84.605 ;
     RECT  3.744 84.605 8.226 84.649 ;
     RECT  30.78 84.109 34.794 84.749 ;
     RECT  2.268 84.605 2.826 84.875 ;
     RECT  31.068 84.749 34.794 85.109 ;
     RECT  31.428 85.109 34.794 85.181 ;
     RECT  10.515 84.371 10.797 85.261 ;
     RECT  32.115 85.181 34.794 85.261 ;
     RECT  35.928 84.509 35.982 85.261 ;
     RECT  32.115 85.261 35.982 85.325 ;
     RECT  3.744 84.649 8.262 85.379 ;
     RECT  2.304 84.875 2.826 85.387 ;
     RECT  0.216 85.291 0.234 85.421 ;
     RECT  7.128 85.379 8.262 85.421 ;
     RECT  10.515 85.261 10.854 85.451 ;
     RECT  2.304 85.387 3.006 85.685 ;
     RECT  35.928 85.325 35.982 85.729 ;
     RECT  32.115 85.325 34.794 85.963 ;
     RECT  31.932 85.963 34.794 86.035 ;
     RECT  7.2 85.421 8.097 86.063 ;
     RECT  3.744 85.379 6.282 86.071 ;
     RECT  9.18 85.351 9.198 86.189 ;
     RECT  31.392 86.035 34.794 86.189 ;
     RECT  3.672 86.071 6.282 86.341 ;
     RECT  30.78 86.233 30.834 86.369 ;
     RECT  3.672 86.341 6.858 86.431 ;
     RECT  2.304 85.685 2.697 86.443 ;
     RECT  35.928 85.729 36.018 86.443 ;
     RECT  2.268 86.443 2.697 86.495 ;
     RECT  30.816 86.369 30.834 86.495 ;
     RECT  35.856 86.443 36.018 86.779 ;
     RECT  2.304 86.495 2.697 86.881 ;
     RECT  3.42 86.431 6.858 86.881 ;
     RECT  10.515 85.451 10.797 86.971 ;
     RECT  7.815 86.063 8.097 87.043 ;
     RECT  32.115 86.189 34.794 87.071 ;
     RECT  7.815 87.043 8.19 87.101 ;
     RECT  35.856 86.779 36.054 87.259 ;
     RECT  9.648 87.151 9.666 87.421 ;
     RECT  35.352 87.259 36.054 87.449 ;
     RECT  2.304 86.881 6.858 87.451 ;
     RECT  9.648 87.421 9.738 87.539 ;
     RECT  2.268 87.451 6.858 87.575 ;
     RECT  6.228 87.575 6.858 87.583 ;
     RECT  7.815 87.101 8.097 87.583 ;
     RECT  10.515 86.971 10.818 87.647 ;
     RECT  2.304 87.575 5.49 87.683 ;
     RECT  32.115 87.071 34.254 87.691 ;
     RECT  6.228 87.583 8.097 87.719 ;
     RECT  35.352 87.449 36.018 87.989 ;
     RECT  30.78 87.925 30.798 88.051 ;
     RECT  32.004 87.691 34.254 88.075 ;
     RECT  35.352 87.989 35.982 88.075 ;
     RECT  30.78 88.051 30.87 88.087 ;
     RECT  30.78 88.087 30.942 88.223 ;
     RECT  0.252 87.643 0.27 88.253 ;
     RECT  9.108 87.961 9.198 88.349 ;
     RECT  2.34 87.683 5.49 88.411 ;
     RECT  2.304 88.411 5.49 88.555 ;
     RECT  2.268 88.555 5.49 88.627 ;
     RECT  6.228 87.719 6.93 88.627 ;
     RECT  2.268 88.627 6.93 88.655 ;
     RECT  32.004 88.075 35.982 88.699 ;
     RECT  2.304 88.655 6.93 88.735 ;
     RECT  2.304 88.735 6.966 88.861 ;
     RECT  7.815 87.719 8.097 88.861 ;
     RECT  2.304 88.861 8.097 89.159 ;
     RECT  2.304 89.159 6.57 89.195 ;
     RECT  30.78 88.223 30.87 89.302 ;
     RECT  30.78 89.302 30.906 89.303 ;
     RECT  7.416 89.159 8.097 89.311 ;
     RECT  30.816 89.303 30.906 89.339 ;
     RECT  31.968 88.699 35.982 89.339 ;
     RECT  30.888 89.339 30.906 89.501 ;
     RECT  31.968 89.339 35.946 89.609 ;
     RECT  31.968 89.609 34.254 89.851 ;
     RECT  9.108 89.239 9.126 89.879 ;
     RECT  31.824 89.851 34.254 89.969 ;
     RECT  0.252 89.851 0.27 90.029 ;
     RECT  6.192 89.195 6.57 90.049 ;
     RECT  7.416 89.311 8.154 90.049 ;
     RECT  2.304 89.195 5.454 90.085 ;
     RECT  6.192 90.049 8.154 90.085 ;
     RECT  2.304 90.085 8.154 90.121 ;
     RECT  2.304 90.121 8.262 90.481 ;
     RECT  35.352 89.609 35.946 90.667 ;
     RECT  2.304 90.481 8.694 90.779 ;
     RECT  10.515 87.647 10.797 90.787 ;
     RECT  10.515 90.787 10.854 90.923 ;
     RECT  31.932 89.969 34.254 91.021 ;
     RECT  7.488 90.779 8.694 91.049 ;
     RECT  31.824 91.021 34.254 91.121 ;
     RECT  31.968 91.121 34.254 91.129 ;
     RECT  2.304 90.779 6.282 91.192 ;
     RECT  35.352 90.667 35.982 91.229 ;
     RECT  31.968 91.129 34.29 91.471 ;
     RECT  35.352 91.229 35.37 91.471 ;
     RECT  31.968 91.471 35.37 91.517 ;
     RECT  30.78 90.283 30.798 91.597 ;
     RECT  31.968 91.517 34.29 91.613 ;
     RECT  2.268 91.192 6.282 91.705 ;
     RECT  30.78 91.597 30.834 91.733 ;
     RECT  9.108 91.471 9.126 91.769 ;
     RECT  30.78 91.733 30.798 91.769 ;
     RECT  32.115 91.613 34.29 91.931 ;
     RECT  35.352 91.517 35.37 91.963 ;
     RECT  35.352 91.963 35.946 92.155 ;
     RECT  2.268 91.705 6.678 92.165 ;
     RECT  2.304 92.165 6.678 92.281 ;
     RECT  7.488 91.049 8.097 92.281 ;
     RECT  0.252 92.203 0.27 92.333 ;
     RECT  31.356 92.515 31.374 92.641 ;
     RECT  9.216 92.515 9.234 92.669 ;
     RECT  35.352 92.155 36.018 92.669 ;
     RECT  32.115 91.931 34.254 92.749 ;
     RECT  30.78 92.641 31.374 92.785 ;
     RECT  32.115 92.749 34.326 92.785 ;
     RECT  30.78 92.785 34.326 92.939 ;
     RECT  2.304 92.281 8.097 92.983 ;
     RECT  2.304 92.983 8.154 93.281 ;
     RECT  30.78 92.939 30.798 93.317 ;
     RECT  35.892 92.669 36.018 93.353 ;
     RECT  2.304 93.281 8.097 93.451 ;
     RECT  35.928 93.353 36.018 93.659 ;
     RECT  2.268 93.451 8.097 94.171 ;
     RECT  31.86 92.939 34.218 94.261 ;
     RECT  2.268 94.171 8.514 94.289 ;
     RECT  2.268 94.289 8.262 94.325 ;
     RECT  31.86 94.261 34.794 94.405 ;
     RECT  0.252 94.603 0.27 94.733 ;
     RECT  31.572 94.405 34.794 94.733 ;
     RECT  35.928 93.659 35.982 94.739 ;
     RECT  35.928 94.739 35.946 95.071 ;
     RECT  2.304 94.325 8.262 95.099 ;
     RECT  2.304 95.099 8.19 95.369 ;
     RECT  2.304 95.369 8.097 95.411 ;
     RECT  30.78 95.377 30.798 95.477 ;
     RECT  35.352 95.071 35.946 95.477 ;
     RECT  31.572 94.733 34.326 95.521 ;
     RECT  5.076 95.411 8.097 95.549 ;
     RECT  2.304 95.411 4.302 95.639 ;
     RECT  5.076 95.549 7.002 95.639 ;
     RECT  5.076 95.639 6.858 95.693 ;
     RECT  35.928 95.477 35.946 95.707 ;
     RECT  2.304 95.639 4.194 95.711 ;
     RECT  30.852 95.521 34.326 95.899 ;
     RECT  5.076 95.693 6.678 95.981 ;
     RECT  30.852 95.899 34.794 96.017 ;
     RECT  35.928 95.707 36.018 96.017 ;
     RECT  2.304 95.711 4.086 96.043 ;
     RECT  31.824 96.017 34.794 96.179 ;
     RECT  30.852 96.017 30.87 96.223 ;
     RECT  5.076 95.981 5.397 96.283 ;
     RECT  30.78 96.223 30.87 96.287 ;
     RECT  30.78 96.287 30.798 96.323 ;
     RECT  32.112 96.179 34.794 96.449 ;
     RECT  6.228 95.981 6.678 96.457 ;
     RECT  7.776 95.549 8.097 96.457 ;
     RECT  2.268 96.043 4.086 96.485 ;
     RECT  6.228 96.457 8.097 96.529 ;
     RECT  2.304 96.485 4.086 96.601 ;
     RECT  5.04 96.283 5.397 96.601 ;
     RECT  32.115 96.449 34.794 96.715 ;
     RECT  6.228 96.529 8.154 96.791 ;
     RECT  6.228 96.791 6.858 96.871 ;
     RECT  7.815 96.791 8.154 96.955 ;
     RECT  7.815 96.955 8.262 97.105 ;
     RECT  9.108 97.069 9.126 97.105 ;
     RECT  7.815 97.105 9.126 97.141 ;
     RECT  7.815 97.141 9.45 97.169 ;
     RECT  7.815 97.169 8.406 97.259 ;
     RECT  30.78 97.141 30.798 97.331 ;
     RECT  32.115 96.715 34.83 97.375 ;
     RECT  32.112 97.375 34.83 97.531 ;
     RECT  35.928 96.017 35.982 97.531 ;
     RECT  2.304 96.601 5.397 97.645 ;
     RECT  6.12 96.871 6.858 97.645 ;
     RECT  7.815 97.259 8.262 97.645 ;
     RECT  9.216 97.169 9.45 97.709 ;
     RECT  32.112 97.531 35.982 97.709 ;
     RECT  30.852 97.573 30.87 97.771 ;
     RECT  35.352 97.709 35.982 97.799 ;
     RECT  9.36 97.709 9.45 97.907 ;
     RECT  30.852 97.771 31.158 97.915 ;
     RECT  32.112 97.709 34.326 97.915 ;
     RECT  2.304 97.645 8.262 97.943 ;
     RECT  2.415 97.943 8.262 98.045 ;
     RECT  30.852 97.915 34.326 98.069 ;
     RECT  32.115 98.069 34.326 98.339 ;
     RECT  30.78 98.077 30.798 98.447 ;
     RECT  0.252 98.395 0.27 98.525 ;
     RECT  2.415 98.045 8.097 98.683 ;
     RECT  35.892 97.799 35.982 98.761 ;
     RECT  2.304 98.683 8.097 98.827 ;
     RECT  35.352 98.761 35.982 98.861 ;
     RECT  35.892 98.861 35.982 98.879 ;
     RECT  32.115 98.339 34.254 98.887 ;
     RECT  2.268 98.827 8.097 99.023 ;
     RECT  31.572 98.887 34.254 99.031 ;
     RECT  31.14 99.031 34.254 99.157 ;
     RECT  2.304 99.023 8.097 99.163 ;
     RECT  9.144 98.491 9.162 99.265 ;
     RECT  31.14 99.157 34.326 99.265 ;
     RECT  9.144 99.265 9.198 99.419 ;
     RECT  30.78 99.265 34.326 99.419 ;
     RECT  9.18 99.419 9.198 99.427 ;
     RECT  9.18 99.427 9.234 99.463 ;
     RECT  30.78 99.419 30.942 99.527 ;
     RECT  9.18 99.463 9.306 99.599 ;
     RECT  30.852 99.527 30.942 99.599 ;
     RECT  35.928 98.879 35.982 99.643 ;
     RECT  30.852 99.599 30.87 99.761 ;
     RECT  35.352 99.643 35.982 99.869 ;
     RECT  32.115 99.419 34.326 99.979 ;
     RECT  35.352 99.869 35.946 99.979 ;
     RECT  2.304 99.163 8.19 100.309 ;
     RECT  2.304 100.309 8.658 100.459 ;
     RECT  2.268 100.459 8.658 100.499 ;
     RECT  32.115 99.979 35.946 100.499 ;
     RECT  29.415 40.733 29.697 100.543 ;
     RECT  2.268 100.499 8.298 100.607 ;
     RECT  29.415 100.543 30.222 100.651 ;
     RECT  2.304 100.607 8.298 100.769 ;
     RECT  32.115 100.499 34.794 100.885 ;
     RECT  29.415 100.651 30.798 101.039 ;
     RECT  31.536 100.885 34.794 101.039 ;
     RECT  35.892 100.499 35.946 101.219 ;
     RECT  32.004 101.039 34.794 101.275 ;
     RECT  30.78 101.039 30.798 101.453 ;
     RECT  7.272 100.769 8.262 101.579 ;
     RECT  2.304 100.769 6.534 101.587 ;
     RECT  7.815 101.579 8.262 101.731 ;
     RECT  32.004 101.275 34.866 101.821 ;
     RECT  7.815 101.731 8.622 101.849 ;
     RECT  10.515 90.923 10.797 101.857 ;
     RECT  0.252 101.275 0.27 101.885 ;
     RECT  35.928 101.219 35.946 101.899 ;
     RECT  10.515 101.857 10.854 102.029 ;
     RECT  31.716 101.821 34.866 102.235 ;
     RECT  31.428 102.235 34.866 102.263 ;
     RECT  31.428 102.263 34.326 102.397 ;
     RECT  35.928 101.899 35.982 102.427 ;
     RECT  31.068 102.397 34.326 102.433 ;
     RECT  30.78 102.433 34.326 102.533 ;
     RECT  35.352 102.427 35.982 102.569 ;
     RECT  2.304 101.587 6.786 102.619 ;
     RECT  7.815 101.849 8.097 102.619 ;
     RECT  2.304 102.619 8.097 102.659 ;
     RECT  8.928 102.271 8.946 102.659 ;
     RECT  30.852 102.533 34.326 102.659 ;
     RECT  3.636 102.659 8.097 102.811 ;
     RECT  9.108 102.811 9.126 102.929 ;
     RECT  0.252 102.907 0.27 103.037 ;
     RECT  31.932 102.659 34.326 103.037 ;
     RECT  30.852 102.659 30.87 103.279 ;
     RECT  32.004 103.037 34.326 103.279 ;
     RECT  35.352 102.569 35.946 103.279 ;
     RECT  2.304 102.659 2.898 103.441 ;
     RECT  3.636 102.811 8.154 103.441 ;
     RECT  2.304 103.441 8.154 103.621 ;
     RECT  32.004 103.279 35.946 103.649 ;
     RECT  30.78 103.279 30.87 103.855 ;
     RECT  2.304 103.621 8.19 104.009 ;
     RECT  30.78 103.855 30.906 104.081 ;
     RECT  30.78 104.081 30.87 104.189 ;
     RECT  32.004 103.649 35.37 104.189 ;
     RECT  32.004 104.189 34.326 104.549 ;
     RECT  35.352 104.189 35.37 104.629 ;
     RECT  30.852 104.189 30.87 104.693 ;
     RECT  35.352 104.629 35.946 104.717 ;
     RECT  2.304 104.009 8.097 104.891 ;
     RECT  8.928 104.791 8.946 105.089 ;
     RECT  32.115 104.549 34.326 105.16 ;
     RECT  35.352 104.717 35.406 105.16 ;
     RECT  30.78 105.097 30.798 105.197 ;
     RECT  32.115 105.16 35.406 105.197 ;
     RECT  3.924 104.891 8.097 105.439 ;
     RECT  35.352 105.197 35.406 105.499 ;
     RECT  3.924 105.439 8.262 105.539 ;
     RECT  32.115 105.197 34.218 105.637 ;
     RECT  35.352 105.499 35.946 105.643 ;
     RECT  2.304 104.891 3.186 105.745 ;
     RECT  3.924 105.539 8.19 105.745 ;
     RECT  2.304 105.745 8.19 105.773 ;
     RECT  2.304 105.773 8.118 105.899 ;
     RECT  35.352 105.643 35.982 106.171 ;
     RECT  2.304 105.899 6.282 106.312 ;
     RECT  32.004 105.637 34.218 106.321 ;
     RECT  7.308 105.899 8.097 106.439 ;
     RECT  31.824 106.321 34.218 106.439 ;
     RECT  31.932 106.439 34.218 106.459 ;
     RECT  31.932 106.459 34.254 106.555 ;
     RECT  10.515 102.029 10.797 106.825 ;
     RECT  9.828 106.825 10.797 106.861 ;
     RECT  2.268 106.312 6.282 106.979 ;
     RECT  35.316 106.171 35.982 106.979 ;
     RECT  2.268 106.979 5.922 107.015 ;
     RECT  31.932 106.555 34.326 107.095 ;
     RECT  9.756 106.861 10.797 107.123 ;
     RECT  7.524 106.439 8.097 107.179 ;
     RECT  9.756 107.123 9.774 107.249 ;
     RECT  10.515 107.123 10.797 107.257 ;
     RECT  31.932 107.095 34.362 107.293 ;
     RECT  10.515 107.257 10.854 107.357 ;
     RECT  0.252 107.467 0.27 107.597 ;
     RECT  2.304 107.015 5.922 107.755 ;
     RECT  31.716 107.293 34.362 107.755 ;
     RECT  2.304 107.755 6.138 107.905 ;
     RECT  7.128 107.179 8.097 107.905 ;
     RECT  35.928 106.979 35.982 107.947 ;
     RECT  2.304 107.905 6.282 108.043 ;
     RECT  7.092 107.905 8.097 108.043 ;
     RECT  35.352 107.947 35.982 108.131 ;
     RECT  31.716 107.755 34.398 108.167 ;
     RECT  2.304 108.043 8.097 108.329 ;
     RECT  10.515 107.357 10.797 108.337 ;
     RECT  6.804 108.329 8.097 108.481 ;
     RECT  10.515 108.337 10.818 108.509 ;
     RECT  35.352 108.131 35.946 108.509 ;
     RECT  30.78 106.447 30.798 108.643 ;
     RECT  31.824 108.167 34.398 108.715 ;
     RECT  35.352 108.509 35.406 108.715 ;
     RECT  30.78 108.643 30.87 108.743 ;
     RECT  6.804 108.481 8.694 108.751 ;
     RECT  31.824 108.715 35.406 108.779 ;
     RECT  6.804 108.751 9.09 108.869 ;
     RECT  30.78 108.743 30.798 108.869 ;
     RECT  32.04 108.779 35.406 108.941 ;
     RECT  35.352 108.941 35.406 109.243 ;
     RECT  2.304 108.329 6.03 109.255 ;
     RECT  6.804 108.869 8.226 109.255 ;
     RECT  10.515 108.509 10.797 109.489 ;
     RECT  32.04 108.941 34.398 109.561 ;
     RECT  35.352 109.243 35.946 109.579 ;
     RECT  10.515 109.489 10.818 109.589 ;
     RECT  2.304 109.255 8.226 109.679 ;
     RECT  9 108.869 9.018 109.679 ;
     RECT  30.852 109.687 30.87 109.787 ;
     RECT  10.515 109.589 10.797 109.795 ;
     RECT  31.896 109.561 34.398 109.831 ;
     RECT  31.824 109.831 34.398 109.921 ;
     RECT  9.9 109.795 10.797 109.949 ;
     RECT  2.304 109.679 8.097 110.021 ;
     RECT  31.752 109.921 34.398 110.059 ;
     RECT  35.352 109.579 35.982 110.059 ;
     RECT  2.304 110.021 3.114 110.203 ;
     RECT  3.924 110.021 8.097 110.255 ;
     RECT  3.96 110.255 8.097 110.461 ;
     RECT  2.268 110.203 3.114 110.525 ;
     RECT  31.752 110.059 35.982 110.633 ;
     RECT  31.752 110.633 35.946 110.641 ;
     RECT  31.644 110.641 35.946 110.669 ;
     RECT  31.644 110.669 35.37 110.759 ;
     RECT  31.752 110.759 35.37 110.867 ;
     RECT  10.515 109.949 10.797 110.911 ;
     RECT  3.96 110.461 8.37 111.001 ;
     RECT  30.78 110.803 30.798 111.001 ;
     RECT  9.792 110.911 10.797 111.029 ;
     RECT  2.304 110.525 3.114 111.073 ;
     RECT  3.888 111.001 8.37 111.073 ;
     RECT  30.78 111.001 30.87 111.136 ;
     RECT  2.304 111.073 8.37 111.343 ;
     RECT  30.78 111.136 30.906 111.407 ;
     RECT  2.304 111.343 8.694 111.451 ;
     RECT  32.004 110.867 35.37 111.479 ;
     RECT  2.304 111.451 8.838 111.569 ;
     RECT  2.304 111.569 6.93 111.641 ;
     RECT  7.815 111.569 8.838 111.641 ;
     RECT  35.352 111.479 35.37 111.691 ;
     RECT  2.304 111.641 6.858 111.713 ;
     RECT  8.82 111.641 8.838 111.749 ;
     RECT  32.004 111.479 34.254 111.955 ;
     RECT  2.304 111.713 6.822 112.145 ;
     RECT  30.78 111.407 30.798 112.153 ;
     RECT  30.78 112.153 30.87 112.379 ;
     RECT  6.444 112.145 6.822 112.415 ;
     RECT  31.824 111.955 34.254 112.507 ;
     RECT  35.352 111.691 35.946 112.507 ;
     RECT  7.815 111.641 8.097 112.531 ;
     RECT  31.824 112.507 35.946 112.649 ;
     RECT  35.928 112.649 35.946 112.828 ;
     RECT  2.304 112.145 5.598 112.891 ;
     RECT  2.304 112.891 5.67 112.955 ;
     RECT  6.876 112.531 8.097 112.963 ;
     RECT  3.924 112.955 5.67 113.071 ;
     RECT  6.876 112.963 8.37 113.189 ;
     RECT  31.824 112.649 34.794 113.197 ;
     RECT  30.78 112.379 30.798 113.233 ;
     RECT  2.304 112.955 2.697 113.323 ;
     RECT  3.924 113.071 5.958 113.341 ;
     RECT  6.876 113.189 8.097 113.341 ;
     RECT  31.788 113.197 34.794 113.467 ;
     RECT  35.928 112.828 35.982 113.467 ;
     RECT  2.268 113.323 2.697 113.495 ;
     RECT  9.108 112.891 9.126 113.611 ;
     RECT  9 113.611 9.126 113.639 ;
     RECT  31.788 113.467 35.982 113.639 ;
     RECT  9 113.639 9.018 113.729 ;
     RECT  2.304 113.495 2.697 113.803 ;
     RECT  30.78 113.233 30.834 113.873 ;
     RECT  2.304 113.803 2.862 113.881 ;
     RECT  3.924 113.341 8.097 113.881 ;
     RECT  30.816 113.873 30.834 113.909 ;
     RECT  2.304 113.881 8.097 113.999 ;
     RECT  31.788 113.639 35.946 114.079 ;
     RECT  31.032 114.079 35.946 114.143 ;
     RECT  2.304 113.999 3.186 114.269 ;
     RECT  3.924 113.999 8.097 114.305 ;
     RECT  31.032 114.143 35.37 114.539 ;
     RECT  6.228 114.305 8.097 114.575 ;
     RECT  3.924 114.305 5.454 114.781 ;
     RECT  31.788 114.539 35.37 114.809 ;
     RECT  30.78 114.817 30.798 114.917 ;
     RECT  2.304 114.269 2.79 115.051 ;
     RECT  7.596 114.575 8.097 115.079 ;
     RECT  3.672 114.781 5.454 115.231 ;
     RECT  6.228 114.575 6.858 115.231 ;
     RECT  10.515 111.029 10.797 115.231 ;
     RECT  32.115 114.809 35.37 115.277 ;
     RECT  7.632 115.079 8.097 115.349 ;
     RECT  9.792 115.231 10.797 115.349 ;
     RECT  3.636 115.231 6.858 115.457 ;
     RECT  2.304 115.051 2.826 115.501 ;
     RECT  2.304 115.501 3.438 115.889 ;
     RECT  2.304 115.889 2.826 116.033 ;
     RECT  4.212 115.457 6.858 116.041 ;
     RECT  30.852 115.861 30.87 116.041 ;
     RECT  0.216 116.059 0.234 116.167 ;
     RECT  0.216 116.167 0.27 116.189 ;
     RECT  4.212 116.041 7.002 116.203 ;
     RECT  32.115 115.277 35.082 116.251 ;
     RECT  3.6 116.203 7.002 116.303 ;
     RECT  3.6 116.303 6.75 116.339 ;
     RECT  0.252 116.189 0.27 116.429 ;
     RECT  30.78 116.041 30.87 116.429 ;
     RECT  7.815 115.349 8.097 116.581 ;
     RECT  32.115 116.251 35.37 116.587 ;
     RECT  3.6 116.339 6.714 116.699 ;
     RECT  7.815 116.581 8.622 116.699 ;
     RECT  2.304 116.033 2.697 116.735 ;
     RECT  2.376 116.735 2.697 116.779 ;
     RECT  3.6 116.699 6.246 116.779 ;
     RECT  7.815 116.699 8.298 116.851 ;
     RECT  2.376 116.779 6.246 116.969 ;
     RECT  7.632 116.851 8.298 116.969 ;
     RECT  2.376 116.969 2.697 117.005 ;
     RECT  3.6 116.969 6.246 117.005 ;
     RECT  3.96 117.005 6.246 117.041 ;
     RECT  3.96 117.041 6.066 117.077 ;
     RECT  7.815 116.969 8.298 117.077 ;
     RECT  30.78 116.429 30.798 117.113 ;
     RECT  9.108 117.013 9.126 117.149 ;
     RECT  32.115 116.587 35.874 117.239 ;
     RECT  3.96 117.077 5.397 117.275 ;
     RECT  7.815 117.077 8.226 117.509 ;
     RECT  32.115 117.239 35.082 117.509 ;
     RECT  32.115 117.509 34.866 117.779 ;
     RECT  32.115 117.779 34.83 117.815 ;
     RECT  33.12 117.815 34.83 118.049 ;
     RECT  33.552 118.049 34.83 118.157 ;
     RECT  33.588 118.157 34.83 118.319 ;
     RECT  33.588 118.319 34.218 118.355 ;
     RECT  2.415 117.005 2.697 118.547 ;
     RECT  5.115 117.275 5.397 118.547 ;
     RECT  7.815 117.509 8.097 118.547 ;
     RECT  10.515 115.349 10.797 118.547 ;
     RECT  13.215 2.413 13.497 118.547 ;
     RECT  15.915 2.413 16.197 118.547 ;
     RECT  18.615 2.413 18.897 118.547 ;
     RECT  21.315 40.733 21.597 118.547 ;
     RECT  24.015 2.413 24.297 118.547 ;
     RECT  26.715 2.413 26.997 118.547 ;
     RECT  29.415 101.039 29.697 118.547 ;
     RECT  32.115 117.815 32.397 118.547 ;
     RECT  35.856 117.239 35.874 118.589 ;
     RECT  33.588 118.355 33.606 118.625 ;
     RECT  2.415 118.547 2.505 118.817 ;
     RECT  5.115 118.547 5.205 118.817 ;
     RECT  7.815 118.547 7.905 118.817 ;
     RECT  10.515 118.547 10.605 118.817 ;
     RECT  13.215 118.547 13.305 118.817 ;
     RECT  15.915 118.547 16.005 118.817 ;
     RECT  18.615 118.547 18.705 118.817 ;
     RECT  21.315 118.547 21.405 118.817 ;
     RECT  24.015 118.547 24.105 118.817 ;
     RECT  26.715 118.547 26.805 118.817 ;
     RECT  29.415 118.547 29.505 118.817 ;
     RECT  32.115 118.547 32.205 118.817 ;
     RECT  18.18 120.828 18.198 120.845 ;
    LAYER M4 ;
     RECT  0.156 4.416 2.408 116.616 ;
     RECT  2.408 2.148 2.512 118.812 ;
     RECT  2.512 2.418 2.704 118.542 ;
     RECT  2.704 33.024 2.729 43.32 ;
     RECT  2.704 15.312 2.765 18.264 ;
     RECT  2.704 29.808 2.765 31.944 ;
     RECT  2.729 33.024 2.765 41.976 ;
     RECT  2.704 53.568 2.765 54.12 ;
     RECT  2.704 58.08 2.765 59.256 ;
     RECT  2.704 78.96 2.765 81.432 ;
     RECT  2.704 82.704 2.765 85.656 ;
     RECT  2.704 93.312 2.765 94.152 ;
     RECT  2.704 95.232 2.765 97.176 ;
     RECT  2.704 4.416 2.801 4.44 ;
     RECT  2.704 6.864 2.801 7.416 ;
     RECT  2.765 18.192 2.801 18.264 ;
     RECT  2.704 23.616 2.801 26.088 ;
     RECT  2.765 33.024 2.801 39.288 ;
     RECT  2.729 43.296 2.801 43.32 ;
     RECT  2.704 55.152 2.801 55.56 ;
     RECT  2.704 60.336 2.801 62.568 ;
     RECT  2.765 95.424 2.801 97.176 ;
     RECT  2.765 79.728 2.837 80.856 ;
     RECT  2.704 98.4 2.837 101.88 ;
     RECT  2.704 11.424 2.873 14.184 ;
     RECT  2.801 24.432 2.873 26.088 ;
     RECT  2.765 40.368 2.873 41.976 ;
     RECT  2.704 50.016 2.873 52.296 ;
     RECT  2.704 68.928 2.873 71.112 ;
     RECT  2.837 80.832 2.873 80.856 ;
     RECT  2.801 96.24 2.873 97.176 ;
     RECT  2.837 98.4 2.873 99.192 ;
     RECT  2.704 110.544 2.873 111.768 ;
     RECT  2.704 112.848 2.873 113.832 ;
     RECT  2.704 19.872 2.909 20.376 ;
     RECT  2.873 24.912 2.909 26.088 ;
     RECT  2.873 40.368 2.909 41.64 ;
     RECT  2.704 46.08 2.909 48.984 ;
     RECT  2.704 67.056 2.909 67.32 ;
     RECT  2.704 103.008 2.909 103.752 ;
     RECT  2.704 65.472 2.981 66.024 ;
     RECT  2.873 71.088 2.981 71.112 ;
     RECT  2.704 75.168 2.981 76.44 ;
     RECT  2.765 29.808 3.017 30.648 ;
     RECT  2.873 52.272 3.017 52.296 ;
     RECT  2.801 55.152 3.017 55.176 ;
     RECT  2.704 87.264 3.017 92.232 ;
     RECT  2.837 100.656 3.017 101.88 ;
     RECT  2.704 28.416 3.089 28.536 ;
     RECT  3.017 29.808 3.089 30.504 ;
     RECT  2.909 47.04 3.089 47.88 ;
     RECT  2.873 50.016 3.089 50.616 ;
     RECT  2.801 60.336 3.089 61.416 ;
     RECT  2.704 9.312 3.125 10.152 ;
     RECT  2.873 11.424 3.125 14.04 ;
     RECT  2.765 15.312 3.125 16.824 ;
     RECT  2.909 20.016 3.125 20.376 ;
     RECT  2.909 25.68 3.125 26.088 ;
     RECT  2.801 62.544 3.125 62.568 ;
     RECT  2.704 106.176 3.125 108.216 ;
     RECT  2.873 110.544 3.125 110.568 ;
     RECT  3.089 47.856 3.197 47.88 ;
     RECT  3.089 50.592 3.197 50.616 ;
     RECT  2.704 21.504 3.233 22.2 ;
     RECT  3.017 87.264 3.233 91.272 ;
     RECT  3.125 106.176 3.233 106.488 ;
     RECT  2.909 48.912 3.269 48.984 ;
     RECT  3.089 60.336 3.269 60.6 ;
     RECT  3.125 107.568 3.269 108.216 ;
     RECT  2.765 31.776 3.305 31.944 ;
     RECT  3.269 60.576 3.341 60.6 ;
     RECT  2.704 63.792 3.395 64.44 ;
     RECT  2.873 68.928 3.395 69.768 ;
     RECT  3.233 87.264 3.413 87.672 ;
     RECT  2.981 75.216 3.443 76.44 ;
     RECT  3.233 88.848 3.449 89.304 ;
     RECT  2.801 7.392 3.491 7.416 ;
     RECT  3.233 21.888 3.539 22.2 ;
     RECT  3.125 11.424 3.552 11.976 ;
     RECT  3.552 11.952 3.565 11.976 ;
     RECT  2.704 27.312 3.635 27.336 ;
     RECT  2.873 97.152 3.635 97.176 ;
     RECT  2.873 112.848 3.635 113.448 ;
     RECT  3.125 25.68 3.665 25.704 ;
     RECT  3.269 107.712 3.693 108.216 ;
     RECT  3.125 13.056 3.731 14.04 ;
     RECT  3.233 91.248 3.731 91.272 ;
     RECT  2.765 93.744 3.731 93.768 ;
     RECT  3.017 100.656 3.731 101.592 ;
     RECT  3.089 28.512 3.733 28.536 ;
     RECT  2.981 65.52 3.733 66.024 ;
     RECT  3.125 20.016 3.737 20.04 ;
     RECT  2.765 83.76 3.74 85.656 ;
     RECT  2.801 34.176 3.769 38.424 ;
     RECT  2.704 77.52 3.769 77.544 ;
     RECT  3.781 80.928 3.881 80.952 ;
     RECT  3.74 83.424 3.913 85.656 ;
     RECT  3.413 87.264 3.913 87.288 ;
     RECT  3.733 28.512 3.917 29.4 ;
     RECT  3.769 34.08 3.925 38.424 ;
     RECT  2.873 111.744 3.925 111.768 ;
     RECT  2.765 58.08 3.941 58.104 ;
     RECT  2.801 33.024 3.949 33.048 ;
     RECT  3.925 34.08 3.949 38.712 ;
     RECT  3.395 69.504 3.949 69.768 ;
     RECT  2.704 72.144 3.949 72.792 ;
     RECT  2.704 74.064 3.949 74.088 ;
     RECT  3.685 92.64 3.953 92.664 ;
     RECT  3.733 65.52 3.971 66.216 ;
     RECT  3.693 108.192 3.971 108.216 ;
     RECT  3.925 110.88 3.971 111.768 ;
     RECT  3.443 76.368 3.98 76.44 ;
     RECT  3.769 77.52 3.98 78.024 ;
     RECT  3.949 81.984 3.98 82.008 ;
     RECT  2.873 99.168 3.985 99.192 ;
     RECT  3.805 100.224 3.985 100.248 ;
     RECT  3.125 15.744 3.989 16.824 ;
     RECT  3.913 83.424 4.019 87.288 ;
     RECT  3.941 58.08 4.021 58.152 ;
     RECT  3.98 76.368 4.021 78.024 ;
     RECT  3.98 81.744 4.021 82.008 ;
     RECT  4.021 76.368 4.025 78.504 ;
     RECT  3.989 16.8 4.057 16.824 ;
     RECT  2.801 18.192 4.057 18.216 ;
     RECT  3.949 69.504 4.057 70.296 ;
     RECT  3.949 72.144 4.057 74.088 ;
     RECT  3.443 75.216 4.057 75.336 ;
     RECT  3.98 52.032 4.067 52.056 ;
     RECT  4.025 76.416 4.067 78.504 ;
     RECT  4.021 81.744 4.067 82.296 ;
     RECT  4.057 16.8 4.069 18.216 ;
     RECT  4.069 16.8 4.097 18.984 ;
     RECT  3.233 106.176 4.097 106.2 ;
     RECT  3.269 48.912 4.117 48.936 ;
     RECT  3.769 22.752 4.124 22.776 ;
     RECT  4.097 17.616 4.141 18.984 ;
     RECT  4.124 22.752 4.165 23.544 ;
     RECT  3.913 114.816 4.172 114.84 ;
     RECT  3.913 116.4 4.172 116.424 ;
     RECT  3.949 33.024 4.201 38.712 ;
     RECT  3.841 97.728 4.201 97.848 ;
     RECT  3.985 99.168 4.201 100.248 ;
     RECT  2.909 41.088 4.213 41.64 ;
     RECT  3.805 42.768 4.213 42.792 ;
     RECT  2.704 44.448 4.213 45.048 ;
     RECT  4.141 17.904 4.237 18.984 ;
     RECT  4.213 44.448 4.237 45.72 ;
     RECT  2.765 54.096 4.273 54.12 ;
     RECT  2.765 59.232 4.273 59.256 ;
     RECT  4.201 33.024 4.345 38.952 ;
     RECT  4.213 40.176 4.345 41.64 ;
     RECT  4.237 44.448 4.345 46.392 ;
     RECT  4.273 53.808 4.345 54.12 ;
     RECT  3.985 109.392 4.345 109.416 ;
     RECT  3.971 110.88 4.345 111.48 ;
     RECT  4.345 33.024 4.417 41.64 ;
     RECT  4.412 26.736 4.453 26.76 ;
     RECT  4.273 59.232 4.453 59.832 ;
     RECT  3.971 65.712 4.453 66.216 ;
     RECT  2.909 67.296 4.453 67.32 ;
     RECT  3.449 88.848 4.453 88.92 ;
     RECT  3.917 29.376 4.46 29.4 ;
     RECT  3.731 101.568 4.489 101.592 ;
     RECT  3.305 31.92 4.501 31.944 ;
     RECT  4.417 32.976 4.501 41.64 ;
     RECT  4.453 88.848 4.501 89.448 ;
     RECT  3.769 95.088 4.508 95.112 ;
     RECT  4.172 116.112 4.517 116.424 ;
     RECT  3.731 13.056 4.525 13.416 ;
     RECT  3.989 15.744 4.525 15.768 ;
     RECT  3.089 30.432 4.525 30.504 ;
     RECT  4.501 31.92 4.525 41.64 ;
     RECT  4.345 44.448 4.525 46.728 ;
     RECT  4.057 72.144 4.549 75.336 ;
     RECT  4.019 83.76 4.549 87.288 ;
     RECT  4.501 88.608 4.549 89.448 ;
     RECT  4.508 93.888 4.549 95.112 ;
     RECT  4.345 104.784 4.549 104.808 ;
     RECT  4.172 114.432 4.549 114.84 ;
     RECT  4.517 116.112 4.549 116.76 ;
     RECT  4.021 57.84 4.561 58.152 ;
     RECT  4.453 59.232 4.561 60.024 ;
     RECT  3.395 64.416 4.561 64.44 ;
     RECT  4.549 83.76 4.561 89.976 ;
     RECT  4.213 42.72 4.597 42.792 ;
     RECT  4.525 44.448 4.597 47.304 ;
     RECT  4.549 93.888 4.597 95.4 ;
     RECT  4.549 96.72 4.597 96.744 ;
     RECT  4.021 50.736 4.645 50.76 ;
     RECT  4.345 52.464 4.645 54.12 ;
     RECT  4.057 69.504 4.652 70.584 ;
     RECT  4.525 68.352 4.693 68.376 ;
     RECT  4.652 69.504 4.693 70.824 ;
     RECT  4.067 81.888 4.777 82.296 ;
     RECT  4.525 30.432 4.789 41.64 ;
     RECT  4.597 42.72 4.789 47.304 ;
     RECT  4.453 65.712 4.885 67.32 ;
     RECT  4.693 68.352 4.885 70.824 ;
     RECT  4.067 78.096 4.885 78.504 ;
     RECT  2.837 79.728 4.885 79.752 ;
     RECT  4.549 104.784 4.885 105.096 ;
     RECT  4.645 50.112 4.981 50.76 ;
     RECT  4.705 62.736 4.981 62.76 ;
     RECT  4.561 64.368 4.981 64.44 ;
     RECT  4.597 93.888 5.029 96.744 ;
     RECT  4.165 22.752 5.065 24.36 ;
     RECT  5.029 93.312 5.065 96.744 ;
     RECT  4.345 109.392 5.101 111.48 ;
     RECT  4.417 5.04 5.108 5.688 ;
     RECT  4.777 10.704 5.108 10.728 ;
     RECT  4.525 12.528 5.108 13.416 ;
     RECT  4.525 15.36 5.108 15.768 ;
     RECT  4.237 17.904 5.108 19.368 ;
     RECT  5.065 22.752 5.108 25.224 ;
     RECT  4.453 26.208 5.108 26.76 ;
     RECT  4.453 27.936 5.108 27.96 ;
     RECT  4.46 29.376 5.108 29.448 ;
     RECT  4.789 30.432 5.108 47.304 ;
     RECT  4.117 48.432 5.108 48.936 ;
     RECT  4.981 50.112 5.108 50.856 ;
     RECT  4.645 52.464 5.108 54.168 ;
     RECT  4.525 55.248 5.108 55.272 ;
     RECT  4.316 56.736 5.108 56.76 ;
     RECT  4.561 57.84 5.108 60.024 ;
     RECT  4.561 61.104 5.108 61.128 ;
     RECT  4.981 62.736 5.108 64.44 ;
     RECT  4.885 65.712 5.108 70.824 ;
     RECT  4.549 71.808 5.108 75.336 ;
     RECT  4.067 76.416 5.108 76.44 ;
     RECT  4.885 78.096 5.108 79.752 ;
     RECT  4.981 80.784 5.108 80.808 ;
     RECT  4.777 81.888 5.108 82.728 ;
     RECT  4.561 83.76 5.108 90.264 ;
     RECT  5.065 92.4 5.108 96.744 ;
     RECT  4.201 97.728 5.108 100.248 ;
     RECT  4.489 101.568 5.108 101.88 ;
     RECT  2.909 103.728 5.108 103.752 ;
     RECT  4.885 104.784 5.108 105.96 ;
     RECT  4.549 107.136 5.108 107.16 ;
     RECT  4.489 108.288 5.108 108.312 ;
     RECT  5.101 109.392 5.108 112.44 ;
     RECT  3.635 113.424 5.108 113.448 ;
     RECT  4.549 114.432 5.108 116.76 ;
     RECT  5.108 2.148 5.212 118.812 ;
     RECT  5.212 2.418 5.404 118.542 ;
     RECT  5.404 109.968 5.465 110.088 ;
     RECT  5.404 88.416 5.501 88.92 ;
     RECT  5.404 59.184 5.555 63.816 ;
     RECT  5.404 90 5.555 90.024 ;
     RECT  5.404 91.152 5.555 95.496 ;
     RECT  5.404 96.912 5.603 103.224 ;
     RECT  5.404 112.08 5.603 114.552 ;
     RECT  5.404 28.416 5.609 35.976 ;
     RECT  5.501 88.752 5.609 88.92 ;
     RECT  5.603 112.08 5.644 113.448 ;
     RECT  5.404 5.04 5.645 5.592 ;
     RECT  5.404 12.528 5.645 13.848 ;
     RECT  5.404 53.232 5.645 53.832 ;
     RECT  5.404 19.248 5.651 19.944 ;
     RECT  5.555 92.016 5.651 95.496 ;
     RECT  5.603 96.912 5.651 98.328 ;
     RECT  5.404 22.752 5.692 25.992 ;
     RECT  5.651 94.272 5.692 95.16 ;
     RECT  5.404 37.056 5.699 42.024 ;
     RECT  5.404 105.936 5.699 107.784 ;
     RECT  5.404 77.952 5.747 78.888 ;
     RECT  5.404 79.968 5.747 87.288 ;
     RECT  5.404 8.496 5.788 8.904 ;
     RECT  5.404 10.272 5.788 10.824 ;
     RECT  5.645 13.008 5.795 13.848 ;
     RECT  5.404 65.52 5.843 66.312 ;
     RECT  5.465 109.968 5.843 109.992 ;
     RECT  5.699 106.032 5.861 106.584 ;
     RECT  5.404 47.856 5.891 47.88 ;
     RECT  5.404 49.488 5.891 51.048 ;
     RECT  5.699 39.024 5.897 42.024 ;
     RECT  5.699 37.056 5.933 37.896 ;
     RECT  5.404 76.896 5.933 76.92 ;
     RECT  5.747 80.64 5.933 87.288 ;
     RECT  5.861 106.032 5.933 106.392 ;
     RECT  5.609 28.416 5.987 30.504 ;
     RECT  5.795 13.008 6.005 13.032 ;
     RECT  5.933 80.64 6.005 87.096 ;
     RECT  5.933 106.032 6.005 106.104 ;
     RECT  5.404 57.312 6.035 57.576 ;
     RECT  6.005 81.888 6.035 87.096 ;
     RECT  5.651 96.912 6.035 97.704 ;
     RECT  5.933 37.056 6.041 37.08 ;
     RECT  5.404 44.976 6.041 45.48 ;
     RECT  5.645 53.232 6.041 53.256 ;
     RECT  5.555 60.528 6.076 63.816 ;
     RECT  5.404 68.736 6.083 70.008 ;
     RECT  5.651 92.016 6.083 92.952 ;
     RECT  5.555 59.184 6.113 59.208 ;
     RECT  5.788 10.704 6.131 10.824 ;
     RECT  5.603 99.696 6.149 102.696 ;
     RECT  5.404 71.472 6.179 75.624 ;
     RECT  6.005 106.032 6.179 106.056 ;
     RECT  5.645 5.568 6.185 5.592 ;
     RECT  6.076 61.008 6.185 63.816 ;
     RECT  6.035 82.704 6.185 87.096 ;
     RECT  6.179 75.36 6.22 75.624 ;
     RECT  6.179 71.472 6.221 73.896 ;
     RECT  5.692 24.528 6.227 25.656 ;
     RECT  6.035 57.408 6.257 57.576 ;
     RECT  6.185 61.008 6.257 63.528 ;
     RECT  6.149 100.272 6.275 102.696 ;
     RECT  5.644 112.08 6.275 112.104 ;
     RECT  5.404 116.304 6.275 116.328 ;
     RECT  5.897 39.024 6.293 40.728 ;
     RECT  6.257 61.008 6.293 63.24 ;
     RECT  6.083 92.016 6.293 92.04 ;
     RECT  6.185 83.184 6.323 87.096 ;
     RECT  5.404 17.472 6.329 18.024 ;
     RECT  5.692 22.752 6.329 23.352 ;
     RECT  6.221 72.816 6.329 73.896 ;
     RECT  6.323 86.64 6.329 87.096 ;
     RECT  6.035 96.912 6.337 96.936 ;
     RECT  6.275 100.704 6.365 102.696 ;
     RECT  5.644 113.424 6.365 113.448 ;
     RECT  5.603 114.528 6.365 114.552 ;
     RECT  6.227 25.632 6.371 25.656 ;
     RECT  5.987 28.416 6.371 29.208 ;
     RECT  5.987 30.24 6.401 30.504 ;
     RECT  5.404 104.688 6.401 104.904 ;
     RECT  5.897 41.856 6.428 42.024 ;
     RECT  5.404 67.68 6.469 67.752 ;
     RECT  5.699 107.76 6.505 107.784 ;
     RECT  6.227 24.528 6.509 24.552 ;
     RECT  6.428 37.008 6.515 37.032 ;
     RECT  6.293 39.984 6.515 40.728 ;
     RECT  5.747 77.952 6.517 78.36 ;
     RECT  5.404 15.168 6.541 15.192 ;
     RECT  6.505 16.224 6.541 16.248 ;
     RECT  6.041 45.456 6.541 45.48 ;
     RECT  5.788 8.496 6.563 8.616 ;
     RECT  6.469 9.696 6.563 9.72 ;
     RECT  6.401 30.336 6.563 30.504 ;
     RECT  6.22 75.36 6.563 75.384 ;
     RECT  6.541 15.168 6.577 16.248 ;
     RECT  6.365 102 6.577 102.696 ;
     RECT  5.692 95.136 6.617 95.16 ;
     RECT  6.083 69.408 6.649 70.008 ;
     RECT  6.221 71.472 6.649 71.736 ;
     RECT  5.891 49.488 6.685 50.76 ;
     RECT  5.651 19.248 6.721 19.368 ;
     RECT  6.541 47.712 6.721 47.736 ;
     RECT  6.323 83.184 6.755 85.416 ;
     RECT  6.577 102 6.755 103.512 ;
     RECT  6.685 49.44 6.793 50.76 ;
     RECT  6.005 80.64 6.793 80.664 ;
     RECT  6.329 72.816 6.797 73.512 ;
     RECT  6.755 83.184 6.797 84.36 ;
     RECT  6.257 57.552 6.805 57.576 ;
     RECT  6.469 58.656 6.805 58.68 ;
     RECT  6.721 46.752 6.833 47.736 ;
     RECT  6.829 95.664 6.853 95.688 ;
     RECT  6.613 98.304 6.853 98.328 ;
     RECT  6.613 111.168 6.853 111.192 ;
     RECT  6.833 46.896 6.873 47.736 ;
     RECT  6.793 49.008 6.873 50.76 ;
     RECT  6.721 19.248 6.901 19.416 ;
     RECT  6.517 77.28 6.908 78.36 ;
     RECT  5.843 65.616 7.073 66.312 ;
     RECT  6.505 107.76 7.073 108.072 ;
     RECT  6.469 67.68 7.093 68.376 ;
     RECT  6.649 69.408 7.093 71.736 ;
     RECT  7.073 107.76 7.093 108.888 ;
     RECT  6.428 41.856 7.109 42.168 ;
     RECT  5.404 21.36 7.117 21.528 ;
     RECT  6.563 30.48 7.117 30.504 ;
     RECT  5.609 31.776 7.117 35.976 ;
     RECT  7.073 65.52 7.117 66.312 ;
     RECT  7.093 107.424 7.117 108.888 ;
     RECT  7.117 21.072 7.141 21.528 ;
     RECT  6.515 40.704 7.141 40.728 ;
     RECT  7.109 41.856 7.141 42.792 ;
     RECT  6.401 104.736 7.141 104.904 ;
     RECT  7.117 107.184 7.141 108.888 ;
     RECT  6.505 26.688 7.292 26.712 ;
     RECT  7.117 30.48 7.333 35.976 ;
     RECT  7.045 13.056 7.429 13.08 ;
     RECT  6.365 100.704 7.621 100.728 ;
     RECT  7.045 53.52 7.628 53.544 ;
     RECT  6.873 46.896 7.669 50.76 ;
     RECT  7.004 51.888 7.669 51.912 ;
     RECT  5.404 55.248 7.669 55.272 ;
     RECT  7.333 30.48 7.693 36.456 ;
     RECT  7.1 37.584 7.693 37.608 ;
     RECT  6.797 83.184 7.693 84.312 ;
     RECT  6.793 6.24 7.808 6.264 ;
     RECT  6.613 7.392 7.808 7.416 ;
     RECT  6.563 8.592 7.808 8.616 ;
     RECT  6.685 11.376 7.808 11.4 ;
     RECT  7.429 13.056 7.808 13.608 ;
     RECT  6.577 15.168 7.808 17.352 ;
     RECT  6.901 18.672 7.808 19.416 ;
     RECT  7.141 21.072 7.808 21.672 ;
     RECT  7.225 23.712 7.808 24.264 ;
     RECT  7.292 26.688 7.808 27.24 ;
     RECT  7.765 28.464 7.808 28.488 ;
     RECT  7.693 30.48 7.808 37.608 ;
     RECT  7.141 40.704 7.808 42.792 ;
     RECT  7.388 44.4 7.808 44.424 ;
     RECT  6.541 45.456 7.808 45.576 ;
     RECT  7.669 46.896 7.808 51.912 ;
     RECT  7.628 52.896 7.808 53.544 ;
     RECT  7.669 55.248 7.808 55.992 ;
     RECT  6.805 57.552 7.808 58.68 ;
     RECT  7.436 59.952 7.808 59.976 ;
     RECT  6.293 61.584 7.808 63.24 ;
     RECT  7.117 64.56 7.808 66.312 ;
     RECT  7.093 67.488 7.808 71.736 ;
     RECT  6.797 72.816 7.808 72.984 ;
     RECT  7.628 74.256 7.808 74.28 ;
     RECT  6.908 77.28 7.808 79.224 ;
     RECT  6.793 80.352 7.808 80.664 ;
     RECT  7.693 82.704 7.808 84.312 ;
     RECT  6.755 85.392 7.808 85.416 ;
     RECT  6.329 86.976 7.808 87.096 ;
     RECT  5.609 88.896 7.808 88.92 ;
     RECT  7.153 90.576 7.808 90.6 ;
     RECT  7.189 92.352 7.808 92.376 ;
     RECT  7.225 94.608 7.808 94.632 ;
     RECT  6.853 95.664 7.808 96.504 ;
     RECT  6.853 98.304 7.808 99.144 ;
     RECT  7.621 100.272 7.808 100.728 ;
     RECT  6.755 102.624 7.808 103.512 ;
     RECT  7.141 104.736 7.808 105.816 ;
     RECT  7.141 106.8 7.808 108.888 ;
     RECT  6.853 110.88 7.808 111.192 ;
     RECT  6.853 112.896 7.808 112.92 ;
     RECT  7.669 115.152 7.808 115.176 ;
     RECT  7.808 2.148 7.912 118.812 ;
     RECT  7.912 2.418 8.104 118.542 ;
     RECT  8.104 55.968 8.165 56.904 ;
     RECT  8.104 87.072 8.201 87.144 ;
     RECT  8.104 7.344 8.243 7.368 ;
     RECT  8.104 17.088 8.243 17.112 ;
     RECT  8.104 18.192 8.243 18.216 ;
     RECT  8.104 25.2 8.243 25.224 ;
     RECT  8.104 26.64 8.243 26.664 ;
     RECT  8.104 28.128 8.243 28.488 ;
     RECT  8.104 36.816 8.243 36.84 ;
     RECT  8.104 38.16 8.243 39.336 ;
     RECT  8.165 56.88 8.243 56.904 ;
     RECT  8.104 58.128 8.243 58.728 ;
     RECT  8.201 87.12 8.243 87.144 ;
     RECT  8.104 91.2 8.243 91.464 ;
     RECT  8.104 99.168 8.245 99.192 ;
     RECT  8.243 58.704 8.273 58.728 ;
     RECT  8.104 98.016 8.273 98.04 ;
     RECT  8.104 5.856 8.284 5.88 ;
     RECT  8.104 85.392 8.284 85.416 ;
     RECT  8.104 42.336 8.291 42.36 ;
     RECT  8.104 49.296 8.291 49.32 ;
     RECT  8.243 91.44 8.291 91.464 ;
     RECT  8.104 96.96 8.291 96.984 ;
     RECT  8.104 33.264 8.309 33.384 ;
     RECT  8.243 38.784 8.309 39.336 ;
     RECT  8.309 39.312 8.332 39.336 ;
     RECT  8.104 10.992 8.339 11.016 ;
     RECT  8.104 12.336 8.339 12.36 ;
     RECT  8.104 15.072 8.339 15.096 ;
     RECT  8.104 77.424 8.339 77.448 ;
     RECT  8.104 78.624 8.339 78.648 ;
     RECT  8.243 28.128 8.381 28.152 ;
     RECT  8.104 82.704 8.483 82.728 ;
     RECT  8.309 33.36 8.489 33.384 ;
     RECT  8.104 69.552 8.489 69.576 ;
     RECT  8.104 80.352 8.489 80.376 ;
     RECT  8.104 81.36 8.524 81.384 ;
     RECT  8.104 75.168 8.669 75.192 ;
     RECT  9.421 15.84 10.508 15.864 ;
     RECT  8.104 21.504 10.508 21.528 ;
     RECT  8.104 40.704 10.508 40.728 ;
     RECT  8.104 45.456 10.508 45.48 ;
     RECT  8.104 62.16 10.508 62.184 ;
     RECT  10.508 2.148 10.612 118.812 ;
     RECT  10.612 2.418 10.804 118.542 ;
     RECT  10.804 21.504 13.208 21.528 ;
     RECT  10.804 40.704 13.208 40.728 ;
     RECT  10.804 45.456 13.208 45.48 ;
     RECT  10.804 62.16 13.208 62.184 ;
     RECT  13.208 2.148 13.312 118.812 ;
     RECT  13.312 2.418 13.504 118.542 ;
     RECT  13.504 40.704 14.821 40.728 ;
     RECT  14.821 40.608 14.861 40.728 ;
     RECT  13.504 21.504 15.908 21.528 ;
     RECT  14.861 40.608 15.908 40.632 ;
     RECT  13.504 45.456 15.908 45.48 ;
     RECT  13.504 62.16 15.908 62.184 ;
     RECT  15.908 2.148 16.012 118.812 ;
     RECT  16.012 2.418 16.204 118.542 ;
     RECT  5.893 120.816 18.209 120.84 ;
     RECT  16.204 21.504 18.608 21.528 ;
     RECT  16.204 40.608 18.608 40.632 ;
     RECT  16.204 45.456 18.608 45.48 ;
     RECT  16.204 62.16 18.608 62.184 ;
     RECT  18.608 2.148 18.712 118.812 ;
     RECT  18.712 2.418 18.904 118.542 ;
     RECT  18.904 21.504 21.308 21.528 ;
     RECT  18.904 40.608 21.308 40.632 ;
     RECT  18.904 45.456 21.308 45.48 ;
     RECT  18.904 62.16 21.308 62.184 ;
     RECT  21.308 2.148 21.412 118.812 ;
     RECT  21.412 2.418 21.604 118.542 ;
     RECT  21.604 40.608 21.701 40.728 ;
     RECT  21.701 40.704 22.813 40.728 ;
     RECT  22.813 40.608 22.853 40.728 ;
     RECT  21.604 21.504 24.008 21.528 ;
     RECT  22.853 40.608 24.008 40.632 ;
     RECT  21.604 45.456 24.008 45.48 ;
     RECT  21.604 62.16 24.008 62.184 ;
     RECT  24.008 2.148 24.112 118.812 ;
     RECT  24.112 2.418 24.304 118.542 ;
     RECT  24.304 21.504 26.708 21.528 ;
     RECT  24.304 40.608 26.708 40.632 ;
     RECT  24.304 45.456 26.708 45.48 ;
     RECT  24.304 62.16 26.708 62.184 ;
     RECT  26.708 2.148 26.812 118.812 ;
     RECT  26.812 2.418 27.004 118.542 ;
     RECT  27.004 21.504 29.408 21.528 ;
     RECT  27.004 40.608 29.408 40.632 ;
     RECT  27.004 45.456 29.408 45.48 ;
     RECT  27.004 62.16 29.408 62.184 ;
     RECT  29.408 2.148 29.512 118.812 ;
     RECT  29.512 2.418 29.704 118.542 ;
     RECT  29.704 40.608 29.801 40.728 ;
     RECT  30.841 58.704 30.953 58.728 ;
     RECT  30.769 43.296 30.989 43.32 ;
     RECT  31.957 25.008 32.065 25.032 ;
     RECT  31.957 91.152 32.101 91.608 ;
     RECT  29.704 21.504 32.108 21.528 ;
     RECT  32.065 24.912 32.108 25.032 ;
     RECT  29.801 40.704 32.108 40.728 ;
     RECT  32.065 42.72 32.108 42.744 ;
     RECT  29.704 45.456 32.108 45.48 ;
     RECT  32.101 51.936 32.108 51.96 ;
     RECT  29.704 62.16 32.108 62.184 ;
     RECT  31.849 79.2 32.108 79.224 ;
     RECT  31.849 83.232 32.108 83.256 ;
     RECT  31.957 89.808 32.108 89.832 ;
     RECT  32.101 91.056 32.108 91.608 ;
     RECT  32.108 2.148 32.212 118.812 ;
     RECT  32.212 2.418 32.404 118.542 ;
     RECT  32.404 89.28 32.465 91.176 ;
     RECT  32.404 51.936 32.789 51.96 ;
     RECT  32.404 107.328 32.789 107.352 ;
     RECT  32.404 108.336 32.789 108.36 ;
     RECT  32.404 31.104 33.185 31.176 ;
     RECT  32.404 42.72 33.329 42.744 ;
     RECT  32.404 74.64 33.397 75.384 ;
     RECT  32.404 77.232 33.433 77.304 ;
     RECT  32.404 62.16 33.469 62.952 ;
     RECT  32.404 17.184 33.473 17.88 ;
     RECT  32.404 79.152 33.505 79.8 ;
     RECT  32.404 9.216 33.545 9.24 ;
     RECT  32.404 83.232 33.581 83.256 ;
     RECT  32.404 21.504 33.653 21.528 ;
     RECT  33.185 31.104 33.653 31.128 ;
     RECT  33.469 62.16 33.653 63.192 ;
     RECT  33.473 17.184 33.725 17.208 ;
     RECT  33.433 76.416 33.725 77.304 ;
     RECT  32.465 89.28 33.725 91.08 ;
     RECT  33.725 89.808 33.797 91.08 ;
     RECT  33.577 116.16 33.973 116.184 ;
     RECT  32.404 49.344 34.085 49.368 ;
     RECT  33.577 70.032 34.117 70.056 ;
     RECT  33.433 15.312 34.189 15.336 ;
     RECT  32.404 24.912 34.189 25.704 ;
     RECT  32.404 28.992 34.189 29.016 ;
     RECT  32.404 32.448 34.189 32.472 ;
     RECT  32.404 37.584 34.189 37.608 ;
     RECT  32.404 38.64 34.189 38.664 ;
     RECT  33.433 42 34.189 42.024 ;
     RECT  33.973 43.296 34.189 43.32 ;
     RECT  32.404 45.936 34.189 46.488 ;
     RECT  33.973 47.712 34.189 47.736 ;
     RECT  32.404 60.288 34.189 60.312 ;
     RECT  33.653 62.928 34.189 63.192 ;
     RECT  32.404 68.112 34.189 68.376 ;
     RECT  34.117 70.032 34.189 70.344 ;
     RECT  33.397 74.304 34.189 75.384 ;
     RECT  33.725 76.848 34.189 77.304 ;
     RECT  33.505 78.672 34.189 79.8 ;
     RECT  33.797 90.048 34.189 91.08 ;
     RECT  33.541 93.936 34.189 93.96 ;
     RECT  32.404 99.456 34.189 99.48 ;
     RECT  33.793 101.424 34.189 101.448 ;
     RECT  33.865 106.656 34.189 106.68 ;
     RECT  33.793 110.448 34.189 110.472 ;
     RECT  34.189 9.456 34.225 13.224 ;
     RECT  34.189 22.32 34.225 23.16 ;
     RECT  34.189 24.576 34.225 26.904 ;
     RECT  34.189 34.224 34.225 35.208 ;
     RECT  34.189 50.304 34.225 51.336 ;
     RECT  34.189 81.072 34.225 81.096 ;
     RECT  34.189 82.08 34.225 82.728 ;
     RECT  34.189 90.048 34.225 91.224 ;
     RECT  34.189 106.656 34.225 112.056 ;
     RECT  34.225 90.048 34.261 91.368 ;
     RECT  33.685 5.712 34.297 5.736 ;
     RECT  34.297 5.568 34.333 5.736 ;
     RECT  33.973 115.584 34.333 116.184 ;
     RECT  34.333 115.44 34.369 116.184 ;
     RECT  34.333 5.568 34.405 6.216 ;
     RECT  34.405 4.752 34.441 6.216 ;
     RECT  34.189 113.136 34.441 114.168 ;
     RECT  34.225 9.456 34.657 13.368 ;
     RECT  34.189 14.832 34.657 15.336 ;
     RECT  34.189 18.576 34.693 18.936 ;
     RECT  34.225 22.32 34.693 26.904 ;
     RECT  34.189 62.928 34.693 64.488 ;
     RECT  34.657 9.456 34.729 15.336 ;
     RECT  34.693 17.904 34.729 18.936 ;
     RECT  34.189 20.064 34.729 20.088 ;
     RECT  34.693 21.168 34.729 26.904 ;
     RECT  34.189 28.992 34.729 29.832 ;
     RECT  34.189 32.4 34.729 33.24 ;
     RECT  34.225 34.224 34.729 35.544 ;
     RECT  34.189 41.184 34.729 42.024 ;
     RECT  34.189 43.296 34.729 44.472 ;
     RECT  34.189 45.6 34.729 49.224 ;
     RECT  34.225 50.304 34.729 51.48 ;
     RECT  34.189 53.232 34.729 54.264 ;
     RECT  34.189 58.8 34.729 58.824 ;
     RECT  34.189 59.904 34.729 60.744 ;
     RECT  34.189 65.616 34.729 68.376 ;
     RECT  34.189 72.48 34.729 72.504 ;
     RECT  34.189 74.256 34.729 75.576 ;
     RECT  34.189 76.848 34.729 79.8 ;
     RECT  34.225 81.072 34.729 82.728 ;
     RECT  34.189 83.856 34.729 85.512 ;
     RECT  34.189 96.384 34.729 96.408 ;
     RECT  34.189 97.68 34.729 98.184 ;
     RECT  34.189 99.312 34.729 105.048 ;
     RECT  34.225 106.464 34.729 112.056 ;
     RECT  34.441 113.136 34.729 114.456 ;
     RECT  34.441 4.752 34.765 6.408 ;
     RECT  33.685 7.68 34.765 7.704 ;
     RECT  34.729 8.832 34.765 15.336 ;
     RECT  34.729 16.944 34.765 20.088 ;
     RECT  34.729 21.168 34.765 29.976 ;
     RECT  34.729 31.776 34.765 35.544 ;
     RECT  34.729 41.184 34.765 49.224 ;
     RECT  34.693 62.688 34.765 64.488 ;
     RECT  34.729 65.616 34.765 68.424 ;
     RECT  34.189 70.032 34.765 70.872 ;
     RECT  34.729 71.952 34.765 72.792 ;
     RECT  34.729 74.256 34.765 79.8 ;
     RECT  34.729 81.072 34.765 85.512 ;
     RECT  34.189 87.936 34.765 87.96 ;
     RECT  34.261 90.048 34.765 91.704 ;
     RECT  34.189 92.976 34.765 95.256 ;
     RECT  34.729 96.384 34.765 98.184 ;
     RECT  34.729 106.464 34.765 114.456 ;
     RECT  34.369 115.44 34.765 116.424 ;
     RECT  34.765 87.936 34.801 88.104 ;
     RECT  34.765 62.688 34.805 69.048 ;
     RECT  34.729 50.304 35.305 54.264 ;
     RECT  34.189 55.344 35.305 57.816 ;
     RECT  34.765 106.464 35.305 116.424 ;
     RECT  34.765 4.752 35.341 15.336 ;
     RECT  34.765 16.608 35.341 29.976 ;
     RECT  34.765 31.104 35.341 35.544 ;
     RECT  34.189 36.624 35.341 39.432 ;
     RECT  34.765 40.56 35.341 49.224 ;
     RECT  35.305 50.304 35.341 57.816 ;
     RECT  34.729 58.8 35.341 60.744 ;
     RECT  34.805 62.784 35.341 69.048 ;
     RECT  34.765 70.032 35.341 72.984 ;
     RECT  34.765 74.256 35.341 85.656 ;
     RECT  34.765 86.64 35.341 86.664 ;
     RECT  34.801 87.936 35.341 88.44 ;
     RECT  34.765 89.568 35.341 91.704 ;
     RECT  34.765 92.976 35.341 98.184 ;
     RECT  34.729 99.312 35.341 105.192 ;
     RECT  35.305 106.176 35.341 116.424 ;
     RECT  35.341 4.416 35.377 29.976 ;
     RECT  35.341 31.104 35.377 61.416 ;
     RECT  35.341 62.784 35.845 85.656 ;
     RECT  35.341 86.64 35.845 91.848 ;
     RECT  35.341 92.976 35.845 116.424 ;
     RECT  35.845 62.784 35.881 91.848 ;
     RECT  35.845 92.976 35.881 116.616 ;
     RECT  35.377 4.416 35.917 61.416 ;
     RECT  35.881 62.544 35.917 116.616 ;
     RECT  35.917 4.416 36.54 116.616 ;
     RECT  36.54 7.104 36.569 7.128 ;
    LAYER M5 ;
     RECT  2.4 2.137 2.52 2.151 ;
     RECT  5.1 2.137 5.22 2.151 ;
     RECT  7.8 2.137 7.92 2.151 ;
     RECT  10.5 2.137 10.62 2.151 ;
     RECT  13.2 2.137 13.32 2.151 ;
     RECT  15.9 2.137 16.02 2.151 ;
     RECT  18.6 2.137 18.72 2.151 ;
     RECT  21.3 2.137 21.42 2.151 ;
     RECT  24 2.137 24.12 2.151 ;
     RECT  26.7 2.137 26.82 2.151 ;
     RECT  29.4 2.137 29.52 2.151 ;
     RECT  32.1 2.137 32.22 2.151 ;
     RECT  7.8 2.151 8.112 5.845 ;
     RECT  2.4 2.151 2.712 7.381 ;
     RECT  5.1 2.151 5.412 8.869 ;
     RECT  6.528 8.485 6.552 8.869 ;
     RECT  5.1 8.869 6.552 9.731 ;
     RECT  5.1 9.731 5.736 10.693 ;
     RECT  7.8 5.845 8.232 10.981 ;
     RECT  2.4 7.381 3.48 11.941 ;
     RECT  2.4 11.941 3.528 13.045 ;
     RECT  7.8 10.981 8.328 13.045 ;
     RECT  7.44 13.045 8.328 15.107 ;
     RECT  2.4 13.045 3.72 15.733 ;
     RECT  5.1 10.693 6.12 16.213 ;
     RECT  7.44 15.107 8.232 16.213 ;
     RECT  2.4 15.733 4.008 17.605 ;
     RECT  5.1 16.213 8.232 18.707 ;
     RECT  2.4 17.605 4.104 18.995 ;
     RECT  5.1 18.707 6.216 21.061 ;
     RECT  7.8 18.707 8.232 21.061 ;
     RECT  5.1 21.061 8.232 21.683 ;
     RECT  2.4 18.995 3.528 22.741 ;
     RECT  5.1 21.683 6.216 22.741 ;
     RECT  2.4 22.741 6.216 23.317 ;
     RECT  7.8 21.683 8.232 23.701 ;
     RECT  2.4 23.317 6.312 24.371 ;
     RECT  5.1 24.371 6.312 24.563 ;
     RECT  7.344 23.701 8.232 25.235 ;
     RECT  5.1 24.563 6.216 25.621 ;
     RECT  5.1 25.621 6.36 26.197 ;
     RECT  7.344 25.235 8.112 26.629 ;
     RECT  2.4 24.371 3.48 27.301 ;
     RECT  4.464 26.197 6.36 27.301 ;
     RECT  2.4 27.301 6.36 27.971 ;
     RECT  7.344 26.629 8.232 28.499 ;
     RECT  2.4 27.971 3.624 28.547 ;
     RECT  5.1 27.971 6.36 29.219 ;
     RECT  5.1 29.219 5.976 29.413 ;
     RECT  4.512 29.413 5.976 30.325 ;
     RECT  7.344 28.499 8.112 30.325 ;
     RECT  4.512 30.325 8.112 30.851 ;
     RECT  0.192 30.757 0.216 30.899 ;
     RECT  7.8 30.851 8.112 31.861 ;
     RECT  4.512 30.851 6.552 32.341 ;
     RECT  7.68 31.861 8.112 32.341 ;
     RECT  4.512 32.341 8.112 33.013 ;
     RECT  3.936 33.013 8.112 34.355 ;
     RECT  4.128 34.355 8.112 35.939 ;
     RECT  2.4 28.547 2.712 36.709 ;
     RECT  4.128 35.939 5.688 36.709 ;
     RECT  2.4 36.709 5.688 36.755 ;
     RECT  7.104 35.939 8.112 36.805 ;
     RECT  4.416 36.755 5.688 36.997 ;
     RECT  7.104 36.805 8.232 36.997 ;
     RECT  2.4 36.755 3.432 38.389 ;
     RECT  4.416 36.997 8.232 38.389 ;
     RECT  2.4 38.389 8.232 38.435 ;
     RECT  3.936 38.435 8.232 39.301 ;
     RECT  3.936 39.301 8.28 42.179 ;
     RECT  3.936 42.179 5.592 42.803 ;
     RECT  7.152 42.179 8.28 42.803 ;
     RECT  7.8 42.803 8.28 44.389 ;
     RECT  4.608 42.803 5.592 44.437 ;
     RECT  7.44 44.389 8.28 45.587 ;
     RECT  4.224 44.437 5.592 45.731 ;
     RECT  7.8 45.587 8.28 46.885 ;
     RECT  4.8 45.731 5.592 47.845 ;
     RECT  4.8 47.845 5.88 48.421 ;
     RECT  6.912 46.885 8.28 48.467 ;
     RECT  7.68 48.467 8.28 49.331 ;
     RECT  7.68 49.331 8.112 50.725 ;
     RECT  4.128 48.421 5.88 50.771 ;
     RECT  4.656 50.771 5.88 52.021 ;
     RECT  4.032 52.021 5.88 53.267 ;
     RECT  7.056 50.725 8.112 53.555 ;
     RECT  4.032 53.267 5.592 54.131 ;
     RECT  4.368 54.131 5.592 55.237 ;
     RECT  7.68 53.555 8.112 56.003 ;
     RECT  7.8 56.003 8.112 56.869 ;
     RECT  4.368 55.237 6.024 57.541 ;
     RECT  7.8 56.869 8.232 57.541 ;
     RECT  4.368 57.541 8.232 58.117 ;
     RECT  3.984 58.117 8.232 58.691 ;
     RECT  7.488 58.691 8.232 58.739 ;
     RECT  3.984 58.691 6.024 59.267 ;
     RECT  7.488 58.739 8.112 59.987 ;
     RECT  4.608 59.267 6.024 60.035 ;
     RECT  5.1 60.035 6.024 61.573 ;
     RECT  5.1 61.573 6.648 62.195 ;
     RECT  7.8 59.987 8.112 62.629 ;
     RECT  36.432 62.677 36.456 62.819 ;
     RECT  5.1 62.195 5.928 63.589 ;
     RECT  2.4 38.435 2.712 63.781 ;
     RECT  4.992 63.589 5.928 63.781 ;
     RECT  2.4 63.781 3.384 64.451 ;
     RECT  4.992 63.781 6.168 64.451 ;
     RECT  5.1 64.451 6.168 65.509 ;
     RECT  7.488 62.629 8.112 65.509 ;
     RECT  5.1 65.509 8.112 65.651 ;
     RECT  3.936 65.509 3.96 66.181 ;
     RECT  3.744 66.181 3.96 66.227 ;
     RECT  5.1 65.651 5.928 66.613 ;
     RECT  4.8 66.613 5.928 67.187 ;
     RECT  3.744 66.227 3.768 67.331 ;
     RECT  4.896 67.187 5.928 67.717 ;
     RECT  4.896 67.717 6.072 68.341 ;
     RECT  7.104 65.651 8.112 68.341 ;
     RECT  2.4 64.451 2.712 68.917 ;
     RECT  4.896 68.341 8.112 69.301 ;
     RECT  2.4 68.917 3.384 69.587 ;
     RECT  4.704 69.301 8.112 70.549 ;
     RECT  4.128 70.549 8.112 70.835 ;
     RECT  4.128 70.835 6.072 72.325 ;
     RECT  4.128 72.325 6.168 73.477 ;
     RECT  4.128 73.477 6.552 74.053 ;
     RECT  7.68 70.835 8.112 74.291 ;
     RECT  3.936 74.053 6.552 75.347 ;
     RECT  2.4 69.587 2.712 75.637 ;
     RECT  2.4 75.637 3.432 77.173 ;
     RECT  4.8 75.347 6.552 77.173 ;
     RECT  2.4 77.173 6.552 77.269 ;
     RECT  7.8 74.291 8.112 77.269 ;
     RECT  2.4 77.269 8.112 77.413 ;
     RECT  2.4 77.413 8.328 77.555 ;
     RECT  4.032 77.555 8.328 78.131 ;
     RECT  4.032 78.131 4.056 79.189 ;
     RECT  5.1 78.131 6.024 79.189 ;
     RECT  7.8 78.131 8.328 79.189 ;
     RECT  4.032 79.189 8.328 80.387 ;
     RECT  4.032 80.387 6.024 80.819 ;
     RECT  4.032 80.819 4.056 80.917 ;
     RECT  7.8 80.387 8.112 81.349 ;
     RECT  3.792 80.917 4.056 81.877 ;
     RECT  5.1 80.819 6.024 81.877 ;
     RECT  3.792 81.877 6.024 81.923 ;
     RECT  7.8 81.349 8.472 82.739 ;
     RECT  3.792 81.923 5.928 83.459 ;
     RECT  3.936 83.459 5.928 84.325 ;
     RECT  3.936 84.325 6.744 85.283 ;
     RECT  7.8 82.739 8.112 85.381 ;
     RECT  3.936 85.283 6.312 86.675 ;
     RECT  3.936 86.675 5.928 87.251 ;
     RECT  4.176 87.251 5.928 88.837 ;
     RECT  3.696 88.837 5.928 89.987 ;
     RECT  7.8 85.381 8.232 90.565 ;
     RECT  7.2 90.565 8.232 91.429 ;
     RECT  4.848 89.987 5.928 92.005 ;
     RECT  7.2 91.429 8.28 92.387 ;
     RECT  4.848 92.005 6.072 92.963 ;
     RECT  3.696 89.987 3.72 93.779 ;
     RECT  4.848 92.963 5.928 93.877 ;
     RECT  7.8 92.387 8.28 94.597 ;
     RECT  36.432 94.597 36.456 94.739 ;
     RECT  4.56 93.877 5.928 95.125 ;
     RECT  7.248 94.597 8.28 95.125 ;
     RECT  4.56 95.125 8.28 96.995 ;
     RECT  2.4 77.555 2.712 97.141 ;
     RECT  4.56 96.995 8.112 97.141 ;
     RECT  2.4 97.141 8.112 97.763 ;
     RECT  4.848 97.763 8.112 98.005 ;
     RECT  2.4 97.763 3.624 99.203 ;
     RECT  4.848 98.005 8.232 99.203 ;
     RECT  4.848 99.203 8.112 100.213 ;
     RECT  4.56 100.213 8.112 100.645 ;
     RECT  3.696 100.645 8.112 101.891 ;
     RECT  5.1 101.891 8.112 102.659 ;
     RECT  3.696 101.891 3.72 103.717 ;
     RECT  5.1 102.659 6.36 103.717 ;
     RECT  3.696 103.717 6.36 104.819 ;
     RECT  7.68 102.659 8.112 104.821 ;
     RECT  3.696 104.819 6.168 105.107 ;
     RECT  5.1 105.107 6.168 106.067 ;
     RECT  2.4 99.203 2.712 106.165 ;
     RECT  3.696 105.107 3.72 106.165 ;
     RECT  2.4 106.165 3.72 107.125 ;
     RECT  5.1 106.067 5.928 107.125 ;
     RECT  7.152 104.821 8.112 107.413 ;
     RECT  2.4 107.125 5.928 107.747 ;
     RECT  3.936 107.747 5.928 108.323 ;
     RECT  7.104 107.413 8.112 108.899 ;
     RECT  3.936 108.323 3.96 109.381 ;
     RECT  4.992 108.323 5.928 109.381 ;
     RECT  3.936 109.381 5.928 110.869 ;
     RECT  7.68 108.899 8.112 110.869 ;
     RECT  3.936 110.869 8.112 111.779 ;
     RECT  2.4 107.747 2.712 112.837 ;
     RECT  4.512 111.779 8.112 112.837 ;
     RECT  2.4 112.837 8.112 112.931 ;
     RECT  2.4 112.931 6.264 113.459 ;
     RECT  5.1 113.459 5.928 114.421 ;
     RECT  4.224 114.421 5.928 114.517 ;
     RECT  7.68 112.931 8.112 115.187 ;
     RECT  4.224 114.517 6.264 116.339 ;
     RECT  4.224 116.339 5.928 116.435 ;
     RECT  4.56 116.435 5.928 116.771 ;
     RECT  2.4 113.459 2.712 118.809 ;
     RECT  7.8 115.187 8.112 118.809 ;
     RECT  10.5 2.151 10.812 118.809 ;
     RECT  13.2 2.151 13.512 118.809 ;
     RECT  15.9 2.151 16.212 118.809 ;
     RECT  18.6 2.151 18.912 118.809 ;
     RECT  21.3 2.151 21.612 118.809 ;
     RECT  24 2.151 24.312 118.809 ;
     RECT  26.7 2.151 27.012 118.809 ;
     RECT  29.4 2.151 29.712 118.809 ;
     RECT  32.1 2.151 32.412 118.809 ;
     RECT  2.4 118.809 2.52 118.823 ;
     RECT  5.1 116.771 5.928 118.823 ;
     RECT  7.8 118.809 7.92 118.823 ;
     RECT  10.5 118.809 10.62 118.823 ;
     RECT  13.2 118.809 13.32 118.823 ;
     RECT  15.9 118.809 16.02 118.823 ;
     RECT  18.6 118.809 18.72 118.823 ;
     RECT  21.3 118.809 21.42 118.823 ;
     RECT  24 118.809 24.12 118.823 ;
     RECT  26.7 118.809 26.82 118.823 ;
     RECT  29.4 118.809 29.52 118.823 ;
     RECT  32.1 118.809 32.22 118.823 ;
     RECT  5.904 118.823 5.928 120.851 ;
     RECT  5.412 8.485 6.528 8.869 ;
     RECT  6.552 8.485 7.8 9.731 ;
     RECT  5.736 9.731 6.12 10.693 ;
     RECT  3.72 13.045 5.1 15.733 ;
     RECT  6.12 13.045 7.44 16.213 ;
     RECT  4.008 15.733 5.1 17.605 ;
     RECT  4.104 17.605 5.1 18.995 ;
     RECT  6.312 23.317 7.8 23.701 ;
     RECT  6.312 23.701 7.344 24.563 ;
     RECT  6.216 24.563 7.344 25.621 ;
     RECT  8.112 25.235 8.232 26.629 ;
     RECT  6.36 25.621 7.344 29.219 ;
     RECT  3.48 26.197 4.464 27.301 ;
     RECT  3.624 27.971 5.1 28.547 ;
     RECT  4.512 28.547 5.1 29.413 ;
     RECT  5.976 29.219 7.344 30.325 ;
     RECT  6.552 30.851 7.8 31.861 ;
     RECT  6.552 31.861 7.68 32.341 ;
     RECT  2.712 33.013 3.936 34.355 ;
     RECT  2.712 34.355 4.128 36.709 ;
     RECT  5.688 35.939 7.104 36.997 ;
     RECT  3.432 36.755 4.416 38.389 ;
     RECT  2.712 38.435 3.936 42.803 ;
     RECT  2.712 44.437 4.224 45.731 ;
     RECT  7.44 45.587 7.8 46.885 ;
     RECT  5.592 46.885 6.912 47.845 ;
     RECT  5.88 47.845 6.912 48.467 ;
     RECT  2.712 48.421 4.128 50.771 ;
     RECT  5.88 50.725 7.056 53.267 ;
     RECT  2.712 50.771 4.656 52.021 ;
     RECT  2.712 52.021 4.032 54.131 ;
     RECT  5.592 53.267 7.056 53.555 ;
     RECT  2.712 58.117 3.984 59.267 ;
     RECT  6.024 58.691 7.488 59.987 ;
     RECT  6.648 61.573 7.8 62.195 ;
     RECT  7.488 62.195 7.8 62.629 ;
     RECT  6.168 63.781 7.488 65.509 ;
     RECT  2.712 64.451 3.384 65.509 ;
     RECT  4.992 64.451 5.1 65.509 ;
     RECT  2.712 65.509 3.936 66.181 ;
     RECT  3.96 65.509 5.1 66.227 ;
     RECT  5.928 65.651 7.104 67.717 ;
     RECT  2.712 66.181 3.744 67.331 ;
     RECT  3.768 66.227 5.1 66.613 ;
     RECT  3.768 66.613 4.8 67.187 ;
     RECT  3.768 67.187 4.896 67.331 ;
     RECT  6.072 67.717 7.104 68.341 ;
     RECT  3.384 68.917 4.896 69.301 ;
     RECT  3.384 69.301 4.704 69.587 ;
     RECT  2.712 69.587 4.704 70.549 ;
     RECT  2.712 70.549 4.128 74.053 ;
     RECT  6.072 70.835 7.68 72.325 ;
     RECT  6.168 72.325 7.68 73.477 ;
     RECT  6.552 73.477 7.68 74.291 ;
     RECT  2.712 74.053 3.936 75.347 ;
     RECT  6.552 74.291 7.8 77.269 ;
     RECT  2.712 75.347 4.8 75.637 ;
     RECT  3.432 75.637 4.8 77.173 ;
     RECT  2.712 77.555 4.032 80.917 ;
     RECT  4.056 78.131 5.1 79.189 ;
     RECT  6.024 78.131 7.8 79.189 ;
     RECT  8.112 80.387 8.328 81.349 ;
     RECT  4.056 80.819 5.1 81.877 ;
     RECT  2.712 80.917 3.792 83.459 ;
     RECT  2.712 83.459 3.936 87.251 ;
     RECT  6.744 84.325 7.8 85.283 ;
     RECT  6.312 85.283 7.8 86.675 ;
     RECT  2.712 87.251 4.176 88.837 ;
     RECT  2.712 88.837 3.696 93.779 ;
     RECT  3.72 89.987 4.848 93.779 ;
     RECT  5.928 90.565 7.2 92.005 ;
     RECT  6.072 92.005 7.2 92.387 ;
     RECT  4.56 93.779 4.848 93.877 ;
     RECT  5.928 94.597 7.248 95.125 ;
     RECT  8.112 96.995 8.232 98.005 ;
     RECT  3.624 97.763 4.848 99.203 ;
     RECT  2.712 99.203 4.848 100.213 ;
     RECT  2.712 100.213 4.56 100.645 ;
     RECT  2.712 100.645 3.696 106.165 ;
     RECT  3.72 101.891 5.1 103.717 ;
     RECT  6.36 102.659 7.68 104.819 ;
     RECT  6.168 104.819 7.68 104.821 ;
     RECT  6.168 104.821 7.152 106.067 ;
     RECT  3.72 105.107 5.1 107.125 ;
     RECT  5.928 106.067 7.152 107.413 ;
     RECT  5.928 107.413 7.104 108.899 ;
     RECT  2.712 107.747 3.936 111.779 ;
     RECT  3.96 108.323 4.992 109.381 ;
     RECT  2.712 111.779 4.512 112.837 ;
     RECT  6.264 112.931 7.68 113.459 ;
     RECT  2.712 113.459 5.1 114.421 ;
     RECT  5.928 113.459 7.68 114.517 ;
     RECT  2.712 114.421 4.224 116.435 ;
     RECT  6.264 114.517 7.68 115.187 ;
  END
END dsfd_hstnh_690
END LIBRARY
